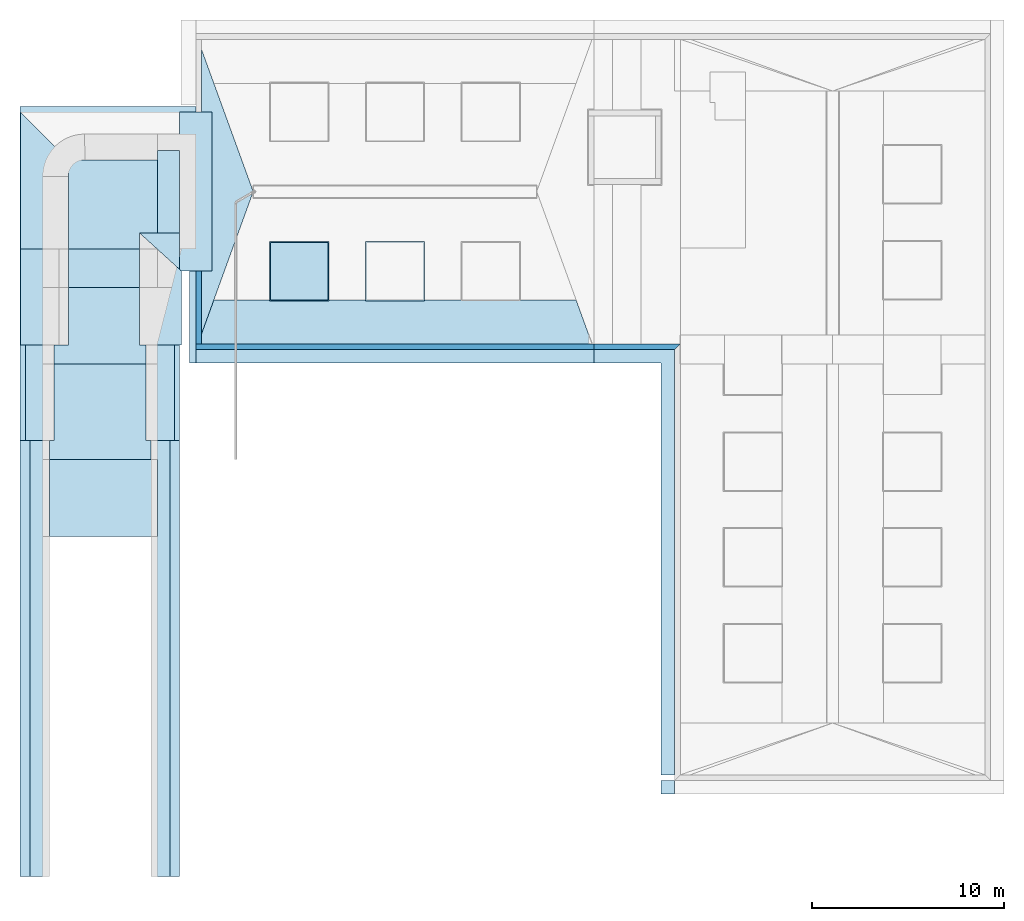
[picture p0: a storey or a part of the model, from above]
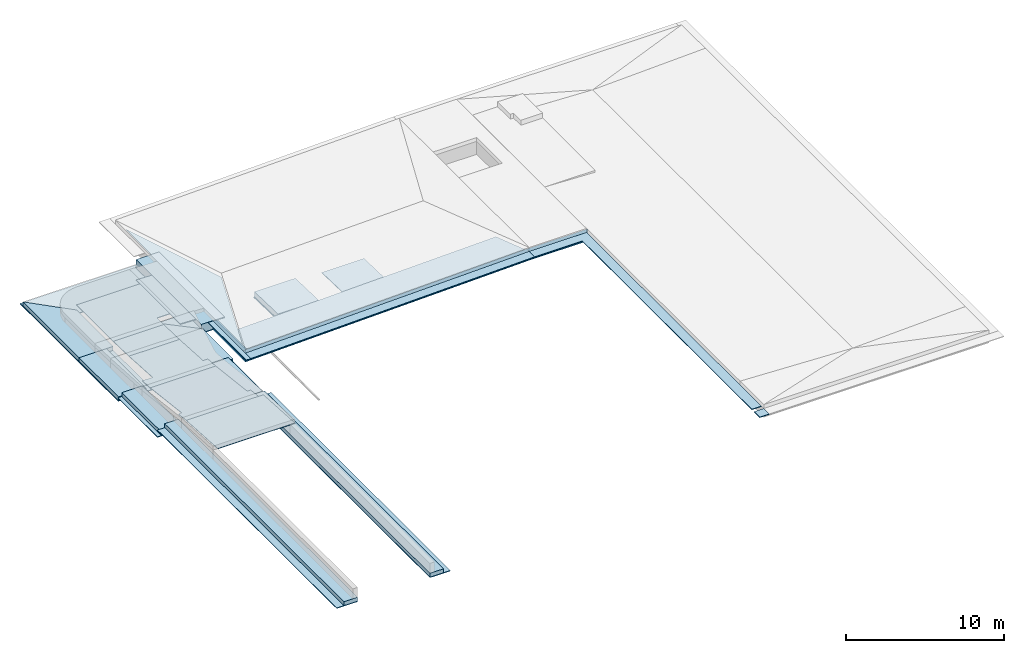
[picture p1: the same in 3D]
Properties of the parts of a building model (IFC4), part 1 of 8

# File
Description: ViewDefinition [, SurfaceGeometryAddOnView], ExchangeRequirement [Architecture], Option [Elements to export: Visible elements (on all stories)], Option [Partial Structure Display: Entire Model], Option [IFC Domain: All], Option [Structural Function: All Elements], Option [Convert Grid elements: On], Option [Convert IFC Annotations and Archicad 2D elements: Off], Option [Convert 2D symbols of Doors and Windows: Off], Option [Export geometries that Participates in Collision Detection only: Off], Option [Split complex elements: On], Option [IFC Model position: Project Origin only], Option [Curtain Wall export mode: Single Element], Option [Railing export mode: Single Element], Option [Stair export mode: Single Element], Option [Properties To Export: Current Scheme properties only], Option [Space containment: On], Option [IFC Domain For Space Containment: All], Option [Geometry to type objects: Off], Option [Element Properties: Visible Only], Option [Building Material Properties: On], Option [Element Parameters: Off], Option [Component Parameters: Off], Option [IFC Base Quantities: Off], Option [Door Window Parameters: Off], Option [IFC Space boundaries: Off], Option [Archicad Zone Categories as IFC Space classification data: Off], Option [Element Classifications: On]
File name: C:\Users\Fabienne\Desktop\Architektur Gebäudemodell__2026-02-03.ifc
Time: 2026-02-03T13:43:27
Author: Architect
Organization: Building Designer Office
Written by: DDS_IFC v3.0
Made in: Graphisoft - Archicad - 28.3.0
Authorization: The authorising person

# IfcSite, Gelände
RefLatitude: 47, 3, 30, 600000; RefLongitude: 8, 18, 39, 700000; RefElevation: 0 mm

# IfcBuildingStorey (7)
In: Gebäude
Name | Elevation (mm)
Fundation | -6000
UG | -3900
1.OG | 2900
EG | 0
2.OG | 5800
Attika | 8700
Dachaufsicht | 11600

# IfcBeam: Dachrand Typ 2 172 x 269 (3)
In: 2.OG
Classification: Träger Massivholz (BIM Base by Evolut); Material: Stahl (2), Vollholzwerkstoff
05_Bauablauf - Bau-Nr.: In Abklärung; Bauablauf Etappe: In Abklärung; Bauablauf Verbauungsort: In Abklärung; Bauablauf Start Ausführung: In Abklärung; Bauablauf Ende Ausführung: In Abklärung
03_Bausystem - Tragende Funktion: In Abklärung; Feuerwiderstand: In Abklärung; Umbau-Status: Neubau; Mehrschichtiger Aufbau: Stahl; Vollholzwerkstoff; Stahl
01_Leistungen und Kosten - Gebäude: In Abklärung; Elementpreis - CHF: 0; BKP: 214 - Montagebau in Holz; eBKP-H_Nr: C04; eBKP-H_Beschrieb: Deckenkonstrutkion, Dachkonstruktion
02_Mengen - Breite - m: 0.172423; Höhe - m: 0.269077; Kote Unterkante: 6.3; Kote Oberkante: 6.569
00_Datenstruktur - BIM Base Version: 4.0.0; Kundenergänzungen Version: v01; CAD Werkzeug Typ: Träger; Klassifizierung: Träger Massivholz; Klassifizierung Level 0: Träger; Modellierungsrichtlinien: https://evolutbaugmbh.sharepoint.com/:b:/s/External/EciBgBMJMZlDgYCafV5wNokBvCJq9PUJAyVGz7O3vsjVrg?e=aLjLN9; Übersicht BIM Base: https://evolutbaugmbh.sharepoint.com/:b:/s/External/EfS4mJ9nZQpOhASXp0n2kW4B0K7N-vHKx-_6Crp5CxEFeg?e=Qu0M5d; Verbesserungsvorschläge BIM Base: https://forms.office.com/e/pcFhFfi5DW; Anleitung Mengen: https://evolutbaugmbh.sharepoint.com/:b:/s/External/ETgyOLO3JxJEqg9rbaRMLVEBHuWIRtkoMiJN1fISDr-3lw?e=E0LTiQ; Anleitung Eigenschaften: https://evolutbaugmbh.sharepoint.com/:b:/s/External/EQedjNXQkc1Btaftc01yAPUBtND9QzXFSH3-7sie6PGFww?e=wP4uf3; Release Notes: https://evolutbaugmbh.sharepoint.com/:b:/s/External/Eb41lwlDI71MhUVvor2V2mUBSaI-0tQK5U9oJAWxpCINuw?e=NtK3j6
Bekleidung - Bekleidung Gipserarbeiten: In Abklärung; Bekleidung Malerarbeiten: In Abklärung; Bekleidung Putz: In Abklärung; Bekleidung Farbe: RAL / NCS
Name | Länge brutto - m = Länge netto - m | Volumen netto - m3
2 x Unterzug-028 | 3.8 | 0.16075
Unterzug-028 | 12.508 | 0.534861

# IfcBeam: Dreischichtplatte DSP 27 x 406, Unterzug-027
In: Dachaufsicht
Classification: Träger Massivholz (BIM Base by Evolut); Material: Dreischichtplatte DSP
01_Leistungen und Kosten - Gebäude: In Abklärung; Elementpreis - CHF: 0; BKP: 214 - Montagebau in Holz; eBKP-H_Nr: C04; eBKP-H_Beschrieb: Deckenkonstrutkion, Dachkonstruktion
05_Bauablauf - Bau-Nr.: In Abklärung; Bauablauf Etappe: In Abklärung; Bauablauf Verbauungsort: In Abklärung; Bauablauf Start Ausführung: In Abklärung; Bauablauf Ende Ausführung: In Abklärung
Bekleidung - Bekleidung Gipserarbeiten: In Abklärung; Bekleidung Malerarbeiten: In Abklärung; Bekleidung Putz: In Abklärung; Bekleidung Farbe: RAL / NCS
03_Bausystem - Tragende Funktion: In Abklärung; Feuerwiderstand: In Abklärung; Umbau-Status: Neubau; Mehrschichtiger Aufbau: Dreischichtplatte DSP
02_Mengen - Breite - m: 0.027; Höhe - m: 0.406; Länge brutto - m: 7.021; Länge netto - m: 7.021; Volumen netto - m3: 0.0769643; Kote Unterkante: 11.844; Kote Oberkante: 12.25
00_Datenstruktur - BIM Base Version: 4.0.0; Kundenergänzungen Version: v01; CAD Werkzeug Typ: Träger; Klassifizierung: Träger Massivholz; Klassifizierung Level 0: Träger; Modellierungsrichtlinien: https://evolutbaugmbh.sharepoint.com/:b:/s/External/EciBgBMJMZlDgYCafV5wNokBvCJq9PUJAyVGz7O3vsjVrg?e=aLjLN9; Übersicht BIM Base: https://evolutbaugmbh.sharepoint.com/:b:/s/External/EfS4mJ9nZQpOhASXp0n2kW4B0K7N-vHKx-_6Crp5CxEFeg?e=Qu0M5d; Verbesserungsvorschläge BIM Base: https://forms.office.com/e/pcFhFfi5DW; Anleitung Mengen: https://evolutbaugmbh.sharepoint.com/:b:/s/External/ETgyOLO3JxJEqg9rbaRMLVEBHuWIRtkoMiJN1fISDr-3lw?e=E0LTiQ; Anleitung Eigenschaften: https://evolutbaugmbh.sharepoint.com/:b:/s/External/EQedjNXQkc1Btaftc01yAPUBtND9QzXFSH3-7sie6PGFww?e=wP4uf3; Release Notes: https://evolutbaugmbh.sharepoint.com/:b:/s/External/Eb41lwlDI71MhUVvor2V2mUBSaI-0tQK5U9oJAWxpCINuw?e=NtK3j6

# IfcBeam: Massivholz 200 x 200 (25)
Classification: Träger Massivholz (BIM Base by Evolut); Material: Massivholz
01_Leistungen und Kosten - Gebäude: In Abklärung; Elementpreis - CHF: 0; BKP: 214 - Montagebau in Holz; eBKP-H_Nr: C04; eBKP-H_Beschrieb: Deckenkonstrutkion, Dachkonstruktion
05_Bauablauf - Bau-Nr.: In Abklärung; Bauablauf Etappe: In Abklärung; Bauablauf Verbauungsort: In Abklärung; Bauablauf Start Ausführung: In Abklärung; Bauablauf Ende Ausführung: In Abklärung
03_Bausystem - Tragende Funktion: In Abklärung; Feuerwiderstand: In Abklärung; Umbau-Status: Neubau; Mehrschichtiger Aufbau: Massivholz
Bekleidung - Bekleidung Gipserarbeiten: In Abklärung; Bekleidung Malerarbeiten: In Abklärung; Bekleidung Putz: In Abklärung; Bekleidung Farbe: RAL / NCS
00_Datenstruktur - BIM Base Version: 4.0.0; Kundenergänzungen Version: v01; CAD Werkzeug Typ: Träger; Klassifizierung: Träger Massivholz; Klassifizierung Level 0: Träger; Modellierungsrichtlinien: https://evolutbaugmbh.sharepoint.com/:b:/s/External/EciBgBMJMZlDgYCafV5wNokBvCJq9PUJAyVGz7O3vsjVrg?e=aLjLN9; Übersicht BIM Base: https://evolutbaugmbh.sharepoint.com/:b:/s/External/EfS4mJ9nZQpOhASXp0n2kW4B0K7N-vHKx-_6Crp5CxEFeg?e=Qu0M5d; Verbesserungsvorschläge BIM Base: https://forms.office.com/e/pcFhFfi5DW; Anleitung Mengen: https://evolutbaugmbh.sharepoint.com/:b:/s/External/ETgyOLO3JxJEqg9rbaRMLVEBHuWIRtkoMiJN1fISDr-3lw?e=E0LTiQ; Anleitung Eigenschaften: https://evolutbaugmbh.sharepoint.com/:b:/s/External/EQedjNXQkc1Btaftc01yAPUBtND9QzXFSH3-7sie6PGFww?e=wP4uf3; Release Notes: https://evolutbaugmbh.sharepoint.com/:b:/s/External/Eb41lwlDI71MhUVvor2V2mUBSaI-0tQK5U9oJAWxpCINuw?e=NtK3j6
02_Mengen - Breite - m: 0.2; Höhe - m: 0.2
Name | In | Länge brutto - m | Länge netto - m | Volumen netto - m3 | Kote Unterkante | Kote Oberkante
5 x Unterzug-027 | EG | 3.6 | 3.6 | 0.144 | 3.02 | 3.22
2 x Unterzug-027 | EG | 4 | 4 | 0.152 | 3.02 | 3.22
2 x Unterzug-027 | EG | 12.908 | 12.908 | 0.50832 | 3.02 | 3.22
2 x Unterzug-027 | 2.OG | 4 | 4 | 0.152 | 8.82 | 9.02
5 x Unterzug-027 | 2.OG | 3.6 | 3.6 | 0.144 | 8.82 | 9.02
2 x Unterzug-027 | 2.OG | 12.8974 | 12.8974 | 0.507897 | 8.82 | 9.02
Unterzug-027 | Attika | 19.2132 | 18.4132 | 0.736528 | 11.35 | 11.55
4 x Unterzug-027 | Attika | 5.11796 | 5.11796 | 0.204719 | 11.35 | 11.55
Unterzug-027 | Attika | 5.21 | 5.21 | 0.2044 | 11.35 | 11.55
Unterzug-027 | Attika | 19.4632 | 19.4632 | 0.757254 | 11.35 | 11.55

# IfcBeam: Massivholz 200 x 400 (5)
Classification: Träger Massivholz (BIM Base by Evolut); Material: Massivholz
05_Bauablauf - Bau-Nr.: In Abklärung; Bauablauf Etappe: In Abklärung; Bauablauf Verbauungsort: In Abklärung; Bauablauf Start Ausführung: In Abklärung; Bauablauf Ende Ausführung: In Abklärung
01_Leistungen und Kosten - Gebäude: In Abklärung; Elementpreis - CHF: 0; BKP: 214 - Montagebau in Holz; eBKP-H_Nr: C04; eBKP-H_Beschrieb: Deckenkonstrutkion, Dachkonstruktion
03_Bausystem - Tragende Funktion: In Abklärung; Feuerwiderstand: In Abklärung; Umbau-Status: Neubau; Mehrschichtiger Aufbau: Massivholz
Bekleidung - Bekleidung Gipserarbeiten: In Abklärung; Bekleidung Malerarbeiten: In Abklärung; Bekleidung Putz: In Abklärung; Bekleidung Farbe: RAL / NCS
00_Datenstruktur - BIM Base Version: 4.0.0; Kundenergänzungen Version: v01; CAD Werkzeug Typ: Träger; Klassifizierung: Träger Massivholz; Klassifizierung Level 0: Träger; Modellierungsrichtlinien: https://evolutbaugmbh.sharepoint.com/:b:/s/External/EciBgBMJMZlDgYCafV5wNokBvCJq9PUJAyVGz7O3vsjVrg?e=aLjLN9; Übersicht BIM Base: https://evolutbaugmbh.sharepoint.com/:b:/s/External/EfS4mJ9nZQpOhASXp0n2kW4B0K7N-vHKx-_6Crp5CxEFeg?e=Qu0M5d; Verbesserungsvorschläge BIM Base: https://forms.office.com/e/pcFhFfi5DW; Anleitung Mengen: https://evolutbaugmbh.sharepoint.com/:b:/s/External/ETgyOLO3JxJEqg9rbaRMLVEBHuWIRtkoMiJN1fISDr-3lw?e=E0LTiQ; Anleitung Eigenschaften: https://evolutbaugmbh.sharepoint.com/:b:/s/External/EQedjNXQkc1Btaftc01yAPUBtND9QzXFSH3-7sie6PGFww?e=wP4uf3; Release Notes: https://evolutbaugmbh.sharepoint.com/:b:/s/External/Eb41lwlDI71MhUVvor2V2mUBSaI-0tQK5U9oJAWxpCINuw?e=NtK3j6
02_Mengen - Breite - m: 0.2; Höhe - m: 0.4
Name | In | Länge brutto - m | Länge netto - m | Volumen netto - m3 | Kote Unterkante | Kote Oberkante
Unterzug-027 | Attika | 8.99307 | 8.99307 | 0.719446 | 11.444 | 11.844
Unterzug-027 | Dachaufsicht | 4.2 | 4.2 | 0.336 | 13.107 | 13.507
Unterzug-027 | Dachaufsicht | 7.93205 | 8.07763 | 0.62173 | 12.893 | 13.293
Unterzug-027 | Dachaufsicht | 4.2 | 4.2 | 0.327483 | 13.107 | 13.507
Unterzug-027 | Dachaufsicht | 7.93205 | 8.07763 | 0.630247 | 12.893 | 13.293

# IfcBeam: Massivholz 200 x 800, Unterzug-027
In: Dachaufsicht
Classification: Träger Massivholz (BIM Base by Evolut); Material: Massivholz
01_Leistungen und Kosten - Gebäude: In Abklärung; Elementpreis - CHF: 0; BKP: 214 - Montagebau in Holz; eBKP-H_Nr: C04; eBKP-H_Beschrieb: Deckenkonstrutkion, Dachkonstruktion
03_Bausystem - Tragende Funktion: In Abklärung; Feuerwiderstand: In Abklärung; Umbau-Status: Neubau; Mehrschichtiger Aufbau: Massivholz
Bekleidung - Bekleidung Gipserarbeiten: In Abklärung; Bekleidung Malerarbeiten: In Abklärung; Bekleidung Putz: In Abklärung; Bekleidung Farbe: RAL / NCS
05_Bauablauf - Bau-Nr.: In Abklärung; Bauablauf Etappe: In Abklärung; Bauablauf Verbauungsort: In Abklärung; Bauablauf Start Ausführung: In Abklärung; Bauablauf Ende Ausführung: In Abklärung
00_Datenstruktur - BIM Base Version: 4.0.0; Kundenergänzungen Version: v01; CAD Werkzeug Typ: Träger; Klassifizierung: Träger Massivholz; Klassifizierung Level 0: Träger; Modellierungsrichtlinien: https://evolutbaugmbh.sharepoint.com/:b:/s/External/EciBgBMJMZlDgYCafV5wNokBvCJq9PUJAyVGz7O3vsjVrg?e=aLjLN9; Übersicht BIM Base: https://evolutbaugmbh.sharepoint.com/:b:/s/External/EfS4mJ9nZQpOhASXp0n2kW4B0K7N-vHKx-_6Crp5CxEFeg?e=Qu0M5d; Verbesserungsvorschläge BIM Base: https://forms.office.com/e/pcFhFfi5DW; Anleitung Mengen: https://evolutbaugmbh.sharepoint.com/:b:/s/External/ETgyOLO3JxJEqg9rbaRMLVEBHuWIRtkoMiJN1fISDr-3lw?e=E0LTiQ; Anleitung Eigenschaften: https://evolutbaugmbh.sharepoint.com/:b:/s/External/EQedjNXQkc1Btaftc01yAPUBtND9QzXFSH3-7sie6PGFww?e=wP4uf3; Release Notes: https://evolutbaugmbh.sharepoint.com/:b:/s/External/Eb41lwlDI71MhUVvor2V2mUBSaI-0tQK5U9oJAWxpCINuw?e=NtK3j6
02_Mengen - Breite - m: 0.2; Höhe - m: 0.8; Länge brutto - m: 33.1; Länge netto - m: 33.264; Volumen netto - m3: 5.30744; Kote Unterkante: 15.004; Kote Oberkante: 15.804

# IfcBeam: Massivholz 21 x 150 (4)
In: Dachaufsicht
Classification: Träger Massivholz (BIM Base by Evolut); Material: Massivholz
05_Bauablauf - Bau-Nr.: In Abklärung; Bauablauf Etappe: In Abklärung; Bauablauf Verbauungsort: In Abklärung; Bauablauf Start Ausführung: In Abklärung; Bauablauf Ende Ausführung: In Abklärung
01_Leistungen und Kosten - Gebäude: In Abklärung; Elementpreis - CHF: 0; BKP: 214 - Montagebau in Holz; eBKP-H_Nr: C04; eBKP-H_Beschrieb: Deckenkonstrutkion, Dachkonstruktion
Bekleidung - Bekleidung Gipserarbeiten: In Abklärung; Bekleidung Malerarbeiten: In Abklärung; Bekleidung Putz: In Abklärung; Bekleidung Farbe: RAL / NCS
03_Bausystem - Tragende Funktion: In Abklärung; Feuerwiderstand: In Abklärung; Umbau-Status: Neubau; Mehrschichtiger Aufbau: Massivholz
02_Mengen - Breite - m: 0.021; Höhe - m: 0.15
00_Datenstruktur - BIM Base Version: 4.0.0; Kundenergänzungen Version: v01; CAD Werkzeug Typ: Träger; Klassifizierung: Träger Massivholz; Klassifizierung Level 0: Träger; Modellierungsrichtlinien: https://evolutbaugmbh.sharepoint.com/:b:/s/External/EciBgBMJMZlDgYCafV5wNokBvCJq9PUJAyVGz7O3vsjVrg?e=aLjLN9; Übersicht BIM Base: https://evolutbaugmbh.sharepoint.com/:b:/s/External/EfS4mJ9nZQpOhASXp0n2kW4B0K7N-vHKx-_6Crp5CxEFeg?e=Qu0M5d; Verbesserungsvorschläge BIM Base: https://forms.office.com/e/pcFhFfi5DW; Anleitung Mengen: https://evolutbaugmbh.sharepoint.com/:b:/s/External/ETgyOLO3JxJEqg9rbaRMLVEBHuWIRtkoMiJN1fISDr-3lw?e=E0LTiQ; Anleitung Eigenschaften: https://evolutbaugmbh.sharepoint.com/:b:/s/External/EQedjNXQkc1Btaftc01yAPUBtND9QzXFSH3-7sie6PGFww?e=wP4uf3; Release Notes: https://evolutbaugmbh.sharepoint.com/:b:/s/External/Eb41lwlDI71MhUVvor2V2mUBSaI-0tQK5U9oJAWxpCINuw?e=NtK3j6
Name | Länge brutto - m | Länge netto - m | Volumen netto - m3 | Kote Unterkante | Kote Oberkante
3 x Unterzug-027 | 8.68662 | 8.74122 | 0.0273629 | 13.06 | 13.21
Unterzug-027 | 6.07832 | 6.13292 | 0.0191467 | 13.952 | 14.102

# IfcBeam: Massivholz 21 x 160 (3)
In: Dachaufsicht
Classification: Träger Massivholz (BIM Base by Evolut); Material: Massivholz
01_Leistungen und Kosten - Gebäude: In Abklärung; Elementpreis - CHF: 0; BKP: 214 - Montagebau in Holz; eBKP-H_Nr: C04; eBKP-H_Beschrieb: Deckenkonstrutkion, Dachkonstruktion
05_Bauablauf - Bau-Nr.: In Abklärung; Bauablauf Etappe: In Abklärung; Bauablauf Verbauungsort: In Abklärung; Bauablauf Start Ausführung: In Abklärung; Bauablauf Ende Ausführung: In Abklärung
03_Bausystem - Tragende Funktion: In Abklärung; Feuerwiderstand: In Abklärung; Umbau-Status: Neubau; Mehrschichtiger Aufbau: Massivholz
02_Mengen - Breite - m: 0.021; Höhe - m: 0.16
Bekleidung - Bekleidung Gipserarbeiten: In Abklärung; Bekleidung Malerarbeiten: In Abklärung; Bekleidung Putz: In Abklärung; Bekleidung Farbe: RAL / NCS
00_Datenstruktur - BIM Base Version: 4.0.0; Kundenergänzungen Version: v01; CAD Werkzeug Typ: Träger; Klassifizierung: Träger Massivholz; Klassifizierung Level 0: Träger; Modellierungsrichtlinien: https://evolutbaugmbh.sharepoint.com/:b:/s/External/EciBgBMJMZlDgYCafV5wNokBvCJq9PUJAyVGz7O3vsjVrg?e=aLjLN9; Übersicht BIM Base: https://evolutbaugmbh.sharepoint.com/:b:/s/External/EfS4mJ9nZQpOhASXp0n2kW4B0K7N-vHKx-_6Crp5CxEFeg?e=Qu0M5d; Verbesserungsvorschläge BIM Base: https://forms.office.com/e/pcFhFfi5DW; Anleitung Mengen: https://evolutbaugmbh.sharepoint.com/:b:/s/External/ETgyOLO3JxJEqg9rbaRMLVEBHuWIRtkoMiJN1fISDr-3lw?e=E0LTiQ; Anleitung Eigenschaften: https://evolutbaugmbh.sharepoint.com/:b:/s/External/EQedjNXQkc1Btaftc01yAPUBtND9QzXFSH3-7sie6PGFww?e=wP4uf3; Release Notes: https://evolutbaugmbh.sharepoint.com/:b:/s/External/Eb41lwlDI71MhUVvor2V2mUBSaI-0tQK5U9oJAWxpCINuw?e=NtK3j6
Name | Länge brutto - m = Länge netto - m | Volumen netto - m3 | Kote Unterkante | Kote Oberkante
Unterzug-027 | 9.911 | 0.033301 | 13.952 | 14.112
Unterzug-027 | 24.271 | 0.0815506 | 13.06 | 13.22
Unterzug-027 | 34.182 | 0.114852 | 13.06 | 13.22

# IfcBuildingElementPart (1315)
Name | In | Material
Lattenrost vertikal | UG | Lattenrost vertikal
2 x Gipskartonplatte GKP | UG | Gipskartonplatte GKP
17 x Anstrich Innen | UG | Anstrich Innen
70 x Beton bewehrt | UG | Beton bewehrt
3 x Kalkzementputz Aussen | UG | Kalkzementputz Aussen
16 x Sichtbeton | UG | Sichtbeton
7 x Lattenrost vertikal | EG | Lattenrost vertikal
6 x Lattenrost horizontal | EG | Lattenrost horizontal
6 x Falzschalung vertikal | EG | Falzschalung vertikal
7 x Dämmung Aussen | EG | Dämmung Aussen
7 x Zementputz Aussen | EG | Zementputz Aussen
4 x Verputz Innen | EG | Verputz Innen
12 x Gipsfaserplatte GFP | EG | Gipsfaserplatte GFP
9 x Ständer Konstruktion gedämmt | EG | Ständer Konstruktion gedämmt
8 x Grobspanplatte-OSB | EG | Grobspanplatte-OSB
9 x Sichtbeton | EG | Sichtbeton
14 x Beton bewehrt | EG | Beton bewehrt
7 x Kalkzementputz Aussen | EG | Kalkzementputz Aussen
Anstrich Innen | EG | Anstrich Innen
4 x Dämmung Innen | EG | Dämmung Innen
6 x Gipskartonplatte GKP | EG | Gipskartonplatte GKP
2 x Balken Konstruktion ungedämmt | EG | Balken Konstruktion ungedämmt
2 x Balken Konstruktion gedämmt | EG | Balken Konstruktion gedämmt
2 x Dreischichtplatte DSP | EG | Dreischichtplatte DSP
5 x  | EG
2 x Bodenbelag | EG | Bodenbelag
2 x Unterlagsboden | EG | Unterlagsboden
5 x Sperrschicht | EG | Sperrschicht
Stahl | EG | Stahl
17 x Massivholz | EG | Massivholz
3 x Keramik | EG | Keramik
3 x Grünfläche | EG | Grünfläche
8 x Falzschalung vertikal | 1.OG | Falzschalung vertikal
8 x Lattenrost horizontal | 1.OG | Lattenrost horizontal
24 x Ständer Konstruktion gedämmt | 1.OG | Ständer Konstruktion gedämmt
2 x Dreischichtplatte DSP | 1.OG | Dreischichtplatte DSP
8 x Lattenrost vertikal | 1.OG | Lattenrost vertikal
20 x Dämmung Innen | 1.OG | Dämmung Innen
22 x Gipsfaserplatte GFP | 1.OG | Gipsfaserplatte GFP
24 x Gipskartonplatte GKP | 1.OG | Gipskartonplatte GKP
50 x Kalkzementputz Aussen | 1.OG | Kalkzementputz Aussen
21 x MW, Backstein | 1.OG | MW, Backstein
7 x Dämmung Aussen | 1.OG | Dämmung Aussen
7 x Zementputz Aussen | 1.OG | Zementputz Aussen
9 x Verputz Innen | 1.OG | Verputz Innen
13 x Grobspanplatte-OSB | 1.OG | Grobspanplatte-OSB
9 x Sichtbeton | 1.OG | Sichtbeton
16 x Beton bewehrt | 1.OG | Beton bewehrt
2 x Balken Konstruktion ungedämmt | 1.OG | Balken Konstruktion ungedämmt
2 x Balken Konstruktion gedämmt | 1.OG | Balken Konstruktion gedämmt
2 x Keramik | 1.OG | Keramik
4 x Unterlagsboden | 1.OG | Unterlagsboden
4 x Trittschalldämmung | 1.OG | Trittschalldämmung
 | 1.OG
2 x Bodenbelag | 1.OG | Bodenbelag
Stahl | 1.OG | Stahl
17 x Massivholz | 1.OG | Massivholz
6 x Falzschalung vertikal | 2.OG | Falzschalung vertikal
6 x Lattenrost horizontal | 2.OG | Lattenrost horizontal
7 x Lattenrost vertikal | 2.OG | Lattenrost vertikal
22 x Ständer Konstruktion gedämmt | 2.OG | Ständer Konstruktion gedämmt
30 x Gipskartonplatte GKP | 2.OG | Gipskartonplatte GKP
51 x Kalkzementputz Aussen | 2.OG | Kalkzementputz Aussen
9 x Grobspanplatte-OSB | 2.OG | Grobspanplatte-OSB
2 x Balken Konstruktion ungedämmt | 2.OG | Balken Konstruktion ungedämmt
2 x Balken Konstruktion gedämmt | 2.OG | Balken Konstruktion gedämmt
7 x Zementputz Aussen | 2.OG | Zementputz Aussen
8 x Dämmung Aussen | 2.OG | Dämmung Aussen
21 x MW, Backstein | 2.OG | MW, Backstein
2 x Dreischichtplatte DSP | 2.OG | Dreischichtplatte DSP
14 x Gipsfaserplatte GFP | 2.OG | Gipsfaserplatte GFP
21 x Dämmung Innen | 2.OG | Dämmung Innen
5 x Verputz Innen | 2.OG | Verputz Innen
9 x Sichtbeton | 2.OG | Sichtbeton
15 x Beton bewehrt | 2.OG | Beton bewehrt
33 x Keramik | 2.OG | Keramik
5 x Unterlagsboden | 2.OG | Unterlagsboden
5 x Trittschalldämmung | 2.OG | Trittschalldämmung
 | 2.OG
4 x Bodenbelag | 2.OG | Bodenbelag
Stahl | 2.OG | Stahl
17 x Massivholz | 2.OG | Massivholz
Sperrschicht | 2.OG | Sperrschicht
3 x Dachbegrünung extensiv | Attika | Dachbegrünung extensiv
3 x Abdichtung Bitumen | Attika | Abdichtung Bitumen
3 x Aufdachdämmung | Attika | Aufdachdämmung
3 x Dampf- / Luftdichtigkeitsschicht | Attika | Dampf- / Luftdichtigkeitsschicht
7 x Falzschalung vertikal | Attika | Falzschalung vertikal
7 x Lattenrost horizontal | Attika | Lattenrost horizontal
13 x Lattenrost vertikal | Attika | Lattenrost vertikal
3 x Gefällsdämmung | Attika | Gefällsdämmung
10 x Verputz Innen | Attika | Verputz Innen
20 x Gipsfaserplatte GFP | Attika | Gipsfaserplatte GFP
21 x Ständer Konstruktion gedämmt | Attika | Ständer Konstruktion gedämmt
20 x Grobspanplatte-OSB | Attika | Grobspanplatte-OSB
13 x Dämmung Innen | Attika | Dämmung Innen
16 x MW, Backstein | Attika | MW, Backstein
36 x Kalkzementputz Aussen | Attika | Kalkzementputz Aussen
12 x Beton bewehrt | Attika | Beton bewehrt
7 x Sichtbeton | Attika | Sichtbeton
16 x Gipskartonplatte GKP | Attika | Gipskartonplatte GKP
5 x Bodenbelag | Attika | Bodenbelag
6 x Unterlagsboden | Attika | Unterlagsboden
5 x Trittschalldämmung | Attika | Trittschalldämmung
8 x Zementputz Aussen | Attika | Zementputz Aussen
10 x Dämmung Aussen | Attika | Dämmung Aussen
2 x Balken Konstruktion ungedämmt | Attika | Balken Konstruktion ungedämmt
2 x Balken Konstruktion gedämmt | Attika | Balken Konstruktion gedämmt
6 x Falzschalung horizontal | Attika | Falzschalung horizontal
Sperrschicht | Attika | Sperrschicht
2 x  | Attika
17 x Vollholzwerkstoff | Attika | Vollholzwerkstoff
23 x Stahl | Attika | Stahl
2 x Keramik | Attika | Keramik
14 x Grobspanplatte-OSB | Dachaufsicht | Grobspanplatte-OSB
15 x Ständer Konstruktion gedämmt | Dachaufsicht | Ständer Konstruktion gedämmt
28 x Gipsfaserplatte GFP | Dachaufsicht | Gipsfaserplatte GFP
14 x Verputz Innen | Dachaufsicht | Verputz Innen
13 x Falzschalung vertikal | Dachaufsicht | Falzschalung vertikal
17 x Lattenrost vertikal | Dachaufsicht | Lattenrost vertikal
13 x Lattenrost horizontal | Dachaufsicht | Lattenrost horizontal
4 x Dachziegel grau | Dachaufsicht | Dachziegel grau
4 x Aufdachdämmung | Dachaufsicht | Aufdachdämmung
6 x Dreischichtplatte-DSP | Dachaufsicht | Dreischichtplatte-DSP
6 x Balken Konstruktion gedämmt | Dachaufsicht | Balken Konstruktion gedämmt
12 x Gipskartonplatte GKP | Dachaufsicht | Gipskartonplatte GKP
6 x Kalkzementputz Aussen | Dachaufsicht | Kalkzementputz Aussen
Bodenbelag | Dachaufsicht | Bodenbelag
Unterlagsboden | Dachaufsicht | Unterlagsboden
Trittschalldämmung | Dachaufsicht | Trittschalldämmung
Dämmung Innen | Dachaufsicht | Dämmung Innen
2 x Dreischichtplatte DSP | Dachaufsicht | Dreischichtplatte DSP
8 x Stahl | Dachaufsicht | Stahl

# IfcBuildingElementProxy: Evolut_Referenzpunkt_BIM Base_v4.0.7 (3)
In: EG
Description: D9.1; Classification: Referenzpunkt (BIM Base by Evolut)
01_Leistungen und Kosten - Gebäude: In Abklärung
Georeferenzierung - X Koordinaten - m: In Abklärung; Y Koordinaten - m: In Abklärung; Z Koordinaten - m: In Abklärung
00_Datenstruktur - BIM Base Version: 4.0.0; Kundenergänzungen Version: v01; CAD Werkzeug Typ: Objekt; Klassifizierung: Referenzpunkt; Klassifizierung Level 0: Referenzpunkt; Modellierungsrichtlinien: https://evolutbaugmbh.sharepoint.com/:b:/s/External/EciBgBMJMZlDgYCafV5wNokBvCJq9PUJAyVGz7O3vsjVrg?e=aLjLN9; Übersicht BIM Base: https://evolutbaugmbh.sharepoint.com/:b:/s/External/EfS4mJ9nZQpOhASXp0n2kW4B0K7N-vHKx-_6Crp5CxEFeg?e=Qu0M5d; Verbesserungsvorschläge BIM Base: https://forms.office.com/e/pcFhFfi5DW; Anleitung Mengen: https://evolutbaugmbh.sharepoint.com/:b:/s/External/ETgyOLO3JxJEqg9rbaRMLVEBHuWIRtkoMiJN1fISDr-3lw?e=E0LTiQ; Anleitung Eigenschaften: https://evolutbaugmbh.sharepoint.com/:b:/s/External/EQedjNXQkc1Btaftc01yAPUBtND9QzXFSH3-7sie6PGFww?e=wP4uf3; Release Notes: https://evolutbaugmbh.sharepoint.com/:b:/s/External/Eb41lwlDI71MhUVvor2V2mUBSaI-0tQK5U9oJAWxpCINuw?e=NtK3j6
02_Mengen - Breite - m: 1; Höhe - m: 2
Name | Kote Unterkante | Kote Oberkante
Kontrollpunkt_3613 | 0 | 2
Einfügepunkt_32084866 | -1.035 | 0.965
Kontrollpunkt_4497 | 0 | 2

# IfcBuildingElementProxy: Rechteckige Türöffnung 27, Türzarge Typ 01
In: Attika
Classification: Öffnung (BIM Base by Evolut)
01_Leistungen und Kosten - Gebäude: In Abklärung; Elementpreis - CHF: 0; eBKP-H_Nr: C05.01; eBKP-H_Beschrieb: Durchbruch, Schlitz zu Konstruktion
03_Bausystem - Umbau-Status: Neubau
02_Mengen - Breite - m: 1.1; Breite Lichtmass - m: 1.1; Höhe Lichtmass - m: 2.1; Fläche Lichtmass - m2: 2.31; Höhe Mauerlicht - m: 2.1; Breite Mauerlicht - m: 1.1; Fläche Mauerlicht - m2: 2.31; Delta Höhe unten - m: 0; Delta Hohe oben - m: 0; Wandstärke - m: 0.318; Kote Unterkante: 9.32; Kote Oberkante: 11.42
00_Datenstruktur - BIM Base Version: 4.0.0; Kundenergänzungen Version: v01; CAD Werkzeug Typ: Tür; Klassifizierung: Öffnung; Klassifizierung Level 0: Öffnung; Modellierungsrichtlinien: https://evolutbaugmbh.sharepoint.com/:b:/s/External/EciBgBMJMZlDgYCafV5wNokBvCJq9PUJAyVGz7O3vsjVrg?e=aLjLN9; Übersicht BIM Base: https://evolutbaugmbh.sharepoint.com/:b:/s/External/EfS4mJ9nZQpOhASXp0n2kW4B0K7N-vHKx-_6Crp5CxEFeg?e=Qu0M5d; Verbesserungsvorschläge BIM Base: https://forms.office.com/e/pcFhFfi5DW; Anleitung Mengen: https://evolutbaugmbh.sharepoint.com/:b:/s/External/ETgyOLO3JxJEqg9rbaRMLVEBHuWIRtkoMiJN1fISDr-3lw?e=E0LTiQ; Anleitung Eigenschaften: https://evolutbaugmbh.sharepoint.com/:b:/s/External/EQedjNXQkc1Btaftc01yAPUBtND9QzXFSH3-7sie6PGFww?e=wP4uf3; Release Notes: https://evolutbaugmbh.sharepoint.com/:b:/s/External/Eb41lwlDI71MhUVvor2V2mUBSaI-0tQK5U9oJAWxpCINuw?e=NtK3j6

# IfcColumn: Massivholz 200 x 200 (10)
Classification: Aussenstütze Massivholz (BIM Base by Evolut); Material: Massivholz
01_Leistungen und Kosten - Gebäude: In Abklärung; Elementpreis - CHF: 0; BKP: 214 - Montagebau in Holz; eBKP-H_Nr: C03.01; eBKP-H_Beschrieb: Aussenstütze
05_Bauablauf - Bau-Nr.: In Abklärung; Bauablauf Etappe: In Abklärung; Bauablauf Verbauungsort: In Abklärung; Bauablauf Start Ausführung: In Abklärung; Bauablauf Ende Ausführung: In Abklärung
03_Bausystem - Tragende Funktion: In Abklärung; Feuerwiderstand: In Abklärung; Umbau-Status: Neubau; Mehrschichtiger Aufbau: Massivholz
Bekleidung - Bekleidung Malerarbeiten: In Abklärung
Holzbau - Holzbau Durchstanzung: In Abklärung
02_Mengen - Breite - m: 0.2; Höhe - m: 0.2
00_Datenstruktur - BIM Base Version: 4.0.0; Kundenergänzungen Version: v01; CAD Werkzeug Typ: Stütze; Klassifizierung: Aussenstütze Massivholz; Klassifizierung Level 0: Stütze; Modellierungsrichtlinien: https://evolutbaugmbh.sharepoint.com/:b:/s/External/EciBgBMJMZlDgYCafV5wNokBvCJq9PUJAyVGz7O3vsjVrg?e=aLjLN9; Übersicht BIM Base: https://evolutbaugmbh.sharepoint.com/:b:/s/External/EfS4mJ9nZQpOhASXp0n2kW4B0K7N-vHKx-_6Crp5CxEFeg?e=Qu0M5d; Verbesserungsvorschläge BIM Base: https://forms.office.com/e/pcFhFfi5DW; Anleitung Mengen: https://evolutbaugmbh.sharepoint.com/:b:/s/External/ETgyOLO3JxJEqg9rbaRMLVEBHuWIRtkoMiJN1fISDr-3lw?e=E0LTiQ; Anleitung Eigenschaften: https://evolutbaugmbh.sharepoint.com/:b:/s/External/EQedjNXQkc1Btaftc01yAPUBtND9QzXFSH3-7sie6PGFww?e=wP4uf3; Release Notes: https://evolutbaugmbh.sharepoint.com/:b:/s/External/Eb41lwlDI71MhUVvor2V2mUBSaI-0tQK5U9oJAWxpCINuw?e=NtK3j6
Name | In | Länge brutto - m | Länge netto - m | Volumen netto - m3 | Kote Unterkante | Kote Oberkante
4 x Stütze-015 | EG | 2.52 | 3.70524 | 0.141866 | 0.5 | 3.02
2 x Stütze-015 | EG | 2.52 | 2.52 | 0.1008 | 0.5 | 3.02
2 x Stütze-015 | 2.OG | 2.52 | 2.52 | 0.1008 | 6.3 | 8.82
2 x Stütze-015 | Attika | 3.90655 | 3.90402 | 0.156161 | 9.2 | 13.107

# IfcColumn: Verschiedene Strukturen - 3 Segmente - 300 x 300 x 2150 (30+2090+30) (5)
In: Attika
Classification: Aussenstütze Stahl (BIM Base by Evolut); Material: Stahl (3)
01_Leistungen und Kosten - Gebäude: In Abklärung; Elementpreis - CHF: 0; BKP: 213 - Montagebau in Stahl; eBKP-H_Nr: C03.01; eBKP-H_Beschrieb: Aussenstütze
05_Bauablauf - Bau-Nr.: In Abklärung; Bauablauf Etappe: In Abklärung; Bauablauf Verbauungsort: In Abklärung; Bauablauf Start Ausführung: In Abklärung; Bauablauf Ende Ausführung: In Abklärung
Bekleidung - Bekleidung Malerarbeiten: In Abklärung
03_Bausystem - Tragende Funktion: In Abklärung; Feuerwiderstand: In Abklärung; Umbau-Status: Neubau; Mehrschichtiger Aufbau: Stahl; Stahl; Stahl
02_Mengen - Breite - m: 0.3; Höhe - m: 0.3; Länge brutto - m: 2.15; Länge netto - m: 2.15; Volumen netto - m3: 0.0130996; Kote Unterkante: 9.2; Kote Oberkante: 11.35
00_Datenstruktur - BIM Base Version: 4.0.0; Kundenergänzungen Version: v01; CAD Werkzeug Typ: Stütze; Klassifizierung: Aussenstütze Stahl; Klassifizierung Level 0: Stütze; Modellierungsrichtlinien: https://evolutbaugmbh.sharepoint.com/:b:/s/External/EciBgBMJMZlDgYCafV5wNokBvCJq9PUJAyVGz7O3vsjVrg?e=aLjLN9; Übersicht BIM Base: https://evolutbaugmbh.sharepoint.com/:b:/s/External/EfS4mJ9nZQpOhASXp0n2kW4B0K7N-vHKx-_6Crp5CxEFeg?e=Qu0M5d; Verbesserungsvorschläge BIM Base: https://forms.office.com/e/pcFhFfi5DW; Anleitung Mengen: https://evolutbaugmbh.sharepoint.com/:b:/s/External/ETgyOLO3JxJEqg9rbaRMLVEBHuWIRtkoMiJN1fISDr-3lw?e=E0LTiQ; Anleitung Eigenschaften: https://evolutbaugmbh.sharepoint.com/:b:/s/External/EQedjNXQkc1Btaftc01yAPUBtND9QzXFSH3-7sie6PGFww?e=wP4uf3; Release Notes: https://evolutbaugmbh.sharepoint.com/:b:/s/External/Eb41lwlDI71MhUVvor2V2mUBSaI-0tQK5U9oJAWxpCINuw?e=NtK3j6

# IfcColumn: Verschiedene Strukturen - 3 Segmente - 300 x 300 x 2650 (30+2590+30) (7)
Classification: Aussenstütze Stahl (BIM Base by Evolut); Material: Stahl (3)
01_Leistungen und Kosten - Gebäude: In Abklärung; Elementpreis - CHF: 0; BKP: 213 - Montagebau in Stahl; eBKP-H_Nr: C03.01; eBKP-H_Beschrieb: Aussenstütze
05_Bauablauf - Bau-Nr.: In Abklärung; Bauablauf Etappe: In Abklärung; Bauablauf Verbauungsort: In Abklärung; Bauablauf Start Ausführung: In Abklärung; Bauablauf Ende Ausführung: In Abklärung
03_Bausystem - Tragende Funktion: In Abklärung; Feuerwiderstand: In Abklärung; Umbau-Status: Neubau; Mehrschichtiger Aufbau: Stahl; Stahl; Stahl
Bekleidung - Bekleidung Malerarbeiten: In Abklärung
02_Mengen - Breite - m: 0.3; Höhe - m: 0.3; Länge brutto - m: 2.65; Länge netto - m: 2.65; Volumen netto - m3: 0.0149416
00_Datenstruktur - BIM Base Version: 4.0.0; Kundenergänzungen Version: v01; CAD Werkzeug Typ: Stütze; Klassifizierung: Aussenstütze Stahl; Klassifizierung Level 0: Stütze; Modellierungsrichtlinien: https://evolutbaugmbh.sharepoint.com/:b:/s/External/EciBgBMJMZlDgYCafV5wNokBvCJq9PUJAyVGz7O3vsjVrg?e=aLjLN9; Übersicht BIM Base: https://evolutbaugmbh.sharepoint.com/:b:/s/External/EfS4mJ9nZQpOhASXp0n2kW4B0K7N-vHKx-_6Crp5CxEFeg?e=Qu0M5d; Verbesserungsvorschläge BIM Base: https://forms.office.com/e/pcFhFfi5DW; Anleitung Mengen: https://evolutbaugmbh.sharepoint.com/:b:/s/External/ETgyOLO3JxJEqg9rbaRMLVEBHuWIRtkoMiJN1fISDr-3lw?e=E0LTiQ; Anleitung Eigenschaften: https://evolutbaugmbh.sharepoint.com/:b:/s/External/EQedjNXQkc1Btaftc01yAPUBtND9QzXFSH3-7sie6PGFww?e=wP4uf3; Release Notes: https://evolutbaugmbh.sharepoint.com/:b:/s/External/Eb41lwlDI71MhUVvor2V2mUBSaI-0tQK5U9oJAWxpCINuw?e=NtK3j6
Name | In | Kote Unterkante | Kote Oberkante
4 x Stütze-015 | 1.OG | 2.9 | 5.55
3 x Stütze-015 | 2.OG | 5.8 | 8.45

# IfcColumn: Verschiedene Strukturen - 3 Segmente - 300 x 300 x 2680 (30+2620+30) (4)
Classification: Aussenstütze Stahl (BIM Base by Evolut); Material: Stahl (3)
01_Leistungen und Kosten - Gebäude: In Abklärung; Elementpreis - CHF: 0; BKP: 213 - Montagebau in Stahl; eBKP-H_Nr: C03.01; eBKP-H_Beschrieb: Aussenstütze
05_Bauablauf - Bau-Nr.: In Abklärung; Bauablauf Etappe: In Abklärung; Bauablauf Verbauungsort: In Abklärung; Bauablauf Start Ausführung: In Abklärung; Bauablauf Ende Ausführung: In Abklärung
Bekleidung - Bekleidung Malerarbeiten: In Abklärung
00_Datenstruktur - BIM Base Version: 4.0.0; Kundenergänzungen Version: v01; CAD Werkzeug Typ: Stütze; Klassifizierung: Aussenstütze Stahl; Klassifizierung Level 0: Stütze; Modellierungsrichtlinien: https://evolutbaugmbh.sharepoint.com/:b:/s/External/EciBgBMJMZlDgYCafV5wNokBvCJq9PUJAyVGz7O3vsjVrg?e=aLjLN9; Übersicht BIM Base: https://evolutbaugmbh.sharepoint.com/:b:/s/External/EfS4mJ9nZQpOhASXp0n2kW4B0K7N-vHKx-_6Crp5CxEFeg?e=Qu0M5d; Verbesserungsvorschläge BIM Base: https://forms.office.com/e/pcFhFfi5DW; Anleitung Mengen: https://evolutbaugmbh.sharepoint.com/:b:/s/External/ETgyOLO3JxJEqg9rbaRMLVEBHuWIRtkoMiJN1fISDr-3lw?e=E0LTiQ; Anleitung Eigenschaften: https://evolutbaugmbh.sharepoint.com/:b:/s/External/EQedjNXQkc1Btaftc01yAPUBtND9QzXFSH3-7sie6PGFww?e=wP4uf3; Release Notes: https://evolutbaugmbh.sharepoint.com/:b:/s/External/Eb41lwlDI71MhUVvor2V2mUBSaI-0tQK5U9oJAWxpCINuw?e=NtK3j6
02_Mengen - Breite - m: 0.3; Höhe - m: 0.3; Länge brutto - m: 2.68; Länge netto - m: 2.68; Volumen netto - m3: 0.0150521
03_Bausystem - Tragende Funktion: In Abklärung; Feuerwiderstand: In Abklärung; Umbau-Status: Neubau; Mehrschichtiger Aufbau: Stahl; Stahl; Stahl
Name | In | Kote Unterkante | Kote Oberkante
2 x Stütze-015 | 1.OG | 2.87 | 5.55
2 x Stütze-015 | 2.OG | 5.77 | 8.45

# IfcColumn: Verschiedene Strukturen - 3 Segmente - 300 x 300 x 3150 (30+3090+30) (5)
In: EG
Classification: Aussenstütze Stahl (BIM Base by Evolut); Material: Stahl (3)
01_Leistungen und Kosten - Gebäude: In Abklärung; Elementpreis - CHF: 0; BKP: 213 - Montagebau in Stahl; eBKP-H_Nr: C03.01; eBKP-H_Beschrieb: Aussenstütze
05_Bauablauf - Bau-Nr.: In Abklärung; Bauablauf Etappe: In Abklärung; Bauablauf Verbauungsort: In Abklärung; Bauablauf Start Ausführung: In Abklärung; Bauablauf Ende Ausführung: In Abklärung
03_Bausystem - Tragende Funktion: In Abklärung; Feuerwiderstand: In Abklärung; Umbau-Status: Neubau; Mehrschichtiger Aufbau: Stahl; Stahl; Stahl
Bekleidung - Bekleidung Malerarbeiten: In Abklärung
02_Mengen - Breite - m: 0.3; Höhe - m: 0.3; Länge brutto - m: 3.15; Länge netto - m: 3.15; Volumen netto - m3: 0.0167836; Kote Unterkante: -0.5; Kote Oberkante: 2.65
00_Datenstruktur - BIM Base Version: 4.0.0; Kundenergänzungen Version: v01; CAD Werkzeug Typ: Stütze; Klassifizierung: Aussenstütze Stahl; Klassifizierung Level 0: Stütze; Modellierungsrichtlinien: https://evolutbaugmbh.sharepoint.com/:b:/s/External/EciBgBMJMZlDgYCafV5wNokBvCJq9PUJAyVGz7O3vsjVrg?e=aLjLN9; Übersicht BIM Base: https://evolutbaugmbh.sharepoint.com/:b:/s/External/EfS4mJ9nZQpOhASXp0n2kW4B0K7N-vHKx-_6Crp5CxEFeg?e=Qu0M5d; Verbesserungsvorschläge BIM Base: https://forms.office.com/e/pcFhFfi5DW; Anleitung Mengen: https://evolutbaugmbh.sharepoint.com/:b:/s/External/ETgyOLO3JxJEqg9rbaRMLVEBHuWIRtkoMiJN1fISDr-3lw?e=E0LTiQ; Anleitung Eigenschaften: https://evolutbaugmbh.sharepoint.com/:b:/s/External/EQedjNXQkc1Btaftc01yAPUBtND9QzXFSH3-7sie6PGFww?e=wP4uf3; Release Notes: https://evolutbaugmbh.sharepoint.com/:b:/s/External/Eb41lwlDI71MhUVvor2V2mUBSaI-0tQK5U9oJAWxpCINuw?e=NtK3j6

# IfcColumn: Verschiedene Strukturen - 3 Segmente - 300 x 300 x 3400 (30+3340+30), Stütze-015
In: EG
Classification: Aussenstütze Stahl (BIM Base by Evolut); Material: Stahl (3)
05_Bauablauf - Bau-Nr.: In Abklärung; Bauablauf Etappe: In Abklärung; Bauablauf Verbauungsort: In Abklärung; Bauablauf Start Ausführung: In Abklärung; Bauablauf Ende Ausführung: In Abklärung
03_Bausystem - Tragende Funktion: In Abklärung; Feuerwiderstand: In Abklärung; Umbau-Status: Neubau; Mehrschichtiger Aufbau: Stahl; Stahl; Stahl
Bekleidung - Bekleidung Malerarbeiten: In Abklärung
02_Mengen - Breite - m: 0.3; Höhe - m: 0.3; Länge brutto - m: 3.4; Länge netto - m: 3.4; Volumen netto - m3: 0.0177046; Kote Unterkante: -0.5; Kote Oberkante: 2.9
00_Datenstruktur - BIM Base Version: 4.0.0; Kundenergänzungen Version: v01; CAD Werkzeug Typ: Stütze; Klassifizierung: Aussenstütze Stahl; Klassifizierung Level 0: Stütze; Modellierungsrichtlinien: https://evolutbaugmbh.sharepoint.com/:b:/s/External/EciBgBMJMZlDgYCafV5wNokBvCJq9PUJAyVGz7O3vsjVrg?e=aLjLN9; Übersicht BIM Base: https://evolutbaugmbh.sharepoint.com/:b:/s/External/EfS4mJ9nZQpOhASXp0n2kW4B0K7N-vHKx-_6Crp5CxEFeg?e=Qu0M5d; Verbesserungsvorschläge BIM Base: https://forms.office.com/e/pcFhFfi5DW; Anleitung Mengen: https://evolutbaugmbh.sharepoint.com/:b:/s/External/ETgyOLO3JxJEqg9rbaRMLVEBHuWIRtkoMiJN1fISDr-3lw?e=E0LTiQ; Anleitung Eigenschaften: https://evolutbaugmbh.sharepoint.com/:b:/s/External/EQedjNXQkc1Btaftc01yAPUBtND9QzXFSH3-7sie6PGFww?e=wP4uf3; Release Notes: https://evolutbaugmbh.sharepoint.com/:b:/s/External/Eb41lwlDI71MhUVvor2V2mUBSaI-0tQK5U9oJAWxpCINuw?e=NtK3j6
01_Leistungen und Kosten - Gebäude: In Abklärung; Elementpreis - CHF: 0; BKP: 213 - Montagebau in Stahl; eBKP-H_Nr: C03.01; eBKP-H_Beschrieb: Aussenstütze

# IfcColumn: Vollholzwerkstoff 200 x 400 (2)
Classification: Innenstütze Massivholz (BIM Base by Evolut); Material: Vollholzwerkstoff
02_Mengen - Breite - m: 0.2; Höhe - m: 0.4
00_Datenstruktur - BIM Base Version: 4.0.0; Kundenergänzungen Version: v01; CAD Werkzeug Typ: Stütze; Klassifizierung: Innenstütze Massivholz; Klassifizierung Level 0: Stütze; Modellierungsrichtlinien: https://evolutbaugmbh.sharepoint.com/:b:/s/External/EciBgBMJMZlDgYCafV5wNokBvCJq9PUJAyVGz7O3vsjVrg?e=aLjLN9; Übersicht BIM Base: https://evolutbaugmbh.sharepoint.com/:b:/s/External/EfS4mJ9nZQpOhASXp0n2kW4B0K7N-vHKx-_6Crp5CxEFeg?e=Qu0M5d; Verbesserungsvorschläge BIM Base: https://forms.office.com/e/pcFhFfi5DW; Anleitung Mengen: https://evolutbaugmbh.sharepoint.com/:b:/s/External/ETgyOLO3JxJEqg9rbaRMLVEBHuWIRtkoMiJN1fISDr-3lw?e=E0LTiQ; Anleitung Eigenschaften: https://evolutbaugmbh.sharepoint.com/:b:/s/External/EQedjNXQkc1Btaftc01yAPUBtND9QzXFSH3-7sie6PGFww?e=wP4uf3; Release Notes: https://evolutbaugmbh.sharepoint.com/:b:/s/External/Eb41lwlDI71MhUVvor2V2mUBSaI-0tQK5U9oJAWxpCINuw?e=NtK3j6
03_Bausystem - Tragende Funktion: In Abklärung; Feuerwiderstand: In Abklärung; Umbau-Status: Neubau; Mehrschichtiger Aufbau: Vollholzwerkstoff
Holzbau - Holzbau Durchstanzung: In Abklärung
05_Bauablauf - Bau-Nr.: In Abklärung; Bauablauf Etappe: In Abklärung; Bauablauf Verbauungsort: In Abklärung; Bauablauf Start Ausführung: In Abklärung; Bauablauf Ende Ausführung: In Abklärung
01_Leistungen und Kosten - Gebäude: In Abklärung; Elementpreis - CHF: 0; BKP: 214 - Montagebau in Holz; eBKP-H_Nr: C03.02; eBKP-H_Beschrieb: Innenstütze
Bekleidung - Bekleidung Gipserarbeiten: In Abklärung; Bekleidung Malerarbeiten: In Abklärung; Bekleidung Putz: In Abklärung; Bekleidung Farbe: RAL / NCS
Name | In | Länge brutto - m = Länge netto - m | Volumen netto - m3 | Kote Unterkante | Kote Oberkante
Stütze-015 | Attika | 2.244 | 0.17952 | 9.2 | 11.444
Stütze-015 | Dachaufsicht | 3.34499 | 0.248501 | 11.844 | 15.189

# IfcCovering: Bodenaufbau Typ 01 150 (10)
Classification: Bodenbekleidung Unterkonstruktion (BIM Base by Evolut)
01_Leistungen und Kosten - Gebäude: In Abklärung; Elementpreis - CHF: 0; BKP: 281 - Bodenbeläge; eBKP-H_Nr: G02.01; eBKP-H_Beschrieb: Unterkonstruktion zu Bodenbelag
03_Bausystem - Feuerwiderstand: In Abklärung; Luftschall: In Abklärung; Trittschall: In Abklärung; U-Wert: In Abklärung; Umbau-Status: Neubau; Mehrschichtiger Aufbau: Bodenbelag; Unterlagsboden; Trittschalldämmung; Dämmung Innen
02_Mengen - Stärke - m: 0.15
05_Bauablauf - Bau-Nr.: In Abklärung; Bauablauf Etappe: In Abklärung; Bauablauf Verbauungsort: In Abklärung; Bauablauf Start Ausführung: In Abklärung; Bauablauf Ende Ausführung: In Abklärung
00_Datenstruktur - BIM Base Version: 4.0.0; Kundenergänzungen Version: v01; CAD Werkzeug Typ: Decke; Klassifizierung: Bodenbekleidung Unterkonstruktion; Klassifizierung Level 0: Bekleidung; Modellierungsrichtlinien: https://evolutbaugmbh.sharepoint.com/:b:/s/External/EciBgBMJMZlDgYCafV5wNokBvCJq9PUJAyVGz7O3vsjVrg?e=aLjLN9; Übersicht BIM Base: https://evolutbaugmbh.sharepoint.com/:b:/s/External/EfS4mJ9nZQpOhASXp0n2kW4B0K7N-vHKx-_6Crp5CxEFeg?e=Qu0M5d; Verbesserungsvorschläge BIM Base: https://forms.office.com/e/pcFhFfi5DW; Anleitung Mengen: https://evolutbaugmbh.sharepoint.com/:b:/s/External/ETgyOLO3JxJEqg9rbaRMLVEBHuWIRtkoMiJN1fISDr-3lw?e=E0LTiQ; Anleitung Eigenschaften: https://evolutbaugmbh.sharepoint.com/:b:/s/External/EQedjNXQkc1Btaftc01yAPUBtND9QzXFSH3-7sie6PGFww?e=wP4uf3; Release Notes: https://evolutbaugmbh.sharepoint.com/:b:/s/External/Eb41lwlDI71MhUVvor2V2mUBSaI-0tQK5U9oJAWxpCINuw?e=NtK3j6
Name | In | Fläche brutto - m2 | Fläche netto - m2 | Volumen netto - m3 | Umfang - m | Kote Unterkante | Kote Oberkante
Decke-007 | 1.OG | 437.021 | 431.699 | 64.7548 | 94.426 | 3.4 | 3.55
Decke-007 | 1.OG | 303.675 | 264.672 | 39.7008 | 103.107 | 2.9 | 3.05
Decke-007 | 2.OG | 387.276 | 383.212 | 57.4818 | 86.358 | 6.3 | 6.45
Decke-007 | 2.OG | 246.735 | 209.347 | 31.402 | 91.7254 | 5.8 | 5.95
Decke-007 | 2.OG | 56.9401 | 55.3219 | 8.29828 | 36.782 | 5.95 | 6.1
Decke-007 | Attika | 51.858 | 50.1196 | 7.51793 | 37.606 | 8.7 | 8.85
Decke-007 | Attika | 123.567 | 119.42 | 17.913 | 59.94 | 8.7 | 8.85
Decke-007 | Attika | 386.244 | 381.765 | 57.2647 | 87.264 | 9.2 | 9.35
Decke-007 | Attika | 8.0835 | 7.33855 | 1.10078 | 13.37 | 9.35 | 9.5
Decke-007 | Dachaufsicht | 124.877 | 120.816 | 18.1225 | 54.9021 | 12.1 | 12.25

# IfcCovering: Bodenaufbau Typ 02 150 (5)
Classification: Bodenbekleidung Unterkonstruktion (BIM Base by Evolut)
05_Bauablauf - Bau-Nr.: In Abklärung; Bauablauf Etappe: In Abklärung; Bauablauf Verbauungsort: In Abklärung; Bauablauf Start Ausführung: In Abklärung; Bauablauf Ende Ausführung: In Abklärung
03_Bausystem - Feuerwiderstand: In Abklärung; Luftschall: In Abklärung; Trittschall: In Abklärung; U-Wert: In Abklärung; Umbau-Status: Neubau; Mehrschichtiger Aufbau: Keramik; Unterlagsboden; Trittschalldämmung; Dämmung Innen
01_Leistungen und Kosten - Gebäude: In Abklärung; Elementpreis - CHF: 0; BKP: 281 - Bodenbeläge; eBKP-H_Nr: G02.01; eBKP-H_Beschrieb: Unterkonstruktion zu Bodenbelag
02_Mengen - Stärke - m: 0.15
00_Datenstruktur - BIM Base Version: 4.0.0; Kundenergänzungen Version: v01; CAD Werkzeug Typ: Decke; Klassifizierung: Bodenbekleidung Unterkonstruktion; Klassifizierung Level 0: Bekleidung; Modellierungsrichtlinien: https://evolutbaugmbh.sharepoint.com/:b:/s/External/EciBgBMJMZlDgYCafV5wNokBvCJq9PUJAyVGz7O3vsjVrg?e=aLjLN9; Übersicht BIM Base: https://evolutbaugmbh.sharepoint.com/:b:/s/External/EfS4mJ9nZQpOhASXp0n2kW4B0K7N-vHKx-_6Crp5CxEFeg?e=Qu0M5d; Verbesserungsvorschläge BIM Base: https://forms.office.com/e/pcFhFfi5DW; Anleitung Mengen: https://evolutbaugmbh.sharepoint.com/:b:/s/External/ETgyOLO3JxJEqg9rbaRMLVEBHuWIRtkoMiJN1fISDr-3lw?e=E0LTiQ; Anleitung Eigenschaften: https://evolutbaugmbh.sharepoint.com/:b:/s/External/EQedjNXQkc1Btaftc01yAPUBtND9QzXFSH3-7sie6PGFww?e=wP4uf3; Release Notes: https://evolutbaugmbh.sharepoint.com/:b:/s/External/Eb41lwlDI71MhUVvor2V2mUBSaI-0tQK5U9oJAWxpCINuw?e=NtK3j6
Name | In | Fläche brutto - m2 = Fläche netto - m2 | Volumen netto - m3 | Umfang - m | Kote Unterkante | Kote Oberkante
Decke-007 | 1.OG | 9.25542 | 1.38831 | 12.4485 | 2.9 | 3.05
Decke-008 | 1.OG | 12.3837 | 1.85756 | 14.1324 | 2.9 | 3.05
Decke-007 | 2.OG | 9.25542 | 1.38831 | 12.4485 | 5.8 | 5.95
Decke-007 | 2.OG | 12.3837 | 1.85756 | 14.1324 | 5.8 | 5.95
Decke-007 | Attika | 5.226 | 0.7839 | 9.82 | 8.7 | 8.85

# IfcCovering: Bodenaufbau Typ 03 - Terrasse 300, Decke-007
In: Attika
Classification: Dacheindeckung Terrasse Unterkonstruktion (BIM Base by Evolut)
01_Leistungen und Kosten - Gebäude: In Abklärung; Elementpreis - CHF: 0; BKP: 224 - Bedachungsarbeiten; eBKP-H_Nr: F01.02; eBKP-H_Beschrieb: Bedachung Flachdach
03_Bausystem - Feuerwiderstand: In Abklärung; Trittschall: In Abklärung; U-Wert: In Abklärung; Umbau-Status: Neubau; Mehrschichtiger Aufbau: Keramik; Unterlagsboden; Fehlt; Dämmung Aussen
05_Bauablauf - Bau-Nr.: In Abklärung; Bauablauf Etappe: In Abklärung; Bauablauf Verbauungsort: In Abklärung; Bauablauf Start Ausführung: In Abklärung; Bauablauf Ende Ausführung: In Abklärung
02_Mengen - Stärke - m: 0.3; Fläche brutto - m2: 131.256; Fläche netto - m2: 130.859; Volumen netto - m3: 39.2577; Umfang - m: 86.6685; Kote Unterkante: 8.7; Kote Oberkante: 9
00_Datenstruktur - BIM Base Version: 4.0.0; Kundenergänzungen Version: v01; CAD Werkzeug Typ: Decke; Klassifizierung: Dacheindeckung Terrasse Unterkonstruktion; Klassifizierung Level 0: Bekleidung; Modellierungsrichtlinien: https://evolutbaugmbh.sharepoint.com/:b:/s/External/EciBgBMJMZlDgYCafV5wNokBvCJq9PUJAyVGz7O3vsjVrg?e=aLjLN9; Übersicht BIM Base: https://evolutbaugmbh.sharepoint.com/:b:/s/External/EfS4mJ9nZQpOhASXp0n2kW4B0K7N-vHKx-_6Crp5CxEFeg?e=Qu0M5d; Verbesserungsvorschläge BIM Base: https://forms.office.com/e/pcFhFfi5DW; Anleitung Mengen: https://evolutbaugmbh.sharepoint.com/:b:/s/External/ETgyOLO3JxJEqg9rbaRMLVEBHuWIRtkoMiJN1fISDr-3lw?e=E0LTiQ; Anleitung Eigenschaften: https://evolutbaugmbh.sharepoint.com/:b:/s/External/EQedjNXQkc1Btaftc01yAPUBtND9QzXFSH3-7sie6PGFww?e=wP4uf3; Release Notes: https://evolutbaugmbh.sharepoint.com/:b:/s/External/Eb41lwlDI71MhUVvor2V2mUBSaI-0tQK5U9oJAWxpCINuw?e=NtK3j6

# IfcCovering: Bodenaufbau Typ 04 220 (2)
In: EG
Classification: Bodenbekleidung Unterkonstruktion (BIM Base by Evolut)
01_Leistungen und Kosten - Gebäude: In Abklärung; Elementpreis - CHF: 0; BKP: 281 - Bodenbeläge; eBKP-H_Nr: G02.01; eBKP-H_Beschrieb: Unterkonstruktion zu Bodenbelag
05_Bauablauf - Bau-Nr.: In Abklärung; Bauablauf Etappe: In Abklärung; Bauablauf Verbauungsort: In Abklärung; Bauablauf Start Ausführung: In Abklärung; Bauablauf Ende Ausführung: In Abklärung
03_Bausystem - Feuerwiderstand: In Abklärung; Luftschall: In Abklärung; Trittschall: In Abklärung; U-Wert: In Abklärung; Umbau-Status: Neubau; Mehrschichtiger Aufbau: Bodenbelag; Unterlagsboden; Fehlt; Fehlt; Sperrschicht
02_Mengen - Stärke - m: 0.22
00_Datenstruktur - BIM Base Version: 4.0.0; Kundenergänzungen Version: v01; CAD Werkzeug Typ: Decke; Klassifizierung: Bodenbekleidung Unterkonstruktion; Klassifizierung Level 0: Bekleidung; Modellierungsrichtlinien: https://evolutbaugmbh.sharepoint.com/:b:/s/External/EciBgBMJMZlDgYCafV5wNokBvCJq9PUJAyVGz7O3vsjVrg?e=aLjLN9; Übersicht BIM Base: https://evolutbaugmbh.sharepoint.com/:b:/s/External/EfS4mJ9nZQpOhASXp0n2kW4B0K7N-vHKx-_6Crp5CxEFeg?e=Qu0M5d; Verbesserungsvorschläge BIM Base: https://forms.office.com/e/pcFhFfi5DW; Anleitung Mengen: https://evolutbaugmbh.sharepoint.com/:b:/s/External/ETgyOLO3JxJEqg9rbaRMLVEBHuWIRtkoMiJN1fISDr-3lw?e=E0LTiQ; Anleitung Eigenschaften: https://evolutbaugmbh.sharepoint.com/:b:/s/External/EQedjNXQkc1Btaftc01yAPUBtND9QzXFSH3-7sie6PGFww?e=wP4uf3; Release Notes: https://evolutbaugmbh.sharepoint.com/:b:/s/External/Eb41lwlDI71MhUVvor2V2mUBSaI-0tQK5U9oJAWxpCINuw?e=NtK3j6
Name | Fläche brutto - m2 | Fläche netto - m2 | Volumen netto - m3 | Umfang - m | Kote Unterkante | Kote Oberkante
Decke-006 | 95.0656 | 95.0656 | 20.9144 | 50.36 | -0.6 | -0.38
Decke-006 | 389.297 | 386.495 | 85.0289 | 86.568 | 0 | 0.22

# IfcCovering: Brüstungsabdeckung 02 470 x 100 (3)
In: Dachaufsicht
Classification: Dacheindeckung Balkon (BIM Base by Evolut)
05_Bauablauf - Bau-Nr.: In Abklärung; Bauablauf Etappe: In Abklärung; Bauablauf Verbauungsort: In Abklärung; Bauablauf Start Ausführung: In Abklärung; Bauablauf Ende Ausführung: In Abklärung
03_Bausystem - Feuerwiderstand: In Abklärung; Trittschall: In Abklärung; U-Wert: In Abklärung; Umbau-Status: Neubau; Mehrschichtiger Aufbau: Stahl; Stahl
01_Leistungen und Kosten - Gebäude: In Abklärung; Elementpreis - CHF: 0; BKP: 224 - Bedachungsarbeiten; eBKP-H_Nr: F01.02; eBKP-H_Beschrieb: Bedachung Flachdach
02_Mengen - Breite - m: 0.4704; Höhe - m: 0.1; Stärke - m: 0.4704; Kote Unterkante: 12.434; Kote Oberkante: 12.534
00_Datenstruktur - BIM Base Version: 4.0.0; Kundenergänzungen Version: v01; CAD Werkzeug Typ: Träger; Klassifizierung: Dacheindeckung Balkon; Klassifizierung Level 0: Bekleidung; Modellierungsrichtlinien: https://evolutbaugmbh.sharepoint.com/:b:/s/External/EciBgBMJMZlDgYCafV5wNokBvCJq9PUJAyVGz7O3vsjVrg?e=aLjLN9; Übersicht BIM Base: https://evolutbaugmbh.sharepoint.com/:b:/s/External/EfS4mJ9nZQpOhASXp0n2kW4B0K7N-vHKx-_6Crp5CxEFeg?e=Qu0M5d; Verbesserungsvorschläge BIM Base: https://forms.office.com/e/pcFhFfi5DW; Anleitung Mengen: https://evolutbaugmbh.sharepoint.com/:b:/s/External/ETgyOLO3JxJEqg9rbaRMLVEBHuWIRtkoMiJN1fISDr-3lw?e=E0LTiQ; Anleitung Eigenschaften: https://evolutbaugmbh.sharepoint.com/:b:/s/External/EQedjNXQkc1Btaftc01yAPUBtND9QzXFSH3-7sie6PGFww?e=wP4uf3; Release Notes: https://evolutbaugmbh.sharepoint.com/:b:/s/External/Eb41lwlDI71MhUVvor2V2mUBSaI-0tQK5U9oJAWxpCINuw?e=NtK3j6
Name | Länge brutto - m | Fläche brutto - m2 | Volumen netto - m3
Unterzug-027 | 24.5077 | 11.5284 | 0.0416262
Unterzug-027 | 12.0154 | 5.65205 | 0.0197992
Unterzug-027 | 22.0787 | 10.3858 | 0.0374606

# IfcCovering: Brüstungsabdeckung 03 520 x 100, Unterzug-027
In: Dachaufsicht
Classification: Dacheindeckung Balkon (BIM Base by Evolut)
05_Bauablauf - Bau-Nr.: In Abklärung; Bauablauf Etappe: In Abklärung; Bauablauf Verbauungsort: In Abklärung; Bauablauf Start Ausführung: In Abklärung; Bauablauf Ende Ausführung: In Abklärung
03_Bausystem - Feuerwiderstand: In Abklärung; Trittschall: In Abklärung; U-Wert: In Abklärung; Umbau-Status: Neubau; Mehrschichtiger Aufbau: Stahl; Stahl
02_Mengen - Breite - m: 0.5204; Höhe - m: 0.1; Stärke - m: 0.5204; Länge brutto - m: 2.291; Fläche brutto - m2: 1.19224; Volumen netto - m3: 0.0044946; Kote Unterkante: 9.103; Kote Oberkante: 9.203
01_Leistungen und Kosten - Gebäude: In Abklärung; Elementpreis - CHF: 0; BKP: 224 - Bedachungsarbeiten; eBKP-H_Nr: F01.02; eBKP-H_Beschrieb: Bedachung Flachdach
00_Datenstruktur - BIM Base Version: 4.0.0; Kundenergänzungen Version: v01; CAD Werkzeug Typ: Träger; Klassifizierung: Dacheindeckung Balkon; Klassifizierung Level 0: Bekleidung; Modellierungsrichtlinien: https://evolutbaugmbh.sharepoint.com/:b:/s/External/EciBgBMJMZlDgYCafV5wNokBvCJq9PUJAyVGz7O3vsjVrg?e=aLjLN9; Übersicht BIM Base: https://evolutbaugmbh.sharepoint.com/:b:/s/External/EfS4mJ9nZQpOhASXp0n2kW4B0K7N-vHKx-_6Crp5CxEFeg?e=Qu0M5d; Verbesserungsvorschläge BIM Base: https://forms.office.com/e/pcFhFfi5DW; Anleitung Mengen: https://evolutbaugmbh.sharepoint.com/:b:/s/External/ETgyOLO3JxJEqg9rbaRMLVEBHuWIRtkoMiJN1fISDr-3lw?e=E0LTiQ; Anleitung Eigenschaften: https://evolutbaugmbh.sharepoint.com/:b:/s/External/EQedjNXQkc1Btaftc01yAPUBtND9QzXFSH3-7sie6PGFww?e=wP4uf3; Release Notes: https://evolutbaugmbh.sharepoint.com/:b:/s/External/Eb41lwlDI71MhUVvor2V2mUBSaI-0tQK5U9oJAWxpCINuw?e=NtK3j6

# IfcCovering: Brüstungsabdeckung 04 315 x 100 (5)
In: Attika
Classification: Dacheindeckung Balkon (BIM Base by Evolut)
01_Leistungen und Kosten - Gebäude: In Abklärung; Elementpreis - CHF: 0; BKP: 224 - Bedachungsarbeiten; eBKP-H_Nr: F01.02; eBKP-H_Beschrieb: Bedachung Flachdach
03_Bausystem - Feuerwiderstand: In Abklärung; Trittschall: In Abklärung; U-Wert: In Abklärung; Umbau-Status: Neubau; Mehrschichtiger Aufbau: Stahl; Stahl
02_Mengen - Breite - m: 0.3154; Höhe - m: 0.1; Stärke - m: 0.3154
00_Datenstruktur - BIM Base Version: 4.0.0; Kundenergänzungen Version: v01; CAD Werkzeug Typ: Träger; Klassifizierung: Dacheindeckung Balkon; Klassifizierung Level 0: Bekleidung; Modellierungsrichtlinien: https://evolutbaugmbh.sharepoint.com/:b:/s/External/EciBgBMJMZlDgYCafV5wNokBvCJq9PUJAyVGz7O3vsjVrg?e=aLjLN9; Übersicht BIM Base: https://evolutbaugmbh.sharepoint.com/:b:/s/External/EfS4mJ9nZQpOhASXp0n2kW4B0K7N-vHKx-_6Crp5CxEFeg?e=Qu0M5d; Verbesserungsvorschläge BIM Base: https://forms.office.com/e/pcFhFfi5DW; Anleitung Mengen: https://evolutbaugmbh.sharepoint.com/:b:/s/External/ETgyOLO3JxJEqg9rbaRMLVEBHuWIRtkoMiJN1fISDr-3lw?e=E0LTiQ; Anleitung Eigenschaften: https://evolutbaugmbh.sharepoint.com/:b:/s/External/EQedjNXQkc1Btaftc01yAPUBtND9QzXFSH3-7sie6PGFww?e=wP4uf3; Release Notes: https://evolutbaugmbh.sharepoint.com/:b:/s/External/Eb41lwlDI71MhUVvor2V2mUBSaI-0tQK5U9oJAWxpCINuw?e=NtK3j6
05_Bauablauf - Bau-Nr.: In Abklärung; Bauablauf Etappe: In Abklärung; Bauablauf Verbauungsort: In Abklärung; Bauablauf Start Ausführung: In Abklärung; Bauablauf Ende Ausführung: In Abklärung
Name | Länge brutto - m | Fläche brutto - m2 | Volumen netto - m3 | Kote Unterkante | Kote Oberkante
Unterzug-027 | 2.0977 | 0.661615 | 0.00250767 | 9.1 | 9.2
Unterzug-027 | 4.4908 | 1.4164 | 0.0059414 | 9.1 | 9.2
Unterzug-027 | 4.4908 | 1.4164 | 0.00594271 | 9.1 | 9.2
Unterzug-027 | 4.4908 | 1.4164 | 0.00594271 | 9.103 | 9.203
Unterzug-027 | 1.91 | 0.602414 | 0.0025829 | 9.103 | 9.203

# IfcCovering: Brüstungsabdeckung 05 405 x 100 (3)
In: Attika
Classification: Dacheindeckung Balkon (BIM Base by Evolut)
05_Bauablauf - Bau-Nr.: In Abklärung; Bauablauf Etappe: In Abklärung; Bauablauf Verbauungsort: In Abklärung; Bauablauf Start Ausführung: In Abklärung; Bauablauf Ende Ausführung: In Abklärung
03_Bausystem - Feuerwiderstand: In Abklärung; Trittschall: In Abklärung; U-Wert: In Abklärung; Umbau-Status: Neubau; Mehrschichtiger Aufbau: Stahl; Stahl
01_Leistungen und Kosten - Gebäude: In Abklärung; Elementpreis - CHF: 0; BKP: 224 - Bedachungsarbeiten; eBKP-H_Nr: F01.02; eBKP-H_Beschrieb: Bedachung Flachdach
02_Mengen - Breite - m: 0.4054; Höhe - m: 0.1; Stärke - m: 0.4054; Kote Unterkante: 9.103; Kote Oberkante: 9.203
00_Datenstruktur - BIM Base Version: 4.0.0; Kundenergänzungen Version: v01; CAD Werkzeug Typ: Träger; Klassifizierung: Dacheindeckung Balkon; Klassifizierung Level 0: Bekleidung; Modellierungsrichtlinien: https://evolutbaugmbh.sharepoint.com/:b:/s/External/EciBgBMJMZlDgYCafV5wNokBvCJq9PUJAyVGz7O3vsjVrg?e=aLjLN9; Übersicht BIM Base: https://evolutbaugmbh.sharepoint.com/:b:/s/External/EfS4mJ9nZQpOhASXp0n2kW4B0K7N-vHKx-_6Crp5CxEFeg?e=Qu0M5d; Verbesserungsvorschläge BIM Base: https://forms.office.com/e/pcFhFfi5DW; Anleitung Mengen: https://evolutbaugmbh.sharepoint.com/:b:/s/External/ETgyOLO3JxJEqg9rbaRMLVEBHuWIRtkoMiJN1fISDr-3lw?e=E0LTiQ; Anleitung Eigenschaften: https://evolutbaugmbh.sharepoint.com/:b:/s/External/EQedjNXQkc1Btaftc01yAPUBtND9QzXFSH3-7sie6PGFww?e=wP4uf3; Release Notes: https://evolutbaugmbh.sharepoint.com/:b:/s/External/Eb41lwlDI71MhUVvor2V2mUBSaI-0tQK5U9oJAWxpCINuw?e=NtK3j6
Name | Länge brutto - m | Fläche brutto - m2 | Volumen netto - m3
Unterzug-027 | 3.0077 | 1.21932 | 0.00434976
Unterzug-027 | 15.0154 | 6.08725 | 0.022656
Unterzug-027 | 3.2535 | 1.31897 | 0.00497547

# IfcCovering: Dacheindeckung Typ 01 120 (2)
Classification: Dacheindeckung Balkon Belag Holz (BIM Base by Evolut)
01_Leistungen und Kosten - Gebäude: In Abklärung; Elementpreis - CHF: 0; BKP: 224 - Bedachungsarbeiten; eBKP-H_Nr: F01.02; eBKP-H_Beschrieb: Bedachung Flachdach
03_Bausystem - Trittschall: In Abklärung; U-Wert: In Abklärung; Umbau-Status: Neubau; Mehrschichtiger Aufbau: Bodenbelag; Dämmung Aussen; Sperrschicht
05_Bauablauf - Bau-Nr.: In Abklärung; Bauablauf Etappe: In Abklärung; Bauablauf Verbauungsort: In Abklärung; Bauablauf Start Ausführung: In Abklärung; Bauablauf Ende Ausführung: In Abklärung
00_Datenstruktur - BIM Base Version: 4.0.0; Kundenergänzungen Version: v01; CAD Werkzeug Typ: Decke; Klassifizierung: Dacheindeckung Balkon Belag Holz; Klassifizierung Level 0: Bekleidung; Modellierungsrichtlinien: https://evolutbaugmbh.sharepoint.com/:b:/s/External/EciBgBMJMZlDgYCafV5wNokBvCJq9PUJAyVGz7O3vsjVrg?e=aLjLN9; Übersicht BIM Base: https://evolutbaugmbh.sharepoint.com/:b:/s/External/EfS4mJ9nZQpOhASXp0n2kW4B0K7N-vHKx-_6Crp5CxEFeg?e=Qu0M5d; Verbesserungsvorschläge BIM Base: https://forms.office.com/e/pcFhFfi5DW; Anleitung Mengen: https://evolutbaugmbh.sharepoint.com/:b:/s/External/ETgyOLO3JxJEqg9rbaRMLVEBHuWIRtkoMiJN1fISDr-3lw?e=E0LTiQ; Anleitung Eigenschaften: https://evolutbaugmbh.sharepoint.com/:b:/s/External/EQedjNXQkc1Btaftc01yAPUBtND9QzXFSH3-7sie6PGFww?e=wP4uf3; Release Notes: https://evolutbaugmbh.sharepoint.com/:b:/s/External/Eb41lwlDI71MhUVvor2V2mUBSaI-0tQK5U9oJAWxpCINuw?e=NtK3j6
02_Mengen - Stärke - m: 0.1201
Name | In | Fläche brutto - m2 | Fläche netto - m2 | Volumen netto - m3 | Umfang - m | Kote Unterkante | Kote Oberkante
Deckennr.-073 | 2.OG | 49.1657 | 49.1654 | 5.90472 | 33.7055 | 6.3 | 6.42
Deckennr.-073 | Attika | 48.7559 | 48.7558 | 5.85549 | 33.64 | 9.2 | 9.32

# IfcCovering: Dacheindeckung Typ 02 - Flachdach 502 (3)
In: Attika
Classification: Dacheindeckung Flachdach Belag extensive Begrünung (BIM Base by Evolut)
01_Leistungen und Kosten - Gebäude: In Abklärung; Elementpreis - CHF: 0; BKP: 224 - Bedachungsarbeiten; eBKP-H_Nr: F01.02; eBKP-H_Beschrieb: Bedachung Flachdach
05_Bauablauf - Bau-Nr.: In Abklärung; Bauablauf Etappe: In Abklärung; Bauablauf Verbauungsort: In Abklärung; Bauablauf Start Ausführung: In Abklärung; Bauablauf Ende Ausführung: In Abklärung
03_Bausystem - Trittschall: In Abklärung; U-Wert: In Abklärung; Umbau-Status: Neubau; Mehrschichtiger Aufbau: Dachbegrünung extensiv; Abdichtung Bitumen; Aufdachdämmung; Gefällsdämmung; Dampf- / Luftdichtigkeitsschicht
00_Datenstruktur - BIM Base Version: 4.0.0; Kundenergänzungen Version: v01; CAD Werkzeug Typ: Decke; Klassifizierung: Dacheindeckung Flachdach Belag extensive Begrünung; Klassifizierung Level 0: Bekleidung; Modellierungsrichtlinien: https://evolutbaugmbh.sharepoint.com/:b:/s/External/EciBgBMJMZlDgYCafV5wNokBvCJq9PUJAyVGz7O3vsjVrg?e=aLjLN9; Übersicht BIM Base: https://evolutbaugmbh.sharepoint.com/:b:/s/External/EfS4mJ9nZQpOhASXp0n2kW4B0K7N-vHKx-_6Crp5CxEFeg?e=Qu0M5d; Verbesserungsvorschläge BIM Base: https://forms.office.com/e/pcFhFfi5DW; Anleitung Mengen: https://evolutbaugmbh.sharepoint.com/:b:/s/External/ETgyOLO3JxJEqg9rbaRMLVEBHuWIRtkoMiJN1fISDr-3lw?e=E0LTiQ; Anleitung Eigenschaften: https://evolutbaugmbh.sharepoint.com/:b:/s/External/EQedjNXQkc1Btaftc01yAPUBtND9QzXFSH3-7sie6PGFww?e=wP4uf3; Release Notes: https://evolutbaugmbh.sharepoint.com/:b:/s/External/Eb41lwlDI71MhUVvor2V2mUBSaI-0tQK5U9oJAWxpCINuw?e=NtK3j6
02_Mengen - Stärke - m: 0.502
Name | Fläche brutto - m2 = Fläche netto - m2 | Volumen netto - m3 | Umfang - m | Kote Unterkante | Kote Oberkante
Deckennr.-073 | 167.937 | 84.3046 | 67.8407 | 11.6 | 12.102
Deckennr.-073 | 31.4745 | 15.8002 | 27.8413 | 11.6 | 12.102
Deckennr.-073 | 62.5125 | 31.3401 | 36.58 | 12.35 | 12.852

# IfcCovering: Dacheindeckung Typ 03 - Steildach 100 (4)
In: Dachaufsicht
Classification: Dacheindeckung Steildach Belag Dachziegel (BIM Base by Evolut)
05_Bauablauf - Bau-Nr.: In Abklärung; Bauablauf Etappe: In Abklärung; Bauablauf Verbauungsort: In Abklärung; Bauablauf Start Ausführung: In Abklärung; Bauablauf Ende Ausführung: In Abklärung
03_Bausystem - U-Wert: In Abklärung; Umbau-Status: Neubau; Mehrschichtiger Aufbau: Dachziegel grau; Aufdachdämmung; Lattenrost vertikal
01_Leistungen und Kosten - Gebäude: In Abklärung; Elementpreis - CHF: 0; BKP: 224 - Bedachungsarbeiten; eBKP-H_Nr: F01.03; eBKP-H_Beschrieb: Bedachung Steildach
02_Mengen - Stärke - m: 0.1
00_Datenstruktur - BIM Base Version: 4.0.0; Kundenergänzungen Version: v01; CAD Werkzeug Typ: Dach; Klassifizierung: Dacheindeckung Steildach Belag Dachziegel; Klassifizierung Level 0: Bekleidung; Modellierungsrichtlinien: https://evolutbaugmbh.sharepoint.com/:b:/s/External/EciBgBMJMZlDgYCafV5wNokBvCJq9PUJAyVGz7O3vsjVrg?e=aLjLN9; Übersicht BIM Base: https://evolutbaugmbh.sharepoint.com/:b:/s/External/EfS4mJ9nZQpOhASXp0n2kW4B0K7N-vHKx-_6Crp5CxEFeg?e=Qu0M5d; Verbesserungsvorschläge BIM Base: https://forms.office.com/e/pcFhFfi5DW; Anleitung Mengen: https://evolutbaugmbh.sharepoint.com/:b:/s/External/ETgyOLO3JxJEqg9rbaRMLVEBHuWIRtkoMiJN1fISDr-3lw?e=E0LTiQ; Anleitung Eigenschaften: https://evolutbaugmbh.sharepoint.com/:b:/s/External/EQedjNXQkc1Btaftc01yAPUBtND9QzXFSH3-7sie6PGFww?e=wP4uf3; Release Notes: https://evolutbaugmbh.sharepoint.com/:b:/s/External/Eb41lwlDI71MhUVvor2V2mUBSaI-0tQK5U9oJAWxpCINuw?e=NtK3j6
Name | Fläche brutto - m2 | Fläche netto - m2 | Volumen netto - m3 | Umfang - m | Kote Unterkante | Kote Oberkante
2 x Dach-011 | 44.4572 | 44.4572 | 4.44572 | 27.1192 | 15.153 | 15.253
Dach-011 | 296.561 | 189.165 | 23.1371 | 113.433 | 13.126 | 13.226
Dach-011 | 270.71 | 184.841 | 21.1978 | 113.433 | 13.126 | 13.226

# IfcCovering: Deckenbekleidung Typ 01 65 (3)
Classification: Deckenbekleidung Belag Gipskarton (BIM Base by Evolut)
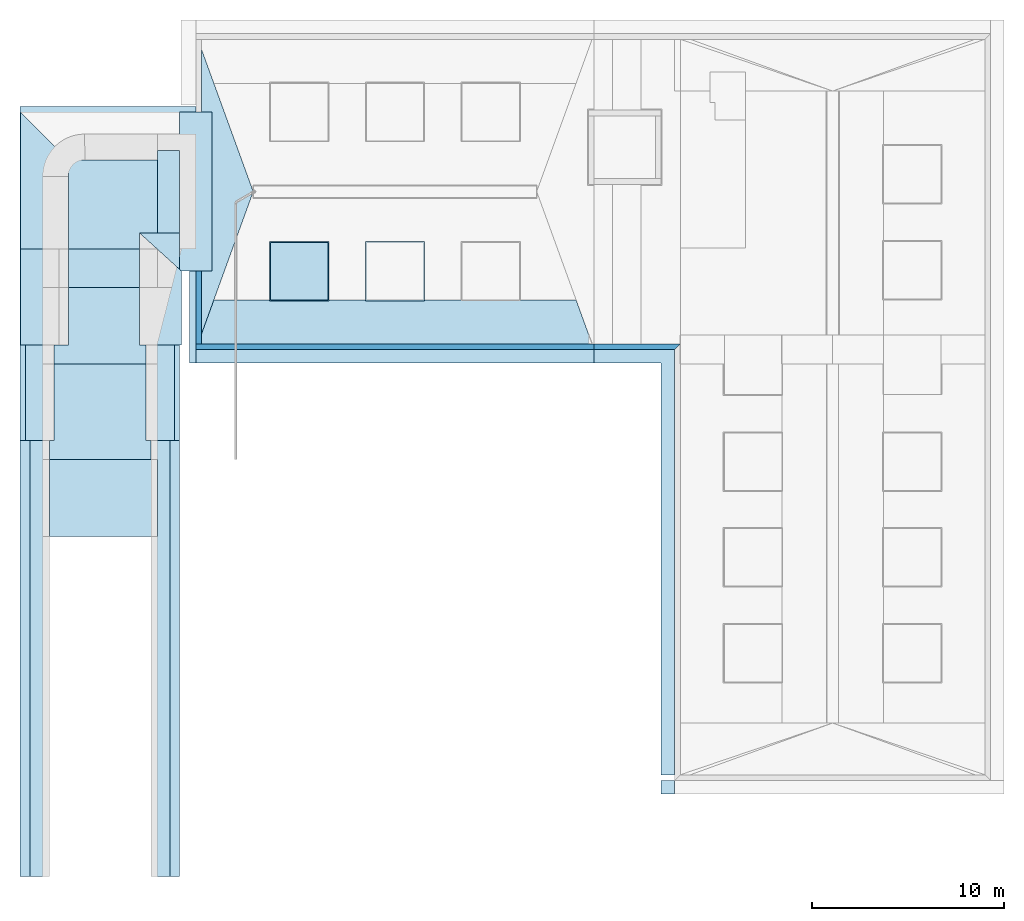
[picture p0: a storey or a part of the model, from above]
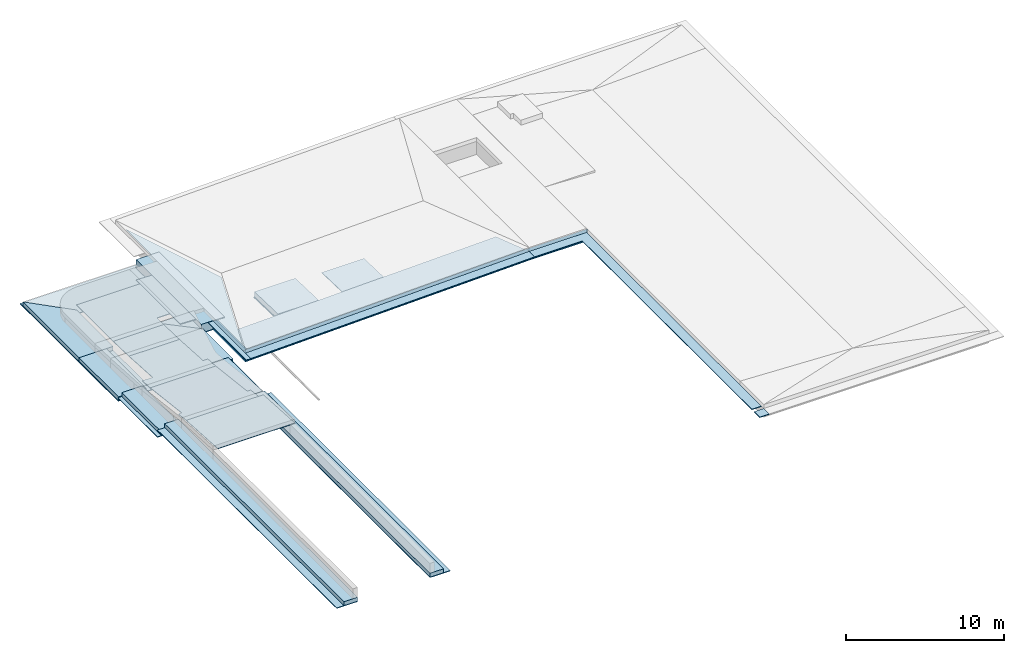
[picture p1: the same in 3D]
Properties of the parts of a building model (IFC4), part 2 of 8

# IfcCovering: Deckenbekleidung Typ 01 65 (3)
01_Leistungen und Kosten - Gebäude: In Abklärung; Elementpreis - CHF: 0; BKP: 283 - Deckenverkleidungen; eBKP-H_Nr: G04.02; eBKP-H_Beschrieb: Deckenbekleidung
05_Bauablauf - Bau-Nr.: In Abklärung; Bauablauf Etappe: In Abklärung; Bauablauf Verbauungsort: In Abklärung; Bauablauf Start Ausführung: In Abklärung; Bauablauf Ende Ausführung: In Abklärung
03_Bausystem - Feuerwiderstand: In Abklärung; Luftschall: In Abklärung; U-Wert: In Abklärung; Umbau-Status: Neubau; Mehrschichtiger Aufbau: Lattenrost vertikal; Gipskartonplatte GKP; Gipskartonplatte GKP
02_Mengen - Stärke - m: 0.065
00_Datenstruktur - BIM Base Version: 4.0.0; Kundenergänzungen Version: v01; Klassifizierung: Deckenbekleidung Belag Gipskarton; Klassifizierung Level 0: Bekleidung; Modellierungsrichtlinien: https://evolutbaugmbh.sharepoint.com/:b:/s/External/EciBgBMJMZlDgYCafV5wNokBvCJq9PUJAyVGz7O3vsjVrg?e=aLjLN9; Übersicht BIM Base: https://evolutbaugmbh.sharepoint.com/:b:/s/External/EfS4mJ9nZQpOhASXp0n2kW4B0K7N-vHKx-_6Crp5CxEFeg?e=Qu0M5d; Verbesserungsvorschläge BIM Base: https://forms.office.com/e/pcFhFfi5DW; Anleitung Mengen: https://evolutbaugmbh.sharepoint.com/:b:/s/External/ETgyOLO3JxJEqg9rbaRMLVEBHuWIRtkoMiJN1fISDr-3lw?e=E0LTiQ; Anleitung Eigenschaften: https://evolutbaugmbh.sharepoint.com/:b:/s/External/EQedjNXQkc1Btaftc01yAPUBtND9QzXFSH3-7sie6PGFww?e=wP4uf3; Release Notes: https://evolutbaugmbh.sharepoint.com/:b:/s/External/Eb41lwlDI71MhUVvor2V2mUBSaI-0tQK5U9oJAWxpCINuw?e=NtK3j6
Name | In | Fläche brutto - m2 | Fläche netto - m2 | Volumen netto - m3 | Umfang - m | Kote Unterkante | Kote Oberkante | CAD Werkzeug Typ
Dach-011 | UG | 29.7123 | 29.7123 | 1.9313 | 23.703 | -0.692 | -0.627 | Dach
Deckennr.-073 | EG | 50.328 | 50.328 | 3.27132 | 35.16 | 2.585 | 2.65 | Decke
Deckennr.-073 | 2.OG | 363.646 | 356.758 | 23.1522 | 86.538 | 8.879 | 8.944 | Decke

# IfcCovering: Dämmung Aussen 80 x 250 (2)
In: Dachaufsicht
Classification: Dämmung Dach (BIM Base by Evolut); Material: Dämmung Aussen
01_Leistungen und Kosten - Gebäude: In Abklärung; Elementpreis - CHF: 0
05_Bauablauf - Bau-Nr.: In Abklärung; Bauablauf Etappe: In Abklärung; Bauablauf Verbauungsort: In Abklärung; Bauablauf Start Ausführung: In Abklärung; Bauablauf Ende Ausführung: In Abklärung
03_Bausystem - Umbau-Status: Neubau; Mehrschichtiger Aufbau: Dämmung Aussen
00_Datenstruktur - BIM Base Version: 4.0.0; Kundenergänzungen Version: v01; CAD Werkzeug Typ: Stütze; Klassifizierung: Dämmung Dach; Klassifizierung Level 0: Baukomponente; Modellierungsrichtlinien: https://evolutbaugmbh.sharepoint.com/:b:/s/External/EciBgBMJMZlDgYCafV5wNokBvCJq9PUJAyVGz7O3vsjVrg?e=aLjLN9; Übersicht BIM Base: https://evolutbaugmbh.sharepoint.com/:b:/s/External/EfS4mJ9nZQpOhASXp0n2kW4B0K7N-vHKx-_6Crp5CxEFeg?e=Qu0M5d; Verbesserungsvorschläge BIM Base: https://forms.office.com/e/pcFhFfi5DW; Anleitung Mengen: https://evolutbaugmbh.sharepoint.com/:b:/s/External/ETgyOLO3JxJEqg9rbaRMLVEBHuWIRtkoMiJN1fISDr-3lw?e=E0LTiQ; Anleitung Eigenschaften: https://evolutbaugmbh.sharepoint.com/:b:/s/External/EQedjNXQkc1Btaftc01yAPUBtND9QzXFSH3-7sie6PGFww?e=wP4uf3; Release Notes: https://evolutbaugmbh.sharepoint.com/:b:/s/External/Eb41lwlDI71MhUVvor2V2mUBSaI-0tQK5U9oJAWxpCINuw?e=NtK3j6
02_Mengen - Breite - m: 0.08; Höhe - m: 0.25; Stärke - m: 0.08; Länge brutto - m: 0.931; Fläche brutto - m2: 0.23275; Volumen netto - m3: 0.01862; Kote Unterkante: 11.6; Kote Oberkante: 12.531

# IfcCovering: Dämmung Innen 40 (4)
In: Attika
Classification: Dämmung Wand (BIM Base by Evolut); Material: Dämmung Innen
01_Leistungen und Kosten - Gebäude: In Abklärung; Elementpreis - CHF: 0
05_Bauablauf - Bau-Nr.: In Abklärung; Bauablauf Etappe: In Abklärung; Bauablauf Verbauungsort: In Abklärung; Bauablauf Start Ausführung: In Abklärung; Bauablauf Ende Ausführung: In Abklärung
02_Mengen - Stärke - m: 0.04; Kote Oberkante: 12.35
03_Bausystem - Umbau-Status: Neubau; Mehrschichtiger Aufbau: Dämmung Innen
00_Datenstruktur - BIM Base Version: 4.0.0; Kundenergänzungen Version: v01; CAD Werkzeug Typ: Wand; Klassifizierung: Dämmung Wand; Klassifizierung Level 0: Baukomponente; Modellierungsrichtlinien: https://evolutbaugmbh.sharepoint.com/:b:/s/External/EciBgBMJMZlDgYCafV5wNokBvCJq9PUJAyVGz7O3vsjVrg?e=aLjLN9; Übersicht BIM Base: https://evolutbaugmbh.sharepoint.com/:b:/s/External/EfS4mJ9nZQpOhASXp0n2kW4B0K7N-vHKx-_6Crp5CxEFeg?e=Qu0M5d; Verbesserungsvorschläge BIM Base: https://forms.office.com/e/pcFhFfi5DW; Anleitung Mengen: https://evolutbaugmbh.sharepoint.com/:b:/s/External/ETgyOLO3JxJEqg9rbaRMLVEBHuWIRtkoMiJN1fISDr-3lw?e=E0LTiQ; Anleitung Eigenschaften: https://evolutbaugmbh.sharepoint.com/:b:/s/External/EQedjNXQkc1Btaftc01yAPUBtND9QzXFSH3-7sie6PGFww?e=wP4uf3; Release Notes: https://evolutbaugmbh.sharepoint.com/:b:/s/External/Eb41lwlDI71MhUVvor2V2mUBSaI-0tQK5U9oJAWxpCINuw?e=NtK3j6
Name | Höhe - m | Länge brutto - m | Fläche brutto - m2 | Fläche netto - m2 | Volumen netto - m3 | Kote Unterkante
Wand-014 | 3.15 | 2.549 | 8.02935 | 7.5852 | 0.303408 | 9.2
Wand-015 | 3.15 | 8.33 | 26.2395 | 26.2335 | 1.04934 | 9.2
Wand-015 | 0.93 | 1.1 | 1.023 | 1.023 | 0.04092 | 11.42
Wand-015 | 3.15 | 0.539 | 1.69785 | 0.82785 | 0.033114 | 9.2

# IfcCovering: Dämmung Innen 80 (3)
Classification: Dämmung Wand (BIM Base by Evolut); Material: Dämmung Innen
01_Leistungen und Kosten - Gebäude: In Abklärung; Elementpreis - CHF: 0
05_Bauablauf - Bau-Nr.: In Abklärung; Bauablauf Etappe: In Abklärung; Bauablauf Verbauungsort: In Abklärung; Bauablauf Start Ausführung: In Abklärung; Bauablauf Ende Ausführung: In Abklärung
02_Mengen - Höhe - m: 2.9; Stärke - m: 0.08
03_Bausystem - Umbau-Status: Neubau; Mehrschichtiger Aufbau: Dämmung Innen
00_Datenstruktur - BIM Base Version: 4.0.0; Kundenergänzungen Version: v01; CAD Werkzeug Typ: Wand; Klassifizierung: Dämmung Wand; Klassifizierung Level 0: Baukomponente; Modellierungsrichtlinien: https://evolutbaugmbh.sharepoint.com/:b:/s/External/EciBgBMJMZlDgYCafV5wNokBvCJq9PUJAyVGz7O3vsjVrg?e=aLjLN9; Übersicht BIM Base: https://evolutbaugmbh.sharepoint.com/:b:/s/External/EfS4mJ9nZQpOhASXp0n2kW4B0K7N-vHKx-_6Crp5CxEFeg?e=Qu0M5d; Verbesserungsvorschläge BIM Base: https://forms.office.com/e/pcFhFfi5DW; Anleitung Mengen: https://evolutbaugmbh.sharepoint.com/:b:/s/External/ETgyOLO3JxJEqg9rbaRMLVEBHuWIRtkoMiJN1fISDr-3lw?e=E0LTiQ; Anleitung Eigenschaften: https://evolutbaugmbh.sharepoint.com/:b:/s/External/EQedjNXQkc1Btaftc01yAPUBtND9QzXFSH3-7sie6PGFww?e=wP4uf3; Release Notes: https://evolutbaugmbh.sharepoint.com/:b:/s/External/Eb41lwlDI71MhUVvor2V2mUBSaI-0tQK5U9oJAWxpCINuw?e=NtK3j6
Name | In | Länge brutto - m | Fläche brutto - m2 | Fläche netto - m2 | Volumen netto - m3 | Kote Unterkante | Kote Oberkante
Wand-014 | EG | 4.4899 | 13.8907 | 13.7407 | 1.09345 | 0.5 | 3.4
Wand-014 | 1.OG | 4.7899 | 13.8907 | 13.8907 | 1.11126 | 3.4 | 6.3
Wand-014 | 2.OG | 4.78 | 14.761 | 13.791 | 1.09655 | 6.3 | 9.2

# IfcCovering: Dämmung-Innen 80, Wand-014
In: Attika
Classification: Dämmung Wand (BIM Base by Evolut); Material: Dämmung-Innen
01_Leistungen und Kosten - Gebäude: In Abklärung; Elementpreis - CHF: 0
05_Bauablauf - Bau-Nr.: In Abklärung; Bauablauf Etappe: In Abklärung; Bauablauf Verbauungsort: In Abklärung; Bauablauf Start Ausführung: In Abklärung; Bauablauf Ende Ausführung: In Abklärung
02_Mengen - Höhe - m: 3.331; Stärke - m: 0.08; Länge brutto - m: 1.75; Fläche brutto - m2: 5.92235; Fläche netto - m2: 5.92209; Volumen netto - m3: 0.473767; Kote Unterkante: 9.2; Kote Oberkante: 12.531
03_Bausystem - Umbau-Status: Neubau; Mehrschichtiger Aufbau: Dämmung-Innen
00_Datenstruktur - BIM Base Version: 4.0.0; Kundenergänzungen Version: v01; CAD Werkzeug Typ: Wand; Klassifizierung: Dämmung Wand; Klassifizierung Level 0: Baukomponente; Modellierungsrichtlinien: https://evolutbaugmbh.sharepoint.com/:b:/s/External/EciBgBMJMZlDgYCafV5wNokBvCJq9PUJAyVGz7O3vsjVrg?e=aLjLN9; Übersicht BIM Base: https://evolutbaugmbh.sharepoint.com/:b:/s/External/EfS4mJ9nZQpOhASXp0n2kW4B0K7N-vHKx-_6Crp5CxEFeg?e=Qu0M5d; Verbesserungsvorschläge BIM Base: https://forms.office.com/e/pcFhFfi5DW; Anleitung Mengen: https://evolutbaugmbh.sharepoint.com/:b:/s/External/ETgyOLO3JxJEqg9rbaRMLVEBHuWIRtkoMiJN1fISDr-3lw?e=E0LTiQ; Anleitung Eigenschaften: https://evolutbaugmbh.sharepoint.com/:b:/s/External/EQedjNXQkc1Btaftc01yAPUBtND9QzXFSH3-7sie6PGFww?e=wP4uf3; Release Notes: https://evolutbaugmbh.sharepoint.com/:b:/s/External/Eb41lwlDI71MhUVvor2V2mUBSaI-0tQK5U9oJAWxpCINuw?e=NtK3j6

# IfcCovering: Flachdach Typ 02 - Dacheindeckung ESH 155 (3)
In: EG
Classification: Dacheindeckung unter Terrain (BIM Base by Evolut)
01_Leistungen und Kosten - Gebäude: In Abklärung; Elementpreis - CHF: 0; BKP: 224 - Bedachungsarbeiten; eBKP-H_Nr: F01.01; eBKP-H_Beschrieb: Dachabdichtung unter Terrain
02_Mengen - Stärke - m: 0.155; Kote Unterkante: 0; Kote Oberkante: 0.155
03_Bausystem - Umbau-Status: Neubau; Mehrschichtiger Aufbau: Grünfläche; Keramik; Sperrschicht
00_Datenstruktur - BIM Base Version: 4.0.0; Kundenergänzungen Version: v01; Klassifizierung: Dacheindeckung unter Terrain; Klassifizierung Level 0: Bekleidung; Modellierungsrichtlinien: https://evolutbaugmbh.sharepoint.com/:b:/s/External/EciBgBMJMZlDgYCafV5wNokBvCJq9PUJAyVGz7O3vsjVrg?e=aLjLN9; Übersicht BIM Base: https://evolutbaugmbh.sharepoint.com/:b:/s/External/EfS4mJ9nZQpOhASXp0n2kW4B0K7N-vHKx-_6Crp5CxEFeg?e=Qu0M5d; Verbesserungsvorschläge BIM Base: https://forms.office.com/e/pcFhFfi5DW; Anleitung Mengen: https://evolutbaugmbh.sharepoint.com/:b:/s/External/ETgyOLO3JxJEqg9rbaRMLVEBHuWIRtkoMiJN1fISDr-3lw?e=E0LTiQ; Anleitung Eigenschaften: https://evolutbaugmbh.sharepoint.com/:b:/s/External/EQedjNXQkc1Btaftc01yAPUBtND9QzXFSH3-7sie6PGFww?e=wP4uf3; Release Notes: https://evolutbaugmbh.sharepoint.com/:b:/s/External/Eb41lwlDI71MhUVvor2V2mUBSaI-0tQK5U9oJAWxpCINuw?e=NtK3j6
05_Bauablauf - Bau-Nr.: In Abklärung; Bauablauf Etappe: In Abklärung; Bauablauf Verbauungsort: In Abklärung; Bauablauf Start Ausführung: In Abklärung; Bauablauf Ende Ausführung: In Abklärung
Name | Fläche brutto - m2 | Fläche netto - m2 | Volumen netto - m3 | Umfang - m | CAD Werkzeug Typ
Dach-010 | 23.6774 | 23.6774 | 3.67 | 35.127 | Dach
Dach-010 | 22.926 | 22.926 | 3.55353 | 34.127 | Dach
Deckennr.-070 | 107.25 | 106.75 | 16.5462 | 46 | Decke

# IfcCovering: Wandbekleidung Typ 01 15 (25)
Classification: Wandbekleidung Belag Keramik (BIM Base by Evolut); Material: Naturstein
05_Bauablauf - Bau-Nr.: In Abklärung; Bauablauf Etappe: In Abklärung; Bauablauf Verbauungsort: In Abklärung; Bauablauf Start Ausführung: In Abklärung; Bauablauf Ende Ausführung: In Abklärung
03_Bausystem - Feuerwiderstand: In Abklärung; Luftschall: In Abklärung; U-Wert: In Abklärung; Umbau-Status: Neubau; Mehrschichtiger Aufbau: Naturstein
02_Mengen - Stärke - m: 0.015
00_Datenstruktur - BIM Base Version: 4.0.0; Kundenergänzungen Version: v01; CAD Werkzeug Typ: Wand; Klassifizierung: Wandbekleidung Belag Keramik; Klassifizierung Level 0: Bekleidung; Modellierungsrichtlinien: https://evolutbaugmbh.sharepoint.com/:b:/s/External/EciBgBMJMZlDgYCafV5wNokBvCJq9PUJAyVGz7O3vsjVrg?e=aLjLN9; Übersicht BIM Base: https://evolutbaugmbh.sharepoint.com/:b:/s/External/EfS4mJ9nZQpOhASXp0n2kW4B0K7N-vHKx-_6Crp5CxEFeg?e=Qu0M5d; Verbesserungsvorschläge BIM Base: https://forms.office.com/e/pcFhFfi5DW; Anleitung Mengen: https://evolutbaugmbh.sharepoint.com/:b:/s/External/ETgyOLO3JxJEqg9rbaRMLVEBHuWIRtkoMiJN1fISDr-3lw?e=E0LTiQ; Anleitung Eigenschaften: https://evolutbaugmbh.sharepoint.com/:b:/s/External/EQedjNXQkc1Btaftc01yAPUBtND9QzXFSH3-7sie6PGFww?e=wP4uf3; Release Notes: https://evolutbaugmbh.sharepoint.com/:b:/s/External/Eb41lwlDI71MhUVvor2V2mUBSaI-0tQK5U9oJAWxpCINuw?e=NtK3j6
01_Leistungen und Kosten - Gebäude: In Abklärung; Elementpreis - CHF: 0; BKP: 282 - Wandbeläge, Wandverkleidungen; eBKP-H_Nr: G03.02; eBKP-H_Beschrieb: Wandbekleidung
Name | In | Höhe - m | Länge brutto - m | Fläche brutto - m2 | Fläche netto - m2 | Volumen netto - m3 | Kote Unterkante | Kote Oberkante
Wand-014 | 1.OG | 2.145 | 3.848 | 8.25329 | 8.25329 | 0.123799 | 3.05 | 5.195
Wand-014 | 1.OG | 2.145 | 2.22322 | 4.76814 | 4.73664 | 0.0710496 | 3.05 | 5.195
Wand-014 | 1.OG | 2.1 | 3.848 | 8.0808 | 8.0493 | 0.12074 | 3.05 | 5.15
2 x Wand-014 | 1.OG | 2.145 | 0.105 | 0.225225 | 0.19305 | 0.00289575 | 3.05 | 5.195
Wand-014 | 1.OG | 2.1 | 3.76778 | 7.91233 | 7.88083 | 0.118212 | 3.05 | 5.15
Wand-014 | 1.OG | 2.1 | 3.21822 | 6.75827 | 6.72677 | 0.100902 | 3.05 | 5.15
Wand-014 | 1.OG | 2.145 | 1.46147 | 3.13417 | 3.10267 | 0.0465401 | 3.05 | 5.195
Wand-014 | 1.OG | 2.1 | 2.45647 | 5.15858 | 5.12708 | 0.0769062 | 3.05 | 5.15
Wand-014 | 1.OG | 2.145 | 3.76778 | 8.08121 | 8.08121 | 0.121218 | 3.05 | 5.195
Wand-014 | 2.OG | 2.145 | 2.22322 | 4.76814 | 4.73664 | 0.0710496 | 5.95 | 8.095
Wand-014 | 2.OG | 2.1 | 3.848 | 8.0808 | 8.0493 | 0.12074 | 5.95 | 8.05
2 x Wand-014 | 2.OG | 2.145 | 0.105 | 0.225225 | 0.19305 | 0.00289575 | 5.95 | 8.095
Wand-014 | 2.OG | 2.1 | 3.21822 | 6.75827 | 6.72677 | 0.100902 | 5.95 | 8.05
Wand-014 | 2.OG | 2.145 | 3.848 | 8.25329 | 8.25329 | 0.123799 | 5.95 | 8.095
Wand-014 | 2.OG | 2.1 | 3.76778 | 7.91233 | 7.88083 | 0.118212 | 5.95 | 8.05
Wand-014 | 2.OG | 2.145 | 1.46147 | 3.13417 | 3.10267 | 0.0465401 | 5.95 | 8.095
Wand-014 | 2.OG | 2.1 | 2.45647 | 5.15858 | 5.12708 | 0.0769062 | 5.95 | 8.05
Wand-014 | 2.OG | 2.145 | 3.76778 | 8.08121 | 8.08121 | 0.121218 | 5.95 | 8.095
Wand-014 | Attika | 2.145 | 0.105 | 0.225225 | 0.19305 | 0.00289575 | 8.85 | 10.995
Wand-014 | Attika | 2.145 | 3.01478 | 6.46602 | 6.46602 | 0.0969903 | 8.85 | 10.995
Wand-014 | Attika | 2.145 | 1.46147 | 3.13417 | 3.10267 | 0.0465401 | 8.85 | 10.995
Wand-014 | Attika | 2.1 | 3.01478 | 6.33103 | 6.29953 | 0.094493 | 8.85 | 10.95
Wand-014 | Attika | 2.1 | 2.45647 | 5.15858 | 5.12708 | 0.0769062 | 8.85 | 10.95

# IfcCurtainWall: Brüstungsabdeckung 01 250 x 33 (3)
In: Attika
Classification: Fassadenbestandteil Gesimse (BIM Base by Evolut)
01_Leistungen und Kosten - Gebäude: In Abklärung; Elementpreis - CHF: 0; BKP: 215 - Montagebau als Leichtkonstruktionen; eBKP-H_Nr: E02.03; eBKP-H_Beschrieb: Fassadenbekleidung
05_Bauablauf - Bau-Nr.: In Abklärung; Bauablauf Etappe: In Abklärung; Bauablauf Verbauungsort: In Abklärung; Bauablauf Start Ausführung: In Abklärung; Bauablauf Ende Ausführung: In Abklärung
03_Bausystem - Feuerwiderstand: In Abklärung; Umbau-Status: Neubau; Mehrschichtiger Aufbau: Stahl; Stahl
02_Mengen - Breite - m: 0.25; Höhe - m: 0.0325268; Kote Unterkante: 10.17; Kote Oberkante: 10.203
00_Datenstruktur - BIM Base Version: 4.0.0; Kundenergänzungen Version: v01; CAD Werkzeug Typ: Träger; Klassifizierung: Fassadenbestandteil Gesimse; Klassifizierung Level 0: Fassade; Modellierungsrichtlinien: https://evolutbaugmbh.sharepoint.com/:b:/s/External/EciBgBMJMZlDgYCafV5wNokBvCJq9PUJAyVGz7O3vsjVrg?e=aLjLN9; Übersicht BIM Base: https://evolutbaugmbh.sharepoint.com/:b:/s/External/EfS4mJ9nZQpOhASXp0n2kW4B0K7N-vHKx-_6Crp5CxEFeg?e=Qu0M5d; Verbesserungsvorschläge BIM Base: https://forms.office.com/e/pcFhFfi5DW; Anleitung Mengen: https://evolutbaugmbh.sharepoint.com/:b:/s/External/ETgyOLO3JxJEqg9rbaRMLVEBHuWIRtkoMiJN1fISDr-3lw?e=E0LTiQ; Anleitung Eigenschaften: https://evolutbaugmbh.sharepoint.com/:b:/s/External/EQedjNXQkc1Btaftc01yAPUBtND9QzXFSH3-7sie6PGFww?e=wP4uf3; Release Notes: https://evolutbaugmbh.sharepoint.com/:b:/s/External/Eb41lwlDI71MhUVvor2V2mUBSaI-0tQK5U9oJAWxpCINuw?e=NtK3j6
Name | Länge brutto - m = Länge netto - m | Volumen netto - m3
2 x Unterzug-027 | 3.933 | 0.00302238
Unterzug-027 | 12.916 | 0.0100529

# IfcCurtainWall: Fassade Typ 01 - Kompaktfassade 210 (29)
Classification: Kompaktfassade Styropor (BIM Base by Evolut)
01_Leistungen und Kosten - Gebäude: In Abklärung; Elementpreis - CHF: 0; BKP: 226 - Fassadenputze; eBKP-H_Nr: E02.02; eBKP-H_Beschrieb: Aussenwärmedämmsystem
05_Bauablauf - Bau-Nr.: In Abklärung; Bauablauf Etappe: In Abklärung; Bauablauf Verbauungsort: In Abklärung; Bauablauf Start Ausführung: In Abklärung; Bauablauf Ende Ausführung: In Abklärung
03_Bausystem - Feuerwiderstand: In Abklärung; U-Wert: In Abklärung; Umbau-Status: Neubau; Mehrschichtiger Aufbau: Zementputz Aussen; Dämmung Aussen
02_Mengen - Stärke - m: 0.21
00_Datenstruktur - BIM Base Version: 4.0.0; Kundenergänzungen Version: v01; CAD Werkzeug Typ: Wand; Klassifizierung: Kompaktfassade Styropor; Klassifizierung Level 0: Fassade; Modellierungsrichtlinien: https://evolutbaugmbh.sharepoint.com/:b:/s/External/EciBgBMJMZlDgYCafV5wNokBvCJq9PUJAyVGz7O3vsjVrg?e=aLjLN9; Übersicht BIM Base: https://evolutbaugmbh.sharepoint.com/:b:/s/External/EfS4mJ9nZQpOhASXp0n2kW4B0K7N-vHKx-_6Crp5CxEFeg?e=Qu0M5d; Verbesserungsvorschläge BIM Base: https://forms.office.com/e/pcFhFfi5DW; Anleitung Mengen: https://evolutbaugmbh.sharepoint.com/:b:/s/External/ETgyOLO3JxJEqg9rbaRMLVEBHuWIRtkoMiJN1fISDr-3lw?e=E0LTiQ; Anleitung Eigenschaften: https://evolutbaugmbh.sharepoint.com/:b:/s/External/EQedjNXQkc1Btaftc01yAPUBtND9QzXFSH3-7sie6PGFww?e=wP4uf3; Release Notes: https://evolutbaugmbh.sharepoint.com/:b:/s/External/Eb41lwlDI71MhUVvor2V2mUBSaI-0tQK5U9oJAWxpCINuw?e=NtK3j6
Name | In | Höhe - m | Länge brutto - m | Fläche brutto - m2 | Fläche netto - m2 | Volumen netto - m3 | Kote Unterkante | Kote Oberkante
Wand-014 | EG | 3.5 | 5.95 | 20.825 | 14.7305 | 3.08899 | -0.6 | 2.9
Wand-014 | EG | 2.9 | 9.05001 | 26.2454 | 15.7169 | 3.1886 | 0 | 2.9
Wand-014 | EG | 2.9 | 2.83252 | 8.215 | 8.21431 | 1.71708 | 0 | 2.9
Wand-014 | EG | 2.9 | 9 | 26.1 | 24.484 | 5.14163 | 0 | 2.9
Wand-014 | EG | 3.5 | 18.5 | 64.75 | 48.5948 | 10.0649 | -0.6 | 2.9
Wand-014 | EG | 2.65 | 19.9912 | 52.9768 | 36.8566 | 7.73988 | 0 | 2.65
Wand-014 | EG | 2.9 | 2.237 | 7.4095 | 6.4518 | 1.35488 | 0 | 2.9
Wand-014 | 1.OG | 2.9 | 5.95 | 17.255 | 10.5609 | 2.21384 | 2.9 | 5.8
Wand-014 | 1.OG | 2.65 | 9.05 | 26.245 | 14.609 | 2.96189 | 2.9 | 5.8
Wand-014 | 1.OG | 2.9 | 9 | 26.1 | 24.484 | 5.14163 | 2.9 | 5.8
Wand-014 | 1.OG | 2.65 | 19.8662 | 52.6455 | 36.5253 | 7.67032 | 2.9 | 5.55
Wand-014 | 1.OG | 2.9 | 2.84276 | 8.244 | 8.185 | 1.63095 | 2.9 | 5.8
Wand-014 | 1.OG | 2.9 | 2.362 | 7.772 | 6.8498 | 1.43846 | 2.9 | 5.8
Wand-014 | 1.OG | 2.9 | 18.5 | 53.65 | 37.5008 | 7.75917 | 2.9 | 5.8
Wand-014 | 2.OG | 2.9 | 2.7458 | 7.96282 | 7.96282 | 1.66639 | 5.8 | 8.7
Wand-014 | 2.OG | 2.9 | 9 | 26.1 | 24.484 | 5.14163 | 5.8 | 8.7
Wand-014 | 2.OG | 2.9 | 18.5 | 53.65 | 37.5008 | 7.75917 | 5.8 | 8.7
Wand-014 | 2.OG | 3.4 | 2.362 | 9.21201 | 8.03081 | 1.68633 | 5.8 | 9.2
Wand-014 | 2.OG | 2.65 | 19.9632 | 52.9025 | 36.7823 | 7.72428 | 5.8 | 8.45
Wand-014 | 2.OG | 2.9 | 5.95 | 17.255 | 12.0249 | 2.40462 | 5.8 | 8.7
Wand-014 | 2.OG | 2.9 | 9.05 | 26.245 | 16.869 | 3.24969 | 5.8 | 8.7
Wand-014 | Attika | 3.831 | 5.95 | 22.7945 | 17.426 | 3.65884 | 8.7 | 12.531
Wand-014 | Attika | 3.831 | 6.05 | 23.1776 | 17.4748 | 3.66205 | 8.7 | 12.531
Wand-014 | Attika | 3.831 | 9 | 34.479 | 32.863 | 6.90122 | 8.7 | 12.531
Wand-014 | Attika | 3.831 | 22.071 | 85.7723 | 68.1555 | 13.4309 | 8.7 | 12.531
Wand-014 | Attika | 3.831 | 15.5 | 59.3805 | 46.446 | 9.60043 | 8.7 | 12.531
Wand-014 | Attika | 0.5 | 15 | 7.5 | 7.495 | 1.55295 | 8.7 | 9.2
Wand-014 | Attika | 0.5 | 3 | 1.655 | 1.5 | 0.315 | 8.7 | 9.2
Wand-014 | Attika | 0.5 | 3.2458 | 1.7229 | 1.6179 | 0.319759 | 8.7 | 9.2

# IfcCurtainWall: Fassade Typ 02 - Vertikale Schalung 71 (40)
Classification: Hinterlüftete Fassade Holzverkleidung (BIM Base by Evolut)
00_Datenstruktur - BIM Base Version: 4.0.0; Kundenergänzungen Version: v01; CAD Werkzeug Typ: Wand; Klassifizierung: Hinterlüftete Fassade Holzverkleidung; Klassifizierung Level 0: Fassade; Modellierungsrichtlinien: https://evolutbaugmbh.sharepoint.com/:b:/s/External/EciBgBMJMZlDgYCafV5wNokBvCJq9PUJAyVGz7O3vsjVrg?e=aLjLN9; Übersicht BIM Base: https://evolutbaugmbh.sharepoint.com/:b:/s/External/EfS4mJ9nZQpOhASXp0n2kW4B0K7N-vHKx-_6Crp5CxEFeg?e=Qu0M5d; Verbesserungsvorschläge BIM Base: https://forms.office.com/e/pcFhFfi5DW; Anleitung Mengen: https://evolutbaugmbh.sharepoint.com/:b:/s/External/ETgyOLO3JxJEqg9rbaRMLVEBHuWIRtkoMiJN1fISDr-3lw?e=E0LTiQ; Anleitung Eigenschaften: https://evolutbaugmbh.sharepoint.com/:b:/s/External/EQedjNXQkc1Btaftc01yAPUBtND9QzXFSH3-7sie6PGFww?e=wP4uf3; Release Notes: https://evolutbaugmbh.sharepoint.com/:b:/s/External/Eb41lwlDI71MhUVvor2V2mUBSaI-0tQK5U9oJAWxpCINuw?e=NtK3j6
02_Mengen - Stärke - m: 0.071
03_Bausystem - Feuerwiderstand: In Abklärung; Umbau-Status: Neubau; Mehrschichtiger Aufbau: Falzschalung vertikal; Lattenrost horizontal; Lattenrost vertikal
05_Bauablauf - Bau-Nr.: In Abklärung; Bauablauf Etappe: In Abklärung; Bauablauf Verbauungsort: In Abklärung; Bauablauf Start Ausführung: In Abklärung; Bauablauf Ende Ausführung: In Abklärung
01_Leistungen und Kosten - Gebäude: In Abklärung; Elementpreis - CHF: 0; BKP: 215 - Montagebau als Leichtkonstruktionen; eBKP-H_Nr: E02.03; eBKP-H_Beschrieb: Fassadenbekleidung
Name | In | Höhe - m | Länge brutto - m | Fläche brutto - m2 | Fläche netto - m2 | Volumen netto - m3 | Kote Unterkante | Kote Oberkante
Wand-014 | EG | 2.9 | 14.4999 | 42.0497 | 32.0089 | 2.26646 | 0.5 | 3.4
Wand-014 | EG | 2.9 | 12.5 | 36.25 | 29.5481 | 2.09193 | 0.5 | 3.4
AW01 | EG | 2.9 | 29.5 | 85.55 | 62.012 | 4.38931 | 0.5 | 3.4
Wand-014 | EG | 2.9 | 1.5 | 4.35 | 4.18731 | 0.292357 | 0.5 | 3.4
Wand-014 | EG | 2.9 | 1.046 | 3.04618 | 2.97339 | 0.205928 | 0.5 | 3.4
Wand-014 | EG | 2.52 | 12.454 | 31.3841 | 21.8672 | 1.55257 | 0.5 | 3.02
2 x Wand-014 | 1.OG | 2.9 | 1.046 | 3.2393 | 3.1059 | 0.220275 | 3.4 | 6.3
Wand-014 | 1.OG | 2.9 | 12.5 | 36.25 | 30.7 | 2.17485 | 3.4 | 6.3
Wand-014 | 1.OG | 2.9 | 14.4999 | 42.0497 | 33.7724 | 2.3924 | 3.4 | 6.3
Wand-014 | 1.OG | 2.9 | 29.5 | 85.55 | 66.0033 | 4.67536 | 3.4 | 6.3
Wand-014 | 1.OG | 3.08 | 12.908 | 39.7566 | 28.703 | 2.02759 | 3.22 | 6.3
Wand-014 | 1.OG | 3.08 | 3.929 | 12.32 | 12.0366 | 0.853985 | 3.22 | 6.3
Wand-014 | 1.OG | 3.08 | 3.929 | 12.32 | 12.0366 | 0.853684 | 3.22 | 6.3
2 x Wand-014 | 2.OG | 2.9 | 1.046 | 3.0334 | 3.03044 | 0.210219 | 6.3 | 9.2
Wand-014 | 2.OG | 2.9 | 12.5 | 36.25 | 30.6647 | 2.17123 | 6.3 | 9.2
Wand-014 | 2.OG | 2.9 | 14.4999 | 42.0497 | 33.7314 | 2.38818 | 6.3 | 9.2
Wand-014 | 2.OG | 2.9 | 29.5 | 85.55 | 65.92 | 4.66677 | 6.3 | 9.2
Wand-014 | 2.OG | 2.4 | 12.908 | 30.9792 | 20.5272 | 1.45602 | 6.42 | 8.82
2 x Wand-014 | Attika | 2.9 | 1.046 | 3.0334 | 3.03044 | 0.210219 | 9.2 | 12.1
Wand-014 | Attika | 2.78 | 12.908 | 35.8842 | 25.4322 | 1.78695 | 9.32 | 12.1
Wand-014 | Attika | 2.9 | 12.5 | 36.25 | 30.6648 | 2.17121 | 9.2 | 12.1
Wand-014 | Attika | 2.9 | 14.4999 | 42.0497 | 33.7314 | 2.38818 | 9.2 | 12.1
Wand-014 | Attika | 2.9 | 29.5 | 85.55 | 65.92 | 4.66677 | 9.2 | 12.1
Wand-014 | Attika | 3.1 | 3 | 9.3 | 9.22 | 0.65462 | 9 | 12.1
Wand-014 | Dachaufsicht | 3.66754 | 15 | 35.1273 | 15.6391 | 1.10595 | 12.1 | 15.768
Wand-014 | Dachaufsicht | 1.22833 | 17.5 | 21.5863 | 20.9767 | 1.5015 | 12.1 | 13.328
Wand-014 | Dachaufsicht | 1.72837 | 10.04 | 17.3528 | 17.3093 | 1.15836 | 12.531 | 14.259
Wand-014 | Dachaufsicht | 3.95811 | 12.5 | 34.7227 | 34.6616 | 2.45751 | 12.1 | 16.058
Wand-014 | Dachaufsicht | 0.822717 | 2.031 | 1.67094 | 1.65982 | 0.116886 | 12.531 | 13.354
Wand-014 | Dachaufsicht | 1.72837 | 2.469 | 3.62518 | 3.56677 | 0.234565 | 12.531 | 14.259
Wand-014 | Dachaufsicht | 1.26072 | 29.5 | 37.1913 | 37.0814 | 2.62564 | 12.1 | 13.361
3 x Wand-014 | Dachaufsicht | 2.00419 | 5.59824 | 4.22852 | 4.19692 | 0.295169 | 13.743 | 15.747
Wand-014 | Dachaufsicht | 2.00419 | 5.59824 | 4.33506 | 4.33506 | 0.305278 | 13.743 | 15.747
Wand-014 | Dachaufsicht | 1.51053 | 8.15 | 12.2564 | 7.20742 | 0.504932 | 13.743 | 15.254
Wand-014 | Dachaufsicht | 1.51053 | 8.15 | 12.2564 | 7.17584 | 0.502395 | 13.743 | 15.254

# IfcCurtainWall: Fassade Typ 03 - Horizontale Schalung 46 (6)
In: Attika
Classification: Hinterlüftete Fassade Holzverkleidung (BIM Base by Evolut)
01_Leistungen und Kosten - Gebäude: In Abklärung; Elementpreis - CHF: 0; BKP: 215 - Montagebau als Leichtkonstruktionen; eBKP-H_Nr: E02.03; eBKP-H_Beschrieb: Fassadenbekleidung
05_Bauablauf - Bau-Nr.: In Abklärung; Bauablauf Etappe: In Abklärung; Bauablauf Verbauungsort: In Abklärung; Bauablauf Start Ausführung: In Abklärung; Bauablauf Ende Ausführung: In Abklärung
02_Mengen - Stärke - m: 0.046; Kote Oberkante: 10.2
00_Datenstruktur - BIM Base Version: 4.0.0; Kundenergänzungen Version: v01; CAD Werkzeug Typ: Wand; Klassifizierung: Hinterlüftete Fassade Holzverkleidung; Klassifizierung Level 0: Fassade; Modellierungsrichtlinien: https://evolutbaugmbh.sharepoint.com/:b:/s/External/EciBgBMJMZlDgYCafV5wNokBvCJq9PUJAyVGz7O3vsjVrg?e=aLjLN9; Übersicht BIM Base: https://evolutbaugmbh.sharepoint.com/:b:/s/External/EfS4mJ9nZQpOhASXp0n2kW4B0K7N-vHKx-_6Crp5CxEFeg?e=Qu0M5d; Verbesserungsvorschläge BIM Base: https://forms.office.com/e/pcFhFfi5DW; Anleitung Mengen: https://evolutbaugmbh.sharepoint.com/:b:/s/External/ETgyOLO3JxJEqg9rbaRMLVEBHuWIRtkoMiJN1fISDr-3lw?e=E0LTiQ; Anleitung Eigenschaften: https://evolutbaugmbh.sharepoint.com/:b:/s/External/EQedjNXQkc1Btaftc01yAPUBtND9QzXFSH3-7sie6PGFww?e=wP4uf3; Release Notes: https://evolutbaugmbh.sharepoint.com/:b:/s/External/Eb41lwlDI71MhUVvor2V2mUBSaI-0tQK5U9oJAWxpCINuw?e=NtK3j6
03_Bausystem - Feuerwiderstand: In Abklärung; Umbau-Status: Neubau; Mehrschichtiger Aufbau: Falzschalung horizontal; Lattenrost vertikal
Name | Höhe - m | Länge brutto - m | Fläche brutto - m2 | Fläche netto - m2 | Volumen netto - m3 | Kote Unterkante
Wand-017 | 0.88 | 12.516 | 11.0141 | 10.9886 | 0.504745 | 9.32
Wand-017 | 1 | 12.508 | 12.508 | 12.508 | 0.575368 | 9.2
2 x Wand-017 | 1 | 3.7289 | 3.7289 | 3.7289 | 0.171529 | 9.2
Wand-017 | 0.88 | 3.71195 | 3.26652 | 3.263 | 0.149776 | 9.32
Wand-017 | 0.88 | 3.71195 | 3.26652 | 3.24452 | 0.148852 | 9.32

# IfcCurtainWall: Fassadentrennblech 01 80 x 71 (20)
Classification: Fassadenbestandteil Trennblech (BIM Base by Evolut); Material: Stahl
01_Leistungen und Kosten - Gebäude: In Abklärung; Elementpreis - CHF: 0; BKP: 215 - Montagebau als Leichtkonstruktionen; eBKP-H_Nr: E02.03; eBKP-H_Beschrieb: Fassadenbekleidung
05_Bauablauf - Bau-Nr.: In Abklärung; Bauablauf Etappe: In Abklärung; Bauablauf Verbauungsort: In Abklärung; Bauablauf Start Ausführung: In Abklärung; Bauablauf Ende Ausführung: In Abklärung
03_Bausystem - Feuerwiderstand: In Abklärung; Umbau-Status: Neubau; Mehrschichtiger Aufbau: Stahl
02_Mengen - Breite - m: 0.0801048; Höhe - m: 0.0706509
00_Datenstruktur - BIM Base Version: 4.0.0; Kundenergänzungen Version: v01; CAD Werkzeug Typ: Träger; Klassifizierung: Fassadenbestandteil Trennblech; Klassifizierung Level 0: Fassade; Modellierungsrichtlinien: https://evolutbaugmbh.sharepoint.com/:b:/s/External/EciBgBMJMZlDgYCafV5wNokBvCJq9PUJAyVGz7O3vsjVrg?e=aLjLN9; Übersicht BIM Base: https://evolutbaugmbh.sharepoint.com/:b:/s/External/EfS4mJ9nZQpOhASXp0n2kW4B0K7N-vHKx-_6Crp5CxEFeg?e=Qu0M5d; Verbesserungsvorschläge BIM Base: https://forms.office.com/e/pcFhFfi5DW; Anleitung Mengen: https://evolutbaugmbh.sharepoint.com/:b:/s/External/ETgyOLO3JxJEqg9rbaRMLVEBHuWIRtkoMiJN1fISDr-3lw?e=E0LTiQ; Anleitung Eigenschaften: https://evolutbaugmbh.sharepoint.com/:b:/s/External/EQedjNXQkc1Btaftc01yAPUBtND9QzXFSH3-7sie6PGFww?e=wP4uf3; Release Notes: https://evolutbaugmbh.sharepoint.com/:b:/s/External/Eb41lwlDI71MhUVvor2V2mUBSaI-0tQK5U9oJAWxpCINuw?e=NtK3j6
Name | In | Länge brutto - m | Länge netto - m | Volumen netto - m3 | Kote Unterkante | Kote Oberkante
Unterzug-032 | EG | 12.5091 | 12.5091 | 0.00496876 | 3.19 | 3.261
2 x Unterzug-032 | EG | 1.0501 | 1.0501 | 0.000402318 | 3.19 | 3.261
Unterzug-032 | EG | 29.5182 | 29.5182 | 0.0117308 | 3.19 | 3.261
Unterzug-032 | EG | 14.509 | 14.509 | 0.00576572 | 3.19 | 3.261
Unterzug-032 | 1.OG | 12.5091 | 12.5091 | 0.00496876 | 6.272 | 6.343
2 x Unterzug-032 | 1.OG | 1.0551 | 1.22266 | 0.000437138 | 6.272 | 6.343
Unterzug-032 | 1.OG | 29.5182 | 29.5182 | 0.0117308 | 6.272 | 6.343
Unterzug-032 | 1.OG | 14.509 | 14.509 | 0.00576572 | 6.272 | 6.343
Unterzug-032 | 2.OG | 12.4691 | 12.4691 | 0.00495282 | 9.172 | 9.243
2 x Unterzug-032 | 2.OG | 1.0551 | 1.0551 | 0.00040431 | 9.172 | 9.243
Unterzug-032 | 2.OG | 29.5182 | 29.5182 | 0.0117308 | 9.172 | 9.243
Unterzug-032 | 2.OG | 14.509 | 14.509 | 0.00576546 | 9.172 | 9.243
Unterzug-032 | Attika | 12.5091 | 12.5091 | 0.00496876 | 12.531 | 12.602
Unterzug-032 | Attika | 29.5182 | 29.5182 | 0.0117308 | 12.531 | 12.602
2 x Unterzug-032 | Attika | 1.7381 | 1.7381 | 0.000676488 | 12.531 | 12.602
Unterzug-032 | Attika | 17.5091 | 17.5091 | 0.00696122 | 12.531 | 12.602

# IfcDiscreteAccessory: Bewehrung 20 x 250 (6)
In: Dachaufsicht
Classification: Bewehrung Kragplattenanschluss (BIM Base by Evolut); Material: Bewehrung
01_Leistungen und Kosten - Gebäude: In Abklärung; BKP: 211 - Baumeisterarbeiten; Elementpreis - CHF: 0
05_Bauablauf - Bau-Nr.: In Abklärung; Bauablauf Etappe: In Abklärung; Bauablauf Verbauungsort: In Abklärung; Bauablauf Start Ausführung: In Abklärung; Bauablauf Ende Ausführung: In Abklärung
03_Bausystem - Tragende Funktion: In Abklärung; Umbau-Status: Neubau; Mehrschichtiger Aufbau: Bewehrung
02_Mengen - Breite - m: 0.02; Höhe - m: 0.25; Kote Unterkante: 11.35; Kote Oberkante: 11.6
00_Datenstruktur - BIM Base Version: 4.0.0; Kundenergänzungen Version: v01; CAD Werkzeug Typ: Träger; Klassifizierung: Bewehrung Kragplattenanschluss; Klassifizierung Level 0: Baukomponente; Modellierungsrichtlinien: https://evolutbaugmbh.sharepoint.com/:b:/s/External/EciBgBMJMZlDgYCafV5wNokBvCJq9PUJAyVGz7O3vsjVrg?e=aLjLN9; Übersicht BIM Base: https://evolutbaugmbh.sharepoint.com/:b:/s/External/EfS4mJ9nZQpOhASXp0n2kW4B0K7N-vHKx-_6Crp5CxEFeg?e=Qu0M5d; Verbesserungsvorschläge BIM Base: https://forms.office.com/e/pcFhFfi5DW; Anleitung Mengen: https://evolutbaugmbh.sharepoint.com/:b:/s/External/ETgyOLO3JxJEqg9rbaRMLVEBHuWIRtkoMiJN1fISDr-3lw?e=E0LTiQ; Anleitung Eigenschaften: https://evolutbaugmbh.sharepoint.com/:b:/s/External/EQedjNXQkc1Btaftc01yAPUBtND9QzXFSH3-7sie6PGFww?e=wP4uf3; Release Notes: https://evolutbaugmbh.sharepoint.com/:b:/s/External/Eb41lwlDI71MhUVvor2V2mUBSaI-0tQK5U9oJAWxpCINuw?e=NtK3j6
Name | Länge brutto - m
Unterzug-029 | 3.625
Unterzug-030 | 2.511
Unterzug-029 | 2.29
2 x Unterzug-029 | 3.5
Unterzug-029 | 3.915

# IfcDiscreteAccessory: Bewehrung 80 x 250 (6)
Classification: Bewehrung Kragplattenanschluss (BIM Base by Evolut); Material: Bewehrung
01_Leistungen und Kosten - Gebäude: In Abklärung; BKP: 211 - Baumeisterarbeiten; Elementpreis - CHF: 0
05_Bauablauf - Bau-Nr.: In Abklärung; Bauablauf Etappe: In Abklärung; Bauablauf Verbauungsort: In Abklärung; Bauablauf Start Ausführung: In Abklärung; Bauablauf Ende Ausführung: In Abklärung
03_Bausystem - Tragende Funktion: In Abklärung; Umbau-Status: Neubau; Mehrschichtiger Aufbau: Bewehrung
02_Mengen - Breite - m: 0.08; Höhe - m: 0.25
00_Datenstruktur - BIM Base Version: 4.0.0; Kundenergänzungen Version: v01; CAD Werkzeug Typ: Träger; Klassifizierung: Bewehrung Kragplattenanschluss; Klassifizierung Level 0: Baukomponente; Modellierungsrichtlinien: https://evolutbaugmbh.sharepoint.com/:b:/s/External/EciBgBMJMZlDgYCafV5wNokBvCJq9PUJAyVGz7O3vsjVrg?e=aLjLN9; Übersicht BIM Base: https://evolutbaugmbh.sharepoint.com/:b:/s/External/EfS4mJ9nZQpOhASXp0n2kW4B0K7N-vHKx-_6Crp5CxEFeg?e=Qu0M5d; Verbesserungsvorschläge BIM Base: https://forms.office.com/e/pcFhFfi5DW; Anleitung Mengen: https://evolutbaugmbh.sharepoint.com/:b:/s/External/ETgyOLO3JxJEqg9rbaRMLVEBHuWIRtkoMiJN1fISDr-3lw?e=E0LTiQ; Anleitung Eigenschaften: https://evolutbaugmbh.sharepoint.com/:b:/s/External/EQedjNXQkc1Btaftc01yAPUBtND9QzXFSH3-7sie6PGFww?e=wP4uf3; Release Notes: https://evolutbaugmbh.sharepoint.com/:b:/s/External/Eb41lwlDI71MhUVvor2V2mUBSaI-0tQK5U9oJAWxpCINuw?e=NtK3j6
Name | In | Länge brutto - m | Kote Unterkante | Kote Oberkante
Unterzug-029 | EG | 19.9912 | 2.65 | 2.9
Unterzug-028 | EG | 14.58 | 2.65 | 2.9
Unterzug-029 | 1.OG | 19.8662 | 5.55 | 5.8
Unterzug-028 | 1.OG | 14.58 | 5.55 | 5.8
Unterzug-028 | 2.OG | 14.58 | 8.45 | 8.7
Unterzug-029 | 2.OG | 19.5632 | 8.45 | 8.7

# IfcDiscreteAccessory: Träger Typ 01- L90X75X9 75 x 90 (4)
Classification: Bewehrung Kragplattenanschluss (BIM Base by Evolut); Material: Stahl
01_Leistungen und Kosten - Gebäude: In Abklärung; BKP: 211 - Baumeisterarbeiten; Elementpreis - CHF: 0
05_Bauablauf - Bau-Nr.: In Abklärung; Bauablauf Etappe: In Abklärung; Bauablauf Verbauungsort: In Abklärung; Bauablauf Start Ausführung: In Abklärung; Bauablauf Ende Ausführung: In Abklärung
03_Bausystem - Tragende Funktion: In Abklärung; Umbau-Status: Neubau; Mehrschichtiger Aufbau: Stahl
00_Datenstruktur - BIM Base Version: 4.0.0; Kundenergänzungen Version: v01; CAD Werkzeug Typ: Träger; Klassifizierung: Bewehrung Kragplattenanschluss; Klassifizierung Level 0: Baukomponente; Modellierungsrichtlinien: https://evolutbaugmbh.sharepoint.com/:b:/s/External/EciBgBMJMZlDgYCafV5wNokBvCJq9PUJAyVGz7O3vsjVrg?e=aLjLN9; Übersicht BIM Base: https://evolutbaugmbh.sharepoint.com/:b:/s/External/EfS4mJ9nZQpOhASXp0n2kW4B0K7N-vHKx-_6Crp5CxEFeg?e=Qu0M5d; Verbesserungsvorschläge BIM Base: https://forms.office.com/e/pcFhFfi5DW; Anleitung Mengen: https://evolutbaugmbh.sharepoint.com/:b:/s/External/ETgyOLO3JxJEqg9rbaRMLVEBHuWIRtkoMiJN1fISDr-3lw?e=E0LTiQ; Anleitung Eigenschaften: https://evolutbaugmbh.sharepoint.com/:b:/s/External/EQedjNXQkc1Btaftc01yAPUBtND9QzXFSH3-7sie6PGFww?e=wP4uf3; Release Notes: https://evolutbaugmbh.sharepoint.com/:b:/s/External/Eb41lwlDI71MhUVvor2V2mUBSaI-0tQK5U9oJAWxpCINuw?e=NtK3j6
02_Mengen - Breite - m: 0.075; Höhe - m: 0.09
Name | In | Länge brutto - m | Kote Unterkante | Kote Oberkante
Unterzug-026 | EG | 9.596 | 3.153 | 3.243
Unterzug-026 | EG | 2.096 | 3.153 | 3.243
Unterzug-026 | 1.OG | 9.596 | 6.053 | 6.143
Unterzug-026 | 1.OG | 2.096 | 6.053 | 6.143

# IfcDistributionPort (12)
FlowDirection: SOURCEANDSINK
Name
6 x Rohr 2
6 x Rohr 1

# IfcDoor: Eingangstür Typ 01 (4)
Type - OperationType: SINGLE_SWING_LEFT
OverallWidth: 1200 mm; Classification: Innentür (BIM Base by Evolut)
01_Leistungen und Kosten - Gebäude: In Abklärung; Elementpreis - CHF: 0; BKP: 273 - Schreinerarbeiten; eBKP-H_Nr: G01.05; eBKP-H_Beschrieb: Innentür
05_Bauablauf - Bau-Nr.: In Abklärung; Bauablauf Etappe: In Abklärung; Bauablauf Verbauungsort: In Abklärung; Bauablauf Start Ausführung: In Abklärung; Bauablauf Ende Ausführung: In Abklärung
03_Bausystem - Feuerwiderstand: In Abklärung; Umbau-Status: Neubau; Wand Typ: Innenwand Typ 10
Tür - Tür Rahmen: In Abklärung; Tür Blatt: In Abklärung; Tür Kanten: In Abklärung; Tür Dichtung: In Abklärung; Tür Drücker: In Abklärung; Tür Schutzbeschlag: In Abklärung; Tür Bänder: In Abklärung; Tür Absenkdichtung: In Abklärung; Tür Türspion: In Abklärung; Tür Schliesssystem: In Abklärung; Tür Schallschutz - R'w: In Abklärung; Tür Einbruchschutz: In Abklärung; Tür Rauchschutz: In Abklärung; Tür Strahlenschutz: In Abklärung; Tür Sicherheitsglas Personenschutz: In Abklärung; Tür Türschliesser: In Abklärung; Tür Blatt Farbe innen: RAL / NCS; Tür Blatt Farbe aussen: RAL / NCS; Tür Rahmen Farbe: RAL / NCS; Tür Rahmen Überstand aussen - cm: In Abklärung; Tür Rahmen Überstand innen - cm: In Abklärung; Tür Typ: In Abklärung
00_Datenstruktur - BIM Base Version: 4.0.0; Kundenergänzungen Version: v01; CAD Werkzeug Typ: Tür; Klassifizierung: Innentür; Klassifizierung Level 0: Tür; Modellierungsrichtlinien: https://evolutbaugmbh.sharepoint.com/:b:/s/External/EciBgBMJMZlDgYCafV5wNokBvCJq9PUJAyVGz7O3vsjVrg?e=aLjLN9; Übersicht BIM Base: https://evolutbaugmbh.sharepoint.com/:b:/s/External/EfS4mJ9nZQpOhASXp0n2kW4B0K7N-vHKx-_6Crp5CxEFeg?e=Qu0M5d; Verbesserungsvorschläge BIM Base: https://forms.office.com/e/pcFhFfi5DW; Anleitung Mengen: https://evolutbaugmbh.sharepoint.com/:b:/s/External/ETgyOLO3JxJEqg9rbaRMLVEBHuWIRtkoMiJN1fISDr-3lw?e=E0LTiQ; Anleitung Eigenschaften: https://evolutbaugmbh.sharepoint.com/:b:/s/External/EQedjNXQkc1Btaftc01yAPUBtND9QzXFSH3-7sie6PGFww?e=wP4uf3; Release Notes: https://evolutbaugmbh.sharepoint.com/:b:/s/External/Eb41lwlDI71MhUVvor2V2mUBSaI-0tQK5U9oJAWxpCINuw?e=NtK3j6
02_Mengen - Breite Lichtmass - m: 1.2; Höhe Lichtmass - m: 2.1; Fläche Lichtmass - m2: 2.52; Höhe Mauerlicht - m: 2.1; Breite Mauerlicht - m: 1.2; Fläche Mauerlicht - m2: 2.52; Wandstärke - m: 0.31
Name | In | OverallHeight (mm) | Delta Höhe unten - m | Delta Hohe oben - m | Kote Brüstung fertig - m = Kote Brüstung roh - m | Kote Sturz fertig - m = Kote Sturz roh - m
Tür-010 | EG | 2320 | 2.77556e-17 | -2.77556e-17 | 0.22 | 2.32
Tür-011 | 1.OG | 2100 | 0 | 0 | 2.9 | 5
Tür-011 | 2.OG | 2100 | 0 | 0 | 5.8 | 7.9
Tür-011 | Attika | 2100 | 0 | 0 | 8.7 | 10.8

# IfcDoor: Eingangstür Typ 01 (5)
Type - OperationType: SINGLE_SWING_RIGHT
OverallWidth: 1200 mm; Classification: Innentür (BIM Base by Evolut)
01_Leistungen und Kosten - Gebäude: In Abklärung; Elementpreis - CHF: 0; BKP: 273 - Schreinerarbeiten; eBKP-H_Nr: G01.05; eBKP-H_Beschrieb: Innentür
05_Bauablauf - Bau-Nr.: In Abklärung; Bauablauf Etappe: In Abklärung; Bauablauf Verbauungsort: In Abklärung; Bauablauf Start Ausführung: In Abklärung; Bauablauf Ende Ausführung: In Abklärung
03_Bausystem - Feuerwiderstand: In Abklärung; Umbau-Status: Neubau
00_Datenstruktur - BIM Base Version: 4.0.0; Kundenergänzungen Version: v01; CAD Werkzeug Typ: Tür; Klassifizierung: Innentür; Klassifizierung Level 0: Tür; Modellierungsrichtlinien: https://evolutbaugmbh.sharepoint.com/:b:/s/External/EciBgBMJMZlDgYCafV5wNokBvCJq9PUJAyVGz7O3vsjVrg?e=aLjLN9; Übersicht BIM Base: https://evolutbaugmbh.sharepoint.com/:b:/s/External/EfS4mJ9nZQpOhASXp0n2kW4B0K7N-vHKx-_6Crp5CxEFeg?e=Qu0M5d; Verbesserungsvorschläge BIM Base: https://forms.office.com/e/pcFhFfi5DW; Anleitung Mengen: https://evolutbaugmbh.sharepoint.com/:b:/s/External/ETgyOLO3JxJEqg9rbaRMLVEBHuWIRtkoMiJN1fISDr-3lw?e=E0LTiQ; Anleitung Eigenschaften: https://evolutbaugmbh.sharepoint.com/:b:/s/External/EQedjNXQkc1Btaftc01yAPUBtND9QzXFSH3-7sie6PGFww?e=wP4uf3; Release Notes: https://evolutbaugmbh.sharepoint.com/:b:/s/External/Eb41lwlDI71MhUVvor2V2mUBSaI-0tQK5U9oJAWxpCINuw?e=NtK3j6
02_Mengen - Breite Lichtmass - m: 1.2; Höhe Lichtmass - m: 2.1; Fläche Lichtmass - m2: 2.52; Höhe Mauerlicht - m: 2.1; Breite Mauerlicht - m: 1.2; Fläche Mauerlicht - m2: 2.52
Tür - Tür Rahmen: In Abklärung; Tür Blatt: In Abklärung; Tür Kanten: In Abklärung; Tür Dichtung: In Abklärung; Tür Drücker: In Abklärung; Tür Schutzbeschlag: In Abklärung; Tür Bänder: In Abklärung; Tür Absenkdichtung: In Abklärung; Tür Türspion: In Abklärung; Tür Schliesssystem: In Abklärung; Tür Schallschutz - R'w: In Abklärung; Tür Einbruchschutz: In Abklärung; Tür Rauchschutz: In Abklärung; Tür Strahlenschutz: In Abklärung; Tür Sicherheitsglas Personenschutz: In Abklärung; Tür Türschliesser: In Abklärung; Tür Blatt Farbe innen: RAL / NCS; Tür Blatt Farbe aussen: RAL / NCS; Tür Rahmen Farbe: RAL / NCS; Tür Rahmen Überstand aussen - cm: In Abklärung; Tür Rahmen Überstand innen - cm: In Abklärung; Tür Typ: In Abklärung
Name | In | OverallHeight (mm) | Wand Typ | Delta Höhe unten - m | Delta Hohe oben - m | Wandstärke - m | Kote Brüstung fertig - m = Kote Brüstung roh - m | Kote Sturz fertig - m = Kote Sturz roh - m
Tür-010 | EG | 2100 | Innenwand Typ 06 | 2.17375e-17 | -2.17375e-17 | 0.3 | 5.19885e-08 | 2.1
Tür-010 | 1.OG | 2750 | Innenwand Typ 10 | 0 | 0 | 0.31 | 3.55 | 5.65
Tür-012 | 2.OG | 2750 | Innenwand Typ 10 | 0 | 0 | 0.31 | 6.45 | 8.55
Tür-011 | 2.OG | 2250 | Innenwand Typ 10 | 0 | 0 | 0.31 | 5.95 | 8.05
Tür-011 | Attika | 2250 | Innenwand Typ 10 | 0 | 0 | 0.31 | 8.85 | 10.95

# IfcDoor: Eingangstür Typ 02 (2)
Type - OperationType: SINGLE_SWING_RIGHT
Classification: Innentür (BIM Base by Evolut)
01_Leistungen und Kosten - Gebäude: In Abklärung; Elementpreis - CHF: 0; BKP: 273 - Schreinerarbeiten; eBKP-H_Nr: G01.05; eBKP-H_Beschrieb: Innentür
05_Bauablauf - Bau-Nr.: In Abklärung; Bauablauf Etappe: In Abklärung; Bauablauf Verbauungsort: In Abklärung; Bauablauf Start Ausführung: In Abklärung; Bauablauf Ende Ausführung: In Abklärung
Tür - Tür Rahmen: In Abklärung; Tür Blatt: In Abklärung; Tür Kanten: In Abklärung; Tür Dichtung: In Abklärung; Tür Drücker: In Abklärung; Tür Schutzbeschlag: In Abklärung; Tür Bänder: In Abklärung; Tür Absenkdichtung: In Abklärung; Tür Türspion: In Abklärung; Tür Schliesssystem: In Abklärung; Tür Schallschutz - R'w: In Abklärung; Tür Einbruchschutz: In Abklärung; Tür Rauchschutz: In Abklärung; Tür Strahlenschutz: In Abklärung; Tür Sicherheitsglas Personenschutz: In Abklärung; Tür Türschliesser: In Abklärung; Tür Blatt Farbe innen: RAL / NCS; Tür Blatt Farbe aussen: RAL / NCS; Tür Rahmen Farbe: RAL / NCS; Tür Rahmen Überstand aussen - cm: In Abklärung; Tür Rahmen Überstand innen - cm: In Abklärung; Tür Typ: In Abklärung
02_Mengen - Höhe Lichtmass - m: 2.1; Höhe Mauerlicht - m: 2.1
00_Datenstruktur - BIM Base Version: 4.0.0; Kundenergänzungen Version: v01; CAD Werkzeug Typ: Tür; Klassifizierung: Innentür; Klassifizierung Level 0: Tür; Modellierungsrichtlinien: https://evolutbaugmbh.sharepoint.com/:b:/s/External/EciBgBMJMZlDgYCafV5wNokBvCJq9PUJAyVGz7O3vsjVrg?e=aLjLN9; Übersicht BIM Base: https://evolutbaugmbh.sharepoint.com/:b:/s/External/EfS4mJ9nZQpOhASXp0n2kW4B0K7N-vHKx-_6Crp5CxEFeg?e=Qu0M5d; Verbesserungsvorschläge BIM Base: https://forms.office.com/e/pcFhFfi5DW; Anleitung Mengen: https://evolutbaugmbh.sharepoint.com/:b:/s/External/ETgyOLO3JxJEqg9rbaRMLVEBHuWIRtkoMiJN1fISDr-3lw?e=E0LTiQ; Anleitung Eigenschaften: https://evolutbaugmbh.sharepoint.com/:b:/s/External/EQedjNXQkc1Btaftc01yAPUBtND9QzXFSH3-7sie6PGFww?e=wP4uf3; Release Notes: https://evolutbaugmbh.sharepoint.com/:b:/s/External/Eb41lwlDI71MhUVvor2V2mUBSaI-0tQK5U9oJAWxpCINuw?e=NtK3j6
03_Bausystem - Feuerwiderstand: In Abklärung; Umbau-Status: Neubau
Name | In | OverallHeight (mm) | OverallWidth (mm) | Breite Lichtmass - m = Breite Mauerlicht - m | Fläche Lichtmass - m2 = Fläche Mauerlicht - m2 | Delta Höhe unten - m | Delta Hohe oben - m | Wandstärke - m | Kote Brüstung fertig - m | Kote Brüstung roh - m | Kote Sturz fertig - m | Kote Sturz roh - m | Wand Typ
Tür-011 | 1.OG | 2250 | 1200 | 1.2 | 2.52 | 0 | 0 | 0.31 | 3.05 | 3.05 | 5.15 | 5.15 | Innenwand Typ 10
Tür-009 | Attika | 2220 | 1100 | 1.1 | 2.31 | 0.12 | -0.12 | 0.3 | 9.32 | 9.2 | 11.42 | 11.3 | Innenwand Typ 06

# IfcDoor: Innentor Typ 01, Tür-008
In: UG
Type - OperationType: USERDEFINED
OverallHeight: 3000 mm; OverallWidth: 4300 mm; Classification: Innentor (BIM Base by Evolut)
01_Leistungen und Kosten - Gebäude: In Abklärung; Elementpreis - CHF: 0; BKP: 221 - Fenster, Aussentüren, Tore; eBKP-H_Nr: G01.06; eBKP-H_Beschrieb: Innentor
05_Bauablauf - Bau-Nr.: In Abklärung; Bauablauf Etappe: In Abklärung; Bauablauf Verbauungsort: In Abklärung; Bauablauf Start Ausführung: In Abklärung; Bauablauf Ende Ausführung: In Abklärung
03_Bausystem - Feuerwiderstand: In Abklärung; Umbau-Status: Neubau; Wand Typ: Innenwand Typ 07
02_Mengen - Breite Lichtmass - m: 4.3; Höhe Lichtmass - m: 2.4; Fläche Lichtmass - m2: 10.32; Höhe Mauerlicht - m: 2.4; Breite Mauerlicht - m: 4.3; Fläche Mauerlicht - m2: 10.32; Delta Höhe unten - m: 0; Delta Hohe oben - m: 0; Wandstärke - m: 0.301; Kote Brüstung fertig - m: -3.3; Kote Brüstung roh - m: -3.3; Kote Sturz fertig - m: -0.9; Kote Sturz roh - m: -0.9
00_Datenstruktur - BIM Base Version: 4.0.0; Kundenergänzungen Version: v01; CAD Werkzeug Typ: Tür; Klassifizierung: Innentor; Klassifizierung Level 0: Tor; Modellierungsrichtlinien: https://evolutbaugmbh.sharepoint.com/:b:/s/External/EciBgBMJMZlDgYCafV5wNokBvCJq9PUJAyVGz7O3vsjVrg?e=aLjLN9; Übersicht BIM Base: https://evolutbaugmbh.sharepoint.com/:b:/s/External/EfS4mJ9nZQpOhASXp0n2kW4B0K7N-vHKx-_6Crp5CxEFeg?e=Qu0M5d; Verbesserungsvorschläge BIM Base: https://forms.office.com/e/pcFhFfi5DW; Anleitung Mengen: https://evolutbaugmbh.sharepoint.com/:b:/s/External/ETgyOLO3JxJEqg9rbaRMLVEBHuWIRtkoMiJN1fISDr-3lw?e=E0LTiQ; Anleitung Eigenschaften: https://evolutbaugmbh.sharepoint.com/:b:/s/External/EQedjNXQkc1Btaftc01yAPUBtND9QzXFSH3-7sie6PGFww?e=wP4uf3; Release Notes: https://evolutbaugmbh.sharepoint.com/:b:/s/External/Eb41lwlDI71MhUVvor2V2mUBSaI-0tQK5U9oJAWxpCINuw?e=NtK3j6
Tor - Tor Typ: In Abklärung

# IfcDoor: Teleskoptür Typ 01 (5)
Type - ElementType: Teleskoptür Typ 01; OperationType: DOUBLE_DOOR_SLIDING
OverallWidth: 1200 mm; Classification: Innentür (BIM Base by Evolut)
01_Leistungen und Kosten - Gebäude: In Abklärung; Elementpreis - CHF: 0; BKP: 273 - Schreinerarbeiten; eBKP-H_Nr: G01.05; eBKP-H_Beschrieb: Innentür
05_Bauablauf - Bau-Nr.: In Abklärung; Bauablauf Etappe: In Abklärung; Bauablauf Verbauungsort: In Abklärung; Bauablauf Start Ausführung: In Abklärung; Bauablauf Ende Ausführung: In Abklärung
03_Bausystem - Feuerwiderstand: In Abklärung; Umbau-Status: Neubau; Wand Typ: Innenwand Typ 06
02_Mengen - Breite Lichtmass - m: 1.2; Höhe Lichtmass - m: 2.05; Fläche Lichtmass - m2: 2.46; Höhe Mauerlicht - m: 2.05; Breite Mauerlicht - m: 1.2; Fläche Mauerlicht - m2: 2.46; Delta Höhe unten - m: 0.04; Delta Hohe oben - m: -0.04; Wandstärke - m: 0.3
00_Datenstruktur - BIM Base Version: 4.0.0; Kundenergänzungen Version: v01; CAD Werkzeug Typ: Tür; Klassifizierung: Innentür; Klassifizierung Level 0: Tür; Modellierungsrichtlinien: https://evolutbaugmbh.sharepoint.com/:b:/s/External/EciBgBMJMZlDgYCafV5wNokBvCJq9PUJAyVGz7O3vsjVrg?e=aLjLN9; Übersicht BIM Base: https://evolutbaugmbh.sharepoint.com/:b:/s/External/EfS4mJ9nZQpOhASXp0n2kW4B0K7N-vHKx-_6Crp5CxEFeg?e=Qu0M5d; Verbesserungsvorschläge BIM Base: https://forms.office.com/e/pcFhFfi5DW; Anleitung Mengen: https://evolutbaugmbh.sharepoint.com/:b:/s/External/ETgyOLO3JxJEqg9rbaRMLVEBHuWIRtkoMiJN1fISDr-3lw?e=E0LTiQ; Anleitung Eigenschaften: https://evolutbaugmbh.sharepoint.com/:b:/s/External/EQedjNXQkc1Btaftc01yAPUBtND9QzXFSH3-7sie6PGFww?e=wP4uf3; Release Notes: https://evolutbaugmbh.sharepoint.com/:b:/s/External/Eb41lwlDI71MhUVvor2V2mUBSaI-0tQK5U9oJAWxpCINuw?e=NtK3j6
Tür - Tür Rahmen: In Abklärung; Tür Blatt: In Abklärung; Tür Kanten: In Abklärung; Tür Dichtung: In Abklärung; Tür Drücker: In Abklärung; Tür Schutzbeschlag: In Abklärung; Tür Bänder: In Abklärung; Tür Absenkdichtung: In Abklärung; Tür Türspion: In Abklärung; Tür Schliesssystem: In Abklärung; Tür Schallschutz - R'w: In Abklärung; Tür Einbruchschutz: In Abklärung; Tür Rauchschutz: In Abklärung; Tür Strahlenschutz: In Abklärung; Tür Sicherheitsglas Personenschutz: In Abklärung; Tür Türschliesser: In Abklärung; Tür Blatt Farbe innen: RAL / NCS; Tür Blatt Farbe aussen: RAL / NCS; Tür Rahmen Farbe: RAL / NCS; Tür Rahmen Überstand aussen - cm: In Abklärung; Tür Rahmen Überstand innen - cm: In Abklärung; Tür Typ: In Abklärung
Name | In | OverallHeight (mm) | Kote Brüstung fertig - m | Kote Brüstung roh - m | Kote Sturz fertig - m | Kote Sturz roh - m
Tür-007 | UG | 2650 | -3.3 | -3.34 | -1.25 | -1.29
Tür-007 | EG | 2050 | 5.19885e-08 | -0.0399999 | 2.05 | 2.01
Tür-007 | 1.OG | 2200 | 3.05 | 3.01 | 5.1 | 5.06
Tür-007 | 2.OG | 2200 | 5.95 | 5.91 | 8 | 7.96
Tür-007 | Attika | 2200 | 8.85 | 8.81 | 10.9 | 10.86

# IfcDoor: Zimmertür Typ 01, Tür-011
In: 2.OG
Type - OperationType: SINGLE_SWING_LEFT
OverallHeight: 2250 mm; OverallWidth: 800 mm; Classification: Innentür (BIM Base by Evolut)
01_Leistungen und Kosten - Gebäude: In Abklärung; Elementpreis - CHF: 0; BKP: 273 - Schreinerarbeiten; eBKP-H_Nr: G01.05; eBKP-H_Beschrieb: Innentür
03_Bausystem - Feuerwiderstand: In Abklärung; Umbau-Status: Neubau; Wand Typ: Innenwand Typ 05
Tür - Tür Rahmen: In Abklärung; Tür Blatt: In Abklärung; Tür Kanten: In Abklärung; Tür Dichtung: In Abklärung; Tür Drücker: In Abklärung; Tür Schutzbeschlag: In Abklärung; Tür Bänder: In Abklärung; Tür Absenkdichtung: In Abklärung; Tür Türspion: In Abklärung; Tür Schliesssystem: In Abklärung; Tür Schallschutz - R'w: In Abklärung; Tür Einbruchschutz: In Abklärung; Tür Rauchschutz: In Abklärung; Tür Strahlenschutz: In Abklärung; Tür Sicherheitsglas Personenschutz: In Abklärung; Tür Türschliesser: In Abklärung; Tür Blatt Farbe innen: RAL / NCS; Tür Blatt Farbe aussen: RAL / NCS; Tür Rahmen Farbe: RAL / NCS; Tür Rahmen Überstand aussen - cm: In Abklärung; Tür Rahmen Überstand innen - cm: In Abklärung; Tür Typ: In Abklärung
05_Bauablauf - Bau-Nr.: In Abklärung; Bauablauf Etappe: In Abklärung; Bauablauf Verbauungsort: In Abklärung; Bauablauf Start Ausführung: In Abklärung; Bauablauf Ende Ausführung: In Abklärung
02_Mengen - Breite Lichtmass - m: 0.8; Höhe Lichtmass - m: 2.1; Fläche Lichtmass - m2: 1.68; Höhe Mauerlicht - m: 2.1; Breite Mauerlicht - m: 0.8; Fläche Mauerlicht - m2: 1.68; Delta Höhe unten - m: 0; Delta Hohe oben - m: 0; Wandstärke - m: 0.17; Kote Brüstung fertig - m: 5.95; Kote Brüstung roh - m: 5.95; Kote Sturz fertig - m: 8.05; Kote Sturz roh - m: 8.05
00_Datenstruktur - BIM Base Version: 4.0.0; Kundenergänzungen Version: v01; CAD Werkzeug Typ: Tür; Klassifizierung: Innentür; Klassifizierung Level 0: Tür; Modellierungsrichtlinien: https://evolutbaugmbh.sharepoint.com/:b:/s/External/EciBgBMJMZlDgYCafV5wNokBvCJq9PUJAyVGz7O3vsjVrg?e=aLjLN9; Übersicht BIM Base: https://evolutbaugmbh.sharepoint.com/:b:/s/External/EfS4mJ9nZQpOhASXp0n2kW4B0K7N-vHKx-_6Crp5CxEFeg?e=Qu0M5d; Verbesserungsvorschläge BIM Base: https://forms.office.com/e/pcFhFfi5DW; Anleitung Mengen: https://evolutbaugmbh.sharepoint.com/:b:/s/External/ETgyOLO3JxJEqg9rbaRMLVEBHuWIRtkoMiJN1fISDr-3lw?e=E0LTiQ; Anleitung Eigenschaften: https://evolutbaugmbh.sharepoint.com/:b:/s/External/EQedjNXQkc1Btaftc01yAPUBtND9QzXFSH3-7sie6PGFww?e=wP4uf3; Release Notes: https://evolutbaugmbh.sharepoint.com/:b:/s/External/Eb41lwlDI71MhUVvor2V2mUBSaI-0tQK5U9oJAWxpCINuw?e=NtK3j6

# IfcDoor: Zimmertür Typ 02 (6)
Type - OperationType: SINGLE_SWING_RIGHT
OverallWidth: 800 mm; Classification: Innentür (BIM Base by Evolut)
01_Leistungen und Kosten - Gebäude: In Abklärung; Elementpreis - CHF: 0; BKP: 273 - Schreinerarbeiten; eBKP-H_Nr: G01.05; eBKP-H_Beschrieb: Innentür
03_Bausystem - Feuerwiderstand: In Abklärung; Umbau-Status: Neubau
Tür - Tür Rahmen: In Abklärung; Tür Blatt: In Abklärung; Tür Kanten: In Abklärung; Tür Dichtung: In Abklärung; Tür Drücker: In Abklärung; Tür Schutzbeschlag: In Abklärung; Tür Bänder: In Abklärung; Tür Absenkdichtung: In Abklärung; Tür Türspion: In Abklärung; Tür Schliesssystem: In Abklärung; Tür Schallschutz - R'w: In Abklärung; Tür Einbruchschutz: In Abklärung; Tür Rauchschutz: In Abklärung; Tür Strahlenschutz: In Abklärung; Tür Sicherheitsglas Personenschutz: In Abklärung; Tür Türschliesser: In Abklärung; Tür Blatt Farbe innen: RAL / NCS; Tür Blatt Farbe aussen: RAL / NCS; Tür Rahmen Farbe: RAL / NCS; Tür Rahmen Überstand aussen - cm: In Abklärung; Tür Rahmen Überstand innen - cm: In Abklärung; Tür Typ: In Abklärung
02_Mengen - Breite Lichtmass - m: 0.8; Höhe Lichtmass - m: 2.1; Fläche Lichtmass - m2: 1.68; Höhe Mauerlicht - m: 2.1; Breite Mauerlicht - m: 0.8; Fläche Mauerlicht - m2: 1.68
00_Datenstruktur - BIM Base Version: 4.0.0; Kundenergänzungen Version: v01; CAD Werkzeug Typ: Tür; Klassifizierung: Innentür; Klassifizierung Level 0: Tür; Modellierungsrichtlinien: https://evolutbaugmbh.sharepoint.com/:b:/s/External/EciBgBMJMZlDgYCafV5wNokBvCJq9PUJAyVGz7O3vsjVrg?e=aLjLN9; Übersicht BIM Base: https://evolutbaugmbh.sharepoint.com/:b:/s/External/EfS4mJ9nZQpOhASXp0n2kW4B0K7N-vHKx-_6Crp5CxEFeg?e=Qu0M5d; Verbesserungsvorschläge BIM Base: https://forms.office.com/e/pcFhFfi5DW; Anleitung Mengen: https://evolutbaugmbh.sharepoint.com/:b:/s/External/ETgyOLO3JxJEqg9rbaRMLVEBHuWIRtkoMiJN1fISDr-3lw?e=E0LTiQ; Anleitung Eigenschaften: https://evolutbaugmbh.sharepoint.com/:b:/s/External/EQedjNXQkc1Btaftc01yAPUBtND9QzXFSH3-7sie6PGFww?e=wP4uf3; Release Notes: https://evolutbaugmbh.sharepoint.com/:b:/s/External/Eb41lwlDI71MhUVvor2V2mUBSaI-0tQK5U9oJAWxpCINuw?e=NtK3j6
05_Bauablauf - Bau-Nr.: In Abklärung; Bauablauf Etappe: In Abklärung; Bauablauf Verbauungsort: In Abklärung; Bauablauf Start Ausführung: In Abklärung; Bauablauf Ende Ausführung: In Abklärung
Name | In | OverallHeight (mm) | Wand Typ | Delta Höhe unten - m | Delta Hohe oben - m | Wandstärke - m | Kote Brüstung fertig - m = Kote Brüstung roh - m | Kote Sturz fertig - m = Kote Sturz roh - m
2 x Tür-011 | 1.OG | 2250 | Innenwand Typ 05 | 4.44089e-16 | -4.44089e-16 | 0.17 | 3.05 | 5.15
2 x Tür-011 | 2.OG | 2250 | Innenwand Typ 05 | 0 | 0 | 0.17 | 5.95 | 8.05
Tür-011 | Attika | 2250 | Innenwand Typ 05 | 0 | 0 | 0.17 | 8.85 | 10.95
Tür-011 | Attika | 2100 | Innenwand Typ 04 | 0 | 0 | 0.145 | 8.7 | 10.8

# IfcDoor: Zimmertür Typ 03 (7)
Type - OperationType: SINGLE_SWING_LEFT
OverallHeight: 2250 mm; OverallWidth: 800 mm; Classification: Innentür (BIM Base by Evolut)
01_Leistungen und Kosten - Gebäude: In Abklärung; Elementpreis - CHF: 0; BKP: 273 - Schreinerarbeiten; eBKP-H_Nr: G01.05; eBKP-H_Beschrieb: Innentür
05_Bauablauf - Bau-Nr.: In Abklärung; Bauablauf Etappe: In Abklärung; Bauablauf Verbauungsort: In Abklärung; Bauablauf Start Ausführung: In Abklärung; Bauablauf Ende Ausführung: In Abklärung
03_Bausystem - Feuerwiderstand: In Abklärung; Umbau-Status: Neubau; Wand Typ: Innenwand Typ 05
Tür - Tür Rahmen: In Abklärung; Tür Blatt: In Abklärung; Tür Kanten: In Abklärung; Tür Dichtung: In Abklärung; Tür Drücker: In Abklärung; Tür Schutzbeschlag: In Abklärung; Tür Bänder: In Abklärung; Tür Absenkdichtung: In Abklärung; Tür Türspion: In Abklärung; Tür Schliesssystem: In Abklärung; Tür Schallschutz - R'w: In Abklärung; Tür Einbruchschutz: In Abklärung; Tür Rauchschutz: In Abklärung; Tür Strahlenschutz: In Abklärung; Tür Sicherheitsglas Personenschutz: In Abklärung; Tür Türschliesser: In Abklärung; Tür Blatt Farbe innen: RAL / NCS; Tür Blatt Farbe aussen: RAL / NCS; Tür Rahmen Farbe: RAL / NCS; Tür Rahmen Überstand aussen - cm: In Abklärung; Tür Rahmen Überstand innen - cm: In Abklärung; Tür Typ: In Abklärung
02_Mengen - Breite Lichtmass - m: 0.8; Höhe Lichtmass - m: 2.1; Fläche Lichtmass - m2: 1.68; Höhe Mauerlicht - m: 2.1; Breite Mauerlicht - m: 0.8; Fläche Mauerlicht - m2: 1.68; Wandstärke - m: 0.17
00_Datenstruktur - BIM Base Version: 4.0.0; Kundenergänzungen Version: v01; CAD Werkzeug Typ: Tür; Klassifizierung: Innentür; Klassifizierung Level 0: Tür; Modellierungsrichtlinien: https://evolutbaugmbh.sharepoint.com/:b:/s/External/EciBgBMJMZlDgYCafV5wNokBvCJq9PUJAyVGz7O3vsjVrg?e=aLjLN9; Übersicht BIM Base: https://evolutbaugmbh.sharepoint.com/:b:/s/External/EfS4mJ9nZQpOhASXp0n2kW4B0K7N-vHKx-_6Crp5CxEFeg?e=Qu0M5d; Verbesserungsvorschläge BIM Base: https://forms.office.com/e/pcFhFfi5DW; Anleitung Mengen: https://evolutbaugmbh.sharepoint.com/:b:/s/External/ETgyOLO3JxJEqg9rbaRMLVEBHuWIRtkoMiJN1fISDr-3lw?e=E0LTiQ; Anleitung Eigenschaften: https://evolutbaugmbh.sharepoint.com/:b:/s/External/EQedjNXQkc1Btaftc01yAPUBtND9QzXFSH3-7sie6PGFww?e=wP4uf3; Release Notes: https://evolutbaugmbh.sharepoint.com/:b:/s/External/Eb41lwlDI71MhUVvor2V2mUBSaI-0tQK5U9oJAWxpCINuw?e=NtK3j6
Name | In | Delta Höhe unten - m | Delta Hohe oben - m | Kote Brüstung fertig - m = Kote Brüstung roh - m | Kote Sturz fertig - m = Kote Sturz roh - m
2 x Tür-011 | 1.OG | 4.44089e-16 | -4.44089e-16 | 3.05 | 5.15
2 x Tür-011 | 2.OG | 0 | 0 | 5.95 | 8.05
3 x Tür-011 | Attika | 0 | 0 | 8.85 | 10.95

# IfcDoor: Zimmertür Typ 04 (5)
Type - OperationType: SINGLE_SWING_LEFT
OverallHeight: 2145 mm; OverallWidth: 890 mm; Classification: Innentür (BIM Base by Evolut)
01_Leistungen und Kosten - Gebäude: In Abklärung; Elementpreis - CHF: 0; BKP: 273 - Schreinerarbeiten; eBKP-H_Nr: G01.05; eBKP-H_Beschrieb: Innentür
03_Bausystem - Feuerwiderstand: In Abklärung; Umbau-Status: Neubau; Wand Typ: Innenwand Typ 05
02_Mengen - Breite Lichtmass - m: 0.8; Höhe Lichtmass - m: 2.1; Fläche Lichtmass - m2: 1.68; Höhe Mauerlicht - m: 2.145; Breite Mauerlicht - m: 0.89; Fläche Mauerlicht - m2: 1.90905; Delta Hohe oben - m: 0.045; Wandstärke - m: 0.17
00_Datenstruktur - BIM Base Version: 4.0.0; Kundenergänzungen Version: v01; CAD Werkzeug Typ: Tür; Klassifizierung: Innentür; Klassifizierung Level 0: Tür; Modellierungsrichtlinien: https://evolutbaugmbh.sharepoint.com/:b:/s/External/EciBgBMJMZlDgYCafV5wNokBvCJq9PUJAyVGz7O3vsjVrg?e=aLjLN9; Übersicht BIM Base: https://evolutbaugmbh.sharepoint.com/:b:/s/External/EfS4mJ9nZQpOhASXp0n2kW4B0K7N-vHKx-_6Crp5CxEFeg?e=Qu0M5d; Verbesserungsvorschläge BIM Base: https://forms.office.com/e/pcFhFfi5DW; Anleitung Mengen: https://evolutbaugmbh.sharepoint.com/:b:/s/External/ETgyOLO3JxJEqg9rbaRMLVEBHuWIRtkoMiJN1fISDr-3lw?e=E0LTiQ; Anleitung Eigenschaften: https://evolutbaugmbh.sharepoint.com/:b:/s/External/EQedjNXQkc1Btaftc01yAPUBtND9QzXFSH3-7sie6PGFww?e=wP4uf3; Release Notes: https://evolutbaugmbh.sharepoint.com/:b:/s/External/Eb41lwlDI71MhUVvor2V2mUBSaI-0tQK5U9oJAWxpCINuw?e=NtK3j6
Tür - Tür Rahmen: In Abklärung; Tür Blatt: In Abklärung; Tür Kanten: In Abklärung; Tür Dichtung: In Abklärung; Tür Drücker: In Abklärung; Tür Schutzbeschlag: In Abklärung; Tür Bänder: In Abklärung; Tür Absenkdichtung: In Abklärung; Tür Türspion: In Abklärung; Tür Schliesssystem: In Abklärung; Tür Schallschutz - R'w: In Abklärung; Tür Einbruchschutz: In Abklärung; Tür Rauchschutz: In Abklärung; Tür Strahlenschutz: In Abklärung; Tür Sicherheitsglas Personenschutz: In Abklärung; Tür Türschliesser: In Abklärung; Tür Blatt Farbe innen: RAL / NCS; Tür Blatt Farbe aussen: RAL / NCS; Tür Rahmen Farbe: RAL / NCS; Tür Rahmen Überstand aussen - cm: In Abklärung; Tür Rahmen Überstand innen - cm: In Abklärung; Tür Typ: In Abklärung
05_Bauablauf - Bau-Nr.: In Abklärung; Bauablauf Etappe: In Abklärung; Bauablauf Verbauungsort: In Abklärung; Bauablauf Start Ausführung: In Abklärung; Bauablauf Ende Ausführung: In Abklärung
Name | In | Delta Höhe unten - m | Kote Brüstung fertig - m = Kote Brüstung roh - m | Kote Sturz fertig - m | Kote Sturz roh - m
2 x Tür-011 | 1.OG | 4.44089e-16 | 3.05 | 5.15 | 5.195
2 x Tür-011 | 2.OG | 0 | 5.95 | 8.05 | 8.095
Tür-011 | Attika | 0 | 8.85 | 10.95 | 10.995

# IfcDoor: Zimmertür Typ 05, Tür-011
In: 1.OG
Type - OperationType: SINGLE_SWING_LEFT
OverallHeight: 2250 mm; OverallWidth: 800 mm; Classification: Innentür (BIM Base by Evolut)
03_Bausystem - Feuerwiderstand: In Abklärung; Umbau-Status: Neubau; Wand Typ: Innenwand Typ 05
00_Datenstruktur - BIM Base Version: 4.0.0; Kundenergänzungen Version: v01; CAD Werkzeug Typ: Tür; Klassifizierung: Innentür; Klassifizierung Level 0: Tür; Modellierungsrichtlinien: https://evolutbaugmbh.sharepoint.com/:b:/s/External/EciBgBMJMZlDgYCafV5wNokBvCJq9PUJAyVGz7O3vsjVrg?e=aLjLN9; Übersicht BIM Base: https://evolutbaugmbh.sharepoint.com/:b:/s/External/EfS4mJ9nZQpOhASXp0n2kW4B0K7N-vHKx-_6Crp5CxEFeg?e=Qu0M5d; Verbesserungsvorschläge BIM Base: https://forms.office.com/e/pcFhFfi5DW; Anleitung Mengen: https://evolutbaugmbh.sharepoint.com/:b:/s/External/ETgyOLO3JxJEqg9rbaRMLVEBHuWIRtkoMiJN1fISDr-3lw?e=E0LTiQ; Anleitung Eigenschaften: https://evolutbaugmbh.sharepoint.com/:b:/s/External/EQedjNXQkc1Btaftc01yAPUBtND9QzXFSH3-7sie6PGFww?e=wP4uf3; Release Notes: https://evolutbaugmbh.sharepoint.com/:b:/s/External/Eb41lwlDI71MhUVvor2V2mUBSaI-0tQK5U9oJAWxpCINuw?e=NtK3j6
01_Leistungen und Kosten - Gebäude: In Abklärung; Elementpreis - CHF: 0; BKP: 273 - Schreinerarbeiten; eBKP-H_Nr: G01.05; eBKP-H_Beschrieb: Innentür
02_Mengen - Breite Lichtmass - m: 0.8; Höhe Lichtmass - m: 2.1; Fläche Lichtmass - m2: 1.68; Höhe Mauerlicht - m: 2.1; Breite Mauerlicht - m: 0.8; Fläche Mauerlicht - m2: 1.68; Delta Höhe unten - m: 4.44089e-16; Delta Hohe oben - m: -4.44089e-16; Wandstärke - m: 0.17; Kote Brüstung fertig - m: 3.05; Kote Brüstung roh - m: 3.05; Kote Sturz fertig - m: 5.15; Kote Sturz roh - m: 5.15
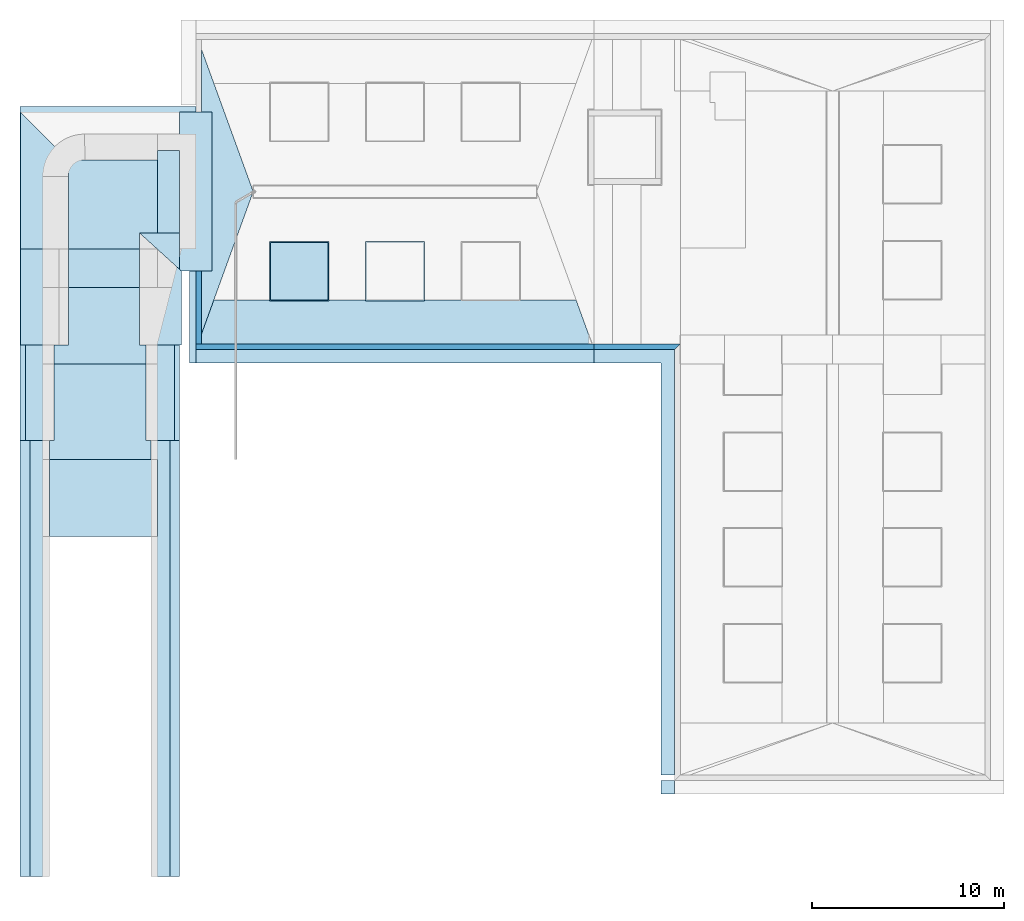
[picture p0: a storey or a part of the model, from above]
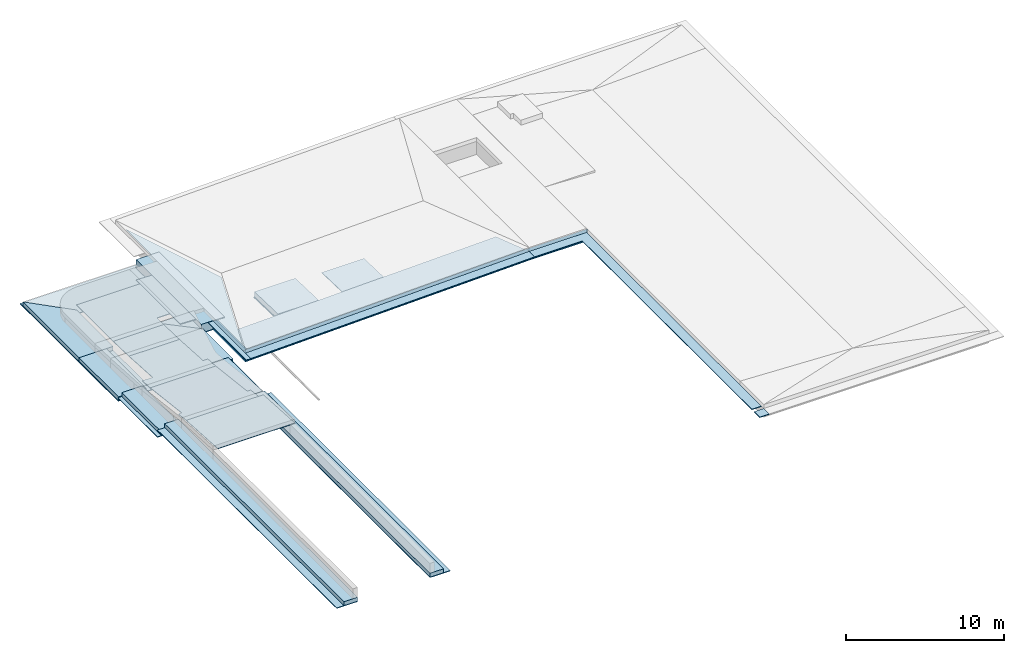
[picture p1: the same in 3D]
Properties of the parts of a building model (IFC4), part 3 of 8

# IfcDoor: Zimmertür Typ 05, Tür-011
Tür - Tür Rahmen: In Abklärung; Tür Blatt: In Abklärung; Tür Kanten: In Abklärung; Tür Dichtung: In Abklärung; Tür Drücker: In Abklärung; Tür Schutzbeschlag: In Abklärung; Tür Bänder: In Abklärung; Tür Absenkdichtung: In Abklärung; Tür Türspion: In Abklärung; Tür Schliesssystem: In Abklärung; Tür Schallschutz - R'w: In Abklärung; Tür Einbruchschutz: In Abklärung; Tür Rauchschutz: In Abklärung; Tür Strahlenschutz: In Abklärung; Tür Sicherheitsglas Personenschutz: In Abklärung; Tür Türschliesser: In Abklärung; Tür Blatt Farbe innen: RAL / NCS; Tür Blatt Farbe aussen: RAL / NCS; Tür Rahmen Farbe: RAL / NCS; Tür Rahmen Überstand aussen - cm: In Abklärung; Tür Rahmen Überstand innen - cm: In Abklärung; Tür Typ: In Abklärung
05_Bauablauf - Bau-Nr.: In Abklärung; Bauablauf Etappe: In Abklärung; Bauablauf Verbauungsort: In Abklärung; Bauablauf Start Ausführung: In Abklärung; Bauablauf Ende Ausführung: In Abklärung

# IfcFooting: Beton bewehrt 1000 x 300 (2)
In: Fundation
Classification: Streifenfundament Ortbeton (BIM Base by Evolut); Material: Beton bewehrt
01_Leistungen und Kosten - Gebäude: In Abklärung; Elementpreis - CHF: 0; BKP: 211 - Baumeisterarbeiten; eBKP-H_Nr: C01.02; eBKP-H_Beschrieb: Fundament
05_Bauablauf - Bau-Nr.: In Abklärung; Bauablauf Etappe: In Abklärung; Bauablauf Verbauungsort: In Abklärung; Bauablauf Start Ausführung: In Abklärung; Bauablauf Ende Ausführung: In Abklärung
03_Bausystem - Tragende Funktion: In Abklärung; Umbau-Status: Neubau; Mehrschichtiger Aufbau: Beton bewehrt
02_Mengen - Breite - m: 1; Höhe - m: 0.3; Stärke - m: 1; Länge brutto - m: 22.75; Fläche brutto - m2: 22.75; Volumen netto - m3: 6.825; Kote Unterkante: -4.065; Kote Oberkante: -3.765
00_Datenstruktur - BIM Base Version: 4.0.0; Kundenergänzungen Version: v01; CAD Werkzeug Typ: Träger; Klassifizierung: Streifenfundament Ortbeton; Klassifizierung Level 0: Fundation; Modellierungsrichtlinien: https://evolutbaugmbh.sharepoint.com/:b:/s/External/EciBgBMJMZlDgYCafV5wNokBvCJq9PUJAyVGz7O3vsjVrg?e=aLjLN9; Übersicht BIM Base: https://evolutbaugmbh.sharepoint.com/:b:/s/External/EfS4mJ9nZQpOhASXp0n2kW4B0K7N-vHKx-_6Crp5CxEFeg?e=Qu0M5d; Verbesserungsvorschläge BIM Base: https://forms.office.com/e/pcFhFfi5DW; Anleitung Mengen: https://evolutbaugmbh.sharepoint.com/:b:/s/External/ETgyOLO3JxJEqg9rbaRMLVEBHuWIRtkoMiJN1fISDr-3lw?e=E0LTiQ; Anleitung Eigenschaften: https://evolutbaugmbh.sharepoint.com/:b:/s/External/EQedjNXQkc1Btaftc01yAPUBtND9QzXFSH3-7sie6PGFww?e=wP4uf3; Release Notes: https://evolutbaugmbh.sharepoint.com/:b:/s/External/Eb41lwlDI71MhUVvor2V2mUBSaI-0tQK5U9oJAWxpCINuw?e=NtK3j6
Massivbau Ortbeton - Ortbeton Druckfestigkeitsklasse: In Abklärung; Ortbeton Expositionsklasse: In Abklärung; Ortbeton Grösstkorn - mm: Dmax 32; Ortbeton Chloridgehaltsklasse: Cl 0.10; Ortbeton Konsistenzklasse: C3; Ortbeton Recyclingbeton: In Abklärung; Ortbeton Oberflächenausführung: In Abklärung; Ortbeton Oberflächenklasse - BOK: In Abklärung; Ortbeton Schalungstyp: In Abklärung; Ortbeton Dreikantleisten - mm: In Abklärung; Ortbeton Bew. Überdeckung oben - mm: In Abklärung; Ortbeton Bew. Überdeckung unten - mm: In Abklärung; Ortbeton Bew. Überdeckung aussen - mm: In Abklärung; Ortbeton Bew. Überdeckung innen - mm: In Abklärung; Ortbeton Bewehrungsgehalt - kg/m3: In Abklärung

# IfcFooting: Beton bewehrt 1500 x 1500 (6)
In: UG
Classification: Einzelfundament Ortbeton (BIM Base by Evolut); Material: Beton bewehrt
01_Leistungen und Kosten - Gebäude: In Abklärung; Elementpreis - CHF: 0; BKP: 211 - Baumeisterarbeiten; eBKP-H_Nr: C01.02; eBKP-H_Beschrieb: Fundament
Massivbau Ortbeton - Ortbeton Druckfestigkeitsklasse: In Abklärung; Ortbeton Expositionsklasse: In Abklärung; Ortbeton Grösstkorn - mm: Dmax 32; Ortbeton Chloridgehaltsklasse: Cl 0.10; Ortbeton Konsistenzklasse: C3; Ortbeton Recyclingbeton: In Abklärung; Ortbeton Oberflächenausführung: In Abklärung; Ortbeton Oberflächenklasse - BOK: In Abklärung; Ortbeton Schalungstyp: In Abklärung; Ortbeton Dreikantleisten - mm: In Abklärung; Ortbeton Bew. Überdeckung oben - mm: In Abklärung; Ortbeton Bew. Überdeckung unten - mm: In Abklärung; Ortbeton Bew. Überdeckung aussen - mm: In Abklärung; Ortbeton Bew. Überdeckung innen - mm: In Abklärung; Ortbeton Bewehrungsgehalt - kg/m3: In Abklärung
02_Mengen - Breite - m: 1.5; Höhe - m: 1.5; Stärke - m: 1.5; Länge brutto - m: 0.25; Fläche brutto - m2: 0.375; Volumen netto - m3: 0.5625; Kote Unterkante: -1; Kote Oberkante: -0.75
00_Datenstruktur - BIM Base Version: 4.0.0; Kundenergänzungen Version: v01; CAD Werkzeug Typ: Stütze; Klassifizierung: Einzelfundament Ortbeton; Klassifizierung Level 0: Fundation; Modellierungsrichtlinien: https://evolutbaugmbh.sharepoint.com/:b:/s/External/EciBgBMJMZlDgYCafV5wNokBvCJq9PUJAyVGz7O3vsjVrg?e=aLjLN9; Übersicht BIM Base: https://evolutbaugmbh.sharepoint.com/:b:/s/External/EfS4mJ9nZQpOhASXp0n2kW4B0K7N-vHKx-_6Crp5CxEFeg?e=Qu0M5d; Verbesserungsvorschläge BIM Base: https://forms.office.com/e/pcFhFfi5DW; Anleitung Mengen: https://evolutbaugmbh.sharepoint.com/:b:/s/External/ETgyOLO3JxJEqg9rbaRMLVEBHuWIRtkoMiJN1fISDr-3lw?e=E0LTiQ; Anleitung Eigenschaften: https://evolutbaugmbh.sharepoint.com/:b:/s/External/EQedjNXQkc1Btaftc01yAPUBtND9QzXFSH3-7sie6PGFww?e=wP4uf3; Release Notes: https://evolutbaugmbh.sharepoint.com/:b:/s/External/Eb41lwlDI71MhUVvor2V2mUBSaI-0tQK5U9oJAWxpCINuw?e=NtK3j6
03_Bausystem - Tragende Funktion: In Abklärung; Umbau-Status: Neubau; Mehrschichtiger Aufbau: Beton bewehrt
05_Bauablauf - Bau-Nr.: In Abklärung; Bauablauf Etappe: In Abklärung; Bauablauf Verbauungsort: In Abklärung; Bauablauf Start Ausführung: In Abklärung; Bauablauf Ende Ausführung: In Abklärung

# IfcFooting: Beton bewehrt 1500 x 250 (4)
In: Fundation
Classification: Streifenfundament Ortbeton (BIM Base by Evolut); Material: Beton bewehrt
05_Bauablauf - Bau-Nr.: In Abklärung; Bauablauf Etappe: In Abklärung; Bauablauf Verbauungsort: In Abklärung; Bauablauf Start Ausführung: In Abklärung; Bauablauf Ende Ausführung: In Abklärung
01_Leistungen und Kosten - Gebäude: In Abklärung; Elementpreis - CHF: 0; BKP: 211 - Baumeisterarbeiten; eBKP-H_Nr: C01.02; eBKP-H_Beschrieb: Fundament
Massivbau Ortbeton - Ortbeton Druckfestigkeitsklasse: In Abklärung; Ortbeton Expositionsklasse: In Abklärung; Ortbeton Grösstkorn - mm: Dmax 32; Ortbeton Chloridgehaltsklasse: Cl 0.10; Ortbeton Konsistenzklasse: C3; Ortbeton Recyclingbeton: In Abklärung; Ortbeton Oberflächenausführung: In Abklärung; Ortbeton Oberflächenklasse - BOK: In Abklärung; Ortbeton Schalungstyp: In Abklärung; Ortbeton Dreikantleisten - mm: In Abklärung; Ortbeton Bew. Überdeckung oben - mm: In Abklärung; Ortbeton Bew. Überdeckung unten - mm: In Abklärung; Ortbeton Bew. Überdeckung aussen - mm: In Abklärung; Ortbeton Bew. Überdeckung innen - mm: In Abklärung; Ortbeton Bewehrungsgehalt - kg/m3: In Abklärung
02_Mengen - Breite - m: 1.5; Höhe - m: 0.25; Stärke - m: 1.5
00_Datenstruktur - BIM Base Version: 4.0.0; Kundenergänzungen Version: v01; CAD Werkzeug Typ: Träger; Klassifizierung: Streifenfundament Ortbeton; Klassifizierung Level 0: Fundation; Modellierungsrichtlinien: https://evolutbaugmbh.sharepoint.com/:b:/s/External/EciBgBMJMZlDgYCafV5wNokBvCJq9PUJAyVGz7O3vsjVrg?e=aLjLN9; Übersicht BIM Base: https://evolutbaugmbh.sharepoint.com/:b:/s/External/EfS4mJ9nZQpOhASXp0n2kW4B0K7N-vHKx-_6Crp5CxEFeg?e=Qu0M5d; Verbesserungsvorschläge BIM Base: https://forms.office.com/e/pcFhFfi5DW; Anleitung Mengen: https://evolutbaugmbh.sharepoint.com/:b:/s/External/ETgyOLO3JxJEqg9rbaRMLVEBHuWIRtkoMiJN1fISDr-3lw?e=E0LTiQ; Anleitung Eigenschaften: https://evolutbaugmbh.sharepoint.com/:b:/s/External/EQedjNXQkc1Btaftc01yAPUBtND9QzXFSH3-7sie6PGFww?e=wP4uf3; Release Notes: https://evolutbaugmbh.sharepoint.com/:b:/s/External/Eb41lwlDI71MhUVvor2V2mUBSaI-0tQK5U9oJAWxpCINuw?e=NtK3j6
03_Bausystem - Tragende Funktion: In Abklärung; Umbau-Status: Neubau; Mehrschichtiger Aufbau: Beton bewehrt
Name | Länge brutto - m | Fläche brutto - m2 | Volumen netto - m3 | Kote Unterkante | Kote Oberkante
2 x Unterzug-024 | 2.65332 | 3.97997 | 0.996868 | -4.18 | -3.93
2 x Unterzug-024 | 2.30304 | 3.45456 | 0.861765 | -3.954 | -3.704

# IfcFooting: Beton bewehrt 1500 x 300 (2)
In: Fundation
Classification: Streifenfundament Ortbeton (BIM Base by Evolut); Material: Beton bewehrt
01_Leistungen und Kosten - Gebäude: In Abklärung; Elementpreis - CHF: 0; BKP: 211 - Baumeisterarbeiten; eBKP-H_Nr: C01.02; eBKP-H_Beschrieb: Fundament
03_Bausystem - Tragende Funktion: In Abklärung; Umbau-Status: Neubau; Mehrschichtiger Aufbau: Beton bewehrt
02_Mengen - Breite - m: 1.5; Höhe - m: 0.3; Stärke - m: 1.5; Länge brutto - m: 5; Fläche brutto - m2: 7.5; Volumen netto - m3: 2.25; Kote Unterkante: -4.6; Kote Oberkante: -4.3
05_Bauablauf - Bau-Nr.: In Abklärung; Bauablauf Etappe: In Abklärung; Bauablauf Verbauungsort: In Abklärung; Bauablauf Start Ausführung: In Abklärung; Bauablauf Ende Ausführung: In Abklärung
00_Datenstruktur - BIM Base Version: 4.0.0; Kundenergänzungen Version: v01; CAD Werkzeug Typ: Träger; Klassifizierung: Streifenfundament Ortbeton; Klassifizierung Level 0: Fundation; Modellierungsrichtlinien: https://evolutbaugmbh.sharepoint.com/:b:/s/External/EciBgBMJMZlDgYCafV5wNokBvCJq9PUJAyVGz7O3vsjVrg?e=aLjLN9; Übersicht BIM Base: https://evolutbaugmbh.sharepoint.com/:b:/s/External/EfS4mJ9nZQpOhASXp0n2kW4B0K7N-vHKx-_6Crp5CxEFeg?e=Qu0M5d; Verbesserungsvorschläge BIM Base: https://forms.office.com/e/pcFhFfi5DW; Anleitung Mengen: https://evolutbaugmbh.sharepoint.com/:b:/s/External/ETgyOLO3JxJEqg9rbaRMLVEBHuWIRtkoMiJN1fISDr-3lw?e=E0LTiQ; Anleitung Eigenschaften: https://evolutbaugmbh.sharepoint.com/:b:/s/External/EQedjNXQkc1Btaftc01yAPUBtND9QzXFSH3-7sie6PGFww?e=wP4uf3; Release Notes: https://evolutbaugmbh.sharepoint.com/:b:/s/External/Eb41lwlDI71MhUVvor2V2mUBSaI-0tQK5U9oJAWxpCINuw?e=NtK3j6
Massivbau Ortbeton - Ortbeton Druckfestigkeitsklasse: In Abklärung; Ortbeton Expositionsklasse: In Abklärung; Ortbeton Grösstkorn - mm: Dmax 32; Ortbeton Chloridgehaltsklasse: Cl 0.10; Ortbeton Konsistenzklasse: C3; Ortbeton Recyclingbeton: In Abklärung; Ortbeton Oberflächenausführung: In Abklärung; Ortbeton Oberflächenklasse - BOK: In Abklärung; Ortbeton Schalungstyp: In Abklärung; Ortbeton Dreikantleisten - mm: In Abklärung; Ortbeton Bew. Überdeckung oben - mm: In Abklärung; Ortbeton Bew. Überdeckung unten - mm: In Abklärung; Ortbeton Bew. Überdeckung aussen - mm: In Abklärung; Ortbeton Bew. Überdeckung innen - mm: In Abklärung; Ortbeton Bewehrungsgehalt - kg/m3: In Abklärung

# IfcFooting: Beton bewehrt 1500 x 350 (2)
In: Fundation
Classification: Streifenfundament Ortbeton (BIM Base by Evolut); Material: Beton bewehrt
01_Leistungen und Kosten - Gebäude: In Abklärung; Elementpreis - CHF: 0; BKP: 211 - Baumeisterarbeiten; eBKP-H_Nr: C01.02; eBKP-H_Beschrieb: Fundament
03_Bausystem - Tragende Funktion: In Abklärung; Umbau-Status: Neubau; Mehrschichtiger Aufbau: Beton bewehrt
05_Bauablauf - Bau-Nr.: In Abklärung; Bauablauf Etappe: In Abklärung; Bauablauf Verbauungsort: In Abklärung; Bauablauf Start Ausführung: In Abklärung; Bauablauf Ende Ausführung: In Abklärung
Massivbau Ortbeton - Ortbeton Druckfestigkeitsklasse: In Abklärung; Ortbeton Expositionsklasse: In Abklärung; Ortbeton Grösstkorn - mm: Dmax 32; Ortbeton Chloridgehaltsklasse: Cl 0.10; Ortbeton Konsistenzklasse: C3; Ortbeton Recyclingbeton: In Abklärung; Ortbeton Oberflächenausführung: In Abklärung; Ortbeton Oberflächenklasse - BOK: In Abklärung; Ortbeton Schalungstyp: In Abklärung; Ortbeton Dreikantleisten - mm: In Abklärung; Ortbeton Bew. Überdeckung oben - mm: In Abklärung; Ortbeton Bew. Überdeckung unten - mm: In Abklärung; Ortbeton Bew. Überdeckung aussen - mm: In Abklärung; Ortbeton Bew. Überdeckung innen - mm: In Abklärung; Ortbeton Bewehrungsgehalt - kg/m3: In Abklärung
00_Datenstruktur - BIM Base Version: 4.0.0; Kundenergänzungen Version: v01; CAD Werkzeug Typ: Träger; Klassifizierung: Streifenfundament Ortbeton; Klassifizierung Level 0: Fundation; Modellierungsrichtlinien: https://evolutbaugmbh.sharepoint.com/:b:/s/External/EciBgBMJMZlDgYCafV5wNokBvCJq9PUJAyVGz7O3vsjVrg?e=aLjLN9; Übersicht BIM Base: https://evolutbaugmbh.sharepoint.com/:b:/s/External/EfS4mJ9nZQpOhASXp0n2kW4B0K7N-vHKx-_6Crp5CxEFeg?e=Qu0M5d; Verbesserungsvorschläge BIM Base: https://forms.office.com/e/pcFhFfi5DW; Anleitung Mengen: https://evolutbaugmbh.sharepoint.com/:b:/s/External/ETgyOLO3JxJEqg9rbaRMLVEBHuWIRtkoMiJN1fISDr-3lw?e=E0LTiQ; Anleitung Eigenschaften: https://evolutbaugmbh.sharepoint.com/:b:/s/External/EQedjNXQkc1Btaftc01yAPUBtND9QzXFSH3-7sie6PGFww?e=wP4uf3; Release Notes: https://evolutbaugmbh.sharepoint.com/:b:/s/External/Eb41lwlDI71MhUVvor2V2mUBSaI-0tQK5U9oJAWxpCINuw?e=NtK3j6
02_Mengen - Breite - m: 1.5; Höhe - m: 0.35; Stärke - m: 1.5; Kote Unterkante: -3.95; Kote Oberkante: -3.6
Name | Länge brutto - m | Fläche brutto - m2 | Volumen netto - m3
Unterzug-024 | 3.7 | 5.55 | 1.9425
Unterzug-024 | 8.325 | 12.4875 | 4.37062

# IfcFooting: Beton bewehrt 1700 x 663, Unterzug-024
In: Fundation
Classification: Streifenfundament Ortbeton (BIM Base by Evolut); Material: Beton bewehrt
01_Leistungen und Kosten - Gebäude: In Abklärung; Elementpreis - CHF: 0; BKP: 211 - Baumeisterarbeiten; eBKP-H_Nr: C01.02; eBKP-H_Beschrieb: Fundament
05_Bauablauf - Bau-Nr.: In Abklärung; Bauablauf Etappe: In Abklärung; Bauablauf Verbauungsort: In Abklärung; Bauablauf Start Ausführung: In Abklärung; Bauablauf Ende Ausführung: In Abklärung
Massivbau Ortbeton - Ortbeton Druckfestigkeitsklasse: In Abklärung; Ortbeton Expositionsklasse: In Abklärung; Ortbeton Grösstkorn - mm: Dmax 32; Ortbeton Chloridgehaltsklasse: Cl 0.10; Ortbeton Konsistenzklasse: C3; Ortbeton Recyclingbeton: In Abklärung; Ortbeton Oberflächenausführung: In Abklärung; Ortbeton Oberflächenklasse - BOK: In Abklärung; Ortbeton Schalungstyp: In Abklärung; Ortbeton Dreikantleisten - mm: In Abklärung; Ortbeton Bew. Überdeckung oben - mm: In Abklärung; Ortbeton Bew. Überdeckung unten - mm: In Abklärung; Ortbeton Bew. Überdeckung aussen - mm: In Abklärung; Ortbeton Bew. Überdeckung innen - mm: In Abklärung; Ortbeton Bewehrungsgehalt - kg/m3: In Abklärung
03_Bausystem - Tragende Funktion: In Abklärung; Umbau-Status: Neubau; Mehrschichtiger Aufbau: Beton bewehrt
02_Mengen - Breite - m: 1.7; Höhe - m: 0.662528; Stärke - m: 1.7; Länge brutto - m: 8.3; Fläche brutto - m2: 14.11; Volumen netto - m3: 9.34692; Kote Unterkante: -4.837; Kote Oberkante: -4.175
00_Datenstruktur - BIM Base Version: 4.0.0; Kundenergänzungen Version: v01; CAD Werkzeug Typ: Träger; Klassifizierung: Streifenfundament Ortbeton; Klassifizierung Level 0: Fundation; Modellierungsrichtlinien: https://evolutbaugmbh.sharepoint.com/:b:/s/External/EciBgBMJMZlDgYCafV5wNokBvCJq9PUJAyVGz7O3vsjVrg?e=aLjLN9; Übersicht BIM Base: https://evolutbaugmbh.sharepoint.com/:b:/s/External/EfS4mJ9nZQpOhASXp0n2kW4B0K7N-vHKx-_6Crp5CxEFeg?e=Qu0M5d; Verbesserungsvorschläge BIM Base: https://forms.office.com/e/pcFhFfi5DW; Anleitung Mengen: https://evolutbaugmbh.sharepoint.com/:b:/s/External/ETgyOLO3JxJEqg9rbaRMLVEBHuWIRtkoMiJN1fISDr-3lw?e=E0LTiQ; Anleitung Eigenschaften: https://evolutbaugmbh.sharepoint.com/:b:/s/External/EQedjNXQkc1Btaftc01yAPUBtND9QzXFSH3-7sie6PGFww?e=wP4uf3; Release Notes: https://evolutbaugmbh.sharepoint.com/:b:/s/External/Eb41lwlDI71MhUVvor2V2mUBSaI-0tQK5U9oJAWxpCINuw?e=NtK3j6

# IfcFooting: Beton bewehrt 2000 x 300 (2)
In: Fundation
Classification: Streifenfundament Ortbeton (BIM Base by Evolut); Material: Beton bewehrt
01_Leistungen und Kosten - Gebäude: In Abklärung; Elementpreis - CHF: 0; BKP: 211 - Baumeisterarbeiten; eBKP-H_Nr: C01.02; eBKP-H_Beschrieb: Fundament
05_Bauablauf - Bau-Nr.: In Abklärung; Bauablauf Etappe: In Abklärung; Bauablauf Verbauungsort: In Abklärung; Bauablauf Start Ausführung: In Abklärung; Bauablauf Ende Ausführung: In Abklärung
03_Bausystem - Tragende Funktion: In Abklärung; Umbau-Status: Neubau; Mehrschichtiger Aufbau: Beton bewehrt
Massivbau Ortbeton - Ortbeton Druckfestigkeitsklasse: In Abklärung; Ortbeton Expositionsklasse: In Abklärung; Ortbeton Grösstkorn - mm: Dmax 32; Ortbeton Chloridgehaltsklasse: Cl 0.10; Ortbeton Konsistenzklasse: C3; Ortbeton Recyclingbeton: In Abklärung; Ortbeton Oberflächenausführung: In Abklärung; Ortbeton Oberflächenklasse - BOK: In Abklärung; Ortbeton Schalungstyp: In Abklärung; Ortbeton Dreikantleisten - mm: In Abklärung; Ortbeton Bew. Überdeckung oben - mm: In Abklärung; Ortbeton Bew. Überdeckung unten - mm: In Abklärung; Ortbeton Bew. Überdeckung aussen - mm: In Abklärung; Ortbeton Bew. Überdeckung innen - mm: In Abklärung; Ortbeton Bewehrungsgehalt - kg/m3: In Abklärung
00_Datenstruktur - BIM Base Version: 4.0.0; Kundenergänzungen Version: v01; CAD Werkzeug Typ: Träger; Klassifizierung: Streifenfundament Ortbeton; Klassifizierung Level 0: Fundation; Modellierungsrichtlinien: https://evolutbaugmbh.sharepoint.com/:b:/s/External/EciBgBMJMZlDgYCafV5wNokBvCJq9PUJAyVGz7O3vsjVrg?e=aLjLN9; Übersicht BIM Base: https://evolutbaugmbh.sharepoint.com/:b:/s/External/EfS4mJ9nZQpOhASXp0n2kW4B0K7N-vHKx-_6Crp5CxEFeg?e=Qu0M5d; Verbesserungsvorschläge BIM Base: https://forms.office.com/e/pcFhFfi5DW; Anleitung Mengen: https://evolutbaugmbh.sharepoint.com/:b:/s/External/ETgyOLO3JxJEqg9rbaRMLVEBHuWIRtkoMiJN1fISDr-3lw?e=E0LTiQ; Anleitung Eigenschaften: https://evolutbaugmbh.sharepoint.com/:b:/s/External/EQedjNXQkc1Btaftc01yAPUBtND9QzXFSH3-7sie6PGFww?e=wP4uf3; Release Notes: https://evolutbaugmbh.sharepoint.com/:b:/s/External/Eb41lwlDI71MhUVvor2V2mUBSaI-0tQK5U9oJAWxpCINuw?e=NtK3j6
02_Mengen - Breite - m: 2; Höhe - m: 0.3; Stärke - m: 2; Kote Unterkante: -4.84; Kote Oberkante: -4.54
Name | Länge brutto - m | Fläche brutto - m2 | Volumen netto - m3
Unterzug-025 | 2.1 | 4.2 | 0.601364
Unterzug-025 | 5 | 10 | 3

# IfcFooting: Beton bewehrt 2200 x 300, Unterzug-025
In: Fundation
Classification: Streifenfundament Ortbeton (BIM Base by Evolut); Material: Beton bewehrt
01_Leistungen und Kosten - Gebäude: In Abklärung; Elementpreis - CHF: 0; BKP: 211 - Baumeisterarbeiten; eBKP-H_Nr: C01.02; eBKP-H_Beschrieb: Fundament
05_Bauablauf - Bau-Nr.: In Abklärung; Bauablauf Etappe: In Abklärung; Bauablauf Verbauungsort: In Abklärung; Bauablauf Start Ausführung: In Abklärung; Bauablauf Ende Ausführung: In Abklärung
03_Bausystem - Tragende Funktion: In Abklärung; Umbau-Status: Neubau; Mehrschichtiger Aufbau: Beton bewehrt
Massivbau Ortbeton - Ortbeton Druckfestigkeitsklasse: In Abklärung; Ortbeton Expositionsklasse: In Abklärung; Ortbeton Grösstkorn - mm: Dmax 32; Ortbeton Chloridgehaltsklasse: Cl 0.10; Ortbeton Konsistenzklasse: C3; Ortbeton Recyclingbeton: In Abklärung; Ortbeton Oberflächenausführung: In Abklärung; Ortbeton Oberflächenklasse - BOK: In Abklärung; Ortbeton Schalungstyp: In Abklärung; Ortbeton Dreikantleisten - mm: In Abklärung; Ortbeton Bew. Überdeckung oben - mm: In Abklärung; Ortbeton Bew. Überdeckung unten - mm: In Abklärung; Ortbeton Bew. Überdeckung aussen - mm: In Abklärung; Ortbeton Bew. Überdeckung innen - mm: In Abklärung; Ortbeton Bewehrungsgehalt - kg/m3: In Abklärung
00_Datenstruktur - BIM Base Version: 4.0.0; Kundenergänzungen Version: v01; CAD Werkzeug Typ: Träger; Klassifizierung: Streifenfundament Ortbeton; Klassifizierung Level 0: Fundation; Modellierungsrichtlinien: https://evolutbaugmbh.sharepoint.com/:b:/s/External/EciBgBMJMZlDgYCafV5wNokBvCJq9PUJAyVGz7O3vsjVrg?e=aLjLN9; Übersicht BIM Base: https://evolutbaugmbh.sharepoint.com/:b:/s/External/EfS4mJ9nZQpOhASXp0n2kW4B0K7N-vHKx-_6Crp5CxEFeg?e=Qu0M5d; Verbesserungsvorschläge BIM Base: https://forms.office.com/e/pcFhFfi5DW; Anleitung Mengen: https://evolutbaugmbh.sharepoint.com/:b:/s/External/ETgyOLO3JxJEqg9rbaRMLVEBHuWIRtkoMiJN1fISDr-3lw?e=E0LTiQ; Anleitung Eigenschaften: https://evolutbaugmbh.sharepoint.com/:b:/s/External/EQedjNXQkc1Btaftc01yAPUBtND9QzXFSH3-7sie6PGFww?e=wP4uf3; Release Notes: https://evolutbaugmbh.sharepoint.com/:b:/s/External/Eb41lwlDI71MhUVvor2V2mUBSaI-0tQK5U9oJAWxpCINuw?e=NtK3j6
02_Mengen - Breite - m: 2.2; Höhe - m: 0.3; Stärke - m: 2.2; Länge brutto - m: 5.85; Fläche brutto - m2: 12.87; Volumen netto - m3: 3.201; Kote Unterkante: -4.84; Kote Oberkante: -4.54

# IfcFooting: Beton bewehrt 2500 x 300 (2)
In: Fundation
Classification: Streifenfundament Ortbeton (BIM Base by Evolut); Material: Beton bewehrt
05_Bauablauf - Bau-Nr.: In Abklärung; Bauablauf Etappe: In Abklärung; Bauablauf Verbauungsort: In Abklärung; Bauablauf Start Ausführung: In Abklärung; Bauablauf Ende Ausführung: In Abklärung
01_Leistungen und Kosten - Gebäude: In Abklärung; Elementpreis - CHF: 0; BKP: 211 - Baumeisterarbeiten; eBKP-H_Nr: C01.02; eBKP-H_Beschrieb: Fundament
03_Bausystem - Tragende Funktion: In Abklärung; Umbau-Status: Neubau; Mehrschichtiger Aufbau: Beton bewehrt
Massivbau Ortbeton - Ortbeton Druckfestigkeitsklasse: In Abklärung; Ortbeton Expositionsklasse: In Abklärung; Ortbeton Grösstkorn - mm: Dmax 32; Ortbeton Chloridgehaltsklasse: Cl 0.10; Ortbeton Konsistenzklasse: C3; Ortbeton Recyclingbeton: In Abklärung; Ortbeton Oberflächenausführung: In Abklärung; Ortbeton Oberflächenklasse - BOK: In Abklärung; Ortbeton Schalungstyp: In Abklärung; Ortbeton Dreikantleisten - mm: In Abklärung; Ortbeton Bew. Überdeckung oben - mm: In Abklärung; Ortbeton Bew. Überdeckung unten - mm: In Abklärung; Ortbeton Bew. Überdeckung aussen - mm: In Abklärung; Ortbeton Bew. Überdeckung innen - mm: In Abklärung; Ortbeton Bewehrungsgehalt - kg/m3: In Abklärung
02_Mengen - Breite - m: 2.5; Höhe - m: 0.3; Stärke - m: 2.5; Kote Unterkante: -4.84; Kote Oberkante: -4.54
00_Datenstruktur - BIM Base Version: 4.0.0; Kundenergänzungen Version: v01; CAD Werkzeug Typ: Träger; Klassifizierung: Streifenfundament Ortbeton; Klassifizierung Level 0: Fundation; Modellierungsrichtlinien: https://evolutbaugmbh.sharepoint.com/:b:/s/External/EciBgBMJMZlDgYCafV5wNokBvCJq9PUJAyVGz7O3vsjVrg?e=aLjLN9; Übersicht BIM Base: https://evolutbaugmbh.sharepoint.com/:b:/s/External/EfS4mJ9nZQpOhASXp0n2kW4B0K7N-vHKx-_6Crp5CxEFeg?e=Qu0M5d; Verbesserungsvorschläge BIM Base: https://forms.office.com/e/pcFhFfi5DW; Anleitung Mengen: https://evolutbaugmbh.sharepoint.com/:b:/s/External/ETgyOLO3JxJEqg9rbaRMLVEBHuWIRtkoMiJN1fISDr-3lw?e=E0LTiQ; Anleitung Eigenschaften: https://evolutbaugmbh.sharepoint.com/:b:/s/External/EQedjNXQkc1Btaftc01yAPUBtND9QzXFSH3-7sie6PGFww?e=wP4uf3; Release Notes: https://evolutbaugmbh.sharepoint.com/:b:/s/External/Eb41lwlDI71MhUVvor2V2mUBSaI-0tQK5U9oJAWxpCINuw?e=NtK3j6
Name | Länge brutto - m | Fläche brutto - m2 | Volumen netto - m3
Unterzug-025 | 8.3 | 20.75 | 5.2875
Unterzug-025 | 7.15 | 17.875 | 4.425

# IfcFooting: Beton bewehrt 300 (5)
In: Fundation
Classification: Liftunerfahrt Ortbeton (BIM Base by Evolut); Material: Beton bewehrt
05_Bauablauf - Bau-Nr.: In Abklärung; Bauablauf Etappe: In Abklärung; Bauablauf Verbauungsort: In Abklärung; Bauablauf Start Ausführung: In Abklärung; Bauablauf Ende Ausführung: In Abklärung
03_Bausystem - Tragende Funktion: In Abklärung; Umbau-Status: Neubau; Mehrschichtiger Aufbau: Beton bewehrt
01_Leistungen und Kosten - Gebäude: In Abklärung; Elementpreis - CHF: 0; BKP: 211 - Baumeisterarbeiten; eBKP-H_Nr: C01.02; eBKP-H_Beschrieb: Fundament
Massivbau Ortbeton - Ortbeton Druckfestigkeitsklasse: In Abklärung; Ortbeton Expositionsklasse: In Abklärung; Ortbeton Grösstkorn - mm: Dmax 32; Ortbeton Chloridgehaltsklasse: Cl 0.10; Ortbeton Konsistenzklasse: C3; Ortbeton Recyclingbeton: In Abklärung; Ortbeton Oberflächenausführung: In Abklärung; Ortbeton Oberflächenklasse - BOK: In Abklärung; Ortbeton Schalungstyp: In Abklärung; Ortbeton Dreikantleisten - mm: In Abklärung; Ortbeton Bew. Überdeckung oben - mm: In Abklärung; Ortbeton Bew. Überdeckung unten - mm: In Abklärung; Ortbeton Bew. Überdeckung aussen - mm: In Abklärung; Ortbeton Bew. Überdeckung innen - mm: In Abklärung; Ortbeton Bewehrungsgehalt - kg/m3: In Abklärung
02_Mengen - Stärke - m: 0.3
00_Datenstruktur - BIM Base Version: 4.0.0; Kundenergänzungen Version: v01; Klassifizierung: Liftunerfahrt Ortbeton; Klassifizierung Level 0: Fundation; Modellierungsrichtlinien: https://evolutbaugmbh.sharepoint.com/:b:/s/External/EciBgBMJMZlDgYCafV5wNokBvCJq9PUJAyVGz7O3vsjVrg?e=aLjLN9; Übersicht BIM Base: https://evolutbaugmbh.sharepoint.com/:b:/s/External/EfS4mJ9nZQpOhASXp0n2kW4B0K7N-vHKx-_6Crp5CxEFeg?e=Qu0M5d; Verbesserungsvorschläge BIM Base: https://forms.office.com/e/pcFhFfi5DW; Anleitung Mengen: https://evolutbaugmbh.sharepoint.com/:b:/s/External/ETgyOLO3JxJEqg9rbaRMLVEBHuWIRtkoMiJN1fISDr-3lw?e=E0LTiQ; Anleitung Eigenschaften: https://evolutbaugmbh.sharepoint.com/:b:/s/External/EQedjNXQkc1Btaftc01yAPUBtND9QzXFSH3-7sie6PGFww?e=wP4uf3; Release Notes: https://evolutbaugmbh.sharepoint.com/:b:/s/External/Eb41lwlDI71MhUVvor2V2mUBSaI-0tQK5U9oJAWxpCINuw?e=NtK3j6
Name | Fläche brutto - m2 | Volumen netto - m3 | Kote Unterkante | Kote Oberkante | CAD Werkzeug Typ | Höhe - m | Länge brutto - m
Deckennr.-069 | 14.725 | 4.4175 | -4.9 | -4.6 | Decke
Wand-008 | 3.8 | 1.14 | -4.6 | -3.6 | Wand | 1 | 3.8
Wand-011 | 3.875 | 0.9825 | -4.6 | -3.6 | Wand | 1 | 3.875
Wand-009 | 3.875 | 1.0725 | -4.6 | -3.6 | Wand | 1 | 3.875
Wand-010 | 3.8 | 1.05 | -4.6 | -3.6 | Wand | 1 | 3.8

# IfcFooting: Beton bewehrt 300 x 700 (9)
In: Fundation
Classification: Streifenfundament Ortbeton (BIM Base by Evolut); Material: Beton bewehrt
01_Leistungen und Kosten - Gebäude: In Abklärung; Elementpreis - CHF: 0; BKP: 211 - Baumeisterarbeiten; eBKP-H_Nr: C01.02; eBKP-H_Beschrieb: Fundament
05_Bauablauf - Bau-Nr.: In Abklärung; Bauablauf Etappe: In Abklärung; Bauablauf Verbauungsort: In Abklärung; Bauablauf Start Ausführung: In Abklärung; Bauablauf Ende Ausführung: In Abklärung
03_Bausystem - Tragende Funktion: In Abklärung; Umbau-Status: Neubau; Mehrschichtiger Aufbau: Beton bewehrt
Massivbau Ortbeton - Ortbeton Druckfestigkeitsklasse: In Abklärung; Ortbeton Expositionsklasse: In Abklärung; Ortbeton Grösstkorn - mm: Dmax 32; Ortbeton Chloridgehaltsklasse: Cl 0.10; Ortbeton Konsistenzklasse: C3; Ortbeton Recyclingbeton: In Abklärung; Ortbeton Oberflächenausführung: In Abklärung; Ortbeton Oberflächenklasse - BOK: In Abklärung; Ortbeton Schalungstyp: In Abklärung; Ortbeton Dreikantleisten - mm: In Abklärung; Ortbeton Bew. Überdeckung oben - mm: In Abklärung; Ortbeton Bew. Überdeckung unten - mm: In Abklärung; Ortbeton Bew. Überdeckung aussen - mm: In Abklärung; Ortbeton Bew. Überdeckung innen - mm: In Abklärung; Ortbeton Bewehrungsgehalt - kg/m3: In Abklärung
02_Mengen - Breite - m: 0.3; Höhe - m: 0.7; Stärke - m: 0.3
00_Datenstruktur - BIM Base Version: 4.0.0; Kundenergänzungen Version: v01; CAD Werkzeug Typ: Träger; Klassifizierung: Streifenfundament Ortbeton; Klassifizierung Level 0: Fundation; Modellierungsrichtlinien: https://evolutbaugmbh.sharepoint.com/:b:/s/External/EciBgBMJMZlDgYCafV5wNokBvCJq9PUJAyVGz7O3vsjVrg?e=aLjLN9; Übersicht BIM Base: https://evolutbaugmbh.sharepoint.com/:b:/s/External/EfS4mJ9nZQpOhASXp0n2kW4B0K7N-vHKx-_6Crp5CxEFeg?e=Qu0M5d; Verbesserungsvorschläge BIM Base: https://forms.office.com/e/pcFhFfi5DW; Anleitung Mengen: https://evolutbaugmbh.sharepoint.com/:b:/s/External/ETgyOLO3JxJEqg9rbaRMLVEBHuWIRtkoMiJN1fISDr-3lw?e=E0LTiQ; Anleitung Eigenschaften: https://evolutbaugmbh.sharepoint.com/:b:/s/External/EQedjNXQkc1Btaftc01yAPUBtND9QzXFSH3-7sie6PGFww?e=wP4uf3; Release Notes: https://evolutbaugmbh.sharepoint.com/:b:/s/External/Eb41lwlDI71MhUVvor2V2mUBSaI-0tQK5U9oJAWxpCINuw?e=NtK3j6
Name | Länge brutto - m | Fläche brutto - m2 | Volumen netto - m3 | Kote Unterkante | Kote Oberkante
Unterzug-026 | 20.8087 | 14.5661 | 4.37085 | -4.9 | -4.2
2 x Unterzug-026 | 3.8 | 2.66 | 0.798 | -4.9 | -4.2
Unterzug-026 | 4.5 | 3.15 | 0.912465 | -4.3 | -3.6
Unterzug-026 | 22.5 | 15.75 | 4.725 | -4.3 | -3.6
Unterzug-026 | 16.5 | 11.55 | 3.402 | -4.3 | -3.6
Unterzug-026 | 39 | 27.3 | 8.127 | -4.3 | -3.6
Unterzug-026 | 20.8092 | 14.5665 | 4.37058 | -4.9 | -4.2
Unterzug-026 | 20.7 | 14.49 | 4.31488 | -4.3 | -3.6

# IfcFooting: Beton bewehrt 3000 x 3000 (14)
In: Fundation
Classification: Einzelfundament Ortbeton (BIM Base by Evolut); Material: Beton bewehrt
01_Leistungen und Kosten - Gebäude: In Abklärung; Elementpreis - CHF: 0; BKP: 211 - Baumeisterarbeiten; eBKP-H_Nr: C01.02; eBKP-H_Beschrieb: Fundament
05_Bauablauf - Bau-Nr.: In Abklärung; Bauablauf Etappe: In Abklärung; Bauablauf Verbauungsort: In Abklärung; Bauablauf Start Ausführung: In Abklärung; Bauablauf Ende Ausführung: In Abklärung
03_Bausystem - Tragende Funktion: In Abklärung; Umbau-Status: Neubau; Mehrschichtiger Aufbau: Beton bewehrt
Massivbau Ortbeton - Ortbeton Druckfestigkeitsklasse: In Abklärung; Ortbeton Expositionsklasse: In Abklärung; Ortbeton Grösstkorn - mm: Dmax 32; Ortbeton Chloridgehaltsklasse: Cl 0.10; Ortbeton Konsistenzklasse: C3; Ortbeton Recyclingbeton: In Abklärung; Ortbeton Oberflächenausführung: In Abklärung; Ortbeton Oberflächenklasse - BOK: In Abklärung; Ortbeton Schalungstyp: In Abklärung; Ortbeton Dreikantleisten - mm: In Abklärung; Ortbeton Bew. Überdeckung oben - mm: In Abklärung; Ortbeton Bew. Überdeckung unten - mm: In Abklärung; Ortbeton Bew. Überdeckung aussen - mm: In Abklärung; Ortbeton Bew. Überdeckung innen - mm: In Abklärung; Ortbeton Bewehrungsgehalt - kg/m3: In Abklärung
02_Mengen - Breite - m: 3; Höhe - m: 3; Stärke - m: 3
00_Datenstruktur - BIM Base Version: 4.0.0; Kundenergänzungen Version: v01; CAD Werkzeug Typ: Stütze; Klassifizierung: Einzelfundament Ortbeton; Klassifizierung Level 0: Fundation; Modellierungsrichtlinien: https://evolutbaugmbh.sharepoint.com/:b:/s/External/EciBgBMJMZlDgYCafV5wNokBvCJq9PUJAyVGz7O3vsjVrg?e=aLjLN9; Übersicht BIM Base: https://evolutbaugmbh.sharepoint.com/:b:/s/External/EfS4mJ9nZQpOhASXp0n2kW4B0K7N-vHKx-_6Crp5CxEFeg?e=Qu0M5d; Verbesserungsvorschläge BIM Base: https://forms.office.com/e/pcFhFfi5DW; Anleitung Mengen: https://evolutbaugmbh.sharepoint.com/:b:/s/External/ETgyOLO3JxJEqg9rbaRMLVEBHuWIRtkoMiJN1fISDr-3lw?e=E0LTiQ; Anleitung Eigenschaften: https://evolutbaugmbh.sharepoint.com/:b:/s/External/EQedjNXQkc1Btaftc01yAPUBtND9QzXFSH3-7sie6PGFww?e=wP4uf3; Release Notes: https://evolutbaugmbh.sharepoint.com/:b:/s/External/Eb41lwlDI71MhUVvor2V2mUBSaI-0tQK5U9oJAWxpCINuw?e=NtK3j6
Name | Länge brutto - m | Volumen netto - m3 | Kote Unterkante | Kote Oberkante
2 x Stütze-015 | 0.400172 | 3.60155 | -4.467 | -4.067
2 x Stütze-015 | 0.400172 | 3.60155 | -4.611 | -4.211
8 x Stütze-015 | 0.40032 | 3.60288 | -4.224 | -3.824
Stütze-015 | 0.400172 | 3.60155 | -4.313 | -3.913
Stütze-015 | 0.400172 | 3.60155 | -4.321 | -3.921

# IfcFooting: Beton bewehrt 3100 x 3000 (2)
In: Fundation
Classification: Einzelfundament Ortbeton (BIM Base by Evolut); Material: Beton bewehrt
01_Leistungen und Kosten - Gebäude: In Abklärung; Elementpreis - CHF: 0; BKP: 211 - Baumeisterarbeiten; eBKP-H_Nr: C01.02; eBKP-H_Beschrieb: Fundament
05_Bauablauf - Bau-Nr.: In Abklärung; Bauablauf Etappe: In Abklärung; Bauablauf Verbauungsort: In Abklärung; Bauablauf Start Ausführung: In Abklärung; Bauablauf Ende Ausführung: In Abklärung
03_Bausystem - Tragende Funktion: In Abklärung; Umbau-Status: Neubau; Mehrschichtiger Aufbau: Beton bewehrt
Massivbau Ortbeton - Ortbeton Druckfestigkeitsklasse: In Abklärung; Ortbeton Expositionsklasse: In Abklärung; Ortbeton Grösstkorn - mm: Dmax 32; Ortbeton Chloridgehaltsklasse: Cl 0.10; Ortbeton Konsistenzklasse: C3; Ortbeton Recyclingbeton: In Abklärung; Ortbeton Oberflächenausführung: In Abklärung; Ortbeton Oberflächenklasse - BOK: In Abklärung; Ortbeton Schalungstyp: In Abklärung; Ortbeton Dreikantleisten - mm: In Abklärung; Ortbeton Bew. Überdeckung oben - mm: In Abklärung; Ortbeton Bew. Überdeckung unten - mm: In Abklärung; Ortbeton Bew. Überdeckung aussen - mm: In Abklärung; Ortbeton Bew. Überdeckung innen - mm: In Abklärung; Ortbeton Bewehrungsgehalt - kg/m3: In Abklärung
00_Datenstruktur - BIM Base Version: 4.0.0; Kundenergänzungen Version: v01; CAD Werkzeug Typ: Stütze; Klassifizierung: Einzelfundament Ortbeton; Klassifizierung Level 0: Fundation; Modellierungsrichtlinien: https://evolutbaugmbh.sharepoint.com/:b:/s/External/EciBgBMJMZlDgYCafV5wNokBvCJq9PUJAyVGz7O3vsjVrg?e=aLjLN9; Übersicht BIM Base: https://evolutbaugmbh.sharepoint.com/:b:/s/External/EfS4mJ9nZQpOhASXp0n2kW4B0K7N-vHKx-_6Crp5CxEFeg?e=Qu0M5d; Verbesserungsvorschläge BIM Base: https://forms.office.com/e/pcFhFfi5DW; Anleitung Mengen: https://evolutbaugmbh.sharepoint.com/:b:/s/External/ETgyOLO3JxJEqg9rbaRMLVEBHuWIRtkoMiJN1fISDr-3lw?e=E0LTiQ; Anleitung Eigenschaften: https://evolutbaugmbh.sharepoint.com/:b:/s/External/EQedjNXQkc1Btaftc01yAPUBtND9QzXFSH3-7sie6PGFww?e=wP4uf3; Release Notes: https://evolutbaugmbh.sharepoint.com/:b:/s/External/Eb41lwlDI71MhUVvor2V2mUBSaI-0tQK5U9oJAWxpCINuw?e=NtK3j6
02_Mengen - Breite - m: 3.1; Höhe - m: 3; Stärke - m: 3.1; Länge brutto - m: 0.40032; Volumen netto - m3: 3.72297; Kote Unterkante: -4.224; Kote Oberkante: -3.824

# IfcFooting: Beton bewehrt 500 x 500 (8)
Classification: Einzelfundament Ortbeton (BIM Base by Evolut); Material: Beton bewehrt
01_Leistungen und Kosten - Gebäude: In Abklärung; Elementpreis - CHF: 0; BKP: 211 - Baumeisterarbeiten; eBKP-H_Nr: C01.02; eBKP-H_Beschrieb: Fundament
05_Bauablauf - Bau-Nr.: In Abklärung; Bauablauf Etappe: In Abklärung; Bauablauf Verbauungsort: In Abklärung; Bauablauf Start Ausführung: In Abklärung; Bauablauf Ende Ausführung: In Abklärung
03_Bausystem - Tragende Funktion: In Abklärung; Umbau-Status: Neubau; Mehrschichtiger Aufbau: Beton bewehrt
Massivbau Ortbeton - Ortbeton Druckfestigkeitsklasse: In Abklärung; Ortbeton Expositionsklasse: In Abklärung; Ortbeton Grösstkorn - mm: Dmax 32; Ortbeton Chloridgehaltsklasse: Cl 0.10; Ortbeton Konsistenzklasse: C3; Ortbeton Recyclingbeton: In Abklärung; Ortbeton Oberflächenausführung: In Abklärung; Ortbeton Oberflächenklasse - BOK: In Abklärung; Ortbeton Schalungstyp: In Abklärung; Ortbeton Dreikantleisten - mm: In Abklärung; Ortbeton Bew. Überdeckung oben - mm: In Abklärung; Ortbeton Bew. Überdeckung unten - mm: In Abklärung; Ortbeton Bew. Überdeckung aussen - mm: In Abklärung; Ortbeton Bew. Überdeckung innen - mm: In Abklärung; Ortbeton Bewehrungsgehalt - kg/m3: In Abklärung
02_Mengen - Breite - m: 0.5; Höhe - m: 0.5; Stärke - m: 0.5
00_Datenstruktur - BIM Base Version: 4.0.0; Kundenergänzungen Version: v01; CAD Werkzeug Typ: Stütze; Klassifizierung: Einzelfundament Ortbeton; Klassifizierung Level 0: Fundation; Modellierungsrichtlinien: https://evolutbaugmbh.sharepoint.com/:b:/s/External/EciBgBMJMZlDgYCafV5wNokBvCJq9PUJAyVGz7O3vsjVrg?e=aLjLN9; Übersicht BIM Base: https://evolutbaugmbh.sharepoint.com/:b:/s/External/EfS4mJ9nZQpOhASXp0n2kW4B0K7N-vHKx-_6Crp5CxEFeg?e=Qu0M5d; Verbesserungsvorschläge BIM Base: https://forms.office.com/e/pcFhFfi5DW; Anleitung Mengen: https://evolutbaugmbh.sharepoint.com/:b:/s/External/ETgyOLO3JxJEqg9rbaRMLVEBHuWIRtkoMiJN1fISDr-3lw?e=E0LTiQ; Anleitung Eigenschaften: https://evolutbaugmbh.sharepoint.com/:b:/s/External/EQedjNXQkc1Btaftc01yAPUBtND9QzXFSH3-7sie6PGFww?e=wP4uf3; Release Notes: https://evolutbaugmbh.sharepoint.com/:b:/s/External/Eb41lwlDI71MhUVvor2V2mUBSaI-0tQK5U9oJAWxpCINuw?e=NtK3j6
Name | In | Länge brutto - m | Fläche brutto - m2 | Volumen netto - m3 | Kote Unterkante | Kote Oberkante
6 x Stütze-015 | UG | 0.25 | 0.125 | 0.0625 | -0.75 | -0.5
2 x Stütze-015 | EG | 0.5 | 0.25 | 0.125 | 0 | 0.5

# IfcFooting: Beton bewehrt 600 x 200 (3)
In: Fundation
Classification: Streifenfundament Ortbeton (BIM Base by Evolut); Material: Beton bewehrt
01_Leistungen und Kosten - Gebäude: In Abklärung; Elementpreis - CHF: 0; BKP: 211 - Baumeisterarbeiten; eBKP-H_Nr: C01.02; eBKP-H_Beschrieb: Fundament
03_Bausystem - Tragende Funktion: In Abklärung; Umbau-Status: Neubau; Mehrschichtiger Aufbau: Beton bewehrt
05_Bauablauf - Bau-Nr.: In Abklärung; Bauablauf Etappe: In Abklärung; Bauablauf Verbauungsort: In Abklärung; Bauablauf Start Ausführung: In Abklärung; Bauablauf Ende Ausführung: In Abklärung
Massivbau Ortbeton - Ortbeton Druckfestigkeitsklasse: In Abklärung; Ortbeton Expositionsklasse: In Abklärung; Ortbeton Grösstkorn - mm: Dmax 32; Ortbeton Chloridgehaltsklasse: Cl 0.10; Ortbeton Konsistenzklasse: C3; Ortbeton Recyclingbeton: In Abklärung; Ortbeton Oberflächenausführung: In Abklärung; Ortbeton Oberflächenklasse - BOK: In Abklärung; Ortbeton Schalungstyp: In Abklärung; Ortbeton Dreikantleisten - mm: In Abklärung; Ortbeton Bew. Überdeckung oben - mm: In Abklärung; Ortbeton Bew. Überdeckung unten - mm: In Abklärung; Ortbeton Bew. Überdeckung aussen - mm: In Abklärung; Ortbeton Bew. Überdeckung innen - mm: In Abklärung; Ortbeton Bewehrungsgehalt - kg/m3: In Abklärung
00_Datenstruktur - BIM Base Version: 4.0.0; Kundenergänzungen Version: v01; CAD Werkzeug Typ: Träger; Klassifizierung: Streifenfundament Ortbeton; Klassifizierung Level 0: Fundation; Modellierungsrichtlinien: https://evolutbaugmbh.sharepoint.com/:b:/s/External/EciBgBMJMZlDgYCafV5wNokBvCJq9PUJAyVGz7O3vsjVrg?e=aLjLN9; Übersicht BIM Base: https://evolutbaugmbh.sharepoint.com/:b:/s/External/EfS4mJ9nZQpOhASXp0n2kW4B0K7N-vHKx-_6Crp5CxEFeg?e=Qu0M5d; Verbesserungsvorschläge BIM Base: https://forms.office.com/e/pcFhFfi5DW; Anleitung Mengen: https://evolutbaugmbh.sharepoint.com/:b:/s/External/ETgyOLO3JxJEqg9rbaRMLVEBHuWIRtkoMiJN1fISDr-3lw?e=E0LTiQ; Anleitung Eigenschaften: https://evolutbaugmbh.sharepoint.com/:b:/s/External/EQedjNXQkc1Btaftc01yAPUBtND9QzXFSH3-7sie6PGFww?e=wP4uf3; Release Notes: https://evolutbaugmbh.sharepoint.com/:b:/s/External/Eb41lwlDI71MhUVvor2V2mUBSaI-0tQK5U9oJAWxpCINuw?e=NtK3j6
02_Mengen - Breite - m: 0.6; Höhe - m: 0.2; Stärke - m: 0.6
Name | Länge brutto - m | Fläche brutto - m2 | Volumen netto - m3 | Kote Unterkante | Kote Oberkante
Unterzug-024 | 18.75 | 11.25 | 2.25 | -4.12 | -3.92
Unterzug-024 | 14.8062 | 8.88369 | 1.77674 | -4.561 | -4.361
Unterzug-024 | 12.75 | 7.65 | 1.53 | -4.118 | -3.918

# IfcFooting: Magerbeton 50 (70)
Classification: Untergrund Magerbeton (BIM Base by Evolut); Material: Magerbeton
01_Leistungen und Kosten - Gebäude: In Abklärung; Elementpreis - CHF: 0; BKP: 211 - Baumeisterarbeiten; eBKP-H_Nr: C01.01; eBKP-H_Beschrieb: Unterbau Fundament, Bodenplatte
05_Bauablauf - Bau-Nr.: In Abklärung; Bauablauf Etappe: In Abklärung; Bauablauf Verbauungsort: In Abklärung; Bauablauf Start Ausführung: In Abklärung; Bauablauf Ende Ausführung: In Abklärung
03_Bausystem - Tragende Funktion: In Abklärung; Umbau-Status: Neubau; Mehrschichtiger Aufbau: Magerbeton
00_Datenstruktur - BIM Base Version: 4.0.0; Kundenergänzungen Version: v01; Klassifizierung: Untergrund Magerbeton; Klassifizierung Level 0: Fundation; Modellierungsrichtlinien: https://evolutbaugmbh.sharepoint.com/:b:/s/External/EciBgBMJMZlDgYCafV5wNokBvCJq9PUJAyVGz7O3vsjVrg?e=aLjLN9; Übersicht BIM Base: https://evolutbaugmbh.sharepoint.com/:b:/s/External/EfS4mJ9nZQpOhASXp0n2kW4B0K7N-vHKx-_6Crp5CxEFeg?e=Qu0M5d; Verbesserungsvorschläge BIM Base: https://forms.office.com/e/pcFhFfi5DW; Anleitung Mengen: https://evolutbaugmbh.sharepoint.com/:b:/s/External/ETgyOLO3JxJEqg9rbaRMLVEBHuWIRtkoMiJN1fISDr-3lw?e=E0LTiQ; Anleitung Eigenschaften: https://evolutbaugmbh.sharepoint.com/:b:/s/External/EQedjNXQkc1Btaftc01yAPUBtND9QzXFSH3-7sie6PGFww?e=wP4uf3; Release Notes: https://evolutbaugmbh.sharepoint.com/:b:/s/External/Eb41lwlDI71MhUVvor2V2mUBSaI-0tQK5U9oJAWxpCINuw?e=NtK3j6
Name | In | Stärke - m | Fläche brutto - m2 | Volumen netto - m3 | Kote Unterkante | Kote Oberkante | CAD Werkzeug Typ
Dach-008 | Fundation | 0.05 | 63.8808 | 3.19404 | -4.411 | -4.361 | Dach
Dach-008 | Fundation | 0.05 | 45.1909 | 2.25954 | -4.301 | -4.251 | Dach
Dach-008 | Fundation | 0.05 | 64.0324 | 3.20162 | -4.411 | -4.361 | Dach
Dach-008 | Fundation | 0.05 | 45.4129 | 2.27065 | -4.301 | -4.251 | Dach
Dach-009 | Fundation | 0.05 | 20.0763 | 1.00382 | -4.411 | -4.361 | Dach
Dach-009 | Fundation | 0.05 | 23.7168 | 1.18584 | -3.984 | -3.934 | Dach
Deckennr.-072 | Fundation | 0.05 | 18.69 | 0.924 | -3.65 | -3.6 | Decke
Deckennr.-072 | Fundation | 0.05 | 12.0399 | 0.601997 | -3.65 | -3.6 | Decke
Deckennr.-072 | Fundation | 0.05 | 27.79 | 1.3894 | -3.65 | -3.6 | Decke
Deckennr.-072 | Fundation | 0.05 | 14.697 | 0.73485 | -3.65 | -3.6 | Decke
Dach-009 | Fundation | 0.05 | 14.7741 | 0.738707 | -4.25 | -4.2 | Dach
Deckennr.-072 | Fundation | 0.05 | 3.48423 | 0.174211 | -4.25 | -4.2 | Decke
Deckennr.-070 | Fundation | 0.05 | 28.5526 | 1.4276 | -3.65 | -3.6 | Decke
Dach-009 | Fundation | 0.05 | 49.4096 | 2.47048 | -3.872 | -3.822 | Dach
Dach-009 | Fundation | 0.05 | 67.6332 | 3.38166 | -3.874 | -3.824 | Dach
Dach-009 | Fundation | 0.05 | 44.1192 | 2.20596 | -3.968 | -3.918 | Dach
Dach-009 | Fundation | 0.05 | 44.1262 | 2.20631 | -3.968 | -3.918 | Dach
Deckennr.-071 | Fundation | 0.05 | 7.90875 | 0.395437 | -3.65 | -3.6 | Decke
Dach-009 | Fundation | 0.05 | 21.6112 | 1.08056 | -3.981 | -3.931 | Dach
Dach-009 | Fundation | 0.05 | 14.5661 | 0.728303 | -4.25 | -4.2 | Dach
Dach-009 | Fundation | 0.05 | 10.7414 | 0.537071 | -3.98 | -3.93 | Dach
Deckennr.-070 | Fundation | 0.05 | 3.515 | 0.17575 | -3.65 | -3.6 | Decke
3 x Dach-009 | Fundation | 0.05 | 10.7411 | 0.537054 | -3.979 | -3.929 | Dach
Dach-009 | Fundation | 0.05 | 30.2059 | 1.51029 | -3.968 | -3.918 | Dach
Dach-009 | Fundation | 0.05 | 97.59 | 4.8795 | -3.968 | -3.918 | Dach
Dach-009 | Fundation | 0.05 | 21.6131 | 1.08065 | -3.979 | -3.929 | Dach
2 x Dach-009 | Fundation | 0.05 | 9.60646 | 0.480323 | -4.519 | -4.469 | Dach
Dach-009 | Fundation | 0.05 | 9.60646 | 0.480323 | -4.374 | -4.324 | Dach
Dach-009 | Fundation | 0.05 | 9.60646 | 0.480323 | -4.364 | -4.314 | Dach
2 x Dach-009 | Fundation | 0.05 | 9.60646 | 0.480323 | -4.663 | -4.613 | Dach
2 x Dach-009 | Fundation | 0.05 | 9.641 | 0.48205 | -4.252 | -4.202 | Dach
Dach-009 | Fundation | 0.05 | 9.7965 | 0.489825 | -4.277 | -4.227 | Dach
Dach-009 | Fundation | 0.05 | 9.641 | 0.48205 | -4.277 | -4.227 | Dach
2 x Dach-009 | Fundation | 0.05 | 9.61 | 0.4805 | -4.276 | -4.226 | Dach
4 x Dach-009 | Fundation | 0.05 | 9.61 | 0.4805 | -4.252 | -4.202 | Dach
Dach-009 | Fundation | 0.05 | 3.43956 | 0.171978 | -4.004 | -3.954 | Dach
2 x Dach-009 | Fundation | 0.05 | 3.99676 | 0.199838 | -4.23 | -4.18 | Dach
Deckennr.-074 | Fundation | 0.05 | 11.625 | 0.58125 | -4.17 | -4.12 | Decke
Dach-009 | Fundation | 0.05 | 3.45006 | 0.172503 | -4.004 | -3.954 | Dach
Deckennr.-074 | Fundation | 0.05 | 8.925 | 0.291441 | -4.148 | -4.098 | Decke
Deckennr.-069 | Fundation | 0.05 | 15.5025 | 0.775125 | -4.95 | -4.9 | Decke
Deckennr.-073 | Fundation | 0.05 | 12.4875 | 0.624375 | -4 | -3.95 | Decke
Dach-009 | Fundation | 0.05 | 10.3785 | 0.518925 | -4.612 | -4.562 | Dach
Deckennr.-072 | Fundation | 0.05 | 8.75 | 0.4375 | -4.65 | -4.6 | Decke
Deckennr.-072 | Fundation | 0.05 | 74.9916 | 3.74508 | -4.89 | -4.84 | Decke
Deckennr.-072 | Fundation | 0.05 | 8.89965 | 0.444983 | -4.65 | -4.6 | Decke
Deckennr.-072 | Fundation | 0.05 | 1.62144 | 0.0810718 | -4.25 | -4.2 | Decke
Dach-008 | Fundation | 0.0499102 | 22.6406 | 1.13 | -3.29 | -3.24 | Dach
Dach-008 | Fundation | 0.0496438 | 24.6758 | 1.225 | -3.89 | -3.841 | Dach
Deckennr.-068 | Fundation | 0.05 | 20.844 | 1.0422 | -4.19 | -4.14 | Decke
Dach-008 | Fundation | 0.0499102 | 15.9286 | 0.795 | -4.13 | -4.08 | Dach
Dach-008 | Fundation | 0.0499775 | 7.40333 | 0.37 | -4.19 | -4.14 | Dach
Deckennr.-072 | Fundation | 0.05 | 5.55 | 0.2775 | -4 | -3.95 | Decke
Dach-008 | Fundation | 0.0499775 | 6.45226 | 0.322468 | -4.225 | -4.175 | Dach
Dach-009 | Fundation | 0.05 | 67.6326 | 3.38163 | -3.874 | -3.824 | Dach
Dach-009 | Fundation | 0.05 | 10.7414 | 0.53707 | -3.98 | -3.93 | Dach
Dach-009 | Fundation | 0.05 | 0.0475428 | 0.00237714 | -3.683 | -3.633 | Dach
Deckennr.-073 | Fundation | 0.05 | 34.125 | 1.70625 | -4.115 | -4.065 | Decke
Deckennr.-071 | Fundation | 0.05 | 34.8059 | 1.74006 | -4.115 | -4.065 | Decke
Deckennr.-068 | UG | 0.05 | 94.075 | 4.70375 | -3.05 | -3 | Decke

# IfcFooting: Verschiedene Strukturen - 2 Segmente - 1500 x 1500 x 2569 (1926+642), Stütze-014
In: UG
Classification: Fundament Beton (BIM Base by Evolut)
05_Bauablauf - Bau-Nr.: In Abklärung; Bauablauf Etappe: In Abklärung; Bauablauf Verbauungsort: In Abklärung; Bauablauf Start Ausführung: In Abklärung; Bauablauf Ende Ausführung: In Abklärung
01_Leistungen und Kosten - Gebäude: In Abklärung; Elementpreis - CHF: 0; BKP: 211 - Baumeisterarbeiten; eBKP-H_Nr: C01.02; eBKP-H_Beschrieb: Fundament
02_Mengen - Breite - m: 1.5; Höhe - m: 1.5; Stärke - m: 1.5; Länge brutto - m: 2.56853; Fläche brutto - m2: 3.8528; Volumen netto - m3: 0.77056; Kote Unterkante: -3.569; Kote Oberkante: -1
00_Datenstruktur - BIM Base Version: 4.0.0; Kundenergänzungen Version: v01; CAD Werkzeug Typ: Stütze; Klassifizierung: Fundament Beton; Klassifizierung Level 0: Fundation; Modellierungsrichtlinien: https://evolutbaugmbh.sharepoint.com/:b:/s/External/EciBgBMJMZlDgYCafV5wNokBvCJq9PUJAyVGz7O3vsjVrg?e=aLjLN9; Übersicht BIM Base: https://evolutbaugmbh.sharepoint.com/:b:/s/External/EfS4mJ9nZQpOhASXp0n2kW4B0K7N-vHKx-_6Crp5CxEFeg?e=Qu0M5d; Verbesserungsvorschläge BIM Base: https://forms.office.com/e/pcFhFfi5DW; Anleitung Mengen: https://evolutbaugmbh.sharepoint.com/:b:/s/External/ETgyOLO3JxJEqg9rbaRMLVEBHuWIRtkoMiJN1fISDr-3lw?e=E0LTiQ; Anleitung Eigenschaften: https://evolutbaugmbh.sharepoint.com/:b:/s/External/EQedjNXQkc1Btaftc01yAPUBtND9QzXFSH3-7sie6PGFww?e=wP4uf3; Release Notes: https://evolutbaugmbh.sharepoint.com/:b:/s/External/Eb41lwlDI71MhUVvor2V2mUBSaI-0tQK5U9oJAWxpCINuw?e=NtK3j6
03_Bausystem - Tragende Funktion: In Abklärung; Umbau-Status: Neubau; Mehrschichtiger Aufbau: Beton bewehrt; Beton bewehrt

# IfcFooting: Verschiedene Strukturen - 2 Segmente - 1500 x 1500 x 2715 (2036+679), Stütze-014
In: UG
Classification: Fundament Beton (BIM Base by Evolut)
05_Bauablauf - Bau-Nr.: In Abklärung; Bauablauf Etappe: In Abklärung; Bauablauf Verbauungsort: In Abklärung; Bauablauf Start Ausführung: In Abklärung; Bauablauf Ende Ausführung: In Abklärung
01_Leistungen und Kosten - Gebäude: In Abklärung; Elementpreis - CHF: 0; BKP: 211 - Baumeisterarbeiten; eBKP-H_Nr: C01.02; eBKP-H_Beschrieb: Fundament
03_Bausystem - Tragende Funktion: In Abklärung; Umbau-Status: Neubau; Mehrschichtiger Aufbau: Beton bewehrt; Beton bewehrt
02_Mengen - Breite - m: 1.5; Höhe - m: 1.5; Stärke - m: 1.5; Länge brutto - m: 2.7152; Fläche brutto - m2: 4.0728; Volumen netto - m3: 0.81456; Kote Unterkante: -3.715; Kote Oberkante: -1
00_Datenstruktur - BIM Base Version: 4.0.0; Kundenergänzungen Version: v01; CAD Werkzeug Typ: Stütze; Klassifizierung: Fundament Beton; Klassifizierung Level 0: Fundation; Modellierungsrichtlinien: https://evolutbaugmbh.sharepoint.com/:b:/s/External/EciBgBMJMZlDgYCafV5wNokBvCJq9PUJAyVGz7O3vsjVrg?e=aLjLN9; Übersicht BIM Base: https://evolutbaugmbh.sharepoint.com/:b:/s/External/EfS4mJ9nZQpOhASXp0n2kW4B0K7N-vHKx-_6Crp5CxEFeg?e=Qu0M5d; Verbesserungsvorschläge BIM Base: https://forms.office.com/e/pcFhFfi5DW; Anleitung Mengen: https://evolutbaugmbh.sharepoint.com/:b:/s/External/ETgyOLO3JxJEqg9rbaRMLVEBHuWIRtkoMiJN1fISDr-3lw?e=E0LTiQ; Anleitung Eigenschaften: https://evolutbaugmbh.sharepoint.com/:b:/s/External/EQedjNXQkc1Btaftc01yAPUBtND9QzXFSH3-7sie6PGFww?e=wP4uf3; Release Notes: https://evolutbaugmbh.sharepoint.com/:b:/s/External/Eb41lwlDI71MhUVvor2V2mUBSaI-0tQK5U9oJAWxpCINuw?e=NtK3j6

# IfcFooting: Verschiedene Strukturen - 2 Segmente - 1500 x 1500 x 2862 (2146+715), Stütze-014
In: UG
Classification: Fundament Beton (BIM Base by Evolut)
05_Bauablauf - Bau-Nr.: In Abklärung; Bauablauf Etappe: In Abklärung; Bauablauf Verbauungsort: In Abklärung; Bauablauf Start Ausführung: In Abklärung; Bauablauf Ende Ausführung: In Abklärung
03_Bausystem - Tragende Funktion: In Abklärung; Umbau-Status: Neubau; Mehrschichtiger Aufbau: Beton bewehrt; Beton bewehrt
01_Leistungen und Kosten - Gebäude: In Abklärung; Elementpreis - CHF: 0; BKP: 211 - Baumeisterarbeiten; eBKP-H_Nr: C01.02; eBKP-H_Beschrieb: Fundament
02_Mengen - Breite - m: 1.5; Höhe - m: 1.5; Stärke - m: 1.5; Länge brutto - m: 2.86187; Fläche brutto - m2: 4.2928; Volumen netto - m3: 0.85856; Kote Unterkante: -3.862; Kote Oberkante: -1
00_Datenstruktur - BIM Base Version: 4.0.0; Kundenergänzungen Version: v01; CAD Werkzeug Typ: Stütze; Klassifizierung: Fundament Beton; Klassifizierung Level 0: Fundation; Modellierungsrichtlinien: https://evolutbaugmbh.sharepoint.com/:b:/s/External/EciBgBMJMZlDgYCafV5wNokBvCJq9PUJAyVGz7O3vsjVrg?e=aLjLN9; Übersicht BIM Base: https://evolutbaugmbh.sharepoint.com/:b:/s/External/EfS4mJ9nZQpOhASXp0n2kW4B0K7N-vHKx-_6Crp5CxEFeg?e=Qu0M5d; Verbesserungsvorschläge BIM Base: https://forms.office.com/e/pcFhFfi5DW; Anleitung Mengen: https://evolutbaugmbh.sharepoint.com/:b:/s/External/ETgyOLO3JxJEqg9rbaRMLVEBHuWIRtkoMiJN1fISDr-3lw?e=E0LTiQ; Anleitung Eigenschaften: https://evolutbaugmbh.sharepoint.com/:b:/s/External/EQedjNXQkc1Btaftc01yAPUBtND9QzXFSH3-7sie6PGFww?e=wP4uf3; Release Notes: https://evolutbaugmbh.sharepoint.com/:b:/s/External/Eb41lwlDI71MhUVvor2V2mUBSaI-0tQK5U9oJAWxpCINuw?e=NtK3j6

# IfcFooting: Verschiedene Strukturen - 2 Segmente - 1500 x 1500 x 3013 (2259+753), Stütze-014
In: UG
Classification: Fundament Beton (BIM Base by Evolut)
05_Bauablauf - Bau-Nr.: In Abklärung; Bauablauf Etappe: In Abklärung; Bauablauf Verbauungsort: In Abklärung; Bauablauf Start Ausführung: In Abklärung; Bauablauf Ende Ausführung: In Abklärung
03_Bausystem - Tragende Funktion: In Abklärung; Umbau-Status: Neubau; Mehrschichtiger Aufbau: Beton bewehrt; Beton bewehrt
02_Mengen - Breite - m: 1.5; Höhe - m: 1.5; Stärke - m: 1.5; Länge brutto - m: 3.0126; Fläche brutto - m2: 4.5189; Volumen netto - m3: 0.903779; Kote Unterkante: -3.569; Kote Oberkante: -0.556
00_Datenstruktur - BIM Base Version: 4.0.0; Kundenergänzungen Version: v01; CAD Werkzeug Typ: Stütze; Klassifizierung: Fundament Beton; Klassifizierung Level 0: Fundation; Modellierungsrichtlinien: https://evolutbaugmbh.sharepoint.com/:b:/s/External/EciBgBMJMZlDgYCafV5wNokBvCJq9PUJAyVGz7O3vsjVrg?e=aLjLN9; Übersicht BIM Base: https://evolutbaugmbh.sharepoint.com/:b:/s/External/EfS4mJ9nZQpOhASXp0n2kW4B0K7N-vHKx-_6Crp5CxEFeg?e=Qu0M5d; Verbesserungsvorschläge BIM Base: https://forms.office.com/e/pcFhFfi5DW; Anleitung Mengen: https://evolutbaugmbh.sharepoint.com/:b:/s/External/ETgyOLO3JxJEqg9rbaRMLVEBHuWIRtkoMiJN1fISDr-3lw?e=E0LTiQ; Anleitung Eigenschaften: https://evolutbaugmbh.sharepoint.com/:b:/s/External/EQedjNXQkc1Btaftc01yAPUBtND9QzXFSH3-7sie6PGFww?e=wP4uf3; Release Notes: https://evolutbaugmbh.sharepoint.com/:b:/s/External/Eb41lwlDI71MhUVvor2V2mUBSaI-0tQK5U9oJAWxpCINuw?e=NtK3j6
01_Leistungen und Kosten - Gebäude: In Abklärung; Elementpreis - CHF: 0; BKP: 211 - Baumeisterarbeiten; eBKP-H_Nr: C01.02; eBKP-H_Beschrieb: Fundament

# IfcFooting: Verschiedene Strukturen - 2 Segmente - 1500 x 1500 x 3015 (2261+754), Stütze-014
In: UG
Classification: Fundament Beton (BIM Base by Evolut)
01_Leistungen und Kosten - Gebäude: In Abklärung; Elementpreis - CHF: 0; BKP: 211 - Baumeisterarbeiten; eBKP-H_Nr: C01.02; eBKP-H_Beschrieb: Fundament
05_Bauablauf - Bau-Nr.: In Abklärung; Bauablauf Etappe: In Abklärung; Bauablauf Verbauungsort: In Abklärung; Bauablauf Start Ausführung: In Abklärung; Bauablauf Ende Ausführung: In Abklärung
00_Datenstruktur - BIM Base Version: 4.0.0; Kundenergänzungen Version: v01; CAD Werkzeug Typ: Stütze; Klassifizierung: Fundament Beton; Klassifizierung Level 0: Fundation; Modellierungsrichtlinien: https://evolutbaugmbh.sharepoint.com/:b:/s/External/EciBgBMJMZlDgYCafV5wNokBvCJq9PUJAyVGz7O3vsjVrg?e=aLjLN9; Übersicht BIM Base: https://evolutbaugmbh.sharepoint.com/:b:/s/External/EfS4mJ9nZQpOhASXp0n2kW4B0K7N-vHKx-_6Crp5CxEFeg?e=Qu0M5d; Verbesserungsvorschläge BIM Base: https://forms.office.com/e/pcFhFfi5DW; Anleitung Mengen: https://evolutbaugmbh.sharepoint.com/:b:/s/External/ETgyOLO3JxJEqg9rbaRMLVEBHuWIRtkoMiJN1fISDr-3lw?e=E0LTiQ; Anleitung Eigenschaften: https://evolutbaugmbh.sharepoint.com/:b:/s/External/EQedjNXQkc1Btaftc01yAPUBtND9QzXFSH3-7sie6PGFww?e=wP4uf3; Release Notes: https://evolutbaugmbh.sharepoint.com/:b:/s/External/Eb41lwlDI71MhUVvor2V2mUBSaI-0tQK5U9oJAWxpCINuw?e=NtK3j6
02_Mengen - Breite - m: 1.5; Höhe - m: 1.5; Stärke - m: 1.5; Länge brutto - m: 3.01503; Fläche brutto - m2: 4.52255; Volumen netto - m3: 0.90451; Kote Unterkante: -3.715; Kote Oberkante: -0.7
03_Bausystem - Tragende Funktion: In Abklärung; Umbau-Status: Neubau; Mehrschichtiger Aufbau: Beton bewehrt; Beton bewehrt

# IfcFooting: Verschiedene Strukturen - 2 Segmente - 1500 x 1500 x 3017 (2263+754), Stütze-014
In: UG
Classification: Fundament Beton (BIM Base by Evolut)
01_Leistungen und Kosten - Gebäude: In Abklärung; Elementpreis - CHF: 0; BKP: 211 - Baumeisterarbeiten; eBKP-H_Nr: C01.02; eBKP-H_Beschrieb: Fundament
05_Bauablauf - Bau-Nr.: In Abklärung; Bauablauf Etappe: In Abklärung; Bauablauf Verbauungsort: In Abklärung; Bauablauf Start Ausführung: In Abklärung; Bauablauf Ende Ausführung: In Abklärung
03_Bausystem - Tragende Funktion: In Abklärung; Umbau-Status: Neubau; Mehrschichtiger Aufbau: Beton bewehrt; Beton bewehrt
02_Mengen - Breite - m: 1.5; Höhe - m: 1.5; Stärke - m: 1.5; Länge brutto - m: 3.01747; Fläche brutto - m2: 4.5262; Volumen netto - m3: 0.905241; Kote Unterkante: -3.862; Kote Oberkante: -0.844
00_Datenstruktur - BIM Base Version: 4.0.0; Kundenergänzungen Version: v01; CAD Werkzeug Typ: Stütze; Klassifizierung: Fundament Beton; Klassifizierung Level 0: Fundation; Modellierungsrichtlinien: https://evolutbaugmbh.sharepoint.com/:b:/s/External/EciBgBMJMZlDgYCafV5wNokBvCJq9PUJAyVGz7O3vsjVrg?e=aLjLN9; Übersicht BIM Base: https://evolutbaugmbh.sharepoint.com/:b:/s/External/EfS4mJ9nZQpOhASXp0n2kW4B0K7N-vHKx-_6Crp5CxEFeg?e=Qu0M5d; Verbesserungsvorschläge BIM Base: https://forms.office.com/e/pcFhFfi5DW; Anleitung Mengen: https://evolutbaugmbh.sharepoint.com/:b:/s/External/ETgyOLO3JxJEqg9rbaRMLVEBHuWIRtkoMiJN1fISDr-3lw?e=E0LTiQ; Anleitung Eigenschaften: https://evolutbaugmbh.sharepoint.com/:b:/s/External/EQedjNXQkc1Btaftc01yAPUBtND9QzXFSH3-7sie6PGFww?e=wP4uf3; Release Notes: https://evolutbaugmbh.sharepoint.com/:b:/s/External/Eb41lwlDI71MhUVvor2V2mUBSaI-0tQK5U9oJAWxpCINuw?e=NtK3j6

# IfcFooting: Verschiedene Strukturen - 2 Segmente - 1500 x 1500 x 3064 (2298+766) (10)
In: UG
Classification: Fundament Beton (BIM Base by Evolut)
01_Leistungen und Kosten - Gebäude: In Abklärung; Elementpreis - CHF: 0; BKP: 211 - Baumeisterarbeiten; eBKP-H_Nr: C01.02; eBKP-H_Beschrieb: Fundament
05_Bauablauf - Bau-Nr.: In Abklärung; Bauablauf Etappe: In Abklärung; Bauablauf Verbauungsort: In Abklärung; Bauablauf Start Ausführung: In Abklärung; Bauablauf Ende Ausführung: In Abklärung
02_Mengen - Breite - m: 1.5; Höhe - m: 1.5; Stärke - m: 1.5; Länge brutto - m: 3.064; Fläche brutto - m2: 4.596; Volumen netto - m3: 0.9192; Kote Unterkante: -3.464; Kote Oberkante: -0.4
03_Bausystem - Tragende Funktion: In Abklärung; Umbau-Status: Neubau; Mehrschichtiger Aufbau: Beton bewehrt; Beton bewehrt
00_Datenstruktur - BIM Base Version: 4.0.0; Kundenergänzungen Version: v01; CAD Werkzeug Typ: Stütze; Klassifizierung: Fundament Beton; Klassifizierung Level 0: Fundation; Modellierungsrichtlinien: https://evolutbaugmbh.sharepoint.com/:b:/s/External/EciBgBMJMZlDgYCafV5wNokBvCJq9PUJAyVGz7O3vsjVrg?e=aLjLN9; Übersicht BIM Base: https://evolutbaugmbh.sharepoint.com/:b:/s/External/EfS4mJ9nZQpOhASXp0n2kW4B0K7N-vHKx-_6Crp5CxEFeg?e=Qu0M5d; Verbesserungsvorschläge BIM Base: https://forms.office.com/e/pcFhFfi5DW; Anleitung Mengen: https://evolutbaugmbh.sharepoint.com/:b:/s/External/ETgyOLO3JxJEqg9rbaRMLVEBHuWIRtkoMiJN1fISDr-3lw?e=E0LTiQ; Anleitung Eigenschaften: https://evolutbaugmbh.sharepoint.com/:b:/s/External/EQedjNXQkc1Btaftc01yAPUBtND9QzXFSH3-7sie6PGFww?e=wP4uf3; Release Notes: https://evolutbaugmbh.sharepoint.com/:b:/s/External/Eb41lwlDI71MhUVvor2V2mUBSaI-0tQK5U9oJAWxpCINuw?e=NtK3j6

# IfcFurniture: Basisschrank Block 27 (18)
Classification: Küche (BIM Base by Evolut)
01_Leistungen und Kosten - Gebäude: In Abklärung; Elementpreis - CHF: 0; BKP: 258 - Kücheneinrichtungen; eBKP-H_Nr: G05.02; eBKP-H_Beschrieb: Einbauküche
02_Mengen - Breite - m: 0.4; Höhe - m: 0.8; Länge brutto - m: 0.6; Fläche brutto - m2: 0.24; Volumen netto - m3: 0.0778351
03_Bausystem - Umbau-Status: Neubau
00_Datenstruktur - BIM Base Version: 4.0.0; Kundenergänzungen Version: v01; CAD Werkzeug Typ: Objekt; Klassifizierung: Küche; Klassifizierung Level 0: Ausstattung; Modellierungsrichtlinien: https://evolutbaugmbh.sharepoint.com/:b:/s/External/EciBgBMJMZlDgYCafV5wNokBvCJq9PUJAyVGz7O3vsjVrg?e=aLjLN9; Übersicht BIM Base: https://evolutbaugmbh.sharepoint.com/:b:/s/External/EfS4mJ9nZQpOhASXp0n2kW4B0K7N-vHKx-_6Crp5CxEFeg?e=Qu0M5d; Verbesserungsvorschläge BIM Base: https://forms.office.com/e/pcFhFfi5DW; Anleitung Mengen: https://evolutbaugmbh.sharepoint.com/:b:/s/External/ETgyOLO3JxJEqg9rbaRMLVEBHuWIRtkoMiJN1fISDr-3lw?e=E0LTiQ; Anleitung Eigenschaften: https://evolutbaugmbh.sharepoint.com/:b:/s/External/EQedjNXQkc1Btaftc01yAPUBtND9QzXFSH3-7sie6PGFww?e=wP4uf3; Release Notes: https://evolutbaugmbh.sharepoint.com/:b:/s/External/Eb41lwlDI71MhUVvor2V2mUBSaI-0tQK5U9oJAWxpCINuw?e=NtK3j6
05_Bauablauf - Bau-Nr.: In Abklärung; Bauablauf Etappe: In Abklärung; Bauablauf Verbauungsort: In Abklärung; Bauablauf Start Ausführung: In Abklärung; Bauablauf Ende Ausführung: In Abklärung
Name | In | Kote Unterkante | Kote Oberkante
6 x Esstisch-4-005 | 1.OG | 2.95 | 3.75
6 x Esstisch-4-005 | 2.OG | 5.85 | 6.65
6 x Esstisch-4-005 | Attika | 8.75 | 9.55

# IfcFurniture: Konzeptküche 27 (6)
Classification: Küche (BIM Base by Evolut)
01_Leistungen und Kosten - Gebäude: In Abklärung; Elementpreis - CHF: 0; BKP: 258 - Kücheneinrichtungen; eBKP-H_Nr: G05.02; eBKP-H_Beschrieb: Einbauküche
05_Bauablauf - Bau-Nr.: In Abklärung; Bauablauf Etappe: In Abklärung; Bauablauf Verbauungsort: In Abklärung; Bauablauf Start Ausführung: In Abklärung; Bauablauf Ende Ausführung: In Abklärung
02_Mengen - Breite - m: 3.00475; Höhe - m: 2.25
03_Bausystem - Umbau-Status: Neubau
00_Datenstruktur - BIM Base Version: 4.0.0; Kundenergänzungen Version: v01; CAD Werkzeug Typ: Objekt; Klassifizierung: Küche; Klassifizierung Level 0: Ausstattung; Modellierungsrichtlinien: https://evolutbaugmbh.sharepoint.com/:b:/s/External/EciBgBMJMZlDgYCafV5wNokBvCJq9PUJAyVGz7O3vsjVrg?e=aLjLN9; Übersicht BIM Base: https://evolutbaugmbh.sharepoint.com/:b:/s/External/EfS4mJ9nZQpOhASXp0n2kW4B0K7N-vHKx-_6Crp5CxEFeg?e=Qu0M5d; Verbesserungsvorschläge BIM Base: https://forms.office.com/e/pcFhFfi5DW; Anleitung Mengen: https://evolutbaugmbh.sharepoint.com/:b:/s/External/ETgyOLO3JxJEqg9rbaRMLVEBHuWIRtkoMiJN1fISDr-3lw?e=E0LTiQ; Anleitung Eigenschaften: https://evolutbaugmbh.sharepoint.com/:b:/s/External/EQedjNXQkc1Btaftc01yAPUBtND9QzXFSH3-7sie6PGFww?e=wP4uf3; Release Notes: https://evolutbaugmbh.sharepoint.com/:b:/s/External/Eb41lwlDI71MhUVvor2V2mUBSaI-0tQK5U9oJAWxpCINuw?e=NtK3j6
Name | In | Länge brutto - m | Fläche brutto - m2 | Volumen netto - m3 | Kote Unterkante | Kote Oberkante
Möbel-020 | 1.OG | 2.76 | 8.29312 | 5.19578 | 3.05 | 5.3
Möbel-020 | 1.OG | 2.928 | 8.79793 | 5.3252 | 3.05 | 5.3
Möbel-020 | 2.OG | 2.928 | 8.79793 | 5.3252 | 5.95 | 8.2
Möbel-020 | 2.OG | 2.76 | 8.29312 | 5.19578 | 5.95 | 8.2
Möbel-020 | Attika | 2.928 | 8.79793 | 5.3252 | 8.85 | 11.1
Möbel-020 | Attika | 2.76 | 8.29312 | 5.19578 | 8.85 | 11.1

# IfcFurniture: Stehender Schrank Block 27 (46)
Classification: Einbauschrank (BIM Base by Evolut)
01_Leistungen und Kosten - Gebäude: In Abklärung; Elementpreis - CHF: 0; BKP: 273 - Schreinerarbeiten; eBKP-H_Nr: G05.01; eBKP-H_Beschrieb: Einbauschrank, Einbauregal
05_Bauablauf - Bau-Nr.: In Abklärung; Bauablauf Etappe: In Abklärung; Bauablauf Verbauungsort: In Abklärung; Bauablauf Start Ausführung: In Abklärung; Bauablauf Ende Ausführung: In Abklärung
03_Bausystem - Umbau-Status: Neubau
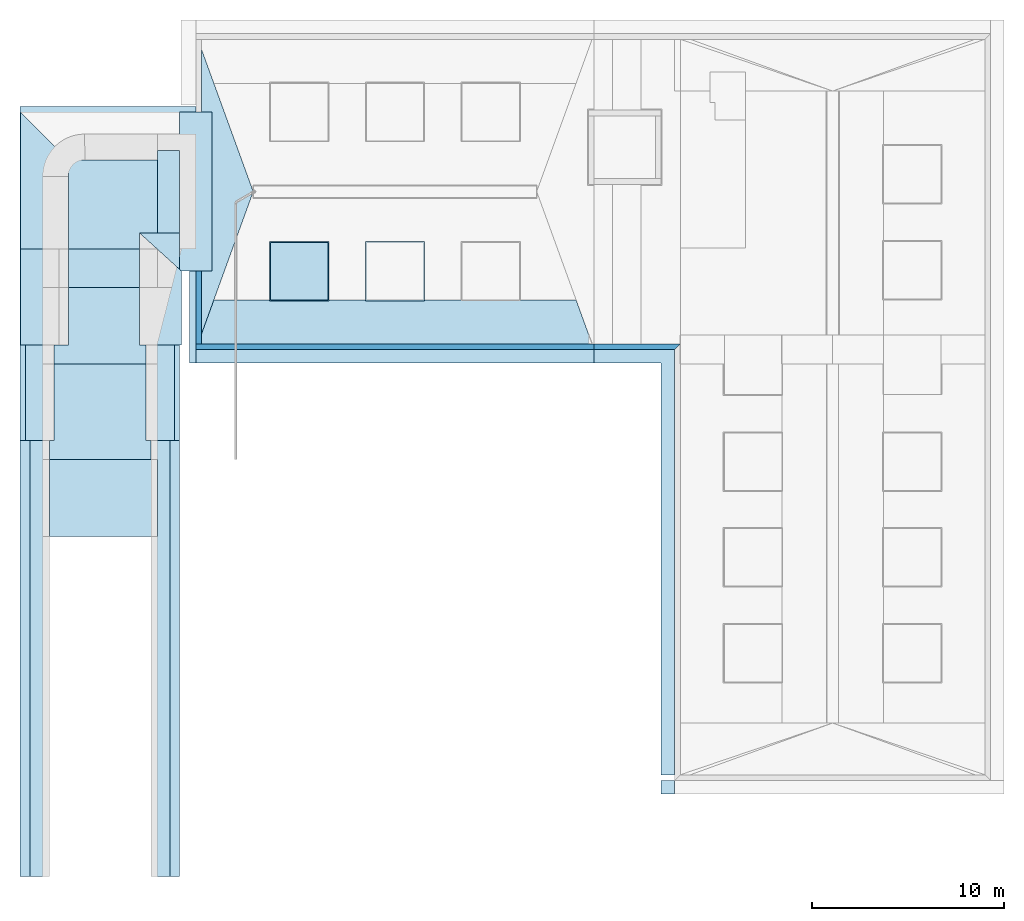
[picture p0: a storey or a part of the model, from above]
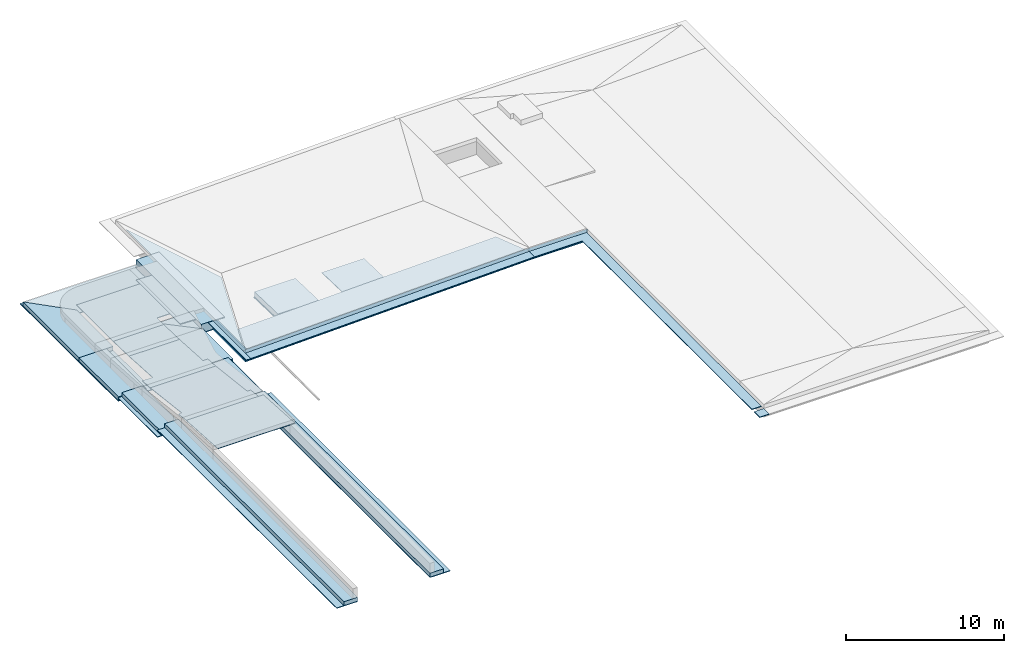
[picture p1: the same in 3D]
Properties of the parts of a building model (IFC4), part 4 of 8

# IfcFurniture: Stehender Schrank Block 27 (46)
00_Datenstruktur - BIM Base Version: 4.0.0; Kundenergänzungen Version: v01; CAD Werkzeug Typ: Objekt; Klassifizierung: Einbauschrank; Klassifizierung Level 0: Ausstattung; Modellierungsrichtlinien: https://evolutbaugmbh.sharepoint.com/:b:/s/External/EciBgBMJMZlDgYCafV5wNokBvCJq9PUJAyVGz7O3vsjVrg?e=aLjLN9; Übersicht BIM Base: https://evolutbaugmbh.sharepoint.com/:b:/s/External/EfS4mJ9nZQpOhASXp0n2kW4B0K7N-vHKx-_6Crp5CxEFeg?e=Qu0M5d; Verbesserungsvorschläge BIM Base: https://forms.office.com/e/pcFhFfi5DW; Anleitung Mengen: https://evolutbaugmbh.sharepoint.com/:b:/s/External/ETgyOLO3JxJEqg9rbaRMLVEBHuWIRtkoMiJN1fISDr-3lw?e=E0LTiQ; Anleitung Eigenschaften: https://evolutbaugmbh.sharepoint.com/:b:/s/External/EQedjNXQkc1Btaftc01yAPUBtND9QzXFSH3-7sie6PGFww?e=wP4uf3; Release Notes: https://evolutbaugmbh.sharepoint.com/:b:/s/External/Eb41lwlDI71MhUVvor2V2mUBSaI-0tQK5U9oJAWxpCINuw?e=NtK3j6
02_Mengen - Breite - m: 0.598
Name | In | Höhe - m | Länge brutto - m | Fläche brutto - m2 | Volumen netto - m3 | Kote Unterkante | Kote Oberkante
9 x Möbel-021 | 1.OG | 2.5 | 0.6 | 0.3588 | 0.129116 | 3.05 | 5.55
Möbel-021 | 1.OG | 2.5 | 0.3 | 0.1794 | 0.0888197 | 3.05 | 5.55
4 x Möbel-021 | 1.OG | 2.55 | 0.6 | 0.3588 | 0.130952 | 3.05 | 5.6
Möbel-021 | 1.OG | 2.55 | 0.6 | 0.3588 | 0.130952 | 3 | 5.55
Möbel-021 | 2.OG | 2.5 | 0.391 | 0.233818 | 0.101043 | 5.95 | 8.45
5 x Möbel-021 | 2.OG | 2.55 | 0.6 | 0.3588 | 0.130952 | 5.95 | 8.5
10 x Möbel-021 | 2.OG | 2.5 | 0.6 | 0.3588 | 0.129116 | 5.95 | 8.45
Möbel-021 | 2.OG | 2.55 | 0.6 | 0.3588 | 0.130952 | 5.9 | 8.45
Möbel-021 | 2.OG | 2.5 | 0.3 | 0.1794 | 0.0888197 | 5.95 | 8.45
9 x Möbel-021 | Attika | 2.5 | 0.6 | 0.3588 | 0.129116 | 8.85 | 11.35
2 x Möbel-021 | Attika | 2.55 | 0.6 | 0.3588 | 0.130952 | 8.85 | 11.4
Möbel-021 | Attika | 2.55 | 0.6 | 0.3588 | 0.130952 | 8.8 | 11.35
Möbel-021 | Attika | 2.5 | 0.3 | 0.1794 | 0.0888197 | 8.85 | 11.35

# IfcFurniture: Tisch-Stuhlgruppe eckig 27 (6)
Classification: Möbel (BIM Base by Evolut)
01_Leistungen und Kosten - Gebäude: In Abklärung; Elementpreis - CHF: 0; BKP: 90 - Möbel; eBKP-H_Nr: J01.02; eBKP-H_Beschrieb: Nutzungsspezifisches Mobiliar
05_Bauablauf - Bau-Nr.: In Abklärung; Bauablauf Etappe: In Abklärung; Bauablauf Verbauungsort: In Abklärung; Bauablauf Start Ausführung: In Abklärung; Bauablauf Ende Ausführung: In Abklärung
02_Mengen - Breite - m: 1.54; Höhe - m: 0.85
03_Bausystem - Umbau-Status: Neubau
00_Datenstruktur - BIM Base Version: 4.0.0; Kundenergänzungen Version: v01; CAD Werkzeug Typ: Objekt; Klassifizierung: Möbel; Klassifizierung Level 0: Ausstattung; Modellierungsrichtlinien: https://evolutbaugmbh.sharepoint.com/:b:/s/External/EciBgBMJMZlDgYCafV5wNokBvCJq9PUJAyVGz7O3vsjVrg?e=aLjLN9; Übersicht BIM Base: https://evolutbaugmbh.sharepoint.com/:b:/s/External/EfS4mJ9nZQpOhASXp0n2kW4B0K7N-vHKx-_6Crp5CxEFeg?e=Qu0M5d; Verbesserungsvorschläge BIM Base: https://forms.office.com/e/pcFhFfi5DW; Anleitung Mengen: https://evolutbaugmbh.sharepoint.com/:b:/s/External/ETgyOLO3JxJEqg9rbaRMLVEBHuWIRtkoMiJN1fISDr-3lw?e=E0LTiQ; Anleitung Eigenschaften: https://evolutbaugmbh.sharepoint.com/:b:/s/External/EQedjNXQkc1Btaftc01yAPUBtND9QzXFSH3-7sie6PGFww?e=wP4uf3; Release Notes: https://evolutbaugmbh.sharepoint.com/:b:/s/External/Eb41lwlDI71MhUVvor2V2mUBSaI-0tQK5U9oJAWxpCINuw?e=NtK3j6
Name | In | Länge brutto - m | Fläche brutto - m2 | Volumen netto - m3 | Kote Unterkante | Kote Oberkante
2 x Esstisch-4-001 | 1.OG | 2.2 | 3.388 | 0.11453 | 3.05 | 3.9
2 x Esstisch-4-001 | 2.OG | 2.2 | 3.388 | 0.11453 | 5.95 | 6.8
Esstisch-4-001 | Attika | 1.6 | 2.464 | 0.0825611 | 8.85 | 9.7
Esstisch-4-001 | Attika | 1.8 | 2.772 | 0.10093 | 8.85 | 9.7

# IfcGeographicElement: Lichtschacht 27 (7)
In: Gelände
Classification: Kleinbauwerk (BIM Base by Evolut)
00_Datenstruktur - BIM Base Version: 4.0.0; Kundenergänzungen Version: v01; CAD Werkzeug Typ: Objekt; Klassifizierung: Kleinbauwerk; Klassifizierung Level 0: Umgebung; Modellierungsrichtlinien: https://evolutbaugmbh.sharepoint.com/:b:/s/External/EciBgBMJMZlDgYCafV5wNokBvCJq9PUJAyVGz7O3vsjVrg?e=aLjLN9; Übersicht BIM Base: https://evolutbaugmbh.sharepoint.com/:b:/s/External/EfS4mJ9nZQpOhASXp0n2kW4B0K7N-vHKx-_6Crp5CxEFeg?e=Qu0M5d; Verbesserungsvorschläge BIM Base: https://forms.office.com/e/pcFhFfi5DW; Anleitung Mengen: https://evolutbaugmbh.sharepoint.com/:b:/s/External/ETgyOLO3JxJEqg9rbaRMLVEBHuWIRtkoMiJN1fISDr-3lw?e=E0LTiQ; Anleitung Eigenschaften: https://evolutbaugmbh.sharepoint.com/:b:/s/External/EQedjNXQkc1Btaftc01yAPUBtND9QzXFSH3-7sie6PGFww?e=wP4uf3; Release Notes: https://evolutbaugmbh.sharepoint.com/:b:/s/External/Eb41lwlDI71MhUVvor2V2mUBSaI-0tQK5U9oJAWxpCINuw?e=NtK3j6
03_Bausystem - Umbau-Status: Neubau
02_Mengen - Breite - m: 0.66; Höhe - m: 2.5; Länge brutto - m: 1.32; Volumen netto - m3: 0.377071
05_Bauablauf - Bau-Nr.: In Abklärung; Bauablauf Etappe: In Abklärung; Bauablauf Verbauungsort: In Abklärung; Bauablauf Start Ausführung: In Abklärung; Bauablauf Ende Ausführung: In Abklärung
01_Leistungen und Kosten - Gebäude: In Abklärung; BKP: 429 - Übriges Umgebung; Elementpreis - CHF: 0; eBKP-H_Nr: I02.05; eBKP-H_Beschrieb: Kleinbauwerk
Name | Kote Unterkante | Kote Oberkante
4 x Möbel-015 | -3 | -0.5
3 x Möbel-015 | -2.2 | 0.3

# IfcOpeningElement (296)
Name | In
Tür-007 | UG
Tür-008 | UG
59 x Fenster-004 | EG
2 x Tür-010 | EG
Tür-007 | EG
 | EG
57 x Fenster-004 | 1.OG
2 x  | 1.OG
9 x Tür-011 | 1.OG
Tür-010 | 1.OG
Tür-007 | 1.OG
DD-020 | 2.OG | Classification: Öffnung (BIM Base by Evolut); 01_Leistungen und Kosten - Gebäude: In Abklärung; Elementpreis - CHF: 0; eBKP-H_Nr: C05.01; eBKP-H_Beschrieb: Durchbruch, Schlitz zu Konstruktion; 02_Mengen - Breite - m: 0.5; Höhe - m: 0.5; Breite Lichtmass - m: 0.5; Höhe Lichtmass - m: 0.5; Delta Höhe unten - m: 0.25; Kote Unterkante: 7.45; Kote Oberkante: 7.95; 05_Bauablauf - Bau-Nr.: In Abklärung; Bauablauf Etappe: In Abklärung; Bauablauf Verbauungsort: In Abklärung; Bauablauf Start Ausführung: In Abklärung; Bauablauf Ende Ausführung: In Abklärung; 03_Bausystem - Umbau-Status: Neubau; 00_Datenstruktur - BIM Base Version: 4.0.0; Kundenergänzungen Version: v01; CAD Werkzeug Typ: Öffnung; Klassifizierung: Öffnung; Klassifizierung Level 0: Öffnung; Modellierungsrichtlinien: https://evolutbaugmbh.sharepoint.com/:b:/s/External/EciBgBMJMZlDgYCafV5wNokBvCJq9PUJAyVGz7O3vsjVrg?e=aLjLN9; Übersicht BIM Base: https://evolutbaugmbh.sharepoint.com/:b:/s/External/EfS4mJ9nZQpOhASXp0n2kW4B0K7N-vHKx-_6Crp5CxEFeg?e=Qu0M5d; Verbesserungsvorschläge BIM Base: https://forms.office.com/e/pcFhFfi5DW; Anleitung Mengen: https://evolutbaugmbh.sharepoint.com/:b:/s/External/ETgyOLO3JxJEqg9rbaRMLVEBHuWIRtkoMiJN1fISDr-3lw?e=E0LTiQ; Anleitung Eigenschaften: https://evolutbaugmbh.sharepoint.com/:b:/s/External/EQedjNXQkc1Btaftc01yAPUBtND9QzXFSH3-7sie6PGFww?e=wP4uf3; Release Notes: https://evolutbaugmbh.sharepoint.com/:b:/s/External/Eb41lwlDI71MhUVvor2V2mUBSaI-0tQK5U9oJAWxpCINuw?e=NtK3j6
60 x Fenster-004 | 2.OG
hervorheben | 2.OG
Tür-012 | 2.OG
9 x Tür-011 | 2.OG
Tür-007 | 2.OG
 | 2.OG
8 x Tür-011 | Attika
Tür-009 | Attika
53 x Fenster-004 | Attika
2 x  | Attika
Türzarge Typ 01 | Attika
Tür-007 | Attika
DD-006 | Attika
20 x Fenster-004 | Dachaufsicht

# IfcPipeSegment: IfcPipeSegment (6)
In: Fundation
Classification: Sanitär Leitung Abwasser (BIM Base by Evolut); Group: Wasser - Abwasser
01_Leistungen und Kosten - Gebäude: In Abklärung; Elementpreis - CHF: 0; BKP: 254 - Sanitärleitungen; eBKP-H_Nr: D09.05; eBKP-H_Beschrieb: Abwasser: Armatur, Apparat
05_Bauablauf - Bau-Nr.: In Abklärung; Bauablauf Etappe: In Abklärung; Bauablauf Verbauungsort: In Abklärung; Bauablauf Start Ausführung: In Abklärung; Bauablauf Ende Ausführung: In Abklärung
02_Mengen - Durchmesser - m: 0.15
03_Bausystem - Umbau-Status: Neubau
00_Datenstruktur - BIM Base Version: 4.0.0; Kundenergänzungen Version: v01; Klassifizierung: Sanitär Leitung Abwasser; Klassifizierung Level 0: Haustechnik; Modellierungsrichtlinien: https://evolutbaugmbh.sharepoint.com/:b:/s/External/EciBgBMJMZlDgYCafV5wNokBvCJq9PUJAyVGz7O3vsjVrg?e=aLjLN9; Übersicht BIM Base: https://evolutbaugmbh.sharepoint.com/:b:/s/External/EfS4mJ9nZQpOhASXp0n2kW4B0K7N-vHKx-_6Crp5CxEFeg?e=Qu0M5d; Verbesserungsvorschläge BIM Base: https://forms.office.com/e/pcFhFfi5DW; Anleitung Mengen: https://evolutbaugmbh.sharepoint.com/:b:/s/External/ETgyOLO3JxJEqg9rbaRMLVEBHuWIRtkoMiJN1fISDr-3lw?e=E0LTiQ; Anleitung Eigenschaften: https://evolutbaugmbh.sharepoint.com/:b:/s/External/EQedjNXQkc1Btaftc01yAPUBtND9QzXFSH3-7sie6PGFww?e=wP4uf3; Release Notes: https://evolutbaugmbh.sharepoint.com/:b:/s/External/Eb41lwlDI71MhUVvor2V2mUBSaI-0tQK5U9oJAWxpCINuw?e=NtK3j6
Name | Kote Unterkante | CAD Werkzeug Typ | Länge brutto - m
2 x Rohrbogen - 001 | -5.137 | Rohr-Bogen
Rohr - 001 | -5.137 | Starres Rohrsegment | 0.871864
Rohr - 001 | -5.137 | Starres Rohrsegment | 13.3445
Rohr - 001 | -4.912 | Starres Rohrsegment | 0.162197
Rohr - 001 | -4.75 | Starres Rohrsegment | 0.188374

# IfcPlate: Podest Typ 01 300 (7)
Classification: Innenpodest Beton vorfabriziert (BIM Base by Evolut)
01_Leistungen und Kosten - Gebäude: In Abklärung; Elementpreis - CHF: 0; BKP: 211 - Baumeisterarbeiten; eBKP-H_Nr: C04.03; eBKP-H_Beschrieb: Innen liegendes Podest
05_Bauablauf - Bau-Nr.: In Abklärung; Bauablauf Etappe: In Abklärung; Bauablauf Verbauungsort: In Abklärung; Bauablauf Start Ausführung: In Abklärung; Bauablauf Ende Ausführung: In Abklärung
03_Bausystem - Tragende Funktion: In Abklärung; Feuerwiderstand: In Abklärung; Trittschall: In Abklärung; Umbau-Status: Neubau; Mehrschichtiger Aufbau: Beton bewehrt; Sichtbeton
Massivbau Beton vorfabriziert - Beton vorfabriziert Druckfestigkeitsklasse: In Abklärung; Beton vorfabriziert Expositionsklasse: In Abklärung; Beton vorfabriziert Grösstkorn - mm: Dmax 32; Beton vorfabriziert Chloridgehaltsklasse: Cl 0.10; Beton vorfabriziert Konsistenzklasse: C3; Beton vorfabriziert Recyclingbeton: In Abklärung; Beton vorfabriziert Betonsorte zusammengestellt: In Abklärung; Beton vorfabriziert Oberflächenklasse - BOK: In Abklärung; Beton vorfabriziert Schalungstyp: In Abklärung; Beton vorfabriziert Dreikantleisten - mm: In Abklärung; Beton vorfabriziert Bew. Überdeckung oben - mm: In Abklärung; Beton vorfabriziert Bew. Überdeckung unten - mm: In Abklärung; Beton vorfabriziert Bew. Überdeckung aussen - mm: In Abklärung; Beton vorfabriziert Bew. Überdeckung innen - mm: In Abklärung; Beton vorfabriziert Bewehrungsgehalt - kg/m3: In Abklärung
Bekleidung - Bekleidung Gipserarbeiten: In Abklärung; Bekleidung Malerarbeiten: In Abklärung; Bekleidung Putz: In Abklärung; Bekleidung Farbe: RAL / NCS
02_Mengen - Stärke - m: 0.3
00_Datenstruktur - BIM Base Version: 4.0.0; Kundenergänzungen Version: v01; CAD Werkzeug Typ: Decke; Klassifizierung: Innenpodest Beton vorfabriziert; Klassifizierung Level 0: Podest; Modellierungsrichtlinien: https://evolutbaugmbh.sharepoint.com/:b:/s/External/EciBgBMJMZlDgYCafV5wNokBvCJq9PUJAyVGz7O3vsjVrg?e=aLjLN9; Übersicht BIM Base: https://evolutbaugmbh.sharepoint.com/:b:/s/External/EfS4mJ9nZQpOhASXp0n2kW4B0K7N-vHKx-_6Crp5CxEFeg?e=Qu0M5d; Verbesserungsvorschläge BIM Base: https://forms.office.com/e/pcFhFfi5DW; Anleitung Mengen: https://evolutbaugmbh.sharepoint.com/:b:/s/External/ETgyOLO3JxJEqg9rbaRMLVEBHuWIRtkoMiJN1fISDr-3lw?e=E0LTiQ; Anleitung Eigenschaften: https://evolutbaugmbh.sharepoint.com/:b:/s/External/EQedjNXQkc1Btaftc01yAPUBtND9QzXFSH3-7sie6PGFww?e=wP4uf3; Release Notes: https://evolutbaugmbh.sharepoint.com/:b:/s/External/Eb41lwlDI71MhUVvor2V2mUBSaI-0tQK5U9oJAWxpCINuw?e=NtK3j6
Name | In | Fläche brutto - m2 | Volumen netto - m3 | Kote Unterkante | Kote Oberkante
Deckennr.-073 | UG | 4.40838 | 1.13521 | 0.34 | 0.64
Deckennr.-073 | EG | 23.133 | 6.74951 | 2.75 | 3.05
Deckennr.-073 | EG | 4.38171 | 1.25211 | 3.25 | 3.55
Deckennr.-073 | 1.OG | 4.38171 | 1.24706 | 6.15 | 6.45
Deckennr.-073 | 1.OG | 23.133 | 6.80006 | 5.65 | 5.95
Deckennr.-073 | 2.OG | 23.133 | 6.79989 | 8.55 | 8.85
Deckennr.-073 | 2.OG | 2.94971 | 0.851314 | 9.05 | 9.35

# IfcRailing: Geländerart (37)
00_Datenstruktur - BIM Base Version: 4.0.0; Kundenergänzungen Version: v01; CAD Werkzeug Typ: Geländer; Klassifizierung Level 0: Absturzsicherung; Modellierungsrichtlinien: https://evolutbaugmbh.sharepoint.com/:b:/s/External/EciBgBMJMZlDgYCafV5wNokBvCJq9PUJAyVGz7O3vsjVrg?e=aLjLN9; Übersicht BIM Base: https://evolutbaugmbh.sharepoint.com/:b:/s/External/EfS4mJ9nZQpOhASXp0n2kW4B0K7N-vHKx-_6Crp5CxEFeg?e=Qu0M5d; Verbesserungsvorschläge BIM Base: https://forms.office.com/e/pcFhFfi5DW; Anleitung Mengen: https://evolutbaugmbh.sharepoint.com/:b:/s/External/ETgyOLO3JxJEqg9rbaRMLVEBHuWIRtkoMiJN1fISDr-3lw?e=E0LTiQ; Anleitung Eigenschaften: https://evolutbaugmbh.sharepoint.com/:b:/s/External/EQedjNXQkc1Btaftc01yAPUBtND9QzXFSH3-7sie6PGFww?e=wP4uf3; Release Notes: https://evolutbaugmbh.sharepoint.com/:b:/s/External/Eb41lwlDI71MhUVvor2V2mUBSaI-0tQK5U9oJAWxpCINuw?e=NtK3j6
03_Bausystem - Umbau-Status: Neubau
01_Leistungen und Kosten - Gebäude: In Abklärung; Elementpreis - CHF: 0; BKP: 272 - Metallbauarbeiten
05_Bauablauf - Bau-Nr.: In Abklärung; Bauablauf Etappe: In Abklärung; Bauablauf Verbauungsort: In Abklärung; Bauablauf Start Ausführung: In Abklärung; Bauablauf Ende Ausführung: In Abklärung
Name | In | Classification | Material | Klassifizierung | Mehrschichtiger Aufbau | Höhe - m | Länge brutto - m | Fläche brutto - m2 | Kote Unterkante | Kote Oberkante | Absturzsicherung Oberflächenbehandlung = Absturzsicherung Handlauf | eBKP-H_Nr | eBKP-H_Beschrieb
Geländer-001 | UG | Absturzsicherung innen Staketengeländer (BIM Base by Evolut) | Vollholzwerkstoff (56) | Absturzsicherung innen Staketengeländer | Vollholzwerkstoff | 3.30991 | 13.9161 | 46.061 | -3.3 | 0.01 | In Abklärung | G05.05 | Absturz-, Anprallschutzeinrichtung
Geländer-001 | EG | Absturzsicherung innen Staketengeländer (BIM Base by Evolut) | Vollholzwerkstoff (56) | Absturzsicherung innen Staketengeländer | Vollholzwerkstoff | 2.86 | 13.9161 | 39.8 | 0.05 | 2.91 | In Abklärung | G05.05 | Absturz-, Anprallschutzeinrichtung
Geländer-001 | EG | Absturzsicherung Aussen Staketengeländer Holz (BIM Base by Evolut) | Vollholzwerkstoff (21) | Absturzsicherung Aussen Staketengeländer Holz | Vollholzwerkstoff | 2.86 | 3.31299 | 9.47516 | 0 | 2.86 | In Abklärung | E02.06 | Aussen liegende Absturzsicherung
Geländer-001 | EG | Absturzsicherung Aussen Staketengeländer Holz (BIM Base by Evolut) | Vollholzwerkstoff (28) | Absturzsicherung Aussen Staketengeländer Holz | Vollholzwerkstoff | 3.355 | 4.7508 | 15.9389 | -0.465 | 2.89 | In Abklärung | E02.06 | Aussen liegende Absturzsicherung
Geländer-001 | 1.OG | Absturzsicherung innen Staketengeländer (BIM Base by Evolut) | Vollholzwerkstoff (56) | Absturzsicherung innen Staketengeländer | Vollholzwerkstoff | 2.86 | 13.9161 | 39.8 | 2.95 | 5.81 | In Abklärung | G05.05 | Absturz-, Anprallschutzeinrichtung
2 x Geländer-001 | 1.OG | Absturzsicherung Aussen Staketengeländer Metall (BIM Base by Evolut) | Chrom (6), Glas (2), Lattenrost vertikal | Absturzsicherung Aussen Staketengeländer Metall | Lattenrost vertikal; Glas; Chrom | 1 | 1.19915 | 1.19915 | 3.5 | 4.5 | In Abklärung | E02.06 | Aussen liegende Absturzsicherung
Geländer-001 | 1.OG | Absturzsicherung Aussen Staketengeländer Holz (BIM Base by Evolut) | Vollholzwerkstoff (5) | Absturzsicherung Aussen Staketengeländer Holz | Vollholzwerkstoff | 2.61 | 0.59 | 1.5399 | 2.9 | 5.51 | In Abklärung | E02.06 | Aussen liegende Absturzsicherung
Geländer-003 | 1.OG | Absturzsicherung Aussen Staketengeländer Metall (BIM Base by Evolut) | Stahl (14) | Absturzsicherung Aussen Staketengeländer Metall | Stahl | 1 | 1.7465 | 1.7465 | 2.936 | 3.936 | In Abklärung | E02.06 | Aussen liegende Absturzsicherung
Geländer-001 | 1.OG | Absturzsicherung Aussen Staketengeländer Holz (BIM Base by Evolut) | Vollholzwerkstoff (26) | Absturzsicherung Aussen Staketengeländer Holz | Vollholzwerkstoff | 2.575 | 4.7508 | 12.2333 | 2.935 | 5.51 | In Abklärung | E02.06 | Aussen liegende Absturzsicherung
Geländer-001 | 1.OG | Absturzsicherung Aussen Staketengeländer Holz (BIM Base by Evolut) | Vollholzwerkstoff (21) | Absturzsicherung Aussen Staketengeländer Holz | Vollholzwerkstoff | 2.61 | 3.31299 | 8.64691 | 2.9 | 5.51 | In Abklärung | E02.06 | Aussen liegende Absturzsicherung
2 x Geländer-003 | 1.OG | Absturzsicherung Aussen Staketengeländer Metall (BIM Base by Evolut) | Stahl (29) | Absturzsicherung Aussen Staketengeländer Metall | Stahl | 1 | 4.6908 | 4.6908 | 2.936 | 3.936 | In Abklärung | E02.06 | Aussen liegende Absturzsicherung
Geländer-001 | 1.OG | Absturzsicherung Aussen Staketengeländer Holz (BIM Base by Evolut) | Vollholzwerkstoff (26) | Absturzsicherung Aussen Staketengeländer Holz | Vollholzwerkstoff | 2.825 | 4.7508 | 13.421 | 2.935 | 5.76 | In Abklärung | E02.06 | Aussen liegende Absturzsicherung
Geländer-001 | 1.OG | Absturzsicherung Aussen Staketengeländer Holz (BIM Base by Evolut) | Vollholzwerkstoff (25) | Absturzsicherung Aussen Staketengeländer Holz | Vollholzwerkstoff | 2.825 | 4.7508 | 13.421 | 2.935 | 5.76 | In Abklärung | E02.06 | Aussen liegende Absturzsicherung
Geländer-003 | 1.OG | Absturzsicherung Aussen Staketengeländer Metall (BIM Base by Evolut) | Stahl (101) | Absturzsicherung Aussen Staketengeländer Metall | Stahl | 1 | 18.1613 | 18.1613 | 2.936 | 3.936 | In Abklärung | E02.06 | Aussen liegende Absturzsicherung
Geländer-001 | 2.OG | Absturzsicherung innen Staketengeländer (BIM Base by Evolut) | Vollholzwerkstoff (56) | Absturzsicherung innen Staketengeländer | Vollholzwerkstoff | 2.86 | 13.9161 | 39.8 | 5.85 | 8.71 | In Abklärung | G05.05 | Absturz-, Anprallschutzeinrichtung
Geländer-003 | 2.OG | Absturzsicherung Aussen Staketengeländer Metall (BIM Base by Evolut) | Stahl (71) | Absturzsicherung Aussen Staketengeländer Metall | Stahl | 1 | 12.4715 | 12.4715 | 6.605 | 7.605 | In Abklärung | E02.06 | Aussen liegende Absturzsicherung
2 x Geländer-003 | 2.OG | Absturzsicherung Aussen Staketengeländer Metall (BIM Base by Evolut) | Stahl (27) | Absturzsicherung Aussen Staketengeländer Metall | Stahl | 1 | 3.679 | 3.679 | 6.605 | 7.605 | In Abklärung | E02.06 | Aussen liegende Absturzsicherung
Geländer-003 | 2.OG | Absturzsicherung Aussen Staketengeländer Metall (BIM Base by Evolut) | Stahl (127) | Absturzsicherung Aussen Staketengeländer Metall | Stahl | 1 | 23.3132 | 23.3132 | 5.836 | 6.836 | In Abklärung | E02.06 | Aussen liegende Absturzsicherung
Geländer-003 | 2.OG | Absturzsicherung Aussen Staketengeländer Metall (BIM Base by Evolut) | Stahl (14) | Absturzsicherung Aussen Staketengeländer Metall | Stahl | 1 | 1.7465 | 1.7465 | 5.836 | 6.836 | In Abklärung | E02.06 | Aussen liegende Absturzsicherung
Geländer-001 | 2.OG | Absturzsicherung Aussen Staketengeländer Holz (BIM Base by Evolut) | Vollholzwerkstoff (26) | Absturzsicherung Aussen Staketengeländer Holz | Vollholzwerkstoff | 2.575 | 4.7508 | 12.2333 | 5.835 | 8.41 | In Abklärung | E02.06 | Aussen liegende Absturzsicherung
2 x Geländer-003 | 2.OG | Absturzsicherung Aussen Staketengeländer Metall (BIM Base by Evolut) | Stahl (29) | Absturzsicherung Aussen Staketengeländer Metall | Stahl | 1 | 4.6908 | 4.6908 | 5.836 | 6.836 | In Abklärung | E02.06 | Aussen liegende Absturzsicherung
Geländer-001 | 2.OG | Absturzsicherung Aussen Staketengeländer Holz (BIM Base by Evolut) | Vollholzwerkstoff (26) | Absturzsicherung Aussen Staketengeländer Holz | Vollholzwerkstoff | 2.825 | 4.7508 | 13.421 | 5.835 | 8.66 | In Abklärung | E02.06 | Aussen liegende Absturzsicherung
Geländer-001 | Attika | Absturzsicherung innen Staketengeländer (BIM Base by Evolut) | Vollholzwerkstoff (56) | Absturzsicherung innen Staketengeländer | Vollholzwerkstoff | 3.41018 | 13.9161 | 47.4563 | 8.75 | 12.16 | In Abklärung | G05.05 | Absturz-, Anprallschutzeinrichtung
Geländer-002 | Attika | Absturzsicherung innen Staketengeländer (BIM Base by Evolut) | Vollholzwerkstoff (27) | Absturzsicherung innen Staketengeländer | Vollholzwerkstoff | 1.14584 | 7.77751 | 8.91181 | 9.474 | 10.62 | In Abklärung | G05.05 | Absturz-, Anprallschutzeinrichtung
Geländer-003 | Attika | Absturzsicherung Aussen Staketengeländer Metall (BIM Base by Evolut) | Stahl (18) | Absturzsicherung Aussen Staketengeländer Metall | Stahl | 0.8 | 1.99966 | 1.59973 | 9.206 | 10.006 | In Abklärung | E02.06 | Aussen liegende Absturzsicherung
3 x Geländer-003 | Attika | Absturzsicherung Aussen Staketengeländer Metall (BIM Base by Evolut) | Stahl (29) | Absturzsicherung Aussen Staketengeländer Metall | Stahl | 0.8 | 4.6908 | 3.75264 | 9.206 | 10.006 | In Abklärung | E02.06 | Aussen liegende Absturzsicherung
Geländer-001 | Attika | Absturzsicherung Aussen Staketengeländer Holz (BIM Base by Evolut) | Vollholzwerkstoff (26) | Absturzsicherung Aussen Staketengeländer Holz | Vollholzwerkstoff | 2.575 | 4.7508 | 12.2333 | 8.735 | 11.31 | In Abklärung | E02.06 | Aussen liegende Absturzsicherung
Geländer-003 | Attika | Absturzsicherung Aussen Staketengeländer Metall (BIM Base by Evolut) | Stahl (111) | Absturzsicherung Aussen Staketengeländer Metall | Stahl | 0.8 | 20.1078 | 16.0862 | 9.206 | 10.006 | In Abklärung | E02.06 | Aussen liegende Absturzsicherung
Geländer-003 | Attika | Absturzsicherung Aussen Staketengeländer Metall (BIM Base by Evolut) | Stahl (31) | Absturzsicherung Aussen Staketengeländer Metall | Stahl | 0.8 | 4.5675 | 3.654 | 9.206 | 10.006 | In Abklärung | E02.06 | Aussen liegende Absturzsicherung
Geländer-002 | Dachaufsicht | Absturzsicherung innen Staketengeländer (BIM Base by Evolut) | Vollholzwerkstoff (25) | Absturzsicherung innen Staketengeländer | Vollholzwerkstoff | 1.00004 | 7.54809 | 7.5484 | 12.21 | 13.21 | In Abklärung | G05.05 | Absturz-, Anprallschutzeinrichtung
Geländer-001 | Dachaufsicht | Absturzsicherung innen Glas (BIM Base by Evolut) | Stahl (5), Glas | Absturzsicherung innen Glas | Glas; Stahl | 1 | 7.021 | 7.021 | 12.25 | 13.25 |  | G05.05 | Absturz-, Anprallschutzeinrichtung

# IfcRamp: Beton bewehrt 300 (7)
Classification: Aussenrampe Ortbeton (BIM Base by Evolut); Material: Beton bewehrt
05_Bauablauf - Bau-Nr.: In Abklärung; Bauablauf Etappe: In Abklärung; Bauablauf Verbauungsort: In Abklärung; Bauablauf Start Ausführung: In Abklärung; Bauablauf Ende Ausführung: In Abklärung
01_Leistungen und Kosten - Gebäude: In Abklärung; Elementpreis - CHF: 0; BKP: 211 - Baumeisterarbeiten; eBKP-H_Nr: C04.06; eBKP-H_Beschrieb: Aussen liegende Treppe, Rampe
03_Bausystem - Feuerwiderstand: In Abklärung; Umbau-Status: Neubau; Mehrschichtiger Aufbau: Beton bewehrt
Massivbau Ortbeton - Ortbeton Druckfestigkeitsklasse: In Abklärung; Ortbeton Expositionsklasse: In Abklärung; Ortbeton Grösstkorn - mm: Dmax 32; Ortbeton Chloridgehaltsklasse: Cl 0.10; Ortbeton Konsistenzklasse: C3; Ortbeton Recyclingbeton: In Abklärung; Ortbeton Oberflächenausführung: In Abklärung; Ortbeton Oberflächenklasse - BOK: In Abklärung; Ortbeton Schalungstyp: In Abklärung; Ortbeton Dreikantleisten - mm: In Abklärung; Ortbeton Bew. Überdeckung oben - mm: In Abklärung; Ortbeton Bew. Überdeckung unten - mm: In Abklärung; Ortbeton Bew. Überdeckung aussen - mm: In Abklärung; Ortbeton Bew. Überdeckung innen - mm: In Abklärung; Ortbeton Bewehrungsgehalt - kg/m3: In Abklärung
00_Datenstruktur - BIM Base Version: 4.0.0; Kundenergänzungen Version: v01; Klassifizierung: Aussenrampe Ortbeton; Klassifizierung Level 0: Rampe; Modellierungsrichtlinien: https://evolutbaugmbh.sharepoint.com/:b:/s/External/EciBgBMJMZlDgYCafV5wNokBvCJq9PUJAyVGz7O3vsjVrg?e=aLjLN9; Übersicht BIM Base: https://evolutbaugmbh.sharepoint.com/:b:/s/External/EfS4mJ9nZQpOhASXp0n2kW4B0K7N-vHKx-_6Crp5CxEFeg?e=Qu0M5d; Verbesserungsvorschläge BIM Base: https://forms.office.com/e/pcFhFfi5DW; Anleitung Mengen: https://evolutbaugmbh.sharepoint.com/:b:/s/External/ETgyOLO3JxJEqg9rbaRMLVEBHuWIRtkoMiJN1fISDr-3lw?e=E0LTiQ; Anleitung Eigenschaften: https://evolutbaugmbh.sharepoint.com/:b:/s/External/EQedjNXQkc1Btaftc01yAPUBtND9QzXFSH3-7sie6PGFww?e=wP4uf3; Release Notes: https://evolutbaugmbh.sharepoint.com/:b:/s/External/Eb41lwlDI71MhUVvor2V2mUBSaI-0tQK5U9oJAWxpCINuw?e=NtK3j6
Name | In | CAD Werkzeug Typ | Stärke - m | Fläche brutto - m2 | Volumen netto - m3 | Kote Unterkante | Kote Oberkante
Dach-008 | Fundation | Dach | 0.299817 | 24.0432 | 7.20855 | -3.24 | -2.94
Dach-008 | Fundation | Dach | 0.299817 | 30.2152 | 9.05905 | -3.842 | -3.542
Dach-008 | Fundation | Dach | 0.299817 | 25.1654 | 7.54503 | -4.08 | -3.78
Dach-008 | Fundation | Dach | 0.299817 | 14.0296 | 4.20632 | -4.14 | -3.84
Dach-008 | Fundation | Dach | 0.299817 | 12.0054 | 3.59943 | -4.2 | -3.9
Deckennr.-068 | Fundation | Decke | 0.3 | 34.962 | 10.4886 | -4.14 | -3.84
Deckennr.-068 | UG | Decke | 0.3 | 106.5 | 31.95 | -3 | -2.7

# IfcRamp: Magerbeton 1267 x 460, Unterzug-032
In: Fundation
Classification: Aussenrampe Ortbeton (BIM Base by Evolut); Material: Magerbeton
01_Leistungen und Kosten - Gebäude: In Abklärung; Elementpreis - CHF: 0; BKP: 211 - Baumeisterarbeiten; eBKP-H_Nr: C04.06; eBKP-H_Beschrieb: Aussen liegende Treppe, Rampe
05_Bauablauf - Bau-Nr.: In Abklärung; Bauablauf Etappe: In Abklärung; Bauablauf Verbauungsort: In Abklärung; Bauablauf Start Ausführung: In Abklärung; Bauablauf Ende Ausführung: In Abklärung
03_Bausystem - Feuerwiderstand: In Abklärung; Umbau-Status: Neubau; Mehrschichtiger Aufbau: Magerbeton
Massivbau Ortbeton - Ortbeton Druckfestigkeitsklasse: In Abklärung; Ortbeton Expositionsklasse: In Abklärung; Ortbeton Grösstkorn - mm: Dmax 32; Ortbeton Chloridgehaltsklasse: Cl 0.10; Ortbeton Konsistenzklasse: C3; Ortbeton Recyclingbeton: In Abklärung; Ortbeton Oberflächenausführung: In Abklärung; Ortbeton Oberflächenklasse - BOK: In Abklärung; Ortbeton Schalungstyp: In Abklärung; Ortbeton Dreikantleisten - mm: In Abklärung; Ortbeton Bew. Überdeckung oben - mm: In Abklärung; Ortbeton Bew. Überdeckung unten - mm: In Abklärung; Ortbeton Bew. Überdeckung aussen - mm: In Abklärung; Ortbeton Bew. Überdeckung innen - mm: In Abklärung; Ortbeton Bewehrungsgehalt - kg/m3: In Abklärung
02_Mengen - Breite - m: 1.26697; Höhe - m: 0.459692; Stärke - m: 1.26697; Länge brutto - m: 2.06416; Fläche brutto - m2: 2.61523; Volumen netto - m3: 0.816998; Kote Unterkante: -4.54; Kote Oberkante: -4.08
00_Datenstruktur - BIM Base Version: 4.0.0; Kundenergänzungen Version: v01; CAD Werkzeug Typ: Träger; Klassifizierung: Aussenrampe Ortbeton; Klassifizierung Level 0: Rampe; Modellierungsrichtlinien: https://evolutbaugmbh.sharepoint.com/:b:/s/External/EciBgBMJMZlDgYCafV5wNokBvCJq9PUJAyVGz7O3vsjVrg?e=aLjLN9; Übersicht BIM Base: https://evolutbaugmbh.sharepoint.com/:b:/s/External/EfS4mJ9nZQpOhASXp0n2kW4B0K7N-vHKx-_6Crp5CxEFeg?e=Qu0M5d; Verbesserungsvorschläge BIM Base: https://forms.office.com/e/pcFhFfi5DW; Anleitung Mengen: https://evolutbaugmbh.sharepoint.com/:b:/s/External/ETgyOLO3JxJEqg9rbaRMLVEBHuWIRtkoMiJN1fISDr-3lw?e=E0LTiQ; Anleitung Eigenschaften: https://evolutbaugmbh.sharepoint.com/:b:/s/External/EQedjNXQkc1Btaftc01yAPUBtND9QzXFSH3-7sie6PGFww?e=wP4uf3; Release Notes: https://evolutbaugmbh.sharepoint.com/:b:/s/External/Eb41lwlDI71MhUVvor2V2mUBSaI-0tQK5U9oJAWxpCINuw?e=NtK3j6

# IfcRamp: Magerbeton 1350 x 400 (3)
In: Fundation
Classification: Aussenrampe Ortbeton (BIM Base by Evolut); Material: Magerbeton
01_Leistungen und Kosten - Gebäude: In Abklärung; Elementpreis - CHF: 0; BKP: 211 - Baumeisterarbeiten; eBKP-H_Nr: C04.06; eBKP-H_Beschrieb: Aussen liegende Treppe, Rampe
03_Bausystem - Feuerwiderstand: In Abklärung; Umbau-Status: Neubau; Mehrschichtiger Aufbau: Magerbeton
Massivbau Ortbeton - Ortbeton Druckfestigkeitsklasse: In Abklärung; Ortbeton Expositionsklasse: In Abklärung; Ortbeton Grösstkorn - mm: Dmax 32; Ortbeton Chloridgehaltsklasse: Cl 0.10; Ortbeton Konsistenzklasse: C3; Ortbeton Recyclingbeton: In Abklärung; Ortbeton Oberflächenausführung: In Abklärung; Ortbeton Oberflächenklasse - BOK: In Abklärung; Ortbeton Schalungstyp: In Abklärung; Ortbeton Dreikantleisten - mm: In Abklärung; Ortbeton Bew. Überdeckung oben - mm: In Abklärung; Ortbeton Bew. Überdeckung unten - mm: In Abklärung; Ortbeton Bew. Überdeckung aussen - mm: In Abklärung; Ortbeton Bew. Überdeckung innen - mm: In Abklärung; Ortbeton Bewehrungsgehalt - kg/m3: In Abklärung
02_Mengen - Breite - m: 1.35; Höhe - m: 0.400002; Stärke - m: 1.35; Kote Unterkante: -4.54; Kote Oberkante: -4.14
05_Bauablauf - Bau-Nr.: In Abklärung; Bauablauf Etappe: In Abklärung; Bauablauf Verbauungsort: In Abklärung; Bauablauf Start Ausführung: In Abklärung; Bauablauf Ende Ausführung: In Abklärung
00_Datenstruktur - BIM Base Version: 4.0.0; Kundenergänzungen Version: v01; CAD Werkzeug Typ: Träger; Klassifizierung: Aussenrampe Ortbeton; Klassifizierung Level 0: Rampe; Modellierungsrichtlinien: https://evolutbaugmbh.sharepoint.com/:b:/s/External/EciBgBMJMZlDgYCafV5wNokBvCJq9PUJAyVGz7O3vsjVrg?e=aLjLN9; Übersicht BIM Base: https://evolutbaugmbh.sharepoint.com/:b:/s/External/EfS4mJ9nZQpOhASXp0n2kW4B0K7N-vHKx-_6Crp5CxEFeg?e=Qu0M5d; Verbesserungsvorschläge BIM Base: https://forms.office.com/e/pcFhFfi5DW; Anleitung Mengen: https://evolutbaugmbh.sharepoint.com/:b:/s/External/ETgyOLO3JxJEqg9rbaRMLVEBHuWIRtkoMiJN1fISDr-3lw?e=E0LTiQ; Anleitung Eigenschaften: https://evolutbaugmbh.sharepoint.com/:b:/s/External/EQedjNXQkc1Btaftc01yAPUBtND9QzXFSH3-7sie6PGFww?e=wP4uf3; Release Notes: https://evolutbaugmbh.sharepoint.com/:b:/s/External/Eb41lwlDI71MhUVvor2V2mUBSaI-0tQK5U9oJAWxpCINuw?e=NtK3j6
Name | Länge brutto - m | Fläche brutto - m2 | Volumen netto - m3
Unterzug-032 | 3.79995 | 5.12993 | 2.05199
Unterzug-032 | 3.45824 | 4.66862 | 1.29333
Unterzug-032 | 3.8 | 5.13 | 2.05201

# IfcRamp: Magerbeton 1706 x 640, Unterzug-032
In: Fundation
Classification: Aussenrampe Ortbeton (BIM Base by Evolut); Material: Magerbeton
01_Leistungen und Kosten - Gebäude: In Abklärung; Elementpreis - CHF: 0; BKP: 211 - Baumeisterarbeiten; eBKP-H_Nr: C04.06; eBKP-H_Beschrieb: Aussen liegende Treppe, Rampe
03_Bausystem - Feuerwiderstand: In Abklärung; Umbau-Status: Neubau; Mehrschichtiger Aufbau: Magerbeton
05_Bauablauf - Bau-Nr.: In Abklärung; Bauablauf Etappe: In Abklärung; Bauablauf Verbauungsort: In Abklärung; Bauablauf Start Ausführung: In Abklärung; Bauablauf Ende Ausführung: In Abklärung
Massivbau Ortbeton - Ortbeton Druckfestigkeitsklasse: In Abklärung; Ortbeton Expositionsklasse: In Abklärung; Ortbeton Grösstkorn - mm: Dmax 32; Ortbeton Chloridgehaltsklasse: Cl 0.10; Ortbeton Konsistenzklasse: C3; Ortbeton Recyclingbeton: In Abklärung; Ortbeton Oberflächenausführung: In Abklärung; Ortbeton Oberflächenklasse - BOK: In Abklärung; Ortbeton Schalungstyp: In Abklärung; Ortbeton Dreikantleisten - mm: In Abklärung; Ortbeton Bew. Überdeckung oben - mm: In Abklärung; Ortbeton Bew. Überdeckung unten - mm: In Abklärung; Ortbeton Bew. Überdeckung aussen - mm: In Abklärung; Ortbeton Bew. Überdeckung innen - mm: In Abklärung; Ortbeton Bewehrungsgehalt - kg/m3: In Abklärung
00_Datenstruktur - BIM Base Version: 4.0.0; Kundenergänzungen Version: v01; CAD Werkzeug Typ: Träger; Klassifizierung: Aussenrampe Ortbeton; Klassifizierung Level 0: Rampe; Modellierungsrichtlinien: https://evolutbaugmbh.sharepoint.com/:b:/s/External/EciBgBMJMZlDgYCafV5wNokBvCJq9PUJAyVGz7O3vsjVrg?e=aLjLN9; Übersicht BIM Base: https://evolutbaugmbh.sharepoint.com/:b:/s/External/EfS4mJ9nZQpOhASXp0n2kW4B0K7N-vHKx-_6Crp5CxEFeg?e=Qu0M5d; Verbesserungsvorschläge BIM Base: https://forms.office.com/e/pcFhFfi5DW; Anleitung Mengen: https://evolutbaugmbh.sharepoint.com/:b:/s/External/ETgyOLO3JxJEqg9rbaRMLVEBHuWIRtkoMiJN1fISDr-3lw?e=E0LTiQ; Anleitung Eigenschaften: https://evolutbaugmbh.sharepoint.com/:b:/s/External/EQedjNXQkc1Btaftc01yAPUBtND9QzXFSH3-7sie6PGFww?e=wP4uf3; Release Notes: https://evolutbaugmbh.sharepoint.com/:b:/s/External/Eb41lwlDI71MhUVvor2V2mUBSaI-0tQK5U9oJAWxpCINuw?e=NtK3j6
02_Mengen - Breite - m: 1.70633; Höhe - m: 0.64; Stärke - m: 1.70633; Länge brutto - m: 3.09496; Fläche brutto - m2: 5.28104; Volumen netto - m3: 2.14855; Kote Unterkante: -4.54; Kote Oberkante: -3.9

# IfcRamp: Magerbeton 350 x 525 (2)
In: Fundation
Classification: Aussenrampe Ortbeton (BIM Base by Evolut); Material: Magerbeton
01_Leistungen und Kosten - Gebäude: In Abklärung; Elementpreis - CHF: 0; BKP: 211 - Baumeisterarbeiten; eBKP-H_Nr: C04.06; eBKP-H_Beschrieb: Aussen liegende Treppe, Rampe
Massivbau Ortbeton - Ortbeton Druckfestigkeitsklasse: In Abklärung; Ortbeton Expositionsklasse: In Abklärung; Ortbeton Grösstkorn - mm: Dmax 32; Ortbeton Chloridgehaltsklasse: Cl 0.10; Ortbeton Konsistenzklasse: C3; Ortbeton Recyclingbeton: In Abklärung; Ortbeton Oberflächenausführung: In Abklärung; Ortbeton Oberflächenklasse - BOK: In Abklärung; Ortbeton Schalungstyp: In Abklärung; Ortbeton Dreikantleisten - mm: In Abklärung; Ortbeton Bew. Überdeckung oben - mm: In Abklärung; Ortbeton Bew. Überdeckung unten - mm: In Abklärung; Ortbeton Bew. Überdeckung aussen - mm: In Abklärung; Ortbeton Bew. Überdeckung innen - mm: In Abklärung; Ortbeton Bewehrungsgehalt - kg/m3: In Abklärung
00_Datenstruktur - BIM Base Version: 4.0.0; Kundenergänzungen Version: v01; CAD Werkzeug Typ: Träger; Klassifizierung: Aussenrampe Ortbeton; Klassifizierung Level 0: Rampe; Modellierungsrichtlinien: https://evolutbaugmbh.sharepoint.com/:b:/s/External/EciBgBMJMZlDgYCafV5wNokBvCJq9PUJAyVGz7O3vsjVrg?e=aLjLN9; Übersicht BIM Base: https://evolutbaugmbh.sharepoint.com/:b:/s/External/EfS4mJ9nZQpOhASXp0n2kW4B0K7N-vHKx-_6Crp5CxEFeg?e=Qu0M5d; Verbesserungsvorschläge BIM Base: https://forms.office.com/e/pcFhFfi5DW; Anleitung Mengen: https://evolutbaugmbh.sharepoint.com/:b:/s/External/ETgyOLO3JxJEqg9rbaRMLVEBHuWIRtkoMiJN1fISDr-3lw?e=E0LTiQ; Anleitung Eigenschaften: https://evolutbaugmbh.sharepoint.com/:b:/s/External/EQedjNXQkc1Btaftc01yAPUBtND9QzXFSH3-7sie6PGFww?e=wP4uf3; Release Notes: https://evolutbaugmbh.sharepoint.com/:b:/s/External/Eb41lwlDI71MhUVvor2V2mUBSaI-0tQK5U9oJAWxpCINuw?e=NtK3j6
02_Mengen - Breite - m: 0.35; Höhe - m: 0.524625; Stärke - m: 0.35; Länge brutto - m: 1; Fläche brutto - m2: 0.524625; Volumen netto - m3: 0.162619; Kote Unterkante: -3.765; Kote Oberkante: -3.24
05_Bauablauf - Bau-Nr.: In Abklärung; Bauablauf Etappe: In Abklärung; Bauablauf Verbauungsort: In Abklärung; Bauablauf Start Ausführung: In Abklärung; Bauablauf Ende Ausführung: In Abklärung
03_Bausystem - Feuerwiderstand: In Abklärung; Umbau-Status: Neubau; Mehrschichtiger Aufbau: Magerbeton

# IfcRamp: Magerbeton 350 x 765 (4)
In: Fundation
Classification: Aussenrampe Ortbeton (BIM Base by Evolut); Material: Magerbeton
01_Leistungen und Kosten - Gebäude: In Abklärung; Elementpreis - CHF: 0; BKP: 211 - Baumeisterarbeiten; eBKP-H_Nr: C04.06; eBKP-H_Beschrieb: Aussen liegende Treppe, Rampe
05_Bauablauf - Bau-Nr.: In Abklärung; Bauablauf Etappe: In Abklärung; Bauablauf Verbauungsort: In Abklärung; Bauablauf Start Ausführung: In Abklärung; Bauablauf Ende Ausführung: In Abklärung
03_Bausystem - Feuerwiderstand: In Abklärung; Umbau-Status: Neubau; Mehrschichtiger Aufbau: Magerbeton
Massivbau Ortbeton - Ortbeton Druckfestigkeitsklasse: In Abklärung; Ortbeton Expositionsklasse: In Abklärung; Ortbeton Grösstkorn - mm: Dmax 32; Ortbeton Chloridgehaltsklasse: Cl 0.10; Ortbeton Konsistenzklasse: C3; Ortbeton Recyclingbeton: In Abklärung; Ortbeton Oberflächenausführung: In Abklärung; Ortbeton Oberflächenklasse - BOK: In Abklärung; Ortbeton Schalungstyp: In Abklärung; Ortbeton Dreikantleisten - mm: In Abklärung; Ortbeton Bew. Überdeckung oben - mm: In Abklärung; Ortbeton Bew. Überdeckung unten - mm: In Abklärung; Ortbeton Bew. Überdeckung aussen - mm: In Abklärung; Ortbeton Bew. Überdeckung innen - mm: In Abklärung; Ortbeton Bewehrungsgehalt - kg/m3: In Abklärung
02_Mengen - Breite - m: 0.35; Höhe - m: 0.764691; Stärke - m: 0.35; Kote Unterkante: -3.765; Kote Oberkante: -3
00_Datenstruktur - BIM Base Version: 4.0.0; Kundenergänzungen Version: v01; CAD Werkzeug Typ: Träger; Klassifizierung: Aussenrampe Ortbeton; Klassifizierung Level 0: Rampe; Modellierungsrichtlinien: https://evolutbaugmbh.sharepoint.com/:b:/s/External/EciBgBMJMZlDgYCafV5wNokBvCJq9PUJAyVGz7O3vsjVrg?e=aLjLN9; Übersicht BIM Base: https://evolutbaugmbh.sharepoint.com/:b:/s/External/EfS4mJ9nZQpOhASXp0n2kW4B0K7N-vHKx-_6Crp5CxEFeg?e=Qu0M5d; Verbesserungsvorschläge BIM Base: https://forms.office.com/e/pcFhFfi5DW; Anleitung Mengen: https://evolutbaugmbh.sharepoint.com/:b:/s/External/ETgyOLO3JxJEqg9rbaRMLVEBHuWIRtkoMiJN1fISDr-3lw?e=E0LTiQ; Anleitung Eigenschaften: https://evolutbaugmbh.sharepoint.com/:b:/s/External/EQedjNXQkc1Btaftc01yAPUBtND9QzXFSH3-7sie6PGFww?e=wP4uf3; Release Notes: https://evolutbaugmbh.sharepoint.com/:b:/s/External/Eb41lwlDI71MhUVvor2V2mUBSaI-0tQK5U9oJAWxpCINuw?e=NtK3j6
Name | Länge brutto - m | Fläche brutto - m2 | Volumen netto - m3
2 x Unterzug-032 | 4 | 3.05876 | 0.902521
2 x Unterzug-032 | 17.75 | 13.5733 | 4.75064

# IfcRamp: Magerbeton 500 x 460, Unterzug-032
In: Fundation
Classification: Aussenrampe Ortbeton (BIM Base by Evolut); Material: Magerbeton
01_Leistungen und Kosten - Gebäude: In Abklärung; Elementpreis - CHF: 0; BKP: 211 - Baumeisterarbeiten; eBKP-H_Nr: C04.06; eBKP-H_Beschrieb: Aussen liegende Treppe, Rampe
03_Bausystem - Feuerwiderstand: In Abklärung; Umbau-Status: Neubau; Mehrschichtiger Aufbau: Magerbeton
Massivbau Ortbeton - Ortbeton Druckfestigkeitsklasse: In Abklärung; Ortbeton Expositionsklasse: In Abklärung; Ortbeton Grösstkorn - mm: Dmax 32; Ortbeton Chloridgehaltsklasse: Cl 0.10; Ortbeton Konsistenzklasse: C3; Ortbeton Recyclingbeton: In Abklärung; Ortbeton Oberflächenausführung: In Abklärung; Ortbeton Oberflächenklasse - BOK: In Abklärung; Ortbeton Schalungstyp: In Abklärung; Ortbeton Dreikantleisten - mm: In Abklärung; Ortbeton Bew. Überdeckung oben - mm: In Abklärung; Ortbeton Bew. Überdeckung unten - mm: In Abklärung; Ortbeton Bew. Überdeckung aussen - mm: In Abklärung; Ortbeton Bew. Überdeckung innen - mm: In Abklärung; Ortbeton Bewehrungsgehalt - kg/m3: In Abklärung
02_Mengen - Breite - m: 0.5; Höhe - m: 0.459691; Stärke - m: 0.5; Länge brutto - m: 2; Fläche brutto - m2: 1; Volumen netto - m3: 0.429847; Kote Unterkante: -4.54; Kote Oberkante: -4.08
00_Datenstruktur - BIM Base Version: 4.0.0; Kundenergänzungen Version: v01; CAD Werkzeug Typ: Träger; Klassifizierung: Aussenrampe Ortbeton; Klassifizierung Level 0: Rampe; Modellierungsrichtlinien: https://evolutbaugmbh.sharepoint.com/:b:/s/External/EciBgBMJMZlDgYCafV5wNokBvCJq9PUJAyVGz7O3vsjVrg?e=aLjLN9; Übersicht BIM Base: https://evolutbaugmbh.sharepoint.com/:b:/s/External/EfS4mJ9nZQpOhASXp0n2kW4B0K7N-vHKx-_6Crp5CxEFeg?e=Qu0M5d; Verbesserungsvorschläge BIM Base: https://forms.office.com/e/pcFhFfi5DW; Anleitung Mengen: https://evolutbaugmbh.sharepoint.com/:b:/s/External/ETgyOLO3JxJEqg9rbaRMLVEBHuWIRtkoMiJN1fISDr-3lw?e=E0LTiQ; Anleitung Eigenschaften: https://evolutbaugmbh.sharepoint.com/:b:/s/External/EQedjNXQkc1Btaftc01yAPUBtND9QzXFSH3-7sie6PGFww?e=wP4uf3; Release Notes: https://evolutbaugmbh.sharepoint.com/:b:/s/External/Eb41lwlDI71MhUVvor2V2mUBSaI-0tQK5U9oJAWxpCINuw?e=NtK3j6
05_Bauablauf - Bau-Nr.: In Abklärung; Bauablauf Etappe: In Abklärung; Bauablauf Verbauungsort: In Abklärung; Bauablauf Start Ausführung: In Abklärung; Bauablauf Ende Ausführung: In Abklärung

# IfcRamp: Magerbeton 500 x 640, Unterzug-032
In: Fundation
Classification: Aussenrampe Ortbeton (BIM Base by Evolut); Material: Magerbeton
01_Leistungen und Kosten - Gebäude: In Abklärung; Elementpreis - CHF: 0; BKP: 211 - Baumeisterarbeiten; eBKP-H_Nr: C04.06; eBKP-H_Beschrieb: Aussen liegende Treppe, Rampe
03_Bausystem - Feuerwiderstand: In Abklärung; Umbau-Status: Neubau; Mehrschichtiger Aufbau: Magerbeton
05_Bauablauf - Bau-Nr.: In Abklärung; Bauablauf Etappe: In Abklärung; Bauablauf Verbauungsort: In Abklärung; Bauablauf Start Ausführung: In Abklärung; Bauablauf Ende Ausführung: In Abklärung
Massivbau Ortbeton - Ortbeton Druckfestigkeitsklasse: In Abklärung; Ortbeton Expositionsklasse: In Abklärung; Ortbeton Grösstkorn - mm: Dmax 32; Ortbeton Chloridgehaltsklasse: Cl 0.10; Ortbeton Konsistenzklasse: C3; Ortbeton Recyclingbeton: In Abklärung; Ortbeton Oberflächenausführung: In Abklärung; Ortbeton Oberflächenklasse - BOK: In Abklärung; Ortbeton Schalungstyp: In Abklärung; Ortbeton Dreikantleisten - mm: In Abklärung; Ortbeton Bew. Überdeckung oben - mm: In Abklärung; Ortbeton Bew. Überdeckung unten - mm: In Abklärung; Ortbeton Bew. Überdeckung aussen - mm: In Abklärung; Ortbeton Bew. Überdeckung innen - mm: In Abklärung; Ortbeton Bewehrungsgehalt - kg/m3: In Abklärung
02_Mengen - Breite - m: 0.5; Höhe - m: 0.64; Stärke - m: 0.5; Länge brutto - m: 3; Fläche brutto - m2: 1.92; Volumen netto - m3: 0.824769; Kote Unterkante: -4.54; Kote Oberkante: -3.9
00_Datenstruktur - BIM Base Version: 4.0.0; Kundenergänzungen Version: v01; CAD Werkzeug Typ: Träger; Klassifizierung: Aussenrampe Ortbeton; Klassifizierung Level 0: Rampe; Modellierungsrichtlinien: https://evolutbaugmbh.sharepoint.com/:b:/s/External/EciBgBMJMZlDgYCafV5wNokBvCJq9PUJAyVGz7O3vsjVrg?e=aLjLN9; Übersicht BIM Base: https://evolutbaugmbh.sharepoint.com/:b:/s/External/EfS4mJ9nZQpOhASXp0n2kW4B0K7N-vHKx-_6Crp5CxEFeg?e=Qu0M5d; Verbesserungsvorschläge BIM Base: https://forms.office.com/e/pcFhFfi5DW; Anleitung Mengen: https://evolutbaugmbh.sharepoint.com/:b:/s/External/ETgyOLO3JxJEqg9rbaRMLVEBHuWIRtkoMiJN1fISDr-3lw?e=E0LTiQ; Anleitung Eigenschaften: https://evolutbaugmbh.sharepoint.com/:b:/s/External/EQedjNXQkc1Btaftc01yAPUBtND9QzXFSH3-7sie6PGFww?e=wP4uf3; Release Notes: https://evolutbaugmbh.sharepoint.com/:b:/s/External/Eb41lwlDI71MhUVvor2V2mUBSaI-0tQK5U9oJAWxpCINuw?e=NtK3j6

# IfcRamp: Magerbeton 600 x 458 (2)
In: Fundation
Classification: Aussenrampe Ortbeton (BIM Base by Evolut); Material: Magerbeton
01_Leistungen und Kosten - Gebäude: In Abklärung; Elementpreis - CHF: 0; BKP: 211 - Baumeisterarbeiten; eBKP-H_Nr: C04.06; eBKP-H_Beschrieb: Aussen liegende Treppe, Rampe
05_Bauablauf - Bau-Nr.: In Abklärung; Bauablauf Etappe: In Abklärung; Bauablauf Verbauungsort: In Abklärung; Bauablauf Start Ausführung: In Abklärung; Bauablauf Ende Ausführung: In Abklärung
Massivbau Ortbeton - Ortbeton Druckfestigkeitsklasse: In Abklärung; Ortbeton Expositionsklasse: In Abklärung; Ortbeton Grösstkorn - mm: Dmax 32; Ortbeton Chloridgehaltsklasse: Cl 0.10; Ortbeton Konsistenzklasse: C3; Ortbeton Recyclingbeton: In Abklärung; Ortbeton Oberflächenausführung: In Abklärung; Ortbeton Oberflächenklasse - BOK: In Abklärung; Ortbeton Schalungstyp: In Abklärung; Ortbeton Dreikantleisten - mm: In Abklärung; Ortbeton Bew. Überdeckung oben - mm: In Abklärung; Ortbeton Bew. Überdeckung unten - mm: In Abklärung; Ortbeton Bew. Überdeckung aussen - mm: In Abklärung; Ortbeton Bew. Überdeckung innen - mm: In Abklärung; Ortbeton Bewehrungsgehalt - kg/m3: In Abklärung
03_Bausystem - Feuerwiderstand: In Abklärung; Umbau-Status: Neubau; Mehrschichtiger Aufbau: Magerbeton
02_Mengen - Breite - m: 0.6; Höhe - m: 0.45839; Stärke - m: 0.6; Länge brutto - m: 1; Fläche brutto - m2: 0.6; Volumen netto - m3: 0.25761; Kote Unterkante: -4.3; Kote Oberkante: -3.842
00_Datenstruktur - BIM Base Version: 4.0.0; Kundenergänzungen Version: v01; CAD Werkzeug Typ: Träger; Klassifizierung: Aussenrampe Ortbeton; Klassifizierung Level 0: Rampe; Modellierungsrichtlinien: https://evolutbaugmbh.sharepoint.com/:b:/s/External/EciBgBMJMZlDgYCafV5wNokBvCJq9PUJAyVGz7O3vsjVrg?e=aLjLN9; Übersicht BIM Base: https://evolutbaugmbh.sharepoint.com/:b:/s/External/EfS4mJ9nZQpOhASXp0n2kW4B0K7N-vHKx-_6Crp5CxEFeg?e=Qu0M5d; Verbesserungsvorschläge BIM Base: https://forms.office.com/e/pcFhFfi5DW; Anleitung Mengen: https://evolutbaugmbh.sharepoint.com/:b:/s/External/ETgyOLO3JxJEqg9rbaRMLVEBHuWIRtkoMiJN1fISDr-3lw?e=E0LTiQ; Anleitung Eigenschaften: https://evolutbaugmbh.sharepoint.com/:b:/s/External/EQedjNXQkc1Btaftc01yAPUBtND9QzXFSH3-7sie6PGFww?e=wP4uf3; Release Notes: https://evolutbaugmbh.sharepoint.com/:b:/s/External/Eb41lwlDI71MhUVvor2V2mUBSaI-0tQK5U9oJAWxpCINuw?e=NtK3j6

# IfcRamp: Magerbeton 600 x 940 (2)
In: Fundation
Classification: Aussenrampe Ortbeton (BIM Base by Evolut); Material: Magerbeton
01_Leistungen und Kosten - Gebäude: In Abklärung; Elementpreis - CHF: 0; BKP: 211 - Baumeisterarbeiten; eBKP-H_Nr: C04.06; eBKP-H_Beschrieb: Aussen liegende Treppe, Rampe
Massivbau Ortbeton - Ortbeton Druckfestigkeitsklasse: In Abklärung; Ortbeton Expositionsklasse: In Abklärung; Ortbeton Grösstkorn - mm: Dmax 32; Ortbeton Chloridgehaltsklasse: Cl 0.10; Ortbeton Konsistenzklasse: C3; Ortbeton Recyclingbeton: In Abklärung; Ortbeton Oberflächenausführung: In Abklärung; Ortbeton Oberflächenklasse - BOK: In Abklärung; Ortbeton Schalungstyp: In Abklärung; Ortbeton Dreikantleisten - mm: In Abklärung; Ortbeton Bew. Überdeckung oben - mm: In Abklärung; Ortbeton Bew. Überdeckung unten - mm: In Abklärung; Ortbeton Bew. Überdeckung aussen - mm: In Abklärung; Ortbeton Bew. Überdeckung innen - mm: In Abklärung; Ortbeton Bewehrungsgehalt - kg/m3: In Abklärung
03_Bausystem - Feuerwiderstand: In Abklärung; Umbau-Status: Neubau; Mehrschichtiger Aufbau: Magerbeton
05_Bauablauf - Bau-Nr.: In Abklärung; Bauablauf Etappe: In Abklärung; Bauablauf Verbauungsort: In Abklärung; Bauablauf Start Ausführung: In Abklärung; Bauablauf Ende Ausführung: In Abklärung
02_Mengen - Breite - m: 0.6; Höhe - m: 0.94; Stärke - m: 0.6; Länge brutto - m: 4; Fläche brutto - m2: 3.76; Volumen netto - m3: 1.67807; Kote Unterkante: -4.3; Kote Oberkante: -3.36
00_Datenstruktur - BIM Base Version: 4.0.0; Kundenergänzungen Version: v01; CAD Werkzeug Typ: Träger; Klassifizierung: Aussenrampe Ortbeton; Klassifizierung Level 0: Rampe; Modellierungsrichtlinien: https://evolutbaugmbh.sharepoint.com/:b:/s/External/EciBgBMJMZlDgYCafV5wNokBvCJq9PUJAyVGz7O3vsjVrg?e=aLjLN9; Übersicht BIM Base: https://evolutbaugmbh.sharepoint.com/:b:/s/External/EfS4mJ9nZQpOhASXp0n2kW4B0K7N-vHKx-_6Crp5CxEFeg?e=Qu0M5d; Verbesserungsvorschläge BIM Base: https://forms.office.com/e/pcFhFfi5DW; Anleitung Mengen: https://evolutbaugmbh.sharepoint.com/:b:/s/External/ETgyOLO3JxJEqg9rbaRMLVEBHuWIRtkoMiJN1fISDr-3lw?e=E0LTiQ; Anleitung Eigenschaften: https://evolutbaugmbh.sharepoint.com/:b:/s/External/EQedjNXQkc1Btaftc01yAPUBtND9QzXFSH3-7sie6PGFww?e=wP4uf3; Release Notes: https://evolutbaugmbh.sharepoint.com/:b:/s/External/Eb41lwlDI71MhUVvor2V2mUBSaI-0tQK5U9oJAWxpCINuw?e=NtK3j6

# IfcRamp: Magerbeton 850 x 460, Unterzug-032
In: Fundation
Classification: Aussenrampe Ortbeton (BIM Base by Evolut); Material: Magerbeton
01_Leistungen und Kosten - Gebäude: In Abklärung; Elementpreis - CHF: 0; BKP: 211 - Baumeisterarbeiten; eBKP-H_Nr: C04.06; eBKP-H_Beschrieb: Aussen liegende Treppe, Rampe
05_Bauablauf - Bau-Nr.: In Abklärung; Bauablauf Etappe: In Abklärung; Bauablauf Verbauungsort: In Abklärung; Bauablauf Start Ausführung: In Abklärung; Bauablauf Ende Ausführung: In Abklärung
03_Bausystem - Feuerwiderstand: In Abklärung; Umbau-Status: Neubau; Mehrschichtiger Aufbau: Magerbeton
Massivbau Ortbeton - Ortbeton Druckfestigkeitsklasse: In Abklärung; Ortbeton Expositionsklasse: In Abklärung; Ortbeton Grösstkorn - mm: Dmax 32; Ortbeton Chloridgehaltsklasse: Cl 0.10; Ortbeton Konsistenzklasse: C3; Ortbeton Recyclingbeton: In Abklärung; Ortbeton Oberflächenausführung: In Abklärung; Ortbeton Oberflächenklasse - BOK: In Abklärung; Ortbeton Schalungstyp: In Abklärung; Ortbeton Dreikantleisten - mm: In Abklärung; Ortbeton Bew. Überdeckung oben - mm: In Abklärung; Ortbeton Bew. Überdeckung unten - mm: In Abklärung; Ortbeton Bew. Überdeckung aussen - mm: In Abklärung; Ortbeton Bew. Überdeckung innen - mm: In Abklärung; Ortbeton Bewehrungsgehalt - kg/m3: In Abklärung
02_Mengen - Breite - m: 0.85; Höhe - m: 0.459691; Stärke - m: 0.85; Länge brutto - m: 2; Fläche brutto - m2: 1.7; Volumen netto - m3: 0.73074; Kote Unterkante: -4.54; Kote Oberkante: -4.08
00_Datenstruktur - BIM Base Version: 4.0.0; Kundenergänzungen Version: v01; CAD Werkzeug Typ: Träger; Klassifizierung: Aussenrampe Ortbeton; Klassifizierung Level 0: Rampe; Modellierungsrichtlinien: https://evolutbaugmbh.sharepoint.com/:b:/s/External/EciBgBMJMZlDgYCafV5wNokBvCJq9PUJAyVGz7O3vsjVrg?e=aLjLN9; Übersicht BIM Base: https://evolutbaugmbh.sharepoint.com/:b:/s/External/EfS4mJ9nZQpOhASXp0n2kW4B0K7N-vHKx-_6Crp5CxEFeg?e=Qu0M5d; Verbesserungsvorschläge BIM Base: https://forms.office.com/e/pcFhFfi5DW; Anleitung Mengen: https://evolutbaugmbh.sharepoint.com/:b:/s/External/ETgyOLO3JxJEqg9rbaRMLVEBHuWIRtkoMiJN1fISDr-3lw?e=E0LTiQ; Anleitung Eigenschaften: https://evolutbaugmbh.sharepoint.com/:b:/s/External/EQedjNXQkc1Btaftc01yAPUBtND9QzXFSH3-7sie6PGFww?e=wP4uf3; Release Notes: https://evolutbaugmbh.sharepoint.com/:b:/s/External/Eb41lwlDI71MhUVvor2V2mUBSaI-0tQK5U9oJAWxpCINuw?e=NtK3j6

# IfcRamp: Magerbeton 850 x 640, Unterzug-032
In: Fundation
Classification: Aussenrampe Ortbeton (BIM Base by Evolut); Material: Magerbeton
01_Leistungen und Kosten - Gebäude: In Abklärung; Elementpreis - CHF: 0; BKP: 211 - Baumeisterarbeiten; eBKP-H_Nr: C04.06; eBKP-H_Beschrieb: Aussen liegende Treppe, Rampe
05_Bauablauf - Bau-Nr.: In Abklärung; Bauablauf Etappe: In Abklärung; Bauablauf Verbauungsort: In Abklärung; Bauablauf Start Ausführung: In Abklärung; Bauablauf Ende Ausführung: In Abklärung
03_Bausystem - Feuerwiderstand: In Abklärung; Umbau-Status: Neubau; Mehrschichtiger Aufbau: Magerbeton
Massivbau Ortbeton - Ortbeton Druckfestigkeitsklasse: In Abklärung; Ortbeton Expositionsklasse: In Abklärung; Ortbeton Grösstkorn - mm: Dmax 32; Ortbeton Chloridgehaltsklasse: Cl 0.10; Ortbeton Konsistenzklasse: C3; Ortbeton Recyclingbeton: In Abklärung; Ortbeton Oberflächenausführung: In Abklärung; Ortbeton Oberflächenklasse - BOK: In Abklärung; Ortbeton Schalungstyp: In Abklärung; Ortbeton Dreikantleisten - mm: In Abklärung; Ortbeton Bew. Überdeckung oben - mm: In Abklärung; Ortbeton Bew. Überdeckung unten - mm: In Abklärung; Ortbeton Bew. Überdeckung aussen - mm: In Abklärung; Ortbeton Bew. Überdeckung innen - mm: In Abklärung; Ortbeton Bewehrungsgehalt - kg/m3: In Abklärung
02_Mengen - Breite - m: 0.85; Höhe - m: 0.64; Stärke - m: 0.85; Länge brutto - m: 3; Fläche brutto - m2: 2.55; Volumen netto - m3: 1.40211; Kote Unterkante: -4.54; Kote Oberkante: -3.9
00_Datenstruktur - BIM Base Version: 4.0.0; Kundenergänzungen Version: v01; CAD Werkzeug Typ: Träger; Klassifizierung: Aussenrampe Ortbeton; Klassifizierung Level 0: Rampe; Modellierungsrichtlinien: https://evolutbaugmbh.sharepoint.com/:b:/s/External/EciBgBMJMZlDgYCafV5wNokBvCJq9PUJAyVGz7O3vsjVrg?e=aLjLN9; Übersicht BIM Base: https://evolutbaugmbh.sharepoint.com/:b:/s/External/EfS4mJ9nZQpOhASXp0n2kW4B0K7N-vHKx-_6Crp5CxEFeg?e=Qu0M5d; Verbesserungsvorschläge BIM Base: https://forms.office.com/e/pcFhFfi5DW; Anleitung Mengen: https://evolutbaugmbh.sharepoint.com/:b:/s/External/ETgyOLO3JxJEqg9rbaRMLVEBHuWIRtkoMiJN1fISDr-3lw?e=E0LTiQ; Anleitung Eigenschaften: https://evolutbaugmbh.sharepoint.com/:b:/s/External/EQedjNXQkc1Btaftc01yAPUBtND9QzXFSH3-7sie6PGFww?e=wP4uf3; Release Notes: https://evolutbaugmbh.sharepoint.com/:b:/s/External/Eb41lwlDI71MhUVvor2V2mUBSaI-0tQK5U9oJAWxpCINuw?e=NtK3j6

# IfcRamp: Magerbeton 950 x 460, Unterzug-032
In: Fundation
Classification: Aussenrampe Ortbeton (BIM Base by Evolut); Material: Magerbeton
01_Leistungen und Kosten - Gebäude: In Abklärung; Elementpreis - CHF: 0; BKP: 211 - Baumeisterarbeiten; eBKP-H_Nr: C04.06; eBKP-H_Beschrieb: Aussen liegende Treppe, Rampe
05_Bauablauf - Bau-Nr.: In Abklärung; Bauablauf Etappe: In Abklärung; Bauablauf Verbauungsort: In Abklärung; Bauablauf Start Ausführung: In Abklärung; Bauablauf Ende Ausführung: In Abklärung
Massivbau Ortbeton - Ortbeton Druckfestigkeitsklasse: In Abklärung; Ortbeton Expositionsklasse: In Abklärung; Ortbeton Grösstkorn - mm: Dmax 32; Ortbeton Chloridgehaltsklasse: Cl 0.10; Ortbeton Konsistenzklasse: C3; Ortbeton Recyclingbeton: In Abklärung; Ortbeton Oberflächenausführung: In Abklärung; Ortbeton Oberflächenklasse - BOK: In Abklärung; Ortbeton Schalungstyp: In Abklärung; Ortbeton Dreikantleisten - mm: In Abklärung; Ortbeton Bew. Überdeckung oben - mm: In Abklärung; Ortbeton Bew. Überdeckung unten - mm: In Abklärung; Ortbeton Bew. Überdeckung aussen - mm: In Abklärung; Ortbeton Bew. Überdeckung innen - mm: In Abklärung; Ortbeton Bewehrungsgehalt - kg/m3: In Abklärung
03_Bausystem - Feuerwiderstand: In Abklärung; Umbau-Status: Neubau; Mehrschichtiger Aufbau: Magerbeton
02_Mengen - Breite - m: 0.95; Höhe - m: 0.459691; Stärke - m: 0.95; Länge brutto - m: 2.85; Fläche brutto - m2: 2.7075; Volumen netto - m3: 1.16578; Kote Unterkante: -4.54; Kote Oberkante: -4.08
00_Datenstruktur - BIM Base Version: 4.0.0; Kundenergänzungen Version: v01; CAD Werkzeug Typ: Träger; Klassifizierung: Aussenrampe Ortbeton; Klassifizierung Level 0: Rampe; Modellierungsrichtlinien: https://evolutbaugmbh.sharepoint.com/:b:/s/External/EciBgBMJMZlDgYCafV5wNokBvCJq9PUJAyVGz7O3vsjVrg?e=aLjLN9; Übersicht BIM Base: https://evolutbaugmbh.sharepoint.com/:b:/s/External/EfS4mJ9nZQpOhASXp0n2kW4B0K7N-vHKx-_6Crp5CxEFeg?e=Qu0M5d; Verbesserungsvorschläge BIM Base: https://forms.office.com/e/pcFhFfi5DW; Anleitung Mengen: https://evolutbaugmbh.sharepoint.com/:b:/s/External/ETgyOLO3JxJEqg9rbaRMLVEBHuWIRtkoMiJN1fISDr-3lw?e=E0LTiQ; Anleitung Eigenschaften: https://evolutbaugmbh.sharepoint.com/:b:/s/External/EQedjNXQkc1Btaftc01yAPUBtND9QzXFSH3-7sie6PGFww?e=wP4uf3; Release Notes: https://evolutbaugmbh.sharepoint.com/:b:/s/External/Eb41lwlDI71MhUVvor2V2mUBSaI-0tQK5U9oJAWxpCINuw?e=NtK3j6

# IfcRoof: Dachrand Typ 01 - Beton 250 (4)
In: Dachaufsicht
Classification: Dachrand Beton (BIM Base by Evolut); Material: Beton bewehrt
01_Leistungen und Kosten - Gebäude: In Abklärung; Elementpreis - CHF: 0; BKP: 211 - Baumeisterarbeiten; eBKP-H_Nr: C04.04; eBKP-H_Beschrieb: Konstruktion Flachdach
05_Bauablauf - Bau-Nr.: In Abklärung; Bauablauf Etappe: In Abklärung; Bauablauf Verbauungsort: In Abklärung; Bauablauf Start Ausführung: In Abklärung; Bauablauf Ende Ausführung: In Abklärung
03_Bausystem - Tragende Funktion: In Abklärung; Feuerwiderstand: In Abklärung; Umbau-Status: Neubau; Mehrschichtiger Aufbau: Beton bewehrt
Bekleidung - Bekleidung Malerarbeiten: In Abklärung
02_Mengen - Höhe - m: 0.931; Kote Unterkante: 11.6; Kote Oberkante: 12.531
00_Datenstruktur - BIM Base Version: 4.0.0; Kundenergänzungen Version: v01; CAD Werkzeug Typ: Wand; Klassifizierung: Dachrand Beton; Klassifizierung Level 0: Dach; Modellierungsrichtlinien: https://evolutbaugmbh.sharepoint.com/:b:/s/External/EciBgBMJMZlDgYCafV5wNokBvCJq9PUJAyVGz7O3vsjVrg?e=aLjLN9; Übersicht BIM Base: https://evolutbaugmbh.sharepoint.com/:b:/s/External/EfS4mJ9nZQpOhASXp0n2kW4B0K7N-vHKx-_6Crp5CxEFeg?e=Qu0M5d; Verbesserungsvorschläge BIM Base: https://forms.office.com/e/pcFhFfi5DW; Anleitung Mengen: https://evolutbaugmbh.sharepoint.com/:b:/s/External/ETgyOLO3JxJEqg9rbaRMLVEBHuWIRtkoMiJN1fISDr-3lw?e=E0LTiQ; Anleitung Eigenschaften: https://evolutbaugmbh.sharepoint.com/:b:/s/External/EQedjNXQkc1Btaftc01yAPUBtND9QzXFSH3-7sie6PGFww?e=wP4uf3; Release Notes: https://evolutbaugmbh.sharepoint.com/:b:/s/External/Eb41lwlDI71MhUVvor2V2mUBSaI-0tQK5U9oJAWxpCINuw?e=NtK3j6
Name | Länge brutto - m | Fläche brutto - m2 | Volumen netto - m3
Wand-014 | 11.58 | 10.781 | 2.63706
Wand-014 | 21.781 | 20.2781 | 5.01134
Wand-014 | 1.71 | 1.59201 | 0.339749
Wand-014 | 19.21 | 17.8845 | 4.47113

# IfcRoof: Flachdach Typ 01 - Beton ungedämmt 250 (3)
In: Attika
Classification: Flachdach Ortbeton (BIM Base by Evolut); Material: Beton bewehrt
01_Leistungen und Kosten - Gebäude: In Abklärung; Elementpreis - CHF: 0; BKP: 211 - Baumeisterarbeiten; eBKP-H_Nr: C04.04; eBKP-H_Beschrieb: Konstruktion Flachdach
03_Bausystem - Tragende Funktion: In Abklärung; Feuerwiderstand: In Abklärung; Luftschall: In Abklärung; Trittschall: In Abklärung; U-Wert: In Abklärung; Umbau-Status: Neubau; Mehrschichtiger Aufbau: Beton bewehrt
Bekleidung - Bekleidung Gipserarbeiten: In Abklärung; Bekleidung Malerarbeiten: In Abklärung; Bekleidung Putz: In Abklärung; Bekleidung Farbe: RAL / NCS
05_Bauablauf - Bau-Nr.: In Abklärung; Bauablauf Etappe: In Abklärung; Bauablauf Verbauungsort: In Abklärung; Bauablauf Start Ausführung: In Abklärung; Bauablauf Ende Ausführung: In Abklärung
Massivbau Ortbeton - Ortbeton Druckfestigkeitsklasse: In Abklärung; Ortbeton Expositionsklasse: In Abklärung; Ortbeton Grösstkorn - mm: Dmax 32; Ortbeton Chloridgehaltsklasse: Cl 0.10; Ortbeton Konsistenzklasse: C3; Ortbeton Recyclingbeton: In Abklärung; Ortbeton Oberflächenausführung: In Abklärung; Ortbeton Oberflächenklasse - BOK: In Abklärung; Ortbeton Schalungstyp: In Abklärung; Ortbeton Dreikantleisten - mm: In Abklärung; Ortbeton Bew. Überdeckung oben - mm: In Abklärung; Ortbeton Bew. Überdeckung unten - mm: In Abklärung; Ortbeton Bew. Überdeckung aussen - mm: In Abklärung; Ortbeton Bew. Überdeckung innen - mm: In Abklärung; Ortbeton Bewehrungsgehalt - kg/m3: In Abklärung
00_Datenstruktur - BIM Base Version: 4.0.0; Kundenergänzungen Version: v01; CAD Werkzeug Typ: Decke; Klassifizierung: Flachdach Ortbeton; Klassifizierung Level 0: Dach; Modellierungsrichtlinien: https://evolutbaugmbh.sharepoint.com/:b:/s/External/EciBgBMJMZlDgYCafV5wNokBvCJq9PUJAyVGz7O3vsjVrg?e=aLjLN9; Übersicht BIM Base: https://evolutbaugmbh.sharepoint.com/:b:/s/External/EfS4mJ9nZQpOhASXp0n2kW4B0K7N-vHKx-_6Crp5CxEFeg?e=Qu0M5d; Verbesserungsvorschläge BIM Base: https://forms.office.com/e/pcFhFfi5DW; Anleitung Mengen: https://evolutbaugmbh.sharepoint.com/:b:/s/External/ETgyOLO3JxJEqg9rbaRMLVEBHuWIRtkoMiJN1fISDr-3lw?e=E0LTiQ; Anleitung Eigenschaften: https://evolutbaugmbh.sharepoint.com/:b:/s/External/EQedjNXQkc1Btaftc01yAPUBtND9QzXFSH3-7sie6PGFww?e=wP4uf3; Release Notes: https://evolutbaugmbh.sharepoint.com/:b:/s/External/Eb41lwlDI71MhUVvor2V2mUBSaI-0tQK5U9oJAWxpCINuw?e=NtK3j6
02_Mengen - Stärke - m: 0.25
Name | Fläche brutto - m2 | Volumen netto - m3 | Kote Unterkante | Kote Oberkante
Deckennr.-073 | 177.045 | 44.1647 | 11.35 | 11.6
Deckennr.-073 | 35.7898 | 8.94745 | 11.35 | 11.6
Deckennr.-073 | 62.5125 | 15.6281 | 12.1 | 12.35

# IfcRoof: Steildach Typ 01 255 (6)
In: Dachaufsicht
Classification: Steildach Holzbalken (BIM Base by Evolut)
01_Leistungen und Kosten - Gebäude: In Abklärung; Elementpreis - CHF: 0; BKP: 214 - Montagebau in Holz; eBKP-H_Nr: C04.05; eBKP-H_Beschrieb: Konstruktion geneigtes Dach
05_Bauablauf - Bau-Nr.: In Abklärung; Bauablauf Etappe: In Abklärung; Bauablauf Verbauungsort: In Abklärung; Bauablauf Start Ausführung: In Abklärung; Bauablauf Ende Ausführung: In Abklärung
03_Bausystem - Tragende Funktion: In Abklärung; Feuerwiderstand: In Abklärung; Luftschall: In Abklärung; U-Wert: In Abklärung; Umbau-Status: Neubau; Mehrschichtiger Aufbau: Dreischichtplatte-DSP; Balken Konstruktion gedämmt; Gipskartonplatte GKP; Gipskartonplatte GKP; Kalkzementputz Aussen
Bekleidung - Bekleidung Gipserarbeiten: In Abklärung; Bekleidung Malerarbeiten: In Abklärung; Bekleidung Putz: In Abklärung; Bekleidung Farbe: RAL / NCS
Holzbau - Holzbau Sonderelement: In Abklärung
02_Mengen - Stärke - m: 0.255
00_Datenstruktur - BIM Base Version: 4.0.0; Kundenergänzungen Version: v01; CAD Werkzeug Typ: Dach; Klassifizierung: Steildach Holzbalken; Klassifizierung Level 0: Dach; Modellierungsrichtlinien: https://evolutbaugmbh.sharepoint.com/:b:/s/External/EciBgBMJMZlDgYCafV5wNokBvCJq9PUJAyVGz7O3vsjVrg?e=aLjLN9; Übersicht BIM Base: https://evolutbaugmbh.sharepoint.com/:b:/s/External/EfS4mJ9nZQpOhASXp0n2kW4B0K7N-vHKx-_6Crp5CxEFeg?e=Qu0M5d; Verbesserungsvorschläge BIM Base: https://forms.office.com/e/pcFhFfi5DW; Anleitung Mengen: https://evolutbaugmbh.sharepoint.com/:b:/s/External/ETgyOLO3JxJEqg9rbaRMLVEBHuWIRtkoMiJN1fISDr-3lw?e=E0LTiQ; Anleitung Eigenschaften: https://evolutbaugmbh.sharepoint.com/:b:/s/External/EQedjNXQkc1Btaftc01yAPUBtND9QzXFSH3-7sie6PGFww?e=wP4uf3; Release Notes: https://evolutbaugmbh.sharepoint.com/:b:/s/External/Eb41lwlDI71MhUVvor2V2mUBSaI-0tQK5U9oJAWxpCINuw?e=NtK3j6
Name | Fläche brutto - m2 | Volumen netto - m3 | Kote Unterkante | Kote Oberkante
Dach-011 | 203.797 | 39.7516 | 13.128 | 13.383
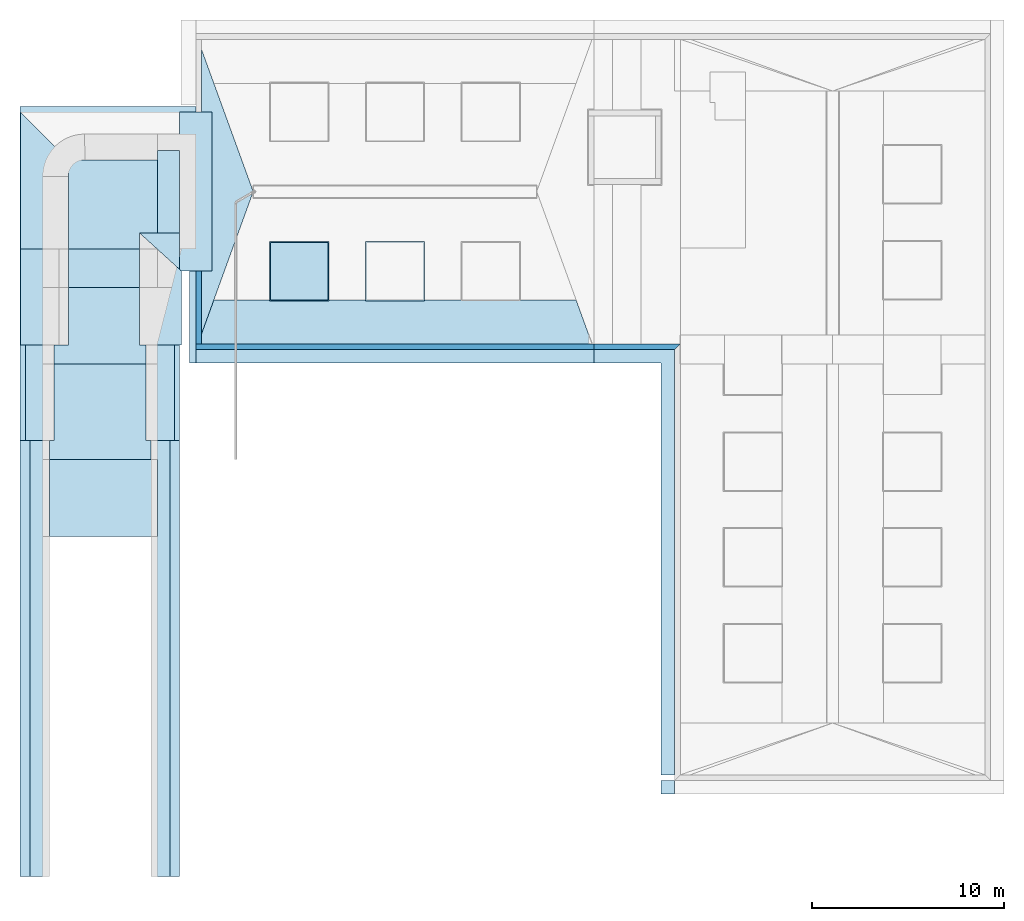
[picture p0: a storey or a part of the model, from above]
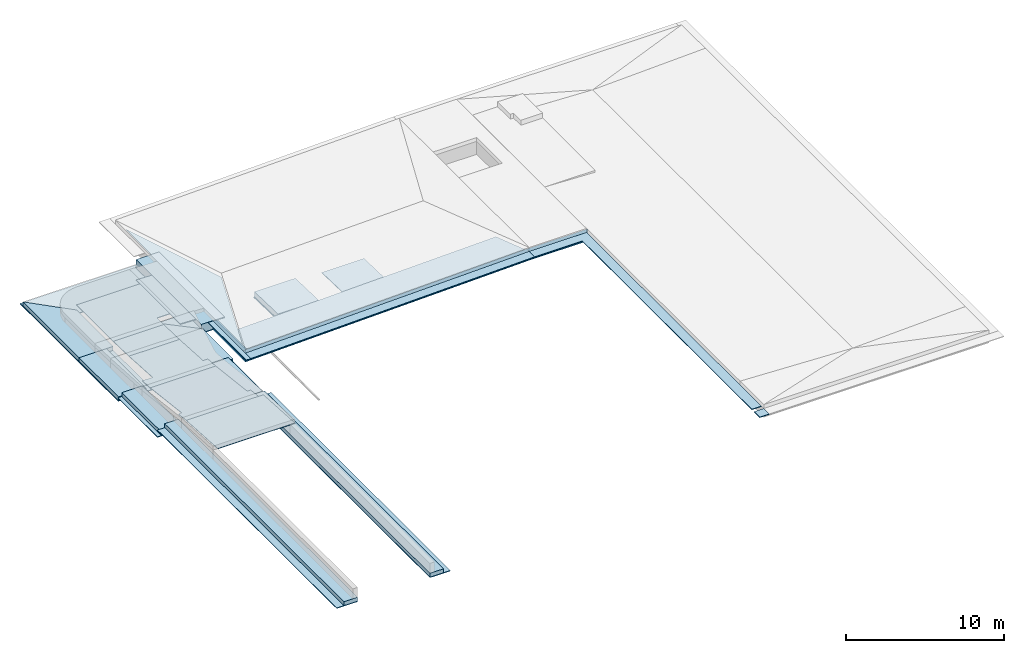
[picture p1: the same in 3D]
Properties of the parts of a building model (IFC4), part 5 of 8

# IfcRoof: Steildach Typ 01 255 (6)
Name | Fläche brutto - m2 | Volumen netto - m3 | Kote Unterkante | Kote Oberkante
2 x Dach-011 | 44.3127 | 11.2997 | 14.909 | 15.164
Dach-011 | 32.477 | 7.94367 | 13.106 | 13.361
Dach-011 | 32.477 | 7.9429 | 13.106 | 13.361
Dach-011 | 229.99 | 46.9398 | 13.107 | 13.362

# IfcRoof: Vordach Typ 01 60 (3)
In: Dachaufsicht
Classification: Vordach Massivholz (BIM Base by Evolut); Material: Dreischichtplatte DSP
05_Bauablauf - Bau-Nr.: In Abklärung; Bauablauf Etappe: In Abklärung; Bauablauf Verbauungsort: In Abklärung; Bauablauf Start Ausführung: In Abklärung; Bauablauf Ende Ausführung: In Abklärung
01_Leistungen und Kosten - Gebäude: In Abklärung; Elementpreis - CHF: 0; BKP: 214 - Montagebau in Holz; eBKP-H_Nr: C04.08; eBKP-H_Beschrieb: Aussen liegende Konstruktion, Vordach
03_Bausystem - Tragende Funktion: In Abklärung; Feuerwiderstand: In Abklärung; Umbau-Status: Neubau; Mehrschichtiger Aufbau: Dreischichtplatte DSP
Holzbau - Holzbau Sonderelement: In Abklärung
Bekleidung - Bekleidung Malerarbeiten: In Abklärung
00_Datenstruktur - BIM Base Version: 4.0.0; Kundenergänzungen Version: v01; CAD Werkzeug Typ: Dach; Klassifizierung: Vordach Massivholz; Klassifizierung Level 0: Dach; Modellierungsrichtlinien: https://evolutbaugmbh.sharepoint.com/:b:/s/External/EciBgBMJMZlDgYCafV5wNokBvCJq9PUJAyVGz7O3vsjVrg?e=aLjLN9; Übersicht BIM Base: https://evolutbaugmbh.sharepoint.com/:b:/s/External/EfS4mJ9nZQpOhASXp0n2kW4B0K7N-vHKx-_6Crp5CxEFeg?e=Qu0M5d; Verbesserungsvorschläge BIM Base: https://forms.office.com/e/pcFhFfi5DW; Anleitung Mengen: https://evolutbaugmbh.sharepoint.com/:b:/s/External/ETgyOLO3JxJEqg9rbaRMLVEBHuWIRtkoMiJN1fISDr-3lw?e=E0LTiQ; Anleitung Eigenschaften: https://evolutbaugmbh.sharepoint.com/:b:/s/External/EQedjNXQkc1Btaftc01yAPUBtND9QzXFSH3-7sie6PGFww?e=wP4uf3; Release Notes: https://evolutbaugmbh.sharepoint.com/:b:/s/External/Eb41lwlDI71MhUVvor2V2mUBSaI-0tQK5U9oJAWxpCINuw?e=NtK3j6
02_Mengen - Stärke - m: 0.06
Name | Fläche brutto - m2 | Volumen netto - m3 | Kote Unterkante | Kote Oberkante
Dach-011 | 38.7664 | 2.32598 | 13.062 | 13.122
Dach-011 | 21.6312 | 1.29787 | 13.609 | 13.669
Dach-011 | 60.2933 | 3.6176 | 13.062 | 13.122

# IfcSanitaryTerminal: Badewanne 27 (5)
Classification: Sanitär Apparate Badewanne (BIM Base by Evolut)
01_Leistungen und Kosten - Gebäude: In Abklärung; Elementpreis - CHF: 0; BKP: 251 - Allgemeine Sanitärapparate; eBKP-H_Nr: D08.05; eBKP-H_Beschrieb: Wasser: Armatur, Apparat
05_Bauablauf - Bau-Nr.: In Abklärung; Bauablauf Etappe: In Abklärung; Bauablauf Verbauungsort: In Abklärung; Bauablauf Start Ausführung: In Abklärung; Bauablauf Ende Ausführung: In Abklärung
02_Mengen - Breite - m: 0.75; Höhe - m: 0.6; Länge brutto - m: 1.7
00_Datenstruktur - BIM Base Version: 4.0.0; Kundenergänzungen Version: v01; CAD Werkzeug Typ: Objekt; Klassifizierung: Sanitär Apparate Badewanne; Klassifizierung Level 0: Haustechnik; Modellierungsrichtlinien: https://evolutbaugmbh.sharepoint.com/:b:/s/External/EciBgBMJMZlDgYCafV5wNokBvCJq9PUJAyVGz7O3vsjVrg?e=aLjLN9; Übersicht BIM Base: https://evolutbaugmbh.sharepoint.com/:b:/s/External/EfS4mJ9nZQpOhASXp0n2kW4B0K7N-vHKx-_6Crp5CxEFeg?e=Qu0M5d; Verbesserungsvorschläge BIM Base: https://forms.office.com/e/pcFhFfi5DW; Anleitung Mengen: https://evolutbaugmbh.sharepoint.com/:b:/s/External/ETgyOLO3JxJEqg9rbaRMLVEBHuWIRtkoMiJN1fISDr-3lw?e=E0LTiQ; Anleitung Eigenschaften: https://evolutbaugmbh.sharepoint.com/:b:/s/External/EQedjNXQkc1Btaftc01yAPUBtND9QzXFSH3-7sie6PGFww?e=wP4uf3; Release Notes: https://evolutbaugmbh.sharepoint.com/:b:/s/External/Eb41lwlDI71MhUVvor2V2mUBSaI-0tQK5U9oJAWxpCINuw?e=NtK3j6
03_Bausystem - Umbau-Status: Neubau
Name | In | Kote Unterkante | Kote Oberkante
2 x Esstisch-4-006 | 1.OG | 2.98 | 3.58
2 x Esstisch-4-006 | 2.OG | 5.88 | 6.48
Esstisch-4-006 | Attika | 8.78 | 9.38

# IfcSanitaryTerminal: Duschkabine 2 27 (7)
Classification: Sanitär Apparate Dusche (BIM Base by Evolut)
03_Bausystem - Umbau-Status: Neubau
02_Mengen - Breite - m: 0.8; Höhe - m: 2.1; Länge brutto - m: 0.8
05_Bauablauf - Bau-Nr.: In Abklärung; Bauablauf Etappe: In Abklärung; Bauablauf Verbauungsort: In Abklärung; Bauablauf Start Ausführung: In Abklärung; Bauablauf Ende Ausführung: In Abklärung
01_Leistungen und Kosten - Gebäude: In Abklärung; Elementpreis - CHF: 0; BKP: 251 - Allgemeine Sanitärapparate; eBKP-H_Nr: D08.05; eBKP-H_Beschrieb: Wasser: Armatur, Apparat
00_Datenstruktur - BIM Base Version: 4.0.0; Kundenergänzungen Version: v01; CAD Werkzeug Typ: Objekt; Klassifizierung: Sanitär Apparate Dusche; Klassifizierung Level 0: Haustechnik; Modellierungsrichtlinien: https://evolutbaugmbh.sharepoint.com/:b:/s/External/EciBgBMJMZlDgYCafV5wNokBvCJq9PUJAyVGz7O3vsjVrg?e=aLjLN9; Übersicht BIM Base: https://evolutbaugmbh.sharepoint.com/:b:/s/External/EfS4mJ9nZQpOhASXp0n2kW4B0K7N-vHKx-_6Crp5CxEFeg?e=Qu0M5d; Verbesserungsvorschläge BIM Base: https://forms.office.com/e/pcFhFfi5DW; Anleitung Mengen: https://evolutbaugmbh.sharepoint.com/:b:/s/External/ETgyOLO3JxJEqg9rbaRMLVEBHuWIRtkoMiJN1fISDr-3lw?e=E0LTiQ; Anleitung Eigenschaften: https://evolutbaugmbh.sharepoint.com/:b:/s/External/EQedjNXQkc1Btaftc01yAPUBtND9QzXFSH3-7sie6PGFww?e=wP4uf3; Release Notes: https://evolutbaugmbh.sharepoint.com/:b:/s/External/Eb41lwlDI71MhUVvor2V2mUBSaI-0tQK5U9oJAWxpCINuw?e=NtK3j6
Name | In | Kote Unterkante | Kote Oberkante
2 x Esstisch-4-003 | 1.OG | 3.03 | 5.13
3 x Esstisch-4-003 | 2.OG | 5.93 | 8.03
2 x Esstisch-4-003 | Attika | 8.83 | 10.93

# IfcSanitaryTerminal: Mehrfach-Becken-Schrank 27 (4)
Classification: Sanitär Apparate Waschbecken + Wasserhahn (BIM Base by Evolut)
01_Leistungen und Kosten - Gebäude: In Abklärung; Elementpreis - CHF: 0; BKP: 251 - Allgemeine Sanitärapparate; eBKP-H_Nr: D08.05; eBKP-H_Beschrieb: Wasser: Armatur, Apparat
05_Bauablauf - Bau-Nr.: In Abklärung; Bauablauf Etappe: In Abklärung; Bauablauf Verbauungsort: In Abklärung; Bauablauf Start Ausführung: In Abklärung; Bauablauf Ende Ausführung: In Abklärung
02_Mengen - Höhe - m: 0.025; Länge brutto - m: 1.2
03_Bausystem - Umbau-Status: Neubau
00_Datenstruktur - BIM Base Version: 4.0.0; Kundenergänzungen Version: v01; CAD Werkzeug Typ: Objekt; Klassifizierung: Sanitär Apparate Waschbecken + Wasserhahn; Klassifizierung Level 0: Haustechnik; Modellierungsrichtlinien: https://evolutbaugmbh.sharepoint.com/:b:/s/External/EciBgBMJMZlDgYCafV5wNokBvCJq9PUJAyVGz7O3vsjVrg?e=aLjLN9; Übersicht BIM Base: https://evolutbaugmbh.sharepoint.com/:b:/s/External/EfS4mJ9nZQpOhASXp0n2kW4B0K7N-vHKx-_6Crp5CxEFeg?e=Qu0M5d; Verbesserungsvorschläge BIM Base: https://forms.office.com/e/pcFhFfi5DW; Anleitung Mengen: https://evolutbaugmbh.sharepoint.com/:b:/s/External/ETgyOLO3JxJEqg9rbaRMLVEBHuWIRtkoMiJN1fISDr-3lw?e=E0LTiQ; Anleitung Eigenschaften: https://evolutbaugmbh.sharepoint.com/:b:/s/External/EQedjNXQkc1Btaftc01yAPUBtND9QzXFSH3-7sie6PGFww?e=wP4uf3; Release Notes: https://evolutbaugmbh.sharepoint.com/:b:/s/External/Eb41lwlDI71MhUVvor2V2mUBSaI-0tQK5U9oJAWxpCINuw?e=NtK3j6
Name | In | Breite - m | Kote Unterkante | Kote Oberkante
Esstisch-4-005 | 1.OG | 0.5 | 3.713 | 3.738
Esstisch-4-005 | 1.OG | 0.485 | 3.713 | 3.738
2 x Esstisch-4-005 | 2.OG | 0.5 | 6.613 | 6.638

# IfcSanitaryTerminal: WC 27 (7)
Classification: Sanitär Apparate WC (BIM Base by Evolut)
01_Leistungen und Kosten - Gebäude: In Abklärung; Elementpreis - CHF: 0; BKP: 251 - Allgemeine Sanitärapparate; eBKP-H_Nr: D08.05; eBKP-H_Beschrieb: Wasser: Armatur, Apparat
05_Bauablauf - Bau-Nr.: In Abklärung; Bauablauf Etappe: In Abklärung; Bauablauf Verbauungsort: In Abklärung; Bauablauf Start Ausführung: In Abklärung; Bauablauf Ende Ausführung: In Abklärung
02_Mengen - Breite - m: 0.56; Höhe - m: 0.33; Länge brutto - m: 0.35
03_Bausystem - Umbau-Status: Neubau
00_Datenstruktur - BIM Base Version: 4.0.0; Kundenergänzungen Version: v01; CAD Werkzeug Typ: Objekt; Klassifizierung: Sanitär Apparate WC; Klassifizierung Level 0: Haustechnik; Modellierungsrichtlinien: https://evolutbaugmbh.sharepoint.com/:b:/s/External/EciBgBMJMZlDgYCafV5wNokBvCJq9PUJAyVGz7O3vsjVrg?e=aLjLN9; Übersicht BIM Base: https://evolutbaugmbh.sharepoint.com/:b:/s/External/EfS4mJ9nZQpOhASXp0n2kW4B0K7N-vHKx-_6Crp5CxEFeg?e=Qu0M5d; Verbesserungsvorschläge BIM Base: https://forms.office.com/e/pcFhFfi5DW; Anleitung Mengen: https://evolutbaugmbh.sharepoint.com/:b:/s/External/ETgyOLO3JxJEqg9rbaRMLVEBHuWIRtkoMiJN1fISDr-3lw?e=E0LTiQ; Anleitung Eigenschaften: https://evolutbaugmbh.sharepoint.com/:b:/s/External/EQedjNXQkc1Btaftc01yAPUBtND9QzXFSH3-7sie6PGFww?e=wP4uf3; Release Notes: https://evolutbaugmbh.sharepoint.com/:b:/s/External/Eb41lwlDI71MhUVvor2V2mUBSaI-0tQK5U9oJAWxpCINuw?e=NtK3j6
Name | In | Kote Unterkante | Kote Oberkante
2 x Esstisch-4-004 | 1.OG | 3.12 | 3.45
3 x Esstisch-4-004 | 2.OG | 6.02 | 6.35
2 x Esstisch-4-004 | Attika | 8.92 | 9.25

# IfcSanitaryTerminal: Waschbecken 7 27 (3)
Classification: Sanitär Apparate Waschbecken + Wasserhahn (BIM Base by Evolut)
01_Leistungen und Kosten - Gebäude: In Abklärung; Elementpreis - CHF: 0; BKP: 251 - Allgemeine Sanitärapparate; eBKP-H_Nr: D08.05; eBKP-H_Beschrieb: Wasser: Armatur, Apparat
05_Bauablauf - Bau-Nr.: In Abklärung; Bauablauf Etappe: In Abklärung; Bauablauf Verbauungsort: In Abklärung; Bauablauf Start Ausführung: In Abklärung; Bauablauf Ende Ausführung: In Abklärung
02_Mengen - Breite - m: 0.6; Höhe - m: 0.2; Länge brutto - m: 0.5
03_Bausystem - Umbau-Status: Neubau
00_Datenstruktur - BIM Base Version: 4.0.0; Kundenergänzungen Version: v01; CAD Werkzeug Typ: Objekt; Klassifizierung: Sanitär Apparate Waschbecken + Wasserhahn; Klassifizierung Level 0: Haustechnik; Modellierungsrichtlinien: https://evolutbaugmbh.sharepoint.com/:b:/s/External/EciBgBMJMZlDgYCafV5wNokBvCJq9PUJAyVGz7O3vsjVrg?e=aLjLN9; Übersicht BIM Base: https://evolutbaugmbh.sharepoint.com/:b:/s/External/EfS4mJ9nZQpOhASXp0n2kW4B0K7N-vHKx-_6Crp5CxEFeg?e=Qu0M5d; Verbesserungsvorschläge BIM Base: https://forms.office.com/e/pcFhFfi5DW; Anleitung Mengen: https://evolutbaugmbh.sharepoint.com/:b:/s/External/ETgyOLO3JxJEqg9rbaRMLVEBHuWIRtkoMiJN1fISDr-3lw?e=E0LTiQ; Anleitung Eigenschaften: https://evolutbaugmbh.sharepoint.com/:b:/s/External/EQedjNXQkc1Btaftc01yAPUBtND9QzXFSH3-7sie6PGFww?e=wP4uf3; Release Notes: https://evolutbaugmbh.sharepoint.com/:b:/s/External/Eb41lwlDI71MhUVvor2V2mUBSaI-0tQK5U9oJAWxpCINuw?e=NtK3j6
Name | In | Kote Unterkante | Kote Oberkante
Esstisch-4-005 | 2.OG | 6.714 | 6.914
2 x Esstisch-4-005 | Attika | 9.614 | 9.814

# IfcSanitaryTerminal: Waschmaschine Einbau 27 (6)
Classification: Sanitär Apparate (BIM Base by Evolut)
01_Leistungen und Kosten - Gebäude: In Abklärung; Elementpreis - CHF: 0; BKP: 251 - Allgemeine Sanitärapparate; eBKP-H_Nr: D08.05; eBKP-H_Beschrieb: Wasser: Armatur, Apparat
05_Bauablauf - Bau-Nr.: In Abklärung; Bauablauf Etappe: In Abklärung; Bauablauf Verbauungsort: In Abklärung; Bauablauf Start Ausführung: In Abklärung; Bauablauf Ende Ausführung: In Abklärung
02_Mengen - Breite - m: 0.6; Höhe - m: 0.865; Länge brutto - m: 0.6
00_Datenstruktur - BIM Base Version: 4.0.0; Kundenergänzungen Version: v01; CAD Werkzeug Typ: Objekt; Klassifizierung: Sanitär Apparate; Klassifizierung Level 0: Haustechnik; Modellierungsrichtlinien: https://evolutbaugmbh.sharepoint.com/:b:/s/External/EciBgBMJMZlDgYCafV5wNokBvCJq9PUJAyVGz7O3vsjVrg?e=aLjLN9; Übersicht BIM Base: https://evolutbaugmbh.sharepoint.com/:b:/s/External/EfS4mJ9nZQpOhASXp0n2kW4B0K7N-vHKx-_6Crp5CxEFeg?e=Qu0M5d; Verbesserungsvorschläge BIM Base: https://forms.office.com/e/pcFhFfi5DW; Anleitung Mengen: https://evolutbaugmbh.sharepoint.com/:b:/s/External/ETgyOLO3JxJEqg9rbaRMLVEBHuWIRtkoMiJN1fISDr-3lw?e=E0LTiQ; Anleitung Eigenschaften: https://evolutbaugmbh.sharepoint.com/:b:/s/External/EQedjNXQkc1Btaftc01yAPUBtND9QzXFSH3-7sie6PGFww?e=wP4uf3; Release Notes: https://evolutbaugmbh.sharepoint.com/:b:/s/External/Eb41lwlDI71MhUVvor2V2mUBSaI-0tQK5U9oJAWxpCINuw?e=NtK3j6
03_Bausystem - Umbau-Status: Neubau
Name | In | Kote Unterkante | Kote Oberkante
Esstisch-4-002 | 1.OG | 3.05 | 3.915
Esstisch-4-002 | 1.OG | 3.915 | 4.78
Esstisch-4-002 | 2.OG | 5.95 | 6.815
Esstisch-4-002 | 2.OG | 6.815 | 7.68
Esstisch-4-002 | Attika | 8.85 | 9.715
Esstisch-4-002 | Attika | 9.715 | 10.58

# IfcShadingDevice: Sonnensegel 27 (4)
In: Attika
Classification: Markise (BIM Base by Evolut)
01_Leistungen und Kosten - Gebäude: In Abklärung; Elementpreis - CHF: 0; BKP: 228 - Äussere Abschlüsse, Sonnenschutz; eBKP-H_Nr: E03.04; eBKP-H_Beschrieb: Sonnenschutz, Wetterschutz
05_Bauablauf - Bau-Nr.: In Abklärung; Bauablauf Etappe: In Abklärung; Bauablauf Verbauungsort: In Abklärung; Bauablauf Start Ausführung: In Abklärung; Bauablauf Ende Ausführung: In Abklärung
Sonnenschutz - Sonnenschutz Steuerung: In Abklärung; Sonnenschutz Antrieb: In Abklärung; Sonnenschutz Farbe: RAL / NCS
03_Bausystem - Umbau-Status: Neubau
00_Datenstruktur - BIM Base Version: 4.0.0; Kundenergänzungen Version: v01; CAD Werkzeug Typ: Objekt; Klassifizierung: Markise; Klassifizierung Level 0: Sonnenschutz; Modellierungsrichtlinien: https://evolutbaugmbh.sharepoint.com/:b:/s/External/EciBgBMJMZlDgYCafV5wNokBvCJq9PUJAyVGz7O3vsjVrg?e=aLjLN9; Übersicht BIM Base: https://evolutbaugmbh.sharepoint.com/:b:/s/External/EfS4mJ9nZQpOhASXp0n2kW4B0K7N-vHKx-_6Crp5CxEFeg?e=Qu0M5d; Verbesserungsvorschläge BIM Base: https://forms.office.com/e/pcFhFfi5DW; Anleitung Mengen: https://evolutbaugmbh.sharepoint.com/:b:/s/External/ETgyOLO3JxJEqg9rbaRMLVEBHuWIRtkoMiJN1fISDr-3lw?e=E0LTiQ; Anleitung Eigenschaften: https://evolutbaugmbh.sharepoint.com/:b:/s/External/EQedjNXQkc1Btaftc01yAPUBtND9QzXFSH3-7sie6PGFww?e=wP4uf3; Release Notes: https://evolutbaugmbh.sharepoint.com/:b:/s/External/Eb41lwlDI71MhUVvor2V2mUBSaI-0tQK5U9oJAWxpCINuw?e=NtK3j6
Name | Breite - m | Höhe - m | Länge brutto - m | Volumen netto - m3 | Kote Unterkante | Kote Oberkante
Möbel-018 | 1.81153 | 0.14974 | 4.6408 | 0.251311 | 11.45 | 11.6
Möbel-018 | 1.76636 | 0.145788 | 4.7908 | 0.258892 | 11.444 | 11.59
Möbel-018 | 1.30245 | 0.105201 | 4.7908 | 0.258892 | 11.45 | 11.555
Möbel-018 | 0.359011 | 0.0226605 | 4.7908 | 0.258892 | 11.45 | 11.473

# IfcSlab: Balkon Typ 01 250 (5)
Classification: Balkon Ortbeton (BIM Base by Evolut); Material: Beton bewehrt
01_Leistungen und Kosten - Gebäude: In Abklärung; Elementpreis - CHF: 0; BKP: 211 - Baumeisterarbeiten; eBKP-H_Nr: C04.08; eBKP-H_Beschrieb: Aussen liegende Konstruktion, Vordach
05_Bauablauf - Bau-Nr.: In Abklärung; Bauablauf Etappe: In Abklärung; Bauablauf Verbauungsort: In Abklärung; Bauablauf Start Ausführung: In Abklärung; Bauablauf Ende Ausführung: In Abklärung
Massivbau Ortbeton - Ortbeton Druckfestigkeitsklasse: In Abklärung; Ortbeton Expositionsklasse: In Abklärung; Ortbeton Grösstkorn - mm: Dmax 32; Ortbeton Chloridgehaltsklasse: Cl 0.10; Ortbeton Konsistenzklasse: C3; Ortbeton Recyclingbeton: In Abklärung; Ortbeton Oberflächenausführung: In Abklärung; Ortbeton Oberflächenklasse - BOK: In Abklärung; Ortbeton Schalungstyp: In Abklärung; Ortbeton Dreikantleisten - mm: In Abklärung; Ortbeton Bew. Überdeckung oben - mm: In Abklärung; Ortbeton Bew. Überdeckung unten - mm: In Abklärung; Ortbeton Bew. Überdeckung aussen - mm: In Abklärung; Ortbeton Bew. Überdeckung innen - mm: In Abklärung; Ortbeton Bewehrungsgehalt - kg/m3: In Abklärung
03_Bausystem - Tragende Funktion: In Abklärung; Feuerwiderstand: In Abklärung; Trittschall: In Abklärung; Umbau-Status: Neubau; Mehrschichtiger Aufbau: Beton bewehrt
Bekleidung - Bekleidung Malerarbeiten: In Abklärung
00_Datenstruktur - BIM Base Version: 4.0.0; Kundenergänzungen Version: v01; CAD Werkzeug Typ: Decke; Klassifizierung: Balkon Ortbeton; Klassifizierung Level 0: Decke; Modellierungsrichtlinien: https://evolutbaugmbh.sharepoint.com/:b:/s/External/EciBgBMJMZlDgYCafV5wNokBvCJq9PUJAyVGz7O3vsjVrg?e=aLjLN9; Übersicht BIM Base: https://evolutbaugmbh.sharepoint.com/:b:/s/External/EfS4mJ9nZQpOhASXp0n2kW4B0K7N-vHKx-_6Crp5CxEFeg?e=Qu0M5d; Verbesserungsvorschläge BIM Base: https://forms.office.com/e/pcFhFfi5DW; Anleitung Mengen: https://evolutbaugmbh.sharepoint.com/:b:/s/External/ETgyOLO3JxJEqg9rbaRMLVEBHuWIRtkoMiJN1fISDr-3lw?e=E0LTiQ; Anleitung Eigenschaften: https://evolutbaugmbh.sharepoint.com/:b:/s/External/EQedjNXQkc1Btaftc01yAPUBtND9QzXFSH3-7sie6PGFww?e=wP4uf3; Release Notes: https://evolutbaugmbh.sharepoint.com/:b:/s/External/Eb41lwlDI71MhUVvor2V2mUBSaI-0tQK5U9oJAWxpCINuw?e=NtK3j6
02_Mengen - Stärke - m: 0.25
Name | In | Fläche brutto - m2 | Volumen netto - m3 | Kote Unterkante | Kote Oberkante
Deckennr.-073 | EG | 26.622 | 6.6555 | 2.65 | 2.9
Deckennr.-073 | EG | 42.1541 | 10.5331 | 2.65 | 2.9
Deckennr.-073 | 1.OG | 47.9393 | 11.9794 | 5.55 | 5.8
Deckennr.-073 | 1.OG | 26.622 | 6.6555 | 5.55 | 5.8
Deckennr.-073 | 2.OG | 37.0219 | 9.25548 | 8.45 | 8.7

# IfcSlab: Beton bewehrt 147, Deckennr.-073
In: Fundation
Classification: Bodenplatte Ortbeton (BIM Base by Evolut); Material: Beton bewehrt
01_Leistungen und Kosten - Gebäude: In Abklärung; Elementpreis - CHF: 0; BKP: 211 - Baumeisterarbeiten; eBKP-H_Nr: C01.03; eBKP-H_Beschrieb: Bodenplatte
05_Bauablauf - Bau-Nr.: In Abklärung; Bauablauf Etappe: In Abklärung; Bauablauf Verbauungsort: In Abklärung; Bauablauf Start Ausführung: In Abklärung; Bauablauf Ende Ausführung: In Abklärung
03_Bausystem - Tragende Funktion: In Abklärung; Feuerwiderstand: In Abklärung; Trittschall: In Abklärung; U-Wert: In Abklärung; Umbau-Status: Neubau; Mehrschichtiger Aufbau: Beton bewehrt
Massivbau Ortbeton - Ortbeton Druckfestigkeitsklasse: In Abklärung; Ortbeton Expositionsklasse: In Abklärung; Ortbeton Grösstkorn - mm: Dmax 32; Ortbeton Chloridgehaltsklasse: Cl 0.10; Ortbeton Konsistenzklasse: C3; Ortbeton Recyclingbeton: In Abklärung; Ortbeton Oberflächenausführung: In Abklärung; Ortbeton Oberflächenklasse - BOK: In Abklärung; Ortbeton Schalungstyp: In Abklärung; Ortbeton Dreikantleisten - mm: In Abklärung; Ortbeton Bew. Überdeckung oben - mm: In Abklärung; Ortbeton Bew. Überdeckung unten - mm: In Abklärung; Ortbeton Bew. Überdeckung aussen - mm: In Abklärung; Ortbeton Bew. Überdeckung innen - mm: In Abklärung; Ortbeton Bewehrungsgehalt - kg/m3: In Abklärung
Bekleidung - Bekleidung Malerarbeiten: In Abklärung
02_Mengen - Stärke - m: 0.147486; Fläche brutto - m2: 34.003; Volumen netto - m3: 5.01495; Kote Unterkante: -3.448; Kote Oberkante: -3.301
00_Datenstruktur - BIM Base Version: 4.0.0; Kundenergänzungen Version: v01; CAD Werkzeug Typ: Decke; Klassifizierung: Bodenplatte Ortbeton; Klassifizierung Level 0: Decke; Modellierungsrichtlinien: https://evolutbaugmbh.sharepoint.com/:b:/s/External/EciBgBMJMZlDgYCafV5wNokBvCJq9PUJAyVGz7O3vsjVrg?e=aLjLN9; Übersicht BIM Base: https://evolutbaugmbh.sharepoint.com/:b:/s/External/EfS4mJ9nZQpOhASXp0n2kW4B0K7N-vHKx-_6Crp5CxEFeg?e=Qu0M5d; Verbesserungsvorschläge BIM Base: https://forms.office.com/e/pcFhFfi5DW; Anleitung Mengen: https://evolutbaugmbh.sharepoint.com/:b:/s/External/ETgyOLO3JxJEqg9rbaRMLVEBHuWIRtkoMiJN1fISDr-3lw?e=E0LTiQ; Anleitung Eigenschaften: https://evolutbaugmbh.sharepoint.com/:b:/s/External/EQedjNXQkc1Btaftc01yAPUBtND9QzXFSH3-7sie6PGFww?e=wP4uf3; Release Notes: https://evolutbaugmbh.sharepoint.com/:b:/s/External/Eb41lwlDI71MhUVvor2V2mUBSaI-0tQK5U9oJAWxpCINuw?e=NtK3j6

# IfcSlab: Beton bewehrt 300 (13)
In: Fundation
Classification: Bodenplatte Ortbeton (BIM Base by Evolut); Material: Beton bewehrt
01_Leistungen und Kosten - Gebäude: In Abklärung; Elementpreis - CHF: 0; BKP: 211 - Baumeisterarbeiten; eBKP-H_Nr: C01.03; eBKP-H_Beschrieb: Bodenplatte
05_Bauablauf - Bau-Nr.: In Abklärung; Bauablauf Etappe: In Abklärung; Bauablauf Verbauungsort: In Abklärung; Bauablauf Start Ausführung: In Abklärung; Bauablauf Ende Ausführung: In Abklärung
03_Bausystem - Tragende Funktion: In Abklärung; Feuerwiderstand: In Abklärung; Trittschall: In Abklärung; U-Wert: In Abklärung; Umbau-Status: Neubau; Mehrschichtiger Aufbau: Beton bewehrt
Massivbau Ortbeton - Ortbeton Druckfestigkeitsklasse: In Abklärung; Ortbeton Expositionsklasse: In Abklärung; Ortbeton Grösstkorn - mm: Dmax 32; Ortbeton Chloridgehaltsklasse: Cl 0.10; Ortbeton Konsistenzklasse: C3; Ortbeton Recyclingbeton: In Abklärung; Ortbeton Oberflächenausführung: In Abklärung; Ortbeton Oberflächenklasse - BOK: In Abklärung; Ortbeton Schalungstyp: In Abklärung; Ortbeton Dreikantleisten - mm: In Abklärung; Ortbeton Bew. Überdeckung oben - mm: In Abklärung; Ortbeton Bew. Überdeckung unten - mm: In Abklärung; Ortbeton Bew. Überdeckung aussen - mm: In Abklärung; Ortbeton Bew. Überdeckung innen - mm: In Abklärung; Ortbeton Bewehrungsgehalt - kg/m3: In Abklärung
Bekleidung - Bekleidung Malerarbeiten: In Abklärung
00_Datenstruktur - BIM Base Version: 4.0.0; Kundenergänzungen Version: v01; Klassifizierung: Bodenplatte Ortbeton; Klassifizierung Level 0: Decke; Modellierungsrichtlinien: https://evolutbaugmbh.sharepoint.com/:b:/s/External/EciBgBMJMZlDgYCafV5wNokBvCJq9PUJAyVGz7O3vsjVrg?e=aLjLN9; Übersicht BIM Base: https://evolutbaugmbh.sharepoint.com/:b:/s/External/EfS4mJ9nZQpOhASXp0n2kW4B0K7N-vHKx-_6Crp5CxEFeg?e=Qu0M5d; Verbesserungsvorschläge BIM Base: https://forms.office.com/e/pcFhFfi5DW; Anleitung Mengen: https://evolutbaugmbh.sharepoint.com/:b:/s/External/ETgyOLO3JxJEqg9rbaRMLVEBHuWIRtkoMiJN1fISDr-3lw?e=E0LTiQ; Anleitung Eigenschaften: https://evolutbaugmbh.sharepoint.com/:b:/s/External/EQedjNXQkc1Btaftc01yAPUBtND9QzXFSH3-7sie6PGFww?e=wP4uf3; Release Notes: https://evolutbaugmbh.sharepoint.com/:b:/s/External/Eb41lwlDI71MhUVvor2V2mUBSaI-0tQK5U9oJAWxpCINuw?e=NtK3j6
Name | Stärke - m | Fläche brutto - m2 | Volumen netto - m3 | Kote Unterkante | Kote Oberkante | CAD Werkzeug Typ
2 x Dach-008 | 0.299817 | 146.977 | 44.0663 | -4.361 | -4.061 | Dach
Dach-009 | 0.3 | 24.903 | 7.47089 | -3.936 | -3.636 | Dach
2 x Dach-009 | 0.3 | 24.8993 | 7.46979 | -3.932 | -3.632 | Dach
4 x Dach-009 | 0.3 | 12.3849 | 3.71547 | -3.93 | -3.63 | Dach
2 x Dach-009 | 0.3 | 272.468 | 81.7403 | -3.93 | -3.63 | Dach
Deckennr.-068 | 0.3 | 58.82 | 17.646 | -3.6 | -3.3 | Decke
Dach-009 | 0.3 | 24.7856 | 7.43568 | -4.361 | -4.061 | Dach

# IfcSlab: Beton bewehrt 528, Deckennr.-073
In: Fundation
Classification: Bodenplatte Ortbeton (BIM Base by Evolut); Material: Beton bewehrt
01_Leistungen und Kosten - Gebäude: In Abklärung; Elementpreis - CHF: 0; BKP: 211 - Baumeisterarbeiten; eBKP-H_Nr: C01.03; eBKP-H_Beschrieb: Bodenplatte
05_Bauablauf - Bau-Nr.: In Abklärung; Bauablauf Etappe: In Abklärung; Bauablauf Verbauungsort: In Abklärung; Bauablauf Start Ausführung: In Abklärung; Bauablauf Ende Ausführung: In Abklärung
03_Bausystem - Tragende Funktion: In Abklärung; Feuerwiderstand: In Abklärung; Trittschall: In Abklärung; U-Wert: In Abklärung; Umbau-Status: Neubau; Mehrschichtiger Aufbau: Beton bewehrt
Massivbau Ortbeton - Ortbeton Druckfestigkeitsklasse: In Abklärung; Ortbeton Expositionsklasse: In Abklärung; Ortbeton Grösstkorn - mm: Dmax 32; Ortbeton Chloridgehaltsklasse: Cl 0.10; Ortbeton Konsistenzklasse: C3; Ortbeton Recyclingbeton: In Abklärung; Ortbeton Oberflächenausführung: In Abklärung; Ortbeton Oberflächenklasse - BOK: In Abklärung; Ortbeton Schalungstyp: In Abklärung; Ortbeton Dreikantleisten - mm: In Abklärung; Ortbeton Bew. Überdeckung oben - mm: In Abklärung; Ortbeton Bew. Überdeckung unten - mm: In Abklärung; Ortbeton Bew. Überdeckung aussen - mm: In Abklärung; Ortbeton Bew. Überdeckung innen - mm: In Abklärung; Ortbeton Bewehrungsgehalt - kg/m3: In Abklärung
Bekleidung - Bekleidung Malerarbeiten: In Abklärung
02_Mengen - Stärke - m: 0.528; Fläche brutto - m2: 4.40838; Volumen netto - m3: 2.26033; Kote Unterkante: -3.448; Kote Oberkante: -2.92
00_Datenstruktur - BIM Base Version: 4.0.0; Kundenergänzungen Version: v01; CAD Werkzeug Typ: Decke; Klassifizierung: Bodenplatte Ortbeton; Klassifizierung Level 0: Decke; Modellierungsrichtlinien: https://evolutbaugmbh.sharepoint.com/:b:/s/External/EciBgBMJMZlDgYCafV5wNokBvCJq9PUJAyVGz7O3vsjVrg?e=aLjLN9; Übersicht BIM Base: https://evolutbaugmbh.sharepoint.com/:b:/s/External/EfS4mJ9nZQpOhASXp0n2kW4B0K7N-vHKx-_6Crp5CxEFeg?e=Qu0M5d; Verbesserungsvorschläge BIM Base: https://forms.office.com/e/pcFhFfi5DW; Anleitung Mengen: https://evolutbaugmbh.sharepoint.com/:b:/s/External/ETgyOLO3JxJEqg9rbaRMLVEBHuWIRtkoMiJN1fISDr-3lw?e=E0LTiQ; Anleitung Eigenschaften: https://evolutbaugmbh.sharepoint.com/:b:/s/External/EQedjNXQkc1Btaftc01yAPUBtND9QzXFSH3-7sie6PGFww?e=wP4uf3; Release Notes: https://evolutbaugmbh.sharepoint.com/:b:/s/External/Eb41lwlDI71MhUVvor2V2mUBSaI-0tQK5U9oJAWxpCINuw?e=NtK3j6

# IfcSlab: Beton bewehrt 800 x 600 (2)
In: UG
Classification: Geschossdecke Ortbeton (BIM Base by Evolut); Material: Beton bewehrt
01_Leistungen und Kosten - Gebäude: In Abklärung; Elementpreis - CHF: 0; BKP: 211 - Baumeisterarbeiten; eBKP-H_Nr: C04.01; eBKP-H_Beschrieb: Geschossdecke
05_Bauablauf - Bau-Nr.: In Abklärung; Bauablauf Etappe: In Abklärung; Bauablauf Verbauungsort: In Abklärung; Bauablauf Start Ausführung: In Abklärung; Bauablauf Ende Ausführung: In Abklärung
03_Bausystem - Tragende Funktion: In Abklärung; Feuerwiderstand: In Abklärung; Luftschall: In Abklärung; Trittschall: In Abklärung; U-Wert: In Abklärung; Umbau-Status: Neubau; Mehrschichtiger Aufbau: Beton bewehrt
Massivbau Ortbeton - Ortbeton Druckfestigkeitsklasse: In Abklärung; Ortbeton Expositionsklasse: In Abklärung; Ortbeton Grösstkorn - mm: Dmax 32; Ortbeton Chloridgehaltsklasse: Cl 0.10; Ortbeton Konsistenzklasse: C3; Ortbeton Recyclingbeton: In Abklärung; Ortbeton Oberflächenausführung: In Abklärung; Ortbeton Oberflächenklasse - BOK: In Abklärung; Ortbeton Schalungstyp: In Abklärung; Ortbeton Dreikantleisten - mm: In Abklärung; Ortbeton Bew. Überdeckung oben - mm: In Abklärung; Ortbeton Bew. Überdeckung unten - mm: In Abklärung; Ortbeton Bew. Überdeckung aussen - mm: In Abklärung; Ortbeton Bew. Überdeckung innen - mm: In Abklärung; Ortbeton Bewehrungsgehalt - kg/m3: In Abklärung
Bekleidung - Bekleidung Gipserarbeiten: In Abklärung; Bekleidung Malerarbeiten: In Abklärung; Bekleidung Putz: In Abklärung; Bekleidung Farbe: RAL / NCS
02_Mengen - Breite - m: 0.8; Höhe - m: 0.6; Stärke - m: 0.8; Kote Unterkante: -0.6; Kote Oberkante: 0
00_Datenstruktur - BIM Base Version: 4.0.0; Kundenergänzungen Version: v01; CAD Werkzeug Typ: Träger; Klassifizierung: Geschossdecke Ortbeton; Klassifizierung Level 0: Decke; Modellierungsrichtlinien: https://evolutbaugmbh.sharepoint.com/:b:/s/External/EciBgBMJMZlDgYCafV5wNokBvCJq9PUJAyVGz7O3vsjVrg?e=aLjLN9; Übersicht BIM Base: https://evolutbaugmbh.sharepoint.com/:b:/s/External/EfS4mJ9nZQpOhASXp0n2kW4B0K7N-vHKx-_6Crp5CxEFeg?e=Qu0M5d; Verbesserungsvorschläge BIM Base: https://forms.office.com/e/pcFhFfi5DW; Anleitung Mengen: https://evolutbaugmbh.sharepoint.com/:b:/s/External/ETgyOLO3JxJEqg9rbaRMLVEBHuWIRtkoMiJN1fISDr-3lw?e=E0LTiQ; Anleitung Eigenschaften: https://evolutbaugmbh.sharepoint.com/:b:/s/External/EQedjNXQkc1Btaftc01yAPUBtND9QzXFSH3-7sie6PGFww?e=wP4uf3; Release Notes: https://evolutbaugmbh.sharepoint.com/:b:/s/External/Eb41lwlDI71MhUVvor2V2mUBSaI-0tQK5U9oJAWxpCINuw?e=NtK3j6
Name | Länge brutto - m | Fläche brutto - m2 | Volumen netto - m3
Unterzug-025 | 8.25 | 6.6 | 3.768
Unterzug-025 | 20.8 | 16.64 | 9.792

# IfcSlab: Gefällsbeton (3)
In: UG
Classification: Geschossdecke Ortbeton (BIM Base by Evolut); Material: Gefällsbeton
01_Leistungen und Kosten - Gebäude: In Abklärung; Elementpreis - CHF: 0; BKP: 211 - Baumeisterarbeiten; eBKP-H_Nr: C04.01; eBKP-H_Beschrieb: Geschossdecke
03_Bausystem - Tragende Funktion: In Abklärung; Feuerwiderstand: In Abklärung; Luftschall: In Abklärung; Trittschall: In Abklärung; U-Wert: In Abklärung; Umbau-Status: Neubau; Mehrschichtiger Aufbau: Gefällsbeton
Massivbau Ortbeton - Ortbeton Druckfestigkeitsklasse: In Abklärung; Ortbeton Expositionsklasse: In Abklärung; Ortbeton Grösstkorn - mm: Dmax 32; Ortbeton Chloridgehaltsklasse: Cl 0.10; Ortbeton Konsistenzklasse: C3; Ortbeton Recyclingbeton: In Abklärung; Ortbeton Oberflächenausführung: In Abklärung; Ortbeton Oberflächenklasse - BOK: In Abklärung; Ortbeton Schalungstyp: In Abklärung; Ortbeton Dreikantleisten - mm: In Abklärung; Ortbeton Bew. Überdeckung oben - mm: In Abklärung; Ortbeton Bew. Überdeckung unten - mm: In Abklärung; Ortbeton Bew. Überdeckung aussen - mm: In Abklärung; Ortbeton Bew. Überdeckung innen - mm: In Abklärung; Ortbeton Bewehrungsgehalt - kg/m3: In Abklärung
05_Bauablauf - Bau-Nr.: In Abklärung; Bauablauf Etappe: In Abklärung; Bauablauf Verbauungsort: In Abklärung; Bauablauf Start Ausführung: In Abklärung; Bauablauf Ende Ausführung: In Abklärung
Bekleidung - Bekleidung Gipserarbeiten: In Abklärung; Bekleidung Malerarbeiten: In Abklärung; Bekleidung Putz: In Abklärung; Bekleidung Farbe: RAL / NCS
00_Datenstruktur - BIM Base Version: 4.0.0; Kundenergänzungen Version: v01; CAD Werkzeug Typ: Freifläche; Klassifizierung: Geschossdecke Ortbeton; Klassifizierung Level 0: Decke; Modellierungsrichtlinien: https://evolutbaugmbh.sharepoint.com/:b:/s/External/EciBgBMJMZlDgYCafV5wNokBvCJq9PUJAyVGz7O3vsjVrg?e=aLjLN9; Übersicht BIM Base: https://evolutbaugmbh.sharepoint.com/:b:/s/External/EfS4mJ9nZQpOhASXp0n2kW4B0K7N-vHKx-_6Crp5CxEFeg?e=Qu0M5d; Verbesserungsvorschläge BIM Base: https://forms.office.com/e/pcFhFfi5DW; Anleitung Mengen: https://evolutbaugmbh.sharepoint.com/:b:/s/External/ETgyOLO3JxJEqg9rbaRMLVEBHuWIRtkoMiJN1fISDr-3lw?e=E0LTiQ; Anleitung Eigenschaften: https://evolutbaugmbh.sharepoint.com/:b:/s/External/EQedjNXQkc1Btaftc01yAPUBtND9QzXFSH3-7sie6PGFww?e=wP4uf3; Release Notes: https://evolutbaugmbh.sharepoint.com/:b:/s/External/Eb41lwlDI71MhUVvor2V2mUBSaI-0tQK5U9oJAWxpCINuw?e=NtK3j6
Name | Stärke - m | Fläche brutto - m2 | Volumen netto - m3 | Kote Unterkante | Kote Oberkante
Gelände-005 | 0.1 | 25.0951 | 1.30952 | 0 | 0.066
Gelände-005 | 0.1 | 22.875 | 1.125 | 0 | 0.066
Gelände-006 | 0.6 | 171.6 | 51.48 | -0.6 | -0.6

# IfcSlab: Geschossdecke Typ 01 256 (8)
Classification: Geschossdecke Holzbalken (BIM Base by Evolut)
03_Bausystem - Tragende Funktion: In Abklärung; Feuerwiderstand: In Abklärung; Luftschall: In Abklärung; Trittschall: In Abklärung; U-Wert: In Abklärung; Umbau-Status: Neubau; Mehrschichtiger Aufbau: Grobspanplatte-OSB; Balken Konstruktion ungedämmt; Balken Konstruktion gedämmt; Grobspanplatte-OSB
05_Bauablauf - Bau-Nr.: In Abklärung; Bauablauf Etappe: In Abklärung; Bauablauf Verbauungsort: In Abklärung; Bauablauf Start Ausführung: In Abklärung; Bauablauf Ende Ausführung: In Abklärung
01_Leistungen und Kosten - Gebäude: In Abklärung; Elementpreis - CHF: 0; BKP: 214 - Montagebau in Holz; eBKP-H_Nr: C04.01; eBKP-H_Beschrieb: Geschossdecke
Holzbau - Holzbau Kapselung: In Abklärung; Holzbau Sonderelement: In Abklärung
Bekleidung - Bekleidung Gipserarbeiten: In Abklärung; Bekleidung Malerarbeiten: In Abklärung; Bekleidung Putz: In Abklärung; Bekleidung Farbe: RAL / NCS
00_Datenstruktur - BIM Base Version: 4.0.0; Kundenergänzungen Version: v01; CAD Werkzeug Typ: Decke; Klassifizierung: Geschossdecke Holzbalken; Klassifizierung Level 0: Decke; Modellierungsrichtlinien: https://evolutbaugmbh.sharepoint.com/:b:/s/External/EciBgBMJMZlDgYCafV5wNokBvCJq9PUJAyVGz7O3vsjVrg?e=aLjLN9; Übersicht BIM Base: https://evolutbaugmbh.sharepoint.com/:b:/s/External/EfS4mJ9nZQpOhASXp0n2kW4B0K7N-vHKx-_6Crp5CxEFeg?e=Qu0M5d; Verbesserungsvorschläge BIM Base: https://forms.office.com/e/pcFhFfi5DW; Anleitung Mengen: https://evolutbaugmbh.sharepoint.com/:b:/s/External/ETgyOLO3JxJEqg9rbaRMLVEBHuWIRtkoMiJN1fISDr-3lw?e=E0LTiQ; Anleitung Eigenschaften: https://evolutbaugmbh.sharepoint.com/:b:/s/External/EQedjNXQkc1Btaftc01yAPUBtND9QzXFSH3-7sie6PGFww?e=wP4uf3; Release Notes: https://evolutbaugmbh.sharepoint.com/:b:/s/External/Eb41lwlDI71MhUVvor2V2mUBSaI-0tQK5U9oJAWxpCINuw?e=NtK3j6
02_Mengen - Stärke - m: 0.256
Name | In | Fläche brutto - m2 | Volumen netto - m3 | Kote Unterkante | Kote Oberkante
Deckennr.-073 | EG | 366.342 | 93.7672 | 3.144 | 3.4
Deckennr.-073 | EG | 30.7896 | 7.88214 | 3.144 | 3.4
Deckennr.-073 | 1.OG | 391.377 | 100.176 | 6.044 | 6.3
Deckennr.-073 | 1.OG | 54.6976 | 14.0026 | 6.044 | 6.3
Deckennr.-073 | 2.OG | 30.7896 | 7.88214 | 8.944 | 9.2
Deckennr.-073 | 2.OG | 367.155 | 93.9917 | 8.944 | 9.2
Deckennr.-073 | Attika | 83.0816 | 21.2689 | 11.844 | 12.1
Deckennr.-073 | Attika | 42.8355 | 10.9659 | 11.844 | 12.1

# IfcSlab: Geschossdecke Typ 02 180 (2)
Material: Brettschichtholz BSH
Holzbau - Holzbau Sonderelement: In Abklärung
03_Bausystem - Tragende Funktion: In Abklärung; Feuerwiderstand: In Abklärung; Trittschall: In Abklärung; Umbau-Status: Neubau; Mehrschichtiger Aufbau: Brettschichtholz BSH
01_Leistungen und Kosten - Gebäude: In Abklärung; Elementpreis - CHF: 0; BKP: 214 - Montagebau in Holz
Bekleidung - Bekleidung Malerarbeiten: In Abklärung
05_Bauablauf - Bau-Nr.: In Abklärung; Bauablauf Etappe: In Abklärung; Bauablauf Verbauungsort: In Abklärung; Bauablauf Start Ausführung: In Abklärung; Bauablauf Ende Ausführung: In Abklärung
02_Mengen - Stärke - m: 0.18
00_Datenstruktur - BIM Base Version: 4.0.0; Kundenergänzungen Version: v01; CAD Werkzeug Typ: Decke; Klassifizierung Level 0: Decke; Modellierungsrichtlinien: https://evolutbaugmbh.sharepoint.com/:b:/s/External/EciBgBMJMZlDgYCafV5wNokBvCJq9PUJAyVGz7O3vsjVrg?e=aLjLN9; Übersicht BIM Base: https://evolutbaugmbh.sharepoint.com/:b:/s/External/EfS4mJ9nZQpOhASXp0n2kW4B0K7N-vHKx-_6Crp5CxEFeg?e=Qu0M5d; Verbesserungsvorschläge BIM Base: https://forms.office.com/e/pcFhFfi5DW; Anleitung Mengen: https://evolutbaugmbh.sharepoint.com/:b:/s/External/ETgyOLO3JxJEqg9rbaRMLVEBHuWIRtkoMiJN1fISDr-3lw?e=E0LTiQ; Anleitung Eigenschaften: https://evolutbaugmbh.sharepoint.com/:b:/s/External/EQedjNXQkc1Btaftc01yAPUBtND9QzXFSH3-7sie6PGFww?e=wP4uf3; Release Notes: https://evolutbaugmbh.sharepoint.com/:b:/s/External/Eb41lwlDI71MhUVvor2V2mUBSaI-0tQK5U9oJAWxpCINuw?e=NtK3j6
Name | In | Classification | eBKP-H_Nr | eBKP-H_Beschrieb | Fläche brutto - m2 | Volumen netto - m3 | Kote Unterkante | Kote Oberkante | Klassifizierung
Deckennr.-073 | EG | Geschossdecke Massivholz (BIM Base by Evolut) | C04.01 | Geschossdecke | 49.787 | 7.97125 | 3.22 | 3.4 | Geschossdecke Massivholz | Holzbau - Holzbau Kapselung: In Abklärung; 03_Bausystem - Luftschall: In Abklärung; U-Wert: In Abklärung; Bekleidung - Bekleidung Gipserarbeiten: In Abklärung; Bekleidung Putz: In Abklärung; Bekleidung Farbe: RAL / NCS
Deckennr.-073 | 2.OG | Balkon Massivholz (BIM Base by Evolut) | C04.08 | Aussen liegende Konstruktion, Vordach | 51.632 | 9.29376 | 9.02 | 9.2 | Balkon Massivholz

# IfcSlab: Geschossdecke Typ 03 250 (8)
Classification: Geschossdecke Ortbeton (BIM Base by Evolut); Material: Beton bewehrt
01_Leistungen und Kosten - Gebäude: In Abklärung; Elementpreis - CHF: 0; BKP: 211 - Baumeisterarbeiten; eBKP-H_Nr: C04.01; eBKP-H_Beschrieb: Geschossdecke
05_Bauablauf - Bau-Nr.: In Abklärung; Bauablauf Etappe: In Abklärung; Bauablauf Verbauungsort: In Abklärung; Bauablauf Start Ausführung: In Abklärung; Bauablauf Ende Ausführung: In Abklärung
Massivbau Ortbeton - Ortbeton Druckfestigkeitsklasse: In Abklärung; Ortbeton Expositionsklasse: In Abklärung; Ortbeton Grösstkorn - mm: Dmax 32; Ortbeton Chloridgehaltsklasse: Cl 0.10; Ortbeton Konsistenzklasse: C3; Ortbeton Recyclingbeton: In Abklärung; Ortbeton Oberflächenausführung: In Abklärung; Ortbeton Oberflächenklasse - BOK: In Abklärung; Ortbeton Schalungstyp: In Abklärung; Ortbeton Dreikantleisten - mm: In Abklärung; Ortbeton Bew. Überdeckung oben - mm: In Abklärung; Ortbeton Bew. Überdeckung unten - mm: In Abklärung; Ortbeton Bew. Überdeckung aussen - mm: In Abklärung; Ortbeton Bew. Überdeckung innen - mm: In Abklärung; Ortbeton Bewehrungsgehalt - kg/m3: In Abklärung
Bekleidung - Bekleidung Gipserarbeiten: In Abklärung; Bekleidung Malerarbeiten: In Abklärung; Bekleidung Putz: In Abklärung; Bekleidung Farbe: RAL / NCS
03_Bausystem - Tragende Funktion: In Abklärung; Feuerwiderstand: In Abklärung; Luftschall: In Abklärung; Trittschall: In Abklärung; U-Wert: In Abklärung; Umbau-Status: Neubau; Mehrschichtiger Aufbau: Beton bewehrt
00_Datenstruktur - BIM Base Version: 4.0.0; Kundenergänzungen Version: v01; CAD Werkzeug Typ: Decke; Klassifizierung: Geschossdecke Ortbeton; Klassifizierung Level 0: Decke; Modellierungsrichtlinien: https://evolutbaugmbh.sharepoint.com/:b:/s/External/EciBgBMJMZlDgYCafV5wNokBvCJq9PUJAyVGz7O3vsjVrg?e=aLjLN9; Übersicht BIM Base: https://evolutbaugmbh.sharepoint.com/:b:/s/External/EfS4mJ9nZQpOhASXp0n2kW4B0K7N-vHKx-_6Crp5CxEFeg?e=Qu0M5d; Verbesserungsvorschläge BIM Base: https://forms.office.com/e/pcFhFfi5DW; Anleitung Mengen: https://evolutbaugmbh.sharepoint.com/:b:/s/External/ETgyOLO3JxJEqg9rbaRMLVEBHuWIRtkoMiJN1fISDr-3lw?e=E0LTiQ; Anleitung Eigenschaften: https://evolutbaugmbh.sharepoint.com/:b:/s/External/EQedjNXQkc1Btaftc01yAPUBtND9QzXFSH3-7sie6PGFww?e=wP4uf3; Release Notes: https://evolutbaugmbh.sharepoint.com/:b:/s/External/Eb41lwlDI71MhUVvor2V2mUBSaI-0tQK5U9oJAWxpCINuw?e=NtK3j6
02_Mengen - Stärke - m: 0.25
Name | In | Fläche brutto - m2 | Volumen netto - m3 | Kote Unterkante | Kote Oberkante
2 x Deckennr.-073 | EG | 52.488 | 13.122 | 2.65 | 2.9
Deckennr.-073 | EG | 58.5095 | 14.6274 | 2.65 | 2.9
Deckennr.-073 | EG | 60.5904 | 15.1416 | 2.65 | 2.9
Deckennr.-073 | 1.OG | 270.774 | 67.6936 | 5.55 | 5.8
Deckennr.-073 | 1.OG | 63.9472 | 15.9868 | 5.7 | 5.95
Deckennr.-073 | 2.OG | 5.1425 | 1.28563 | 9.1 | 9.35
Deckennr.-073 | 2.OG | 322.664 | 80.6659 | 8.45 | 8.7

# IfcSlab: Geschossdecke Typ 04 260 (2)
Classification: Geschossdecke Ortbeton (BIM Base by Evolut)
01_Leistungen und Kosten - Gebäude: In Abklärung; Elementpreis - CHF: 0; BKP: 211 - Baumeisterarbeiten; eBKP-H_Nr: C04.01; eBKP-H_Beschrieb: Geschossdecke
03_Bausystem - Tragende Funktion: In Abklärung; Feuerwiderstand: In Abklärung; Luftschall: In Abklärung; Trittschall: In Abklärung; U-Wert: In Abklärung; Umbau-Status: Neubau; Mehrschichtiger Aufbau: Beton bewehrt; Kalkzementputz Aussen
05_Bauablauf - Bau-Nr.: In Abklärung; Bauablauf Etappe: In Abklärung; Bauablauf Verbauungsort: In Abklärung; Bauablauf Start Ausführung: In Abklärung; Bauablauf Ende Ausführung: In Abklärung
Bekleidung - Bekleidung Gipserarbeiten: In Abklärung; Bekleidung Malerarbeiten: In Abklärung; Bekleidung Putz: In Abklärung; Bekleidung Farbe: RAL / NCS
02_Mengen - Stärke - m: 0.26
Massivbau Ortbeton - Ortbeton Druckfestigkeitsklasse: In Abklärung; Ortbeton Expositionsklasse: In Abklärung; Ortbeton Grösstkorn - mm: Dmax 32; Ortbeton Chloridgehaltsklasse: Cl 0.10; Ortbeton Konsistenzklasse: C3; Ortbeton Recyclingbeton: In Abklärung; Ortbeton Oberflächenausführung: In Abklärung; Ortbeton Oberflächenklasse - BOK: In Abklärung; Ortbeton Schalungstyp: In Abklärung; Ortbeton Dreikantleisten - mm: In Abklärung; Ortbeton Bew. Überdeckung oben - mm: In Abklärung; Ortbeton Bew. Überdeckung unten - mm: In Abklärung; Ortbeton Bew. Überdeckung aussen - mm: In Abklärung; Ortbeton Bew. Überdeckung innen - mm: In Abklärung; Ortbeton Bewehrungsgehalt - kg/m3: In Abklärung
00_Datenstruktur - BIM Base Version: 4.0.0; Kundenergänzungen Version: v01; CAD Werkzeug Typ: Decke; Klassifizierung: Geschossdecke Ortbeton; Klassifizierung Level 0: Decke; Modellierungsrichtlinien: https://evolutbaugmbh.sharepoint.com/:b:/s/External/EciBgBMJMZlDgYCafV5wNokBvCJq9PUJAyVGz7O3vsjVrg?e=aLjLN9; Übersicht BIM Base: https://evolutbaugmbh.sharepoint.com/:b:/s/External/EfS4mJ9nZQpOhASXp0n2kW4B0K7N-vHKx-_6Crp5CxEFeg?e=Qu0M5d; Verbesserungsvorschläge BIM Base: https://forms.office.com/e/pcFhFfi5DW; Anleitung Mengen: https://evolutbaugmbh.sharepoint.com/:b:/s/External/ETgyOLO3JxJEqg9rbaRMLVEBHuWIRtkoMiJN1fISDr-3lw?e=E0LTiQ; Anleitung Eigenschaften: https://evolutbaugmbh.sharepoint.com/:b:/s/External/EQedjNXQkc1Btaftc01yAPUBtND9QzXFSH3-7sie6PGFww?e=wP4uf3; Release Notes: https://evolutbaugmbh.sharepoint.com/:b:/s/External/Eb41lwlDI71MhUVvor2V2mUBSaI-0tQK5U9oJAWxpCINuw?e=NtK3j6
Name | In | Fläche brutto - m2 | Volumen netto - m3 | Kote Unterkante | Kote Oberkante
Deckennr.-073 | UG | 17.104 | 4.41824 | -0.26 | 0
Deckennr.-073 | EG | 52.488 | 13.6253 | 2.64 | 2.9

# IfcSlab: Geschossdecke Typ 05 251, Deckennr.-073
In: EG
Classification: Geschossdecke Ortbeton (BIM Base by Evolut)
01_Leistungen und Kosten - Gebäude: In Abklärung; Elementpreis - CHF: 0; BKP: 211 - Baumeisterarbeiten; eBKP-H_Nr: C04.01; eBKP-H_Beschrieb: Geschossdecke
05_Bauablauf - Bau-Nr.: In Abklärung; Bauablauf Etappe: In Abklärung; Bauablauf Verbauungsort: In Abklärung; Bauablauf Start Ausführung: In Abklärung; Bauablauf Ende Ausführung: In Abklärung
Bekleidung - Bekleidung Gipserarbeiten: In Abklärung; Bekleidung Malerarbeiten: In Abklärung; Bekleidung Putz: In Abklärung; Bekleidung Farbe: RAL / NCS
02_Mengen - Stärke - m: 0.251; Fläche brutto - m2: 52.488; Volumen netto - m3: 13.1723; Kote Unterkante: 2.649; Kote Oberkante: 2.9
00_Datenstruktur - BIM Base Version: 4.0.0; Kundenergänzungen Version: v01; CAD Werkzeug Typ: Decke; Klassifizierung: Geschossdecke Ortbeton; Klassifizierung Level 0: Decke; Modellierungsrichtlinien: https://evolutbaugmbh.sharepoint.com/:b:/s/External/EciBgBMJMZlDgYCafV5wNokBvCJq9PUJAyVGz7O3vsjVrg?e=aLjLN9; Übersicht BIM Base: https://evolutbaugmbh.sharepoint.com/:b:/s/External/EfS4mJ9nZQpOhASXp0n2kW4B0K7N-vHKx-_6Crp5CxEFeg?e=Qu0M5d; Verbesserungsvorschläge BIM Base: https://forms.office.com/e/pcFhFfi5DW; Anleitung Mengen: https://evolutbaugmbh.sharepoint.com/:b:/s/External/ETgyOLO3JxJEqg9rbaRMLVEBHuWIRtkoMiJN1fISDr-3lw?e=E0LTiQ; Anleitung Eigenschaften: https://evolutbaugmbh.sharepoint.com/:b:/s/External/EQedjNXQkc1Btaftc01yAPUBtND9QzXFSH3-7sie6PGFww?e=wP4uf3; Release Notes: https://evolutbaugmbh.sharepoint.com/:b:/s/External/Eb41lwlDI71MhUVvor2V2mUBSaI-0tQK5U9oJAWxpCINuw?e=NtK3j6
03_Bausystem - Tragende Funktion: In Abklärung; Feuerwiderstand: In Abklärung; Luftschall: In Abklärung; Trittschall: In Abklärung; U-Wert: In Abklärung; Umbau-Status: Neubau; Mehrschichtiger Aufbau: Beton bewehrt; Anstrich Innen
Massivbau Ortbeton - Ortbeton Druckfestigkeitsklasse: In Abklärung; Ortbeton Expositionsklasse: In Abklärung; Ortbeton Grösstkorn - mm: Dmax 32; Ortbeton Chloridgehaltsklasse: Cl 0.10; Ortbeton Konsistenzklasse: C3; Ortbeton Recyclingbeton: In Abklärung; Ortbeton Oberflächenausführung: In Abklärung; Ortbeton Oberflächenklasse - BOK: In Abklärung; Ortbeton Schalungstyp: In Abklärung; Ortbeton Dreikantleisten - mm: In Abklärung; Ortbeton Bew. Überdeckung oben - mm: In Abklärung; Ortbeton Bew. Überdeckung unten - mm: In Abklärung; Ortbeton Bew. Überdeckung aussen - mm: In Abklärung; Ortbeton Bew. Überdeckung innen - mm: In Abklärung; Ortbeton Bewehrungsgehalt - kg/m3: In Abklärung

# IfcSlab: Geschossdecke Typ 06 310, Deckennr.-073
In: UG
Classification: Geschossdecke Ortbeton (BIM Base by Evolut)
Bekleidung - Bekleidung Gipserarbeiten: In Abklärung; Bekleidung Malerarbeiten: In Abklärung; Bekleidung Putz: In Abklärung; Bekleidung Farbe: RAL / NCS
Massivbau Ortbeton - Ortbeton Druckfestigkeitsklasse: In Abklärung; Ortbeton Expositionsklasse: In Abklärung; Ortbeton Grösstkorn - mm: Dmax 32; Ortbeton Chloridgehaltsklasse: Cl 0.10; Ortbeton Konsistenzklasse: C3; Ortbeton Recyclingbeton: In Abklärung; Ortbeton Oberflächenausführung: In Abklärung; Ortbeton Oberflächenklasse - BOK: In Abklärung; Ortbeton Schalungstyp: In Abklärung; Ortbeton Dreikantleisten - mm: In Abklärung; Ortbeton Bew. Überdeckung oben - mm: In Abklärung; Ortbeton Bew. Überdeckung unten - mm: In Abklärung; Ortbeton Bew. Überdeckung aussen - mm: In Abklärung; Ortbeton Bew. Überdeckung innen - mm: In Abklärung; Ortbeton Bewehrungsgehalt - kg/m3: In Abklärung
03_Bausystem - Tragende Funktion: In Abklärung; Feuerwiderstand: In Abklärung; Luftschall: In Abklärung; Trittschall: In Abklärung; U-Wert: In Abklärung; Umbau-Status: Neubau; Mehrschichtiger Aufbau: Beton bewehrt; Kalkzementputz Aussen
05_Bauablauf - Bau-Nr.: In Abklärung; Bauablauf Etappe: In Abklärung; Bauablauf Verbauungsort: In Abklärung; Bauablauf Start Ausführung: In Abklärung; Bauablauf Ende Ausführung: In Abklärung
01_Leistungen und Kosten - Gebäude: In Abklärung; Elementpreis - CHF: 0; BKP: 211 - Baumeisterarbeiten; eBKP-H_Nr: C04.01; eBKP-H_Beschrieb: Geschossdecke
02_Mengen - Stärke - m: 0.31; Fläche brutto - m2: 3.752; Volumen netto - m3: 1.08632; Kote Unterkante: -0.09; Kote Oberkante: 0.22
00_Datenstruktur - BIM Base Version: 4.0.0; Kundenergänzungen Version: v01; CAD Werkzeug Typ: Decke; Klassifizierung: Geschossdecke Ortbeton; Klassifizierung Level 0: Decke; Modellierungsrichtlinien: https://evolutbaugmbh.sharepoint.com/:b:/s/External/EciBgBMJMZlDgYCafV5wNokBvCJq9PUJAyVGz7O3vsjVrg?e=aLjLN9; Übersicht BIM Base: https://evolutbaugmbh.sharepoint.com/:b:/s/External/EfS4mJ9nZQpOhASXp0n2kW4B0K7N-vHKx-_6Crp5CxEFeg?e=Qu0M5d; Verbesserungsvorschläge BIM Base: https://forms.office.com/e/pcFhFfi5DW; Anleitung Mengen: https://evolutbaugmbh.sharepoint.com/:b:/s/External/ETgyOLO3JxJEqg9rbaRMLVEBHuWIRtkoMiJN1fISDr-3lw?e=E0LTiQ; Anleitung Eigenschaften: https://evolutbaugmbh.sharepoint.com/:b:/s/External/EQedjNXQkc1Btaftc01yAPUBtND9QzXFSH3-7sie6PGFww?e=wP4uf3; Release Notes: https://evolutbaugmbh.sharepoint.com/:b:/s/External/Eb41lwlDI71MhUVvor2V2mUBSaI-0tQK5U9oJAWxpCINuw?e=NtK3j6

# IfcSlab: Geschossdecke Typ 07 410, Dach-011
In: UG
Classification: Geschossdecke Ortbeton (BIM Base by Evolut)
01_Leistungen und Kosten - Gebäude: In Abklärung; Elementpreis - CHF: 0; BKP: 211 - Baumeisterarbeiten; eBKP-H_Nr: C04.01; eBKP-H_Beschrieb: Geschossdecke
03_Bausystem - Tragende Funktion: In Abklärung; Feuerwiderstand: In Abklärung; Luftschall: In Abklärung; Trittschall: In Abklärung; U-Wert: In Abklärung; Umbau-Status: Neubau; Mehrschichtiger Aufbau: Beton bewehrt; Kalkzementputz Aussen
05_Bauablauf - Bau-Nr.: In Abklärung; Bauablauf Etappe: In Abklärung; Bauablauf Verbauungsort: In Abklärung; Bauablauf Start Ausführung: In Abklärung; Bauablauf Ende Ausführung: In Abklärung
Bekleidung - Bekleidung Gipserarbeiten: In Abklärung; Bekleidung Malerarbeiten: In Abklärung; Bekleidung Putz: In Abklärung; Bekleidung Farbe: RAL / NCS
02_Mengen - Stärke - m: 0.41; Fläche brutto - m2: 29.7123; Volumen netto - m3: 12.1821; Kote Unterkante: -0.741; Kote Oberkante: -0.331
00_Datenstruktur - BIM Base Version: 4.0.0; Kundenergänzungen Version: v01; CAD Werkzeug Typ: Dach; Klassifizierung: Geschossdecke Ortbeton; Klassifizierung Level 0: Decke; Modellierungsrichtlinien: https://evolutbaugmbh.sharepoint.com/:b:/s/External/EciBgBMJMZlDgYCafV5wNokBvCJq9PUJAyVGz7O3vsjVrg?e=aLjLN9; Übersicht BIM Base: https://evolutbaugmbh.sharepoint.com/:b:/s/External/EfS4mJ9nZQpOhASXp0n2kW4B0K7N-vHKx-_6Crp5CxEFeg?e=Qu0M5d; Verbesserungsvorschläge BIM Base: https://forms.office.com/e/pcFhFfi5DW; Anleitung Mengen: https://evolutbaugmbh.sharepoint.com/:b:/s/External/ETgyOLO3JxJEqg9rbaRMLVEBHuWIRtkoMiJN1fISDr-3lw?e=E0LTiQ; Anleitung Eigenschaften: https://evolutbaugmbh.sharepoint.com/:b:/s/External/EQedjNXQkc1Btaftc01yAPUBtND9QzXFSH3-7sie6PGFww?e=wP4uf3; Release Notes: https://evolutbaugmbh.sharepoint.com/:b:/s/External/Eb41lwlDI71MhUVvor2V2mUBSaI-0tQK5U9oJAWxpCINuw?e=NtK3j6
Massivbau Ortbeton - Ortbeton Druckfestigkeitsklasse: In Abklärung; Ortbeton Expositionsklasse: In Abklärung; Ortbeton Grösstkorn - mm: Dmax 32; Ortbeton Chloridgehaltsklasse: Cl 0.10; Ortbeton Konsistenzklasse: C3; Ortbeton Recyclingbeton: In Abklärung; Ortbeton Oberflächenausführung: In Abklärung; Ortbeton Oberflächenklasse - BOK: In Abklärung; Ortbeton Schalungstyp: In Abklärung; Ortbeton Dreikantleisten - mm: In Abklärung; Ortbeton Bew. Überdeckung oben - mm: In Abklärung; Ortbeton Bew. Überdeckung unten - mm: In Abklärung; Ortbeton Bew. Überdeckung aussen - mm: In Abklärung; Ortbeton Bew. Überdeckung innen - mm: In Abklärung; Ortbeton Bewehrungsgehalt - kg/m3: In Abklärung

# IfcSlab: Geschossdecke Typ 08 401 (2)
In: UG
Classification: Geschossdecke Ortbeton (BIM Base by Evolut)
01_Leistungen und Kosten - Gebäude: In Abklärung; Elementpreis - CHF: 0; BKP: 211 - Baumeisterarbeiten; eBKP-H_Nr: C04.01; eBKP-H_Beschrieb: Geschossdecke
05_Bauablauf - Bau-Nr.: In Abklärung; Bauablauf Etappe: In Abklärung; Bauablauf Verbauungsort: In Abklärung; Bauablauf Start Ausführung: In Abklärung; Bauablauf Ende Ausführung: In Abklärung
03_Bausystem - Tragende Funktion: In Abklärung; Feuerwiderstand: In Abklärung; Luftschall: In Abklärung; Trittschall: In Abklärung; U-Wert: In Abklärung; Umbau-Status: Neubau; Mehrschichtiger Aufbau: Beton bewehrt; Anstrich Innen
Massivbau Ortbeton - Ortbeton Druckfestigkeitsklasse: In Abklärung; Ortbeton Expositionsklasse: In Abklärung; Ortbeton Grösstkorn - mm: Dmax 32; Ortbeton Chloridgehaltsklasse: Cl 0.10; Ortbeton Konsistenzklasse: C3; Ortbeton Recyclingbeton: In Abklärung; Ortbeton Oberflächenausführung: In Abklärung; Ortbeton Oberflächenklasse - BOK: In Abklärung; Ortbeton Schalungstyp: In Abklärung; Ortbeton Dreikantleisten - mm: In Abklärung; Ortbeton Bew. Überdeckung oben - mm: In Abklärung; Ortbeton Bew. Überdeckung unten - mm: In Abklärung; Ortbeton Bew. Überdeckung aussen - mm: In Abklärung; Ortbeton Bew. Überdeckung innen - mm: In Abklärung; Ortbeton Bewehrungsgehalt - kg/m3: In Abklärung
00_Datenstruktur - BIM Base Version: 4.0.0; Kundenergänzungen Version: v01; Klassifizierung: Geschossdecke Ortbeton; Klassifizierung Level 0: Decke; Modellierungsrichtlinien: https://evolutbaugmbh.sharepoint.com/:b:/s/External/EciBgBMJMZlDgYCafV5wNokBvCJq9PUJAyVGz7O3vsjVrg?e=aLjLN9; Übersicht BIM Base: https://evolutbaugmbh.sharepoint.com/:b:/s/External/EfS4mJ9nZQpOhASXp0n2kW4B0K7N-vHKx-_6Crp5CxEFeg?e=Qu0M5d; Verbesserungsvorschläge BIM Base: https://forms.office.com/e/pcFhFfi5DW; Anleitung Mengen: https://evolutbaugmbh.sharepoint.com/:b:/s/External/ETgyOLO3JxJEqg9rbaRMLVEBHuWIRtkoMiJN1fISDr-3lw?e=E0LTiQ; Anleitung Eigenschaften: https://evolutbaugmbh.sharepoint.com/:b:/s/External/EQedjNXQkc1Btaftc01yAPUBtND9QzXFSH3-7sie6PGFww?e=wP4uf3; Release Notes: https://evolutbaugmbh.sharepoint.com/:b:/s/External/Eb41lwlDI71MhUVvor2V2mUBSaI-0tQK5U9oJAWxpCINuw?e=NtK3j6
02_Mengen - Stärke - m: 0.401
Bekleidung - Bekleidung Gipserarbeiten: In Abklärung; Bekleidung Malerarbeiten: In Abklärung; Bekleidung Putz: In Abklärung; Bekleidung Farbe: RAL / NCS
Name | CAD Werkzeug Typ | Fläche brutto - m2 | Volumen netto - m3 | Kote Unterkante | Kote Oberkante
Dach-011 | Dach | 29.7123 | 11.9147 | -0.836 | -0.435
Deckennr.-072 | Decke | 171.6 | 68.7961 | -1.001 | -0.6

# IfcSlab: Geschossdecke Typ 09 400 (4)
In: UG
Classification: Geschossdecke Ortbeton (BIM Base by Evolut); Material: Beton bewehrt
01_Leistungen und Kosten - Gebäude: In Abklärung; Elementpreis - CHF: 0; BKP: 211 - Baumeisterarbeiten; eBKP-H_Nr: C04.01; eBKP-H_Beschrieb: Geschossdecke
05_Bauablauf - Bau-Nr.: In Abklärung; Bauablauf Etappe: In Abklärung; Bauablauf Verbauungsort: In Abklärung; Bauablauf Start Ausführung: In Abklärung; Bauablauf Ende Ausführung: In Abklärung
Massivbau Ortbeton - Ortbeton Druckfestigkeitsklasse: In Abklärung; Ortbeton Expositionsklasse: In Abklärung; Ortbeton Grösstkorn - mm: Dmax 32; Ortbeton Chloridgehaltsklasse: Cl 0.10; Ortbeton Konsistenzklasse: C3; Ortbeton Recyclingbeton: In Abklärung; Ortbeton Oberflächenausführung: In Abklärung; Ortbeton Oberflächenklasse - BOK: In Abklärung; Ortbeton Schalungstyp: In Abklärung; Ortbeton Dreikantleisten - mm: In Abklärung; Ortbeton Bew. Überdeckung oben - mm: In Abklärung; Ortbeton Bew. Überdeckung unten - mm: In Abklärung; Ortbeton Bew. Überdeckung aussen - mm: In Abklärung; Ortbeton Bew. Überdeckung innen - mm: In Abklärung; Ortbeton Bewehrungsgehalt - kg/m3: In Abklärung
03_Bausystem - Tragende Funktion: In Abklärung; Feuerwiderstand: In Abklärung; Luftschall: In Abklärung; Trittschall: In Abklärung; U-Wert: In Abklärung; Umbau-Status: Neubau; Mehrschichtiger Aufbau: Beton bewehrt
Bekleidung - Bekleidung Gipserarbeiten: In Abklärung; Bekleidung Malerarbeiten: In Abklärung; Bekleidung Putz: In Abklärung; Bekleidung Farbe: RAL / NCS
02_Mengen - Stärke - m: 0.4
00_Datenstruktur - BIM Base Version: 4.0.0; Kundenergänzungen Version: v01; Klassifizierung: Geschossdecke Ortbeton; Klassifizierung Level 0: Decke; Modellierungsrichtlinien: https://evolutbaugmbh.sharepoint.com/:b:/s/External/EciBgBMJMZlDgYCafV5wNokBvCJq9PUJAyVGz7O3vsjVrg?e=aLjLN9; Übersicht BIM Base: https://evolutbaugmbh.sharepoint.com/:b:/s/External/EfS4mJ9nZQpOhASXp0n2kW4B0K7N-vHKx-_6Crp5CxEFeg?e=Qu0M5d; Verbesserungsvorschläge BIM Base: https://forms.office.com/e/pcFhFfi5DW; Anleitung Mengen: https://evolutbaugmbh.sharepoint.com/:b:/s/External/ETgyOLO3JxJEqg9rbaRMLVEBHuWIRtkoMiJN1fISDr-3lw?e=E0LTiQ; Anleitung Eigenschaften: https://evolutbaugmbh.sharepoint.com/:b:/s/External/EQedjNXQkc1Btaftc01yAPUBtND9QzXFSH3-7sie6PGFww?e=wP4uf3; Release Notes: https://evolutbaugmbh.sharepoint.com/:b:/s/External/Eb41lwlDI71MhUVvor2V2mUBSaI-0tQK5U9oJAWxpCINuw?e=NtK3j6
Name | Fläche brutto - m2 | Volumen netto - m3 | Kote Unterkante | Kote Oberkante | CAD Werkzeug Typ
Dach-011 | 29.7123 | 11.8849 | -0.627 | -0.227 | Dach
Dach-011 | 47.2344 | 18.8937 | -1 | -0.6 | Dach
Dach-011 | 35.2999 | 14.12 | -0.524 | -0.124 | Dach
Deckennr.-072 | 660.901 | 264.361 | -0.4 | 0 | Decke

# IfcStair: Treppentyp (12)
Classification: Innentreppe Beton vorfabriziert (BIM Base by Evolut)
01_Leistungen und Kosten - Gebäude: In Abklärung; Elementpreis - CHF: 0; BKP: 211 - Baumeisterarbeiten; eBKP-H_Nr: C04.02; eBKP-H_Beschrieb: Innen liegende Treppe, Rampe
05_Bauablauf - Bau-Nr.: In Abklärung; Bauablauf Etappe: In Abklärung; Bauablauf Verbauungsort: In Abklärung; Bauablauf Start Ausführung: In Abklärung; Bauablauf Ende Ausführung: In Abklärung
03_Bausystem - Feuerwiderstand: In Abklärung; Trittschall: In Abklärung; Umbau-Status: Neubau
Massivbau Beton vorfabriziert - Beton vorfabriziert Druckfestigkeitsklasse: In Abklärung; Beton vorfabriziert Expositionsklasse: In Abklärung; Beton vorfabriziert Grösstkorn - mm: Dmax 32; Beton vorfabriziert Chloridgehaltsklasse: Cl 0.10; Beton vorfabriziert Konsistenzklasse: C3; Beton vorfabriziert Recyclingbeton: In Abklärung; Beton vorfabriziert Betonsorte zusammengestellt: In Abklärung; Beton vorfabriziert Oberflächenklasse - BOK: In Abklärung; Beton vorfabriziert Schalungstyp: In Abklärung; Beton vorfabriziert Dreikantleisten - mm: In Abklärung; Beton vorfabriziert Bew. Überdeckung oben - mm: In Abklärung; Beton vorfabriziert Bew. Überdeckung unten - mm: In Abklärung; Beton vorfabriziert Bew. Überdeckung aussen - mm: In Abklärung; Beton vorfabriziert Bew. Überdeckung innen - mm: In Abklärung; Beton vorfabriziert Bewehrungsgehalt - kg/m3: In Abklärung
00_Datenstruktur - BIM Base Version: 4.0.0; Kundenergänzungen Version: v01; CAD Werkzeug Typ: Treppe; Klassifizierung: Innentreppe Beton vorfabriziert; Klassifizierung Level 0: Treppe; Modellierungsrichtlinien: https://evolutbaugmbh.sharepoint.com/:b:/s/External/EciBgBMJMZlDgYCafV5wNokBvCJq9PUJAyVGz7O3vsjVrg?e=aLjLN9; Übersicht BIM Base: https://evolutbaugmbh.sharepoint.com/:b:/s/External/EfS4mJ9nZQpOhASXp0n2kW4B0K7N-vHKx-_6Crp5CxEFeg?e=Qu0M5d; Verbesserungsvorschläge BIM Base: https://forms.office.com/e/pcFhFfi5DW; Anleitung Mengen: https://evolutbaugmbh.sharepoint.com/:b:/s/External/ETgyOLO3JxJEqg9rbaRMLVEBHuWIRtkoMiJN1fISDr-3lw?e=E0LTiQ; Anleitung Eigenschaften: https://evolutbaugmbh.sharepoint.com/:b:/s/External/EQedjNXQkc1Btaftc01yAPUBtND9QzXFSH3-7sie6PGFww?e=wP4uf3; Release Notes: https://evolutbaugmbh.sharepoint.com/:b:/s/External/Eb41lwlDI71MhUVvor2V2mUBSaI-0tQK5U9oJAWxpCINuw?e=NtK3j6
Bekleidung - Bekleidung Gipserarbeiten: In Abklärung; Bekleidung Malerarbeiten: In Abklärung; Bekleidung Farbe: RAL / NCS
Name | In | Mehrschichtiger Aufbau | Breite - m | Höhe - m | Länge brutto - m | Fläche brutto - m2 | Volumen netto - m3 | Kote Unterkante | Kote Oberkante
Treppe-001 | UG | Beton bewehrt | 1.6 | 0.380514 | 0.808457 | 1.29353 | 0.246104 | -3.301 | -2.92
Treppe-001 | UG | Beton bewehrt | 1.6 | 3.04 | 4.5 | 7.2 | 2.38537 | -3.1 | -0.06
Treppe-001 | EG | Fehlt | 1.6 | 0.66 | 1.35 | 2.16 | 0.550208 | -0.237 | 0.423
Treppe-001 | EG | Beton bewehrt | 1.6 | 2.43 | 4.5 | 7.2 | 2.22548 | 0.34 | 2.77
2 x Treppe-001 | EG | Beton bewehrt | 1.6 | 0.6 | 1 | 1.6 | 0.48 | -0.6 | 0
Treppe-001 | 1.OG | Fehlt | 1.6 | 0.52 | 1.10643 | 1.77029 | 0.460068 | 2.805 | 3.325
Treppe-001 | 1.OG | Beton bewehrt | 1.6 | 2.42 | 4.5 | 7.2 | 2.22167 | 3.25 | 5.67
Treppe-001 | 2.OG | Fehlt | 1.6 | 0.52 | 1.10643 | 1.77029 | 0.460068 | 5.705 | 6.225
Treppe-001 | 2.OG | Keramik; Beton bewehrt | 1.6 | 2.42 | 4.5 | 7.2 | 2.41856 | 6.13 | 8.55
Treppe-001 | Attika | Fehlt | 1.6 | 0.52 | 1.10643 | 1.77029 | 0.460068 | 8.605 | 9.125
Treppe-001 | Attika | Stahl; Vollholzwerkstoff | 0.8 | 2.75 | 4.55395 | 3.64316 | 0.317144 | 9.35 | 12.1

# IfcStair: Treppentyp 01 - Metall - Holz (3)
Classification: Aussentreppe Stahlbau (BIM Base by Evolut)
01_Leistungen und Kosten - Gebäude: In Abklärung; Elementpreis - CHF: 0; BKP: 213 - Montagebau in Stahl; eBKP-H_Nr: C04.06; eBKP-H_Beschrieb: Aussen liegende Treppe, Rampe
05_Bauablauf - Bau-Nr.: In Abklärung; Bauablauf Etappe: In Abklärung; Bauablauf Verbauungsort: In Abklärung; Bauablauf Start Ausführung: In Abklärung; Bauablauf Ende Ausführung: In Abklärung
03_Bausystem - Feuerwiderstand: In Abklärung; Trittschall: In Abklärung; Umbau-Status: Neubau; Mehrschichtiger Aufbau: Stahl; Massivholz
Stahlbau - Stahlbau Stahlgüte: In Abklärung; Stahlbau Oberflächenbehandlung: In Abklärung; Stahlbau Farbe: In Abklärung
Bekleidung - Bekleidung Malerarbeiten: In Abklärung; Bekleidung Farbe: RAL / NCS
02_Mengen - Höhe - m: 2.9
00_Datenstruktur - BIM Base Version: 4.0.0; Kundenergänzungen Version: v01; CAD Werkzeug Typ: Treppe; Klassifizierung: Aussentreppe Stahlbau; Klassifizierung Level 0: Treppe; Modellierungsrichtlinien: https://evolutbaugmbh.sharepoint.com/:b:/s/External/EciBgBMJMZlDgYCafV5wNokBvCJq9PUJAyVGz7O3vsjVrg?e=aLjLN9; Übersicht BIM Base: https://evolutbaugmbh.sharepoint.com/:b:/s/External/EfS4mJ9nZQpOhASXp0n2kW4B0K7N-vHKx-_6Crp5CxEFeg?e=Qu0M5d; Verbesserungsvorschläge BIM Base: https://forms.office.com/e/pcFhFfi5DW; Anleitung Mengen: https://evolutbaugmbh.sharepoint.com/:b:/s/External/ETgyOLO3JxJEqg9rbaRMLVEBHuWIRtkoMiJN1fISDr-3lw?e=E0LTiQ; Anleitung Eigenschaften: https://evolutbaugmbh.sharepoint.com/:b:/s/External/EQedjNXQkc1Btaftc01yAPUBtND9QzXFSH3-7sie6PGFww?e=wP4uf3; Release Notes: https://evolutbaugmbh.sharepoint.com/:b:/s/External/Eb41lwlDI71MhUVvor2V2mUBSaI-0tQK5U9oJAWxpCINuw?e=NtK3j6
Name | In | Breite - m | Länge brutto - m | Fläche brutto - m2 | Volumen netto - m3 | Kote Unterkante | Kote Oberkante
Treppe-001 | EG | 1.2 | 4.97604 | 5.97125 | 0.433155 | 0 | 2.9
Treppe-001 | 1.OG | 0.8 | 4.25 | 3.4 | 0.303353 | 2.9 | 5.8
Treppe-001 | 2.OG | 0.8 | 4.25 | 3.4 | 0.303353 | 5.8 | 8.7

# IfcTransportElement: Fahrstuhl 27, Möbel-019
In: UG
Classification: Aufzug (BIM Base by Evolut)
01_Leistungen und Kosten - Gebäude: In Abklärung; BKP: 261 - Aufzüge; Elementpreis - CHF: 0; eBKP-H_Nr: D12.01; eBKP-H_Beschrieb: Aufzug
05_Bauablauf - Bau-Nr.: In Abklärung; Bauablauf Etappe: In Abklärung; Bauablauf Verbauungsort: In Abklärung; Bauablauf Start Ausführung: In Abklärung; Bauablauf Ende Ausführung: In Abklärung
02_Mengen - Breite - m: 3.2; Höhe - m: 6.5; Länge brutto - m: 3.275; Kote Unterkante: -3.338; Kote Oberkante: 3.162
03_Bausystem - Umbau-Status: Neubau
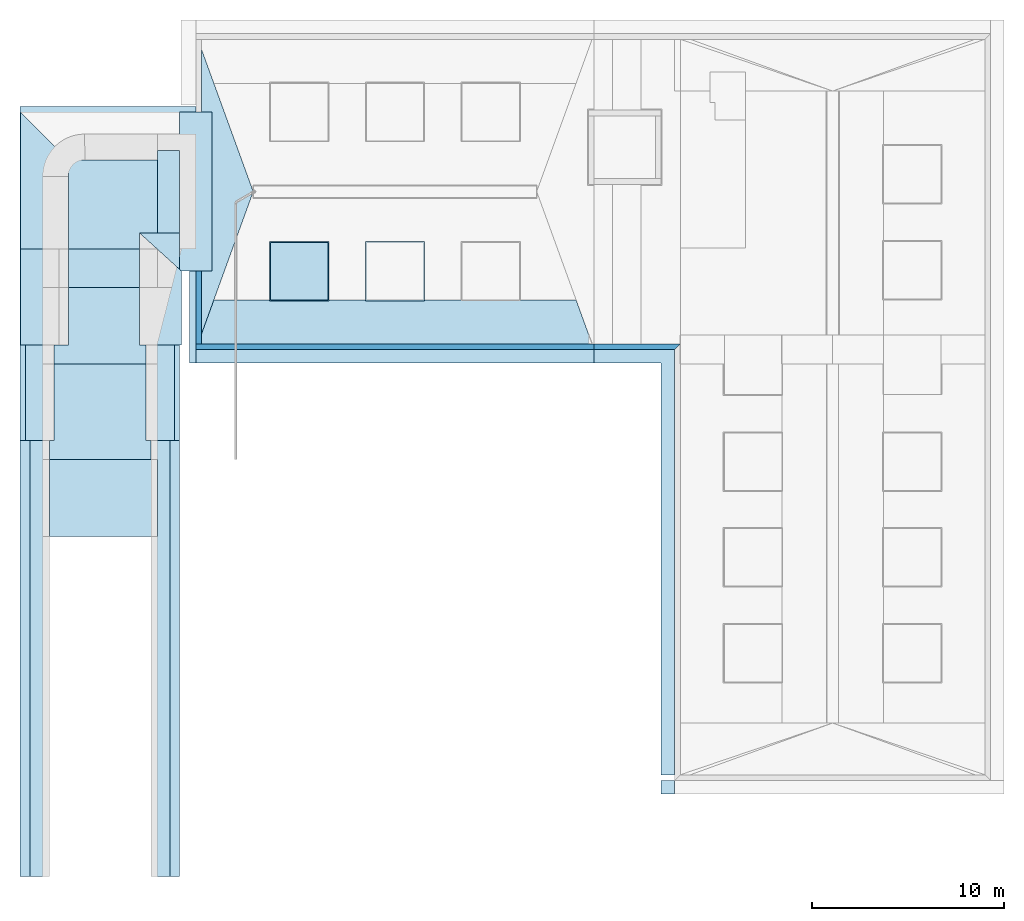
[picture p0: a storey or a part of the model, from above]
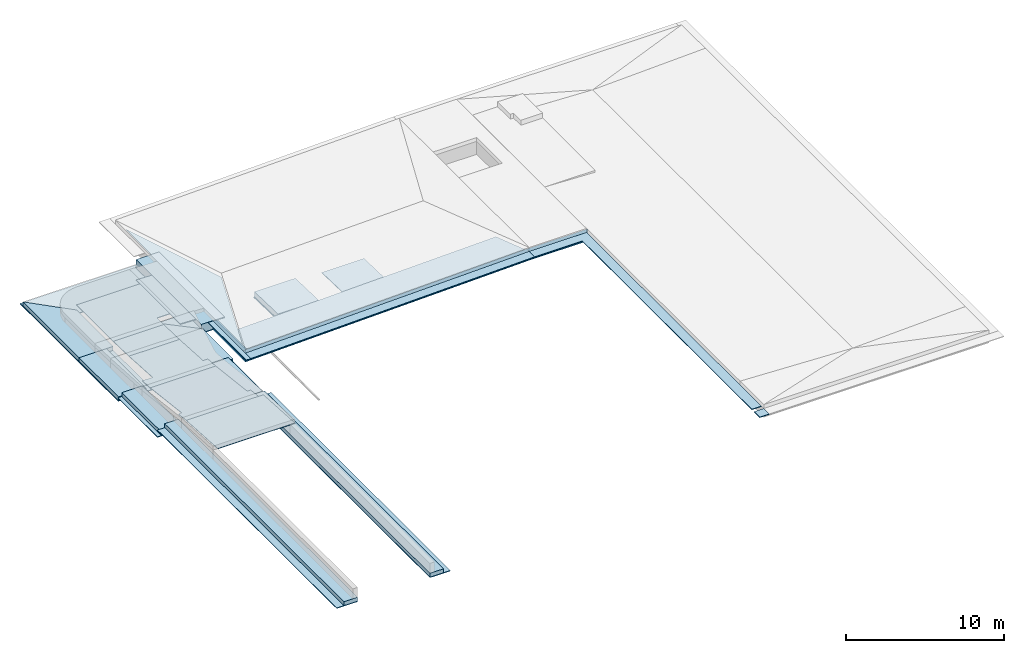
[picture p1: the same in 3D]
Properties of the parts of a building model (IFC4), part 6 of 8

# IfcTransportElement: Fahrstuhl 27, Möbel-019
00_Datenstruktur - BIM Base Version: 4.0.0; Kundenergänzungen Version: v01; CAD Werkzeug Typ: Objekt; Klassifizierung: Aufzug; Klassifizierung Level 0: Transportmittel; Modellierungsrichtlinien: https://evolutbaugmbh.sharepoint.com/:b:/s/External/EciBgBMJMZlDgYCafV5wNokBvCJq9PUJAyVGz7O3vsjVrg?e=aLjLN9; Übersicht BIM Base: https://evolutbaugmbh.sharepoint.com/:b:/s/External/EfS4mJ9nZQpOhASXp0n2kW4B0K7N-vHKx-_6Crp5CxEFeg?e=Qu0M5d; Verbesserungsvorschläge BIM Base: https://forms.office.com/e/pcFhFfi5DW; Anleitung Mengen: https://evolutbaugmbh.sharepoint.com/:b:/s/External/ETgyOLO3JxJEqg9rbaRMLVEBHuWIRtkoMiJN1fISDr-3lw?e=E0LTiQ; Anleitung Eigenschaften: https://evolutbaugmbh.sharepoint.com/:b:/s/External/EQedjNXQkc1Btaftc01yAPUBtND9QzXFSH3-7sie6PGFww?e=wP4uf3; Release Notes: https://evolutbaugmbh.sharepoint.com/:b:/s/External/Eb41lwlDI71MhUVvor2V2mUBSaI-0tQK5U9oJAWxpCINuw?e=NtK3j6

# IfcWall: Aussenwand Typ 01 318 (42)
01_Leistungen und Kosten - Gebäude: In Abklärung; Elementpreis - CHF: 0; BKP: 214 - Montagebau in Holz
03_Bausystem - Tragende Funktion: In Abklärung; Feuerwiderstand: In Abklärung; Luftschall: In Abklärung; U-Wert: In Abklärung; Umbau-Status: Neubau; Mehrschichtiger Aufbau: Grobspanplatte-OSB; Ständer Konstruktion gedämmt; Gipsfaserplatte GFP; Gipsfaserplatte GFP; Verputz Innen
05_Bauablauf - Bau-Nr.: In Abklärung; Bauablauf Etappe: In Abklärung; Bauablauf Verbauungsort: In Abklärung; Bauablauf Start Ausführung: In Abklärung; Bauablauf Ende Ausführung: In Abklärung
Bekleidung - Bekleidung Gipserarbeiten: In Abklärung; Bekleidung Malerarbeiten: In Abklärung; Bekleidung Putz: In Abklärung; Bekleidung Farbe: RAL / NCS
Holzbau - Holzbau Anschluss Massivbau vertikal: In Abklärung; Holzbau Anschluss Massivbau horizontal: In Abklärung; Holzbau Durchstanzung: In Abklärung; Holzbau Kapselung: In Abklärung; Holzbau Sonderelement: In Abklärung
00_Datenstruktur - BIM Base Version: 4.0.0; Kundenergänzungen Version: v01; CAD Werkzeug Typ: Wand; Klassifizierung Level 0: Wand; Modellierungsrichtlinien: https://evolutbaugmbh.sharepoint.com/:b:/s/External/EciBgBMJMZlDgYCafV5wNokBvCJq9PUJAyVGz7O3vsjVrg?e=aLjLN9; Übersicht BIM Base: https://evolutbaugmbh.sharepoint.com/:b:/s/External/EfS4mJ9nZQpOhASXp0n2kW4B0K7N-vHKx-_6Crp5CxEFeg?e=Qu0M5d; Verbesserungsvorschläge BIM Base: https://forms.office.com/e/pcFhFfi5DW; Anleitung Mengen: https://evolutbaugmbh.sharepoint.com/:b:/s/External/ETgyOLO3JxJEqg9rbaRMLVEBHuWIRtkoMiJN1fISDr-3lw?e=E0LTiQ; Anleitung Eigenschaften: https://evolutbaugmbh.sharepoint.com/:b:/s/External/EQedjNXQkc1Btaftc01yAPUBtND9QzXFSH3-7sie6PGFww?e=wP4uf3; Release Notes: https://evolutbaugmbh.sharepoint.com/:b:/s/External/Eb41lwlDI71MhUVvor2V2mUBSaI-0tQK5U9oJAWxpCINuw?e=NtK3j6
02_Mengen - Stärke - m: 0.318
Name | In | Classification | eBKP-H_Nr | eBKP-H_Beschrieb | Klassifizierung | Höhe - m | Länge brutto - m | Fläche brutto - m2 | Volumen netto - m3 | Kote Unterkante | Kote Oberkante
Wand-014 | EG | Aussenwand Holzständer (BIM Base by Evolut) | C02.01 | Aussenwandkonstruktion | Aussenwand Holzständer | 2.9 | 12.429 | 42.2586 | 8.23795 | 0 | 3.4
AW01 | EG | Aussenwand Holzständer (BIM Base by Evolut) | C02.01 | Aussenwandkonstruktion | Aussenwand Holzständer | 3.4 | 29.358 | 99.8172 | 20.0151 | 0 | 3.4
Wand-014 | EG | Aussenwand Holzständer (BIM Base by Evolut) | C02.01 | Aussenwandkonstruktion | Aussenwand Holzständer | 3.4 | 19.4289 | 66.0583 | 15.2425 | 0 | 3.4
Wand-014 | 1.OG | Aussenwand Holzständer (BIM Base by Evolut) | C02.01 | Aussenwandkonstruktion | Aussenwand Holzständer | 3.4 | 12.429 | 42.2586 | 10.5333 | 2.9 | 6.3
Wand-014 | EG | Aussenwand Holzständer (BIM Base by Evolut) | C02.01 | Aussenwandkonstruktion | Aussenwand Holzständer | 3.4 | 14.858 | 50.5172 | 10.9348 | 0 | 3.4
Wand-014 | 1.OG | Aussenwand Holzständer (BIM Base by Evolut) | C02.01 | Aussenwandkonstruktion | Aussenwand Holzständer | 2.9 | 29.358 | 85.1382 | 18.8593 | 3.4 | 6.3
Wand-014 | 1.OG | Aussenwand Holzständer (BIM Base by Evolut) | C02.01 | Aussenwandkonstruktion | Aussenwand Holzständer | 3.08 | 3.929 | 13.0808 | 3.66619 | 3.22 | 6.3
Wand-014 | 1.OG | Aussenwand Holzständer (BIM Base by Evolut) | C02.01 | Aussenwandkonstruktion | Aussenwand Holzständer | 2.9 | 1.046 | 3.9556 | 0.733801 | 3.4 | 6.3
Wand-014 | 1.OG | Aussenwand Holzständer (BIM Base by Evolut) | C02.01 | Aussenwandkonstruktion | Aussenwand Holzständer | 3.08 | 3.929 | 13.0808 | 3.7639 | 3.22 | 6.3
Wand-014 | 1.OG | Aussenwand Holzständer (BIM Base by Evolut) | C02.01 | Aussenwandkonstruktion | Aussenwand Holzständer | 2.9 | 5.00001 | 14.5 | 4.42431 | 3.4 | 6.3
Wand-014 | 1.OG | Aussenwand Holzständer (BIM Base by Evolut) | C02.01 | Aussenwandkonstruktion | Aussenwand Holzständer | 2.9 | 1.046 | 3.9556 | 0.92966 | 3.4 | 6.3
Wand-014 | 1.OG | Aussenwand Holzständer (BIM Base by Evolut) | C02.01 | Aussenwandkonstruktion | Aussenwand Holzständer | 2.9 | 14.4289 | 41.8438 | 9.57233 | 3.4 | 6.3
Wand-014 | 1.OG | Aussenwand Holzständer (BIM Base by Evolut) | C02.01 | Aussenwandkonstruktion | Aussenwand Holzständer | 3.08 | 12.766 | 39.3193 | 8.11466 | 3.22 | 6.3
Wand-014 | 2.OG | Aussenwand Holzständer (BIM Base by Evolut) | C02.01 | Aussenwandkonstruktion | Aussenwand Holzständer | 2.9 | 12.429 | 36.0441 | 8.99077 | 6.3 | 9.2
Wand-014 | 2.OG | Aussenwand Holzständer (BIM Base by Evolut) | C02.01 | Aussenwandkonstruktion | Aussenwand Holzständer | 2.9 | 29.358 | 85.1382 | 18.634 | 6.3 | 9.2
Wand-014 | 2.OG | Aussenwand Holzständer (BIM Base by Evolut) | C02.01 | Aussenwandkonstruktion | Aussenwand Holzständer | 2.9 | 4.99011 | 15.3703 | 4.4319 | 6.3 | 9.2
Wand-014 | 2.OG | Aussenwand Holzständer (BIM Base by Evolut) | C02.01 | Aussenwandkonstruktion | Aussenwand Holzständer | 2.9 | 14.4289 | 41.8438 | 9.62259 | 6.3 | 9.2
Wand-014 | 2.OG | Aussenwand Holzständer (BIM Base by Evolut) | C02.01 | Aussenwandkonstruktion | Aussenwand Holzständer | 2.9 | 14.858 | 43.0882 | 9.28325 | 6.3 | 9.2
Wand-014 | Attika | Innenwand Holzständer (BIM Base by Evolut) | C02.02 | Innenwandkonstruktion | Innenwand Holzständer | 3.70393 | 4.652 | 13.3907 | 4.23435 | 12.1 | 15.804
Wand-014 | Attika | Innenwand Holzständer (BIM Base by Evolut) | C02.02 | Innenwandkonstruktion | Innenwand Holzständer | 3.70393 | 7.121 | 17.1475 | 5.42945 | 12.1 | 15.804
Wand-014 | Attika | Innenwand Holzständer (BIM Base by Evolut) | C02.02 | Innenwandkonstruktion | Innenwand Holzständer | 2.9 | 11.773 | 34.1417 | 10.8394 | 9.2 | 12.1
Wand-014 | Attika | Aussenwand Holzständer (BIM Base by Evolut) | C02.01 | Aussenwandkonstruktion | Aussenwand Holzständer | 2.9 | 29.358 | 85.1382 | 19.3777 | 9.2 | 12.1
Wand-014 | Attika | Aussenwand Holzständer (BIM Base by Evolut) | C02.01 | Aussenwandkonstruktion | Aussenwand Holzständer | 2.9 | 12.389 | 35.9281 | 9.35741 | 9.2 | 12.1
Wand-014 | Attika | Aussenwand Holzständer (BIM Base by Evolut) | C02.01 | Aussenwandkonstruktion | Aussenwand Holzständer | 2.9 | 2.469 | 8.0823 | 2.27321 | 9.2 | 12.1
Wand-014 | Attika | Aussenwand Holzständer (BIM Base by Evolut) | C02.01 | Aussenwandkonstruktion | Aussenwand Holzständer | 2.9 | 9.969 | 29.8323 | 8.20832 | 9.2 | 12.1
Wand-014 | Attika | Aussenwand Holzständer (BIM Base by Evolut) | C02.01 | Aussenwandkonstruktion | Aussenwand Holzständer | 2.9 | 14.858 | 43.0882 | 9.27978 | 9.2 | 12.1
Wand-014 | Attika | Aussenwand Holzständer (BIM Base by Evolut) | C02.01 | Aussenwandkonstruktion | Aussenwand Holzständer | 2.9 | 14.4289 | 41.8438 | 9.78861 | 9.2 | 12.1
Wand-014 | Attika | Aussenwand Holzständer (BIM Base by Evolut) | C02.01 | Aussenwandkonstruktion | Aussenwand Holzständer | 2.9 | 4.96011 | 14.3843 | 4.5199 | 9.2 | 12.1
2 x Wand-014 | Dachaufsicht | Aussenwand Holzständer (BIM Base by Evolut) | C02.01 | Aussenwandkonstruktion | Aussenwand Holzständer | 2.17975 | 5.5499 | 5.59068 | 1.63614 | 13.495 | 15.675
Wand-014 | Dachaufsicht | Aussenwand Holzständer (BIM Base by Evolut) | C02.01 | Aussenwandkonstruktion | Aussenwand Holzständer | 3.96466 | 7.429 | 19.4097 | 6.13081 | 12.1 | 16.065
Wand-014 | Dachaufsicht | Aussenwand Holzständer (BIM Base by Evolut) | C02.01 | Aussenwandkonstruktion | Aussenwand Holzständer | 1.26728 | 29.358 | 37.2047 | 11.6031 | 12.1 | 13.367
Wand-014 | Dachaufsicht | Aussenwand Holzständer (BIM Base by Evolut) | C02.01 | Aussenwandkonstruktion | Aussenwand Holzständer | 2.16592 | 2.469 | 4.9108 | 1.27321 | 12.1 | 14.266
Wand-014 | Dachaufsicht | Aussenwand Holzständer (BIM Base by Evolut) | C02.01 | Aussenwandkonstruktion | Aussenwand Holzständer | 3.96466 | 4.96 | 15.1876 | 4.6252 | 12.1 | 16.065
Wand-014 | Dachaufsicht | Aussenwand Holzständer (BIM Base by Evolut) | C02.01 | Aussenwandkonstruktion | Aussenwand Holzständer | 2.17975 | 5.5499 | 5.59068 | 1.75061 | 13.495 | 15.675
Wand-014 | Dachaufsicht | Aussenwand Holzständer (BIM Base by Evolut) | C02.01 | Aussenwandkonstruktion | Aussenwand Holzständer | 1.68398 | 8.008 | 13.3687 | 2.39307 | 13.495 | 15.179
Wand-014 | Dachaufsicht | Aussenwand Holzständer (BIM Base by Evolut) | C02.01 | Aussenwandkonstruktion | Aussenwand Holzständer | 1.23535 | 19.389 | 23.9522 | 7.56317 | 12.1 | 13.335
Wand-014 | Dachaufsicht | Aussenwand Holzständer (BIM Base by Evolut) | C02.01 | Aussenwandkonstruktion | Aussenwand Holzständer | 3.96466 | 7.429 | 19.4097 | 2.79192 | 12.1 | 16.065
Wand-014 | Dachaufsicht | Aussenwand Holzständer (BIM Base by Evolut) | C02.01 | Aussenwandkonstruktion | Aussenwand Holzständer | 1.65954 | 8.008 | 14.0339 | 1.3892 | 13.495 | 15.277
Wand-014 | Dachaufsicht | Aussenwand Holzständer (BIM Base by Evolut) | C02.01 | Aussenwandkonstruktion | Aussenwand Holzständer | 3.96466 | 7.429 | 19.4097 | 2.64809 | 12.1 | 16.065
Wand-014 | Dachaufsicht | Aussenwand Holzständer (BIM Base by Evolut) | C02.01 | Aussenwandkonstruktion | Aussenwand Holzständer | 2.17975 | 5.5499 | 5.59068 | 1.24721 | 13.495 | 15.675
Wand-014 | Dachaufsicht | Aussenwand Holzständer (BIM Base by Evolut) | C02.01 | Aussenwandkonstruktion | Aussenwand Holzständer | 2.16592 | 9.969 | 22.2808 | 7.01458 | 12.1 | 14.266

# IfcWall: Aussenwand Typ 02 150 (3)
In: Attika
Classification: Aussenwand Holzständer (BIM Base by Evolut)
02_Mengen - Höhe - m: 1; Stärke - m: 0.15; Kote Unterkante: 9.2; Kote Oberkante: 10.2
00_Datenstruktur - BIM Base Version: 4.0.0; Kundenergänzungen Version: v01; CAD Werkzeug Typ: Wand; Klassifizierung: Aussenwand Holzständer; Klassifizierung Level 0: Wand; Modellierungsrichtlinien: https://evolutbaugmbh.sharepoint.com/:b:/s/External/EciBgBMJMZlDgYCafV5wNokBvCJq9PUJAyVGz7O3vsjVrg?e=aLjLN9; Übersicht BIM Base: https://evolutbaugmbh.sharepoint.com/:b:/s/External/EfS4mJ9nZQpOhASXp0n2kW4B0K7N-vHKx-_6Crp5CxEFeg?e=Qu0M5d; Verbesserungsvorschläge BIM Base: https://forms.office.com/e/pcFhFfi5DW; Anleitung Mengen: https://evolutbaugmbh.sharepoint.com/:b:/s/External/ETgyOLO3JxJEqg9rbaRMLVEBHuWIRtkoMiJN1fISDr-3lw?e=E0LTiQ; Anleitung Eigenschaften: https://evolutbaugmbh.sharepoint.com/:b:/s/External/EQedjNXQkc1Btaftc01yAPUBtND9QzXFSH3-7sie6PGFww?e=wP4uf3; Release Notes: https://evolutbaugmbh.sharepoint.com/:b:/s/External/Eb41lwlDI71MhUVvor2V2mUBSaI-0tQK5U9oJAWxpCINuw?e=NtK3j6
Bekleidung - Bekleidung Gipserarbeiten: In Abklärung; Bekleidung Malerarbeiten: In Abklärung; Bekleidung Putz: In Abklärung; Bekleidung Farbe: RAL / NCS
Holzbau - Holzbau Anschluss Massivbau vertikal: In Abklärung; Holzbau Anschluss Massivbau horizontal: In Abklärung; Holzbau Durchstanzung: In Abklärung; Holzbau Kapselung: In Abklärung; Holzbau Sonderelement: In Abklärung
01_Leistungen und Kosten - Gebäude: In Abklärung; Elementpreis - CHF: 0; BKP: 214 - Montagebau in Holz; eBKP-H_Nr: C02.01; eBKP-H_Beschrieb: Aussenwandkonstruktion
03_Bausystem - Tragende Funktion: In Abklärung; Feuerwiderstand: In Abklärung; Luftschall: In Abklärung; U-Wert: In Abklärung; Umbau-Status: Neubau; Mehrschichtiger Aufbau: Grobspanplatte-OSB; Ständer Konstruktion gedämmt; Grobspanplatte-OSB
05_Bauablauf - Bau-Nr.: In Abklärung; Bauablauf Etappe: In Abklärung; Bauablauf Verbauungsort: In Abklärung; Bauablauf Start Ausführung: In Abklärung; Bauablauf Ende Ausführung: In Abklärung
Name | Länge brutto - m = Fläche brutto - m2 | Volumen netto - m3
Wand-017 | 12.508 | 1.8762
2 x Wand-017 | 3.7999 | 0.569985

# IfcWall: Aussenwand Typ 03 301 (11)
In: UG
01_Leistungen und Kosten - Gebäude: In Abklärung; Elementpreis - CHF: 0; BKP: 211 - Baumeisterarbeiten
03_Bausystem - Tragende Funktion: In Abklärung; Umbau-Status: Neubau; Mehrschichtiger Aufbau: Beton bewehrt; Anstrich Innen
05_Bauablauf - Bau-Nr.: In Abklärung; Bauablauf Etappe: In Abklärung; Bauablauf Verbauungsort: In Abklärung; Bauablauf Start Ausführung: In Abklärung; Bauablauf Ende Ausführung: In Abklärung
Massivbau Ortbeton - Ortbeton Druckfestigkeitsklasse: In Abklärung; Ortbeton Expositionsklasse: In Abklärung; Ortbeton Grösstkorn - mm: Dmax 32; Ortbeton Chloridgehaltsklasse: Cl 0.10; Ortbeton Konsistenzklasse: C3; Ortbeton Recyclingbeton: In Abklärung; Ortbeton Oberflächenausführung: In Abklärung; Ortbeton Oberflächenklasse - BOK: In Abklärung; Ortbeton Schalungstyp: In Abklärung; Ortbeton Dreikantleisten - mm: In Abklärung; Ortbeton Bew. Überdeckung oben - mm: In Abklärung; Ortbeton Bew. Überdeckung unten - mm: In Abklärung; Ortbeton Bew. Überdeckung aussen - mm: In Abklärung; Ortbeton Bew. Überdeckung innen - mm: In Abklärung; Ortbeton Bewehrungsgehalt - kg/m3: In Abklärung
Bekleidung - Bekleidung Malerarbeiten: In Abklärung
02_Mengen - Stärke - m: 0.301
00_Datenstruktur - BIM Base Version: 4.0.0; Kundenergänzungen Version: v01; CAD Werkzeug Typ: Wand; Klassifizierung Level 0: Wand; Modellierungsrichtlinien: https://evolutbaugmbh.sharepoint.com/:b:/s/External/EciBgBMJMZlDgYCafV5wNokBvCJq9PUJAyVGz7O3vsjVrg?e=aLjLN9; Übersicht BIM Base: https://evolutbaugmbh.sharepoint.com/:b:/s/External/EfS4mJ9nZQpOhASXp0n2kW4B0K7N-vHKx-_6Crp5CxEFeg?e=Qu0M5d; Verbesserungsvorschläge BIM Base: https://forms.office.com/e/pcFhFfi5DW; Anleitung Mengen: https://evolutbaugmbh.sharepoint.com/:b:/s/External/ETgyOLO3JxJEqg9rbaRMLVEBHuWIRtkoMiJN1fISDr-3lw?e=E0LTiQ; Anleitung Eigenschaften: https://evolutbaugmbh.sharepoint.com/:b:/s/External/EQedjNXQkc1Btaftc01yAPUBtND9QzXFSH3-7sie6PGFww?e=wP4uf3; Release Notes: https://evolutbaugmbh.sharepoint.com/:b:/s/External/Eb41lwlDI71MhUVvor2V2mUBSaI-0tQK5U9oJAWxpCINuw?e=NtK3j6
Name | Classification | eBKP-H_Nr | eBKP-H_Beschrieb | Feuerwiderstand = Luftschall = U-Wert = Bekleidung Gipserarbeiten = Bekleidung Putz | Bekleidung Farbe | Höhe - m | Länge brutto - m | Fläche brutto - m2 | Volumen netto - m3 | Schalungsfläche Wände brutto - m2 | Kote Unterkante | Kote Oberkante | Klassifizierung
Wand-013 | Aussenwand Ortbeton (BIM Base by Evolut) | C02.01 | Aussenwandkonstruktion | In Abklärung | RAL / NCS | 2.9 | 4.501 | 13.0529 | 3.92805 | 26.1058 | -3.3 | -0.4 | Aussenwand Ortbeton
Wand-013 | Aussenwand Ortbeton (BIM Base by Evolut) | C02.01 | Aussenwandkonstruktion | In Abklärung | RAL / NCS | 2.9 | 20.7 | 60.03 | 18.0682 | 120.06 | -3.3 | -0.4 | Aussenwand Ortbeton
Wand-013 | Aussenwand Ortbeton (BIM Base by Evolut) | C02.01 | Aussenwandkonstruktion | In Abklärung | RAL / NCS | 2.9 | 38.699 | 113.1 | 33.5194 | 226.2 | -3.3 | -0.4 | Aussenwand Ortbeton
Wand-013 | Aussenwand Ortbeton (BIM Base by Evolut) | C02.01 | Aussenwandkonstruktion | In Abklärung | RAL / NCS | 3.49983 | 20.8 | 60.6007 | 17.9522 | 121.023 | -3.9 | 0 | Aussenwand Ortbeton
Wand-013 | Aussenwand Ortbeton (BIM Base by Evolut) | C02.01 | Aussenwandkonstruktion | In Abklärung | RAL / NCS | 2.9 | 4.95 | 15.2279 | 4.32086 | 30.4558 | -3.9 | -1 | Aussenwand Ortbeton
Wand-013 | Aussenwand Ortbeton (BIM Base by Evolut) | C02.01 | Aussenwandkonstruktion | In Abklärung | RAL / NCS | 2.9 | 4.95 | 14.355 | 4.31998 | 28.71 | -3.9 | -1 | Aussenwand Ortbeton
Wand-013 | Aussenwand Ortbeton (BIM Base by Evolut) | C02.01 | Aussenwandkonstruktion | In Abklärung | RAL / NCS | 2.9 | 22.5 | 66.1229 | 19.6403 | 132.246 | -3.3 | -0.4 | Aussenwand Ortbeton
Wand-013 | Aussenwand Ortbeton (BIM Base by Evolut) | C02.01 | Aussenwandkonstruktion | In Abklärung | RAL / NCS | 2.9 | 16.5 | 47.85 | 14.1401 | 95.7 | -3.3 | -0.4 | Aussenwand Ortbeton
Wand-013 | Aussenwand Ortbeton (BIM Base by Evolut) | C02.01 | Aussenwandkonstruktion | In Abklärung | RAL / NCS | 2.9 | 20.8 | 54.3624 | 16.0744 | 108.546 | -3.9 | -1 | Aussenwand Ortbeton
Wand-013 | Wand Umgebung Ortbeton (BIM Base by Evolut) | I02.03 | Frei stehende Wand |  |  | 4.1745 | 1.03377 | 4.54859 | 1.03886 |  | -4.175 | 0.366 | Wand Umgebung Ortbeton
Wand-014 | Wand Umgebung Ortbeton (BIM Base by Evolut) | I02.03 | Frei stehende Wand |  |  | 3.76493 | 27 | 102.816 | 30.5513 |  | -3.765 | 0 | Wand Umgebung Ortbeton

# IfcWall: Aussenwand Typ 04 300 (13)
01_Leistungen und Kosten - Gebäude: In Abklärung; Elementpreis - CHF: 0; BKP: 211 - Baumeisterarbeiten
00_Datenstruktur - BIM Base Version: 4.0.0; Kundenergänzungen Version: v01; CAD Werkzeug Typ: Wand; Klassifizierung Level 0: Wand; Modellierungsrichtlinien: https://evolutbaugmbh.sharepoint.com/:b:/s/External/EciBgBMJMZlDgYCafV5wNokBvCJq9PUJAyVGz7O3vsjVrg?e=aLjLN9; Übersicht BIM Base: https://evolutbaugmbh.sharepoint.com/:b:/s/External/EfS4mJ9nZQpOhASXp0n2kW4B0K7N-vHKx-_6Crp5CxEFeg?e=Qu0M5d; Verbesserungsvorschläge BIM Base: https://forms.office.com/e/pcFhFfi5DW; Anleitung Mengen: https://evolutbaugmbh.sharepoint.com/:b:/s/External/ETgyOLO3JxJEqg9rbaRMLVEBHuWIRtkoMiJN1fISDr-3lw?e=E0LTiQ; Anleitung Eigenschaften: https://evolutbaugmbh.sharepoint.com/:b:/s/External/EQedjNXQkc1Btaftc01yAPUBtND9QzXFSH3-7sie6PGFww?e=wP4uf3; Release Notes: https://evolutbaugmbh.sharepoint.com/:b:/s/External/Eb41lwlDI71MhUVvor2V2mUBSaI-0tQK5U9oJAWxpCINuw?e=NtK3j6
02_Mengen - Stärke - m: 0.3
Bekleidung - Bekleidung Malerarbeiten: In Abklärung
Massivbau Ortbeton - Ortbeton Druckfestigkeitsklasse: In Abklärung; Ortbeton Expositionsklasse: In Abklärung; Ortbeton Grösstkorn - mm: Dmax 32; Ortbeton Chloridgehaltsklasse: Cl 0.10; Ortbeton Konsistenzklasse: C3; Ortbeton Recyclingbeton: In Abklärung; Ortbeton Oberflächenausführung: In Abklärung; Ortbeton Oberflächenklasse - BOK: In Abklärung; Ortbeton Schalungstyp: In Abklärung; Ortbeton Dreikantleisten - mm: In Abklärung; Ortbeton Bew. Überdeckung oben - mm: In Abklärung; Ortbeton Bew. Überdeckung unten - mm: In Abklärung; Ortbeton Bew. Überdeckung aussen - mm: In Abklärung; Ortbeton Bew. Überdeckung innen - mm: In Abklärung; Ortbeton Bewehrungsgehalt - kg/m3: In Abklärung
03_Bausystem - Tragende Funktion: In Abklärung; Umbau-Status: Neubau; Mehrschichtiger Aufbau: Beton bewehrt; Sichtbeton
05_Bauablauf - Bau-Nr.: In Abklärung; Bauablauf Etappe: In Abklärung; Bauablauf Verbauungsort: In Abklärung; Bauablauf Start Ausführung: In Abklärung; Bauablauf Ende Ausführung: In Abklärung
Name | In | Classification | eBKP-H_Nr | eBKP-H_Beschrieb | Klassifizierung | Höhe - m | Länge brutto - m | Fläche brutto - m2 | Volumen netto - m3 | Schalungsfläche Wände brutto - m2 | Kote Unterkante | Kote Oberkante | Bekleidung Gipserarbeiten = Bekleidung Putz = Feuerwiderstand = Luftschall = U-Wert | Bekleidung Farbe
Wand-013 | UG | Aussenwand Ortbeton (BIM Base by Evolut) | C02.01 | Aussenwandkonstruktion | Aussenwand Ortbeton | 4.54 | 3.92699 | 17.8346 | 5.02934 | 33.529 | -4.54 | 0 | In Abklärung | RAL / NCS
Wand-013 | UG | Wand Umgebung Ortbeton (BIM Base by Evolut) | I02.03 | Frei stehende Wand | Wand Umgebung Ortbeton | 4.30031 | 5.03769 | 26.7165 | 5.87332 |  | -4.3 | 0
Wand-014 | UG | Wand Umgebung Ortbeton (BIM Base by Evolut) | I02.03 | Frei stehende Wand | Wand Umgebung Ortbeton | 3.76493 | 17.7502 | 66.8283 | 19.725 |  | -3.765 | 0
Wand-014 | UG | Aussenwand Ortbeton (BIM Base by Evolut) | C02.01 | Aussenwandkonstruktion | Aussenwand Ortbeton | 3.76493 | 14.75 | 55.5328 | 16.6598 | 111.066 | -3.765 | 0 | In Abklärung | RAL / NCS
Wand-014 | UG | Aussenwand Ortbeton (BIM Base by Evolut) | C02.01 | Aussenwandkonstruktion | Aussenwand Ortbeton | 1.86498 | 8 | 14.9198 | 4.47595 | 29.8397 | -3.765 | -1.9 | In Abklärung | RAL / NCS
Wand-013 | UG | Wand Umgebung Ortbeton (BIM Base by Evolut) | I02.03 | Frei stehende Wand | Wand Umgebung Ortbeton | 4.54 | 5.12253 | 28.6478 | 7.15838 |  | -4.54 | 0
Wand-014 | UG | Aussenwand Ortbeton (BIM Base by Evolut) | C02.01 | Aussenwandkonstruktion | Aussenwand Ortbeton | 1.86498 | 4.9998 | 10.0724 | 2.82727 | 20.1448 | -3.765 | -1.9 | In Abklärung | RAL / NCS
Wand-013 | UG | Aussenwand Ortbeton (BIM Base by Evolut) | C02.01 | Aussenwandkonstruktion | Aussenwand Ortbeton | 4.54 | 8.8 | 39.952 | 11.9856 | 79.904 | -4.54 | 0 | In Abklärung | RAL / NCS
Wand-014 | EG | Aussenwand Ortbeton (BIM Base by Evolut) | C02.01 | Aussenwandkonstruktion | Aussenwand Ortbeton | 2.9 | 5.01 | 14.454 | 3.88572 | 28.908 | 0 | 2.9 | In Abklärung | RAL / NCS
Wand-013 | UG | Aussenwand Ortbeton (BIM Base by Evolut) | C02.01 | Aussenwandkonstruktion | Aussenwand Ortbeton | 4.30031 | 5 | 21.5015 | 6.45046 | 43.0031 | -4.3 | 0 | In Abklärung | RAL / NCS
Wand-014 | 1.OG | Aussenwand Ortbeton (BIM Base by Evolut) | C02.01 | Aussenwandkonstruktion | Aussenwand Ortbeton | 2.65 | 5.02 | 13.303 | 3.7365 | 26.606 | 2.9 | 5.55 | In Abklärung | RAL / NCS
Wand-014 | 2.OG | Aussenwand Ortbeton (BIM Base by Evolut) | C02.01 | Aussenwandkonstruktion | Aussenwand Ortbeton | 2.9 | 5.02 | 14.5115 | 4.05284 | 29.023 | 5.8 | 8.7 | In Abklärung | RAL / NCS
Wand-014 | Attika | Aussenwand Ortbeton (BIM Base by Evolut) | C02.01 | Aussenwandkonstruktion | Aussenwand Ortbeton | 3.4 | 5.01 | 17.15 | 5.09944 | 34.3 | 8.7 | 12.1 | In Abklärung | RAL / NCS

# IfcWall: Aussenwand Typ 05 300 (5)
In: EG
Classification: Aussenwand Ortbeton (BIM Base by Evolut); Material: Beton bewehrt
01_Leistungen und Kosten - Gebäude: In Abklärung; Elementpreis - CHF: 0; BKP: 211 - Baumeisterarbeiten; eBKP-H_Nr: C02.01; eBKP-H_Beschrieb: Aussenwandkonstruktion
05_Bauablauf - Bau-Nr.: In Abklärung; Bauablauf Etappe: In Abklärung; Bauablauf Verbauungsort: In Abklärung; Bauablauf Start Ausführung: In Abklärung; Bauablauf Ende Ausführung: In Abklärung
03_Bausystem - Tragende Funktion: In Abklärung; Feuerwiderstand: In Abklärung; Luftschall: In Abklärung; U-Wert: In Abklärung; Umbau-Status: Neubau; Mehrschichtiger Aufbau: Beton bewehrt
Massivbau Ortbeton - Ortbeton Druckfestigkeitsklasse: In Abklärung; Ortbeton Expositionsklasse: In Abklärung; Ortbeton Grösstkorn - mm: Dmax 32; Ortbeton Chloridgehaltsklasse: Cl 0.10; Ortbeton Konsistenzklasse: C3; Ortbeton Recyclingbeton: In Abklärung; Ortbeton Oberflächenausführung: In Abklärung; Ortbeton Oberflächenklasse - BOK: In Abklärung; Ortbeton Schalungstyp: In Abklärung; Ortbeton Dreikantleisten - mm: In Abklärung; Ortbeton Bew. Überdeckung oben - mm: In Abklärung; Ortbeton Bew. Überdeckung unten - mm: In Abklärung; Ortbeton Bew. Überdeckung aussen - mm: In Abklärung; Ortbeton Bew. Überdeckung innen - mm: In Abklärung; Ortbeton Bewehrungsgehalt - kg/m3: In Abklärung
Bekleidung - Bekleidung Gipserarbeiten: In Abklärung; Bekleidung Malerarbeiten: In Abklärung; Bekleidung Putz: In Abklärung; Bekleidung Farbe: RAL / NCS
02_Mengen - Stärke - m: 0.3; Kote Oberkante: 2.65
00_Datenstruktur - BIM Base Version: 4.0.0; Kundenergänzungen Version: v01; CAD Werkzeug Typ: Wand; Klassifizierung: Aussenwand Ortbeton; Klassifizierung Level 0: Wand; Modellierungsrichtlinien: https://evolutbaugmbh.sharepoint.com/:b:/s/External/EciBgBMJMZlDgYCafV5wNokBvCJq9PUJAyVGz7O3vsjVrg?e=aLjLN9; Übersicht BIM Base: https://evolutbaugmbh.sharepoint.com/:b:/s/External/EfS4mJ9nZQpOhASXp0n2kW4B0K7N-vHKx-_6Crp5CxEFeg?e=Qu0M5d; Verbesserungsvorschläge BIM Base: https://forms.office.com/e/pcFhFfi5DW; Anleitung Mengen: https://evolutbaugmbh.sharepoint.com/:b:/s/External/ETgyOLO3JxJEqg9rbaRMLVEBHuWIRtkoMiJN1fISDr-3lw?e=E0LTiQ; Anleitung Eigenschaften: https://evolutbaugmbh.sharepoint.com/:b:/s/External/EQedjNXQkc1Btaftc01yAPUBtND9QzXFSH3-7sie6PGFww?e=wP4uf3; Release Notes: https://evolutbaugmbh.sharepoint.com/:b:/s/External/Eb41lwlDI71MhUVvor2V2mUBSaI-0tQK5U9oJAWxpCINuw?e=NtK3j6
Name | Höhe - m | Länge brutto - m | Fläche brutto - m2 | Volumen netto - m3 | Schalungsfläche Wände brutto - m2 | Kote Unterkante
Wand-014 | 2.65 | 4 | 10.6 | 2.66705 | 21.2 | 0
Wand-014 | 3.25 | 18.29 | 59.4425 | 12.5291 | 118.885 | -0.6
Wand-014 | 2.65 | 24.79 | 65.7935 | 14.6969 | 131.587 | 0
Wand-014 | 2.65 | 8.84 | 23.426 | 4.22013 | 46.852 | 0
Wand-014 | 3.25 | 5.74 | 18.655 | 4.15677 | 37.31 | -0.6

# IfcWall: Aussenwand Typ 06 310 (13)
Classification: Aussenwand Ortbeton (BIM Base by Evolut)
01_Leistungen und Kosten - Gebäude: In Abklärung; Elementpreis - CHF: 0; BKP: 211 - Baumeisterarbeiten; eBKP-H_Nr: C02.01; eBKP-H_Beschrieb: Aussenwandkonstruktion
03_Bausystem - Tragende Funktion: In Abklärung; Feuerwiderstand: In Abklärung; Luftschall: In Abklärung; U-Wert: In Abklärung; Umbau-Status: Neubau; Mehrschichtiger Aufbau: Beton bewehrt; Kalkzementputz Aussen
Massivbau Ortbeton - Ortbeton Druckfestigkeitsklasse: In Abklärung; Ortbeton Expositionsklasse: In Abklärung; Ortbeton Grösstkorn - mm: Dmax 32; Ortbeton Chloridgehaltsklasse: Cl 0.10; Ortbeton Konsistenzklasse: C3; Ortbeton Recyclingbeton: In Abklärung; Ortbeton Oberflächenausführung: In Abklärung; Ortbeton Oberflächenklasse - BOK: In Abklärung; Ortbeton Schalungstyp: In Abklärung; Ortbeton Dreikantleisten - mm: In Abklärung; Ortbeton Bew. Überdeckung oben - mm: In Abklärung; Ortbeton Bew. Überdeckung unten - mm: In Abklärung; Ortbeton Bew. Überdeckung aussen - mm: In Abklärung; Ortbeton Bew. Überdeckung innen - mm: In Abklärung; Ortbeton Bewehrungsgehalt - kg/m3: In Abklärung
05_Bauablauf - Bau-Nr.: In Abklärung; Bauablauf Etappe: In Abklärung; Bauablauf Verbauungsort: In Abklärung; Bauablauf Start Ausführung: In Abklärung; Bauablauf Ende Ausführung: In Abklärung
Bekleidung - Bekleidung Gipserarbeiten: In Abklärung; Bekleidung Malerarbeiten: In Abklärung; Bekleidung Putz: In Abklärung; Bekleidung Farbe: RAL / NCS
02_Mengen - Stärke - m: 0.31
00_Datenstruktur - BIM Base Version: 4.0.0; Kundenergänzungen Version: v01; CAD Werkzeug Typ: Wand; Klassifizierung: Aussenwand Ortbeton; Klassifizierung Level 0: Wand; Modellierungsrichtlinien: https://evolutbaugmbh.sharepoint.com/:b:/s/External/EciBgBMJMZlDgYCafV5wNokBvCJq9PUJAyVGz7O3vsjVrg?e=aLjLN9; Übersicht BIM Base: https://evolutbaugmbh.sharepoint.com/:b:/s/External/EfS4mJ9nZQpOhASXp0n2kW4B0K7N-vHKx-_6Crp5CxEFeg?e=Qu0M5d; Verbesserungsvorschläge BIM Base: https://forms.office.com/e/pcFhFfi5DW; Anleitung Mengen: https://evolutbaugmbh.sharepoint.com/:b:/s/External/ETgyOLO3JxJEqg9rbaRMLVEBHuWIRtkoMiJN1fISDr-3lw?e=E0LTiQ; Anleitung Eigenschaften: https://evolutbaugmbh.sharepoint.com/:b:/s/External/EQedjNXQkc1Btaftc01yAPUBtND9QzXFSH3-7sie6PGFww?e=wP4uf3; Release Notes: https://evolutbaugmbh.sharepoint.com/:b:/s/External/Eb41lwlDI71MhUVvor2V2mUBSaI-0tQK5U9oJAWxpCINuw?e=NtK3j6
Name | In | Höhe - m | Länge brutto - m | Fläche brutto - m2 | Volumen netto - m3 | Schalungsfläche Wände brutto - m2 | Kote Unterkante | Kote Oberkante
Wand-014 | 1.OG | 2.65 | 3.99 | 11.395 | 2.7455 | 22.79 | 2.9 | 5.55
Wand-014 | 1.OG | 2.65 | 18.29 | 48.4685 | 9.54902 | 96.937 | 2.9 | 5.55
Wand-014 | 1.OG | 2.65 | 17.69 | 46.8785 | 10.3325 | 93.757 | 2.9 | 5.55
Wand-014 | 1.OG | 2.65 | 14.58 | 38.637 | 7.04141 | 77.274 | 2.9 | 5.55
Wand-014 | 1.OG | 2.8 | 7.091 | 19.8948 | 5.10789 | 39.7896 | 2.9 | 5.7
Wand-014 | 2.OG | 2.65 | 3.99 | 11.395 | 2.7455 | 22.79 | 5.8 | 8.45
Wand-014 | 2.OG | 2.65 | 18.29 | 48.4685 | 9.54902 | 96.937 | 5.8 | 8.45
Wand-014 | 2.OG | 2.65 | 24.781 | 65.6697 | 14.7429 | 131.339 | 5.8 | 8.45
Wand-014 | 2.OG | 2.65 | 14.58 | 38.637 | 7.04141 | 77.274 | 5.8 | 8.45
Wand-014 | Attika | 2.65 | 3.99 | 11.395 | 2.62031 | 22.79 | 8.7 | 11.35
Wand-014 | Attika | 2.65 | 15.29 | 40.5185 | 8.12952 | 81.037 | 8.7 | 11.35
Wand-014 | Attika | 2.65 | 21.781 | 57.7197 | 12.6468 | 115.439 | 8.7 | 11.35
Wand-014 | Attika | 2.65 | 11.58 | 30.687 | 5.74652 | 61.374 | 8.7 | 11.35

# IfcWall: Aussenwand Typ 07 - Brüstung 200 (16)
Classification: Aussenwand Ortbeton (BIM Base by Evolut); Material: Beton bewehrt
01_Leistungen und Kosten - Gebäude: In Abklärung; Elementpreis - CHF: 0; BKP: 211 - Baumeisterarbeiten; eBKP-H_Nr: C02.01; eBKP-H_Beschrieb: Aussenwandkonstruktion
03_Bausystem - Tragende Funktion: In Abklärung; Feuerwiderstand: In Abklärung; Luftschall: In Abklärung; U-Wert: In Abklärung; Umbau-Status: Neubau; Mehrschichtiger Aufbau: Beton bewehrt
Massivbau Ortbeton - Ortbeton Druckfestigkeitsklasse: In Abklärung; Ortbeton Expositionsklasse: In Abklärung; Ortbeton Grösstkorn - mm: Dmax 32; Ortbeton Chloridgehaltsklasse: Cl 0.10; Ortbeton Konsistenzklasse: C3; Ortbeton Recyclingbeton: In Abklärung; Ortbeton Oberflächenausführung: In Abklärung; Ortbeton Oberflächenklasse - BOK: In Abklärung; Ortbeton Schalungstyp: In Abklärung; Ortbeton Dreikantleisten - mm: In Abklärung; Ortbeton Bew. Überdeckung oben - mm: In Abklärung; Ortbeton Bew. Überdeckung unten - mm: In Abklärung; Ortbeton Bew. Überdeckung aussen - mm: In Abklärung; Ortbeton Bew. Überdeckung innen - mm: In Abklärung; Ortbeton Bewehrungsgehalt - kg/m3: In Abklärung
05_Bauablauf - Bau-Nr.: In Abklärung; Bauablauf Etappe: In Abklärung; Bauablauf Verbauungsort: In Abklärung; Bauablauf Start Ausführung: In Abklärung; Bauablauf Ende Ausführung: In Abklärung
Bekleidung - Bekleidung Gipserarbeiten: In Abklärung; Bekleidung Malerarbeiten: In Abklärung; Bekleidung Putz: In Abklärung; Bekleidung Farbe: RAL / NCS
02_Mengen - Höhe - m: 0.5; Stärke - m: 0.2
00_Datenstruktur - BIM Base Version: 4.0.0; Kundenergänzungen Version: v01; CAD Werkzeug Typ: Wand; Klassifizierung: Aussenwand Ortbeton; Klassifizierung Level 0: Wand; Modellierungsrichtlinien: https://evolutbaugmbh.sharepoint.com/:b:/s/External/EciBgBMJMZlDgYCafV5wNokBvCJq9PUJAyVGz7O3vsjVrg?e=aLjLN9; Übersicht BIM Base: https://evolutbaugmbh.sharepoint.com/:b:/s/External/EfS4mJ9nZQpOhASXp0n2kW4B0K7N-vHKx-_6Crp5CxEFeg?e=Qu0M5d; Verbesserungsvorschläge BIM Base: https://forms.office.com/e/pcFhFfi5DW; Anleitung Mengen: https://evolutbaugmbh.sharepoint.com/:b:/s/External/ETgyOLO3JxJEqg9rbaRMLVEBHuWIRtkoMiJN1fISDr-3lw?e=E0LTiQ; Anleitung Eigenschaften: https://evolutbaugmbh.sharepoint.com/:b:/s/External/EQedjNXQkc1Btaftc01yAPUBtND9QzXFSH3-7sie6PGFww?e=wP4uf3; Release Notes: https://evolutbaugmbh.sharepoint.com/:b:/s/External/Eb41lwlDI71MhUVvor2V2mUBSaI-0tQK5U9oJAWxpCINuw?e=NtK3j6
Name | In | Länge brutto - m | Fläche brutto - m2 | Volumen netto - m3 | Schalungsfläche Wände brutto - m2 | Kote Unterkante | Kote Oberkante
Wand-017 | EG | 12.5 | 6.25 | 1.23 | 12.5 | 0 | 0.5
Wand-015 | EG | 4.69467 | 2.34733 | 0.469467 | 4.69467 | 0 | 0.5
2 x Wand-015 | EG | 2.82067 | 1.41033 | 0.262067 | 2.82067 | 0 | 0.5
Wand-016 | EG | 29.5 | 14.75 | 2.95 | 29.5 | 0 | 0.5
Wand-014 | EG | 19.4999 | 9.74995 | 1.94999 | 19.4999 | 0 | 0.5
Wand-014 | Attika | 14.58 | 7.29 | 1.45425 | 14.58 | 8.7 | 9.2
Wand-014 | Attika | 3.0358 | 1.6179 | 0.30278 | 3.2358 | 8.7 | 9.2
Wand-015 | Attika | 2.491 | 1.2597 | 0.23194 | 2.5194 | 8.7 | 9.2
Wand-014 | Attika | 9.8816 | 4.9408 | 0.984709 | 9.8816 | 8.7 | 9.2
Wand-015 | Attika | 2.21 | 1.205 | 0.221 | 2.41 | 8.7 | 9.2
Wand-014 | Attika | 1.01 | 0.605 | 0.101 | 1.21 | 8.7 | 9.2
Wand-014 | Attika | 2.21 | 1.205 | 0.219635 | 2.41 | 8.7 | 9.2
Wand-014 | Attika | 5.0908 | 2.5454 | 0.485629 | 5.0908 | 8.7 | 9.2
Wand-014 | Attika | 2.79 | 1.5 | 0.279318 | 3 | 8.7 | 9.2
Wand-014 | Attika | 4.5908 | 2.2954 | 0.43908 | 4.5908 | 8.7 | 9.2

# IfcWall: Beton bewehrt 300, Wand-013
In: EG
Classification: Aussenwand Ortbeton (BIM Base by Evolut); Material: Beton bewehrt
01_Leistungen und Kosten - Gebäude: In Abklärung; Elementpreis - CHF: 0; BKP: 211 - Baumeisterarbeiten; eBKP-H_Nr: C02.01; eBKP-H_Beschrieb: Aussenwandkonstruktion
03_Bausystem - Tragende Funktion: In Abklärung; Feuerwiderstand: In Abklärung; Luftschall: In Abklärung; U-Wert: In Abklärung; Umbau-Status: Neubau; Mehrschichtiger Aufbau: Beton bewehrt
05_Bauablauf - Bau-Nr.: In Abklärung; Bauablauf Etappe: In Abklärung; Bauablauf Verbauungsort: In Abklärung; Bauablauf Start Ausführung: In Abklärung; Bauablauf Ende Ausführung: In Abklärung
Massivbau Ortbeton - Ortbeton Druckfestigkeitsklasse: In Abklärung; Ortbeton Expositionsklasse: In Abklärung; Ortbeton Grösstkorn - mm: Dmax 32; Ortbeton Chloridgehaltsklasse: Cl 0.10; Ortbeton Konsistenzklasse: C3; Ortbeton Recyclingbeton: In Abklärung; Ortbeton Oberflächenausführung: In Abklärung; Ortbeton Oberflächenklasse - BOK: In Abklärung; Ortbeton Schalungstyp: In Abklärung; Ortbeton Dreikantleisten - mm: In Abklärung; Ortbeton Bew. Überdeckung oben - mm: In Abklärung; Ortbeton Bew. Überdeckung unten - mm: In Abklärung; Ortbeton Bew. Überdeckung aussen - mm: In Abklärung; Ortbeton Bew. Überdeckung innen - mm: In Abklärung; Ortbeton Bewehrungsgehalt - kg/m3: In Abklärung
Bekleidung - Bekleidung Gipserarbeiten: In Abklärung; Bekleidung Malerarbeiten: In Abklärung; Bekleidung Putz: In Abklärung; Bekleidung Farbe: RAL / NCS
02_Mengen - Höhe - m: 3.54; Stärke - m: 0.3; Länge brutto - m: 0.5; Fläche brutto - m2: 1.96816; Volumen netto - m3: 0.562418; Schalungsfläche Wände brutto - m2: 3.8873; Kote Unterkante: -0.64; Kote Oberkante: 2.9
00_Datenstruktur - BIM Base Version: 4.0.0; Kundenergänzungen Version: v01; CAD Werkzeug Typ: Wand; Klassifizierung: Aussenwand Ortbeton; Klassifizierung Level 0: Wand; Modellierungsrichtlinien: https://evolutbaugmbh.sharepoint.com/:b:/s/External/EciBgBMJMZlDgYCafV5wNokBvCJq9PUJAyVGz7O3vsjVrg?e=aLjLN9; Übersicht BIM Base: https://evolutbaugmbh.sharepoint.com/:b:/s/External/EfS4mJ9nZQpOhASXp0n2kW4B0K7N-vHKx-_6Crp5CxEFeg?e=Qu0M5d; Verbesserungsvorschläge BIM Base: https://forms.office.com/e/pcFhFfi5DW; Anleitung Mengen: https://evolutbaugmbh.sharepoint.com/:b:/s/External/ETgyOLO3JxJEqg9rbaRMLVEBHuWIRtkoMiJN1fISDr-3lw?e=E0LTiQ; Anleitung Eigenschaften: https://evolutbaugmbh.sharepoint.com/:b:/s/External/EQedjNXQkc1Btaftc01yAPUBtND9QzXFSH3-7sie6PGFww?e=wP4uf3; Release Notes: https://evolutbaugmbh.sharepoint.com/:b:/s/External/Eb41lwlDI71MhUVvor2V2mUBSaI-0tQK5U9oJAWxpCINuw?e=NtK3j6

# IfcWall: Innenwand Typ 01 154 (4)
Classification: Innenwand Holzständer (BIM Base by Evolut)
01_Leistungen und Kosten - Gebäude: In Abklärung; Elementpreis - CHF: 0; BKP: 214 - Montagebau in Holz; eBKP-H_Nr: C02.02; eBKP-H_Beschrieb: Innenwandkonstruktion
05_Bauablauf - Bau-Nr.: In Abklärung; Bauablauf Etappe: In Abklärung; Bauablauf Verbauungsort: In Abklärung; Bauablauf Start Ausführung: In Abklärung; Bauablauf Ende Ausführung: In Abklärung
03_Bausystem - Tragende Funktion: In Abklärung; Feuerwiderstand: In Abklärung; Luftschall: In Abklärung; U-Wert: In Abklärung; Umbau-Status: Neubau; Mehrschichtiger Aufbau: Dreischichtplatte DSP; Ständer Konstruktion gedämmt; Dreischichtplatte DSP
Holzbau - Holzbau Anschluss Massivbau vertikal: In Abklärung; Holzbau Anschluss Massivbau horizontal: In Abklärung; Holzbau Durchstanzung: In Abklärung; Holzbau Kapselung: In Abklärung; Holzbau Sonderelement: In Abklärung
Bekleidung - Bekleidung Gipserarbeiten: In Abklärung; Bekleidung Malerarbeiten: In Abklärung; Bekleidung Putz: In Abklärung; Bekleidung Farbe: RAL / NCS
00_Datenstruktur - BIM Base Version: 4.0.0; Kundenergänzungen Version: v01; CAD Werkzeug Typ: Wand; Klassifizierung: Innenwand Holzständer; Klassifizierung Level 0: Wand; Modellierungsrichtlinien: https://evolutbaugmbh.sharepoint.com/:b:/s/External/EciBgBMJMZlDgYCafV5wNokBvCJq9PUJAyVGz7O3vsjVrg?e=aLjLN9; Übersicht BIM Base: https://evolutbaugmbh.sharepoint.com/:b:/s/External/EfS4mJ9nZQpOhASXp0n2kW4B0K7N-vHKx-_6Crp5CxEFeg?e=Qu0M5d; Verbesserungsvorschläge BIM Base: https://forms.office.com/e/pcFhFfi5DW; Anleitung Mengen: https://evolutbaugmbh.sharepoint.com/:b:/s/External/ETgyOLO3JxJEqg9rbaRMLVEBHuWIRtkoMiJN1fISDr-3lw?e=E0LTiQ; Anleitung Eigenschaften: https://evolutbaugmbh.sharepoint.com/:b:/s/External/EQedjNXQkc1Btaftc01yAPUBtND9QzXFSH3-7sie6PGFww?e=wP4uf3; Release Notes: https://evolutbaugmbh.sharepoint.com/:b:/s/External/Eb41lwlDI71MhUVvor2V2mUBSaI-0tQK5U9oJAWxpCINuw?e=NtK3j6
02_Mengen - Stärke - m: 0.154
Name | In | Höhe - m | Länge brutto - m | Fläche brutto - m2 | Volumen netto - m3 | Kote Unterkante | Kote Oberkante
Wand-014 | EG | 3.144 | 3.76105 | 12.4095 | 1.82585 | 0 | 3.144
Wand-014 | 1.OG | 2.644 | 3.76105 | 10.436 | 1.53548 | 3.4 | 6.044
Wand-014 | 2.OG | 2.579 | 3.76105 | 10.436 | 1.49773 | 6.3 | 8.944
Wand-014 | Dachaufsicht | 1.40441 | 7.021 | 9.86037 | 1.29023 | 11.844 | 13.248

# IfcWall: Innenwand Typ 02 150 (13)
Classification: Innenwand Backstein (BIM Base by Evolut); Material: MW, Backstein, Sichtmauerwerk
01_Leistungen und Kosten - Gebäude: In Abklärung; Elementpreis - CHF: 0; BKP: 211 - Baumeisterarbeiten; eBKP-H_Nr: C02.02; eBKP-H_Beschrieb: Innenwandkonstruktion
05_Bauablauf - Bau-Nr.: In Abklärung; Bauablauf Etappe: In Abklärung; Bauablauf Verbauungsort: In Abklärung; Bauablauf Start Ausführung: In Abklärung; Bauablauf Ende Ausführung: In Abklärung
03_Bausystem - Tragende Funktion: In Abklärung; Feuerwiderstand: In Abklärung; Luftschall: In Abklärung; U-Wert: In Abklärung; Umbau-Status: Neubau; Mehrschichtiger Aufbau: MW, Backstein, Sichtmauerwerk
Mauerwerk - Mauerwerk Deckenlager: In Abklärung; Mauerwerk Mauerfusselement: In Abklärung
Bekleidung - Bekleidung Gipserarbeiten: In Abklärung; Bekleidung Malerarbeiten: In Abklärung; Bekleidung Putz: In Abklärung; Bekleidung Farbe: RAL / NCS
02_Mengen - Stärke - m: 0.15
00_Datenstruktur - BIM Base Version: 4.0.0; Kundenergänzungen Version: v01; CAD Werkzeug Typ: Wand; Klassifizierung: Innenwand Backstein; Klassifizierung Level 0: Wand; Modellierungsrichtlinien: https://evolutbaugmbh.sharepoint.com/:b:/s/External/EciBgBMJMZlDgYCafV5wNokBvCJq9PUJAyVGz7O3vsjVrg?e=aLjLN9; Übersicht BIM Base: https://evolutbaugmbh.sharepoint.com/:b:/s/External/EfS4mJ9nZQpOhASXp0n2kW4B0K7N-vHKx-_6Crp5CxEFeg?e=Qu0M5d; Verbesserungsvorschläge BIM Base: https://forms.office.com/e/pcFhFfi5DW; Anleitung Mengen: https://evolutbaugmbh.sharepoint.com/:b:/s/External/ETgyOLO3JxJEqg9rbaRMLVEBHuWIRtkoMiJN1fISDr-3lw?e=E0LTiQ; Anleitung Eigenschaften: https://evolutbaugmbh.sharepoint.com/:b:/s/External/EQedjNXQkc1Btaftc01yAPUBtND9QzXFSH3-7sie6PGFww?e=wP4uf3; Release Notes: https://evolutbaugmbh.sharepoint.com/:b:/s/External/Eb41lwlDI71MhUVvor2V2mUBSaI-0tQK5U9oJAWxpCINuw?e=NtK3j6
Name | In | Höhe - m | Länge brutto - m | Fläche brutto - m2 | Volumen netto - m3 | Kote Unterkante | Kote Oberkante
Wand-016 | UG | 3.44872 | 15.174 | 46.2873 | 6.93851 | -4.002 | -0.542
Wand-016 | UG | 3.65 | 0.851 | 3.65365 | 0.43881 | -3.9 | -0.25
Wand-017 | UG | 3.34627 | 3.649 | 12.2105 | 1.78706 | -3.9 | -0.554
Wand-017 | UG | 3.0579 | 3.649 | 11.1583 | 1.63865 | -3.9 | -0.842
Wand-016 | UG | 3.65 | 0.851 | 3.65365 | 0.438837 | -3.9 | -0.25
Wand-016 | UG | 3.65 | 1.001 | 3.65365 | 0.438865 | -3.9 | -0.25
Wand-017 | UG | 3.20208 | 3.649 | 11.6844 | 1.7176 | -3.9 | -0.698
Wand-016 | EG | 2.65 | 1.99 | 6.3335 | 0.791025 | 0 | 2.65
Wand-015 | 1.OG | 2.65 | 2.74147 | 7.66239 | 1.02613 | 2.9 | 5.55
Wand-014 | 1.OG | 2.65 | 3.963 | 11.2704 | 1.57529 | 2.9 | 5.55
Wand-014 | 2.OG | 2.65 | 3.963 | 11.2704 | 1.57529 | 5.8 | 8.45
Wand-015 | 2.OG | 2.65 | 2.74147 | 7.66239 | 1.02613 | 5.8 | 8.45
Wand-015 | Attika | 2.65 | 2.74147 | 7.68889 | 1.02613 | 8.7 | 11.35

# IfcWall: Innenwand Typ 03 160 (4)
Classification: Innenwand Backstein (BIM Base by Evolut)
01_Leistungen und Kosten - Gebäude: In Abklärung; Elementpreis - CHF: 0; BKP: 211 - Baumeisterarbeiten; eBKP-H_Nr: C02.02; eBKP-H_Beschrieb: Innenwandkonstruktion
03_Bausystem - Tragende Funktion: In Abklärung; Feuerwiderstand: In Abklärung; Luftschall: In Abklärung; U-Wert: In Abklärung; Umbau-Status: Neubau; Mehrschichtiger Aufbau: MW, Backstein; Kalkzementputz Aussen
05_Bauablauf - Bau-Nr.: In Abklärung; Bauablauf Etappe: In Abklärung; Bauablauf Verbauungsort: In Abklärung; Bauablauf Start Ausführung: In Abklärung; Bauablauf Ende Ausführung: In Abklärung
Bekleidung - Bekleidung Gipserarbeiten: In Abklärung; Bekleidung Malerarbeiten: In Abklärung; Bekleidung Putz: In Abklärung; Bekleidung Farbe: RAL / NCS
02_Mengen - Stärke - m: 0.16
Mauerwerk - Mauerwerk Deckenlager: In Abklärung; Mauerwerk Mauerfusselement: In Abklärung
00_Datenstruktur - BIM Base Version: 4.0.0; Kundenergänzungen Version: v01; CAD Werkzeug Typ: Wand; Klassifizierung: Innenwand Backstein; Klassifizierung Level 0: Wand; Modellierungsrichtlinien: https://evolutbaugmbh.sharepoint.com/:b:/s/External/EciBgBMJMZlDgYCafV5wNokBvCJq9PUJAyVGz7O3vsjVrg?e=aLjLN9; Übersicht BIM Base: https://evolutbaugmbh.sharepoint.com/:b:/s/External/EfS4mJ9nZQpOhASXp0n2kW4B0K7N-vHKx-_6Crp5CxEFeg?e=Qu0M5d; Verbesserungsvorschläge BIM Base: https://forms.office.com/e/pcFhFfi5DW; Anleitung Mengen: https://evolutbaugmbh.sharepoint.com/:b:/s/External/ETgyOLO3JxJEqg9rbaRMLVEBHuWIRtkoMiJN1fISDr-3lw?e=E0LTiQ; Anleitung Eigenschaften: https://evolutbaugmbh.sharepoint.com/:b:/s/External/EQedjNXQkc1Btaftc01yAPUBtND9QzXFSH3-7sie6PGFww?e=wP4uf3; Release Notes: https://evolutbaugmbh.sharepoint.com/:b:/s/External/Eb41lwlDI71MhUVvor2V2mUBSaI-0tQK5U9oJAWxpCINuw?e=NtK3j6
Name | In | Höhe - m | Länge brutto - m | Fläche brutto - m2 | Volumen netto - m3 | Kote Unterkante | Kote Oberkante
Wand-014 | 1.OG | 2.8 | 1.655 | 6.23 | 0.743157 | 2.9 | 5.7
Wand-014 | 2.OG | 2.5 | 1.655 | 5.5625 | 0.663267 | 5.95 | 8.45
Wand-014 | Attika | 2.65 | 3.2 | 9.7255 | 1.35995 | 8.7 | 11.35
Wand-014 | Attika | 2.65 | 1.655 | 5.83125 | 0.70337 | 8.7 | 11.35

# IfcWall: Innenwand Typ 04 145, Wand-014
In: Attika
Classification: Innenwand Backstein (BIM Base by Evolut)
05_Bauablauf - Bau-Nr.: In Abklärung; Bauablauf Etappe: In Abklärung; Bauablauf Verbauungsort: In Abklärung; Bauablauf Start Ausführung: In Abklärung; Bauablauf Ende Ausführung: In Abklärung
01_Leistungen und Kosten - Gebäude: In Abklärung; Elementpreis - CHF: 0; BKP: 211 - Baumeisterarbeiten; eBKP-H_Nr: C02.02; eBKP-H_Beschrieb: Innenwandkonstruktion
03_Bausystem - Tragende Funktion: In Abklärung; Feuerwiderstand: In Abklärung; Luftschall: In Abklärung; U-Wert: In Abklärung; Umbau-Status: Neubau; Mehrschichtiger Aufbau: Kalkzementputz Aussen; MW, Backstein; Kalkzementputz Aussen
Mauerwerk - Mauerwerk Deckenlager: In Abklärung; Mauerwerk Mauerfusselement: In Abklärung
Bekleidung - Bekleidung Gipserarbeiten: In Abklärung; Bekleidung Malerarbeiten: In Abklärung; Bekleidung Putz: In Abklärung; Bekleidung Farbe: RAL / NCS
02_Mengen - Höhe - m: 2.65; Stärke - m: 0.145; Länge brutto - m: 1.48; Fläche brutto - m2: 4.9935; Volumen netto - m3: 0.338683; Kote Unterkante: 8.7; Kote Oberkante: 11.35
00_Datenstruktur - BIM Base Version: 4.0.0; Kundenergänzungen Version: v01; CAD Werkzeug Typ: Wand; Klassifizierung: Innenwand Backstein; Klassifizierung Level 0: Wand; Modellierungsrichtlinien: https://evolutbaugmbh.sharepoint.com/:b:/s/External/EciBgBMJMZlDgYCafV5wNokBvCJq9PUJAyVGz7O3vsjVrg?e=aLjLN9; Übersicht BIM Base: https://evolutbaugmbh.sharepoint.com/:b:/s/External/EfS4mJ9nZQpOhASXp0n2kW4B0K7N-vHKx-_6Crp5CxEFeg?e=Qu0M5d; Verbesserungsvorschläge BIM Base: https://forms.office.com/e/pcFhFfi5DW; Anleitung Mengen: https://evolutbaugmbh.sharepoint.com/:b:/s/External/ETgyOLO3JxJEqg9rbaRMLVEBHuWIRtkoMiJN1fISDr-3lw?e=E0LTiQ; Anleitung Eigenschaften: https://evolutbaugmbh.sharepoint.com/:b:/s/External/EQedjNXQkc1Btaftc01yAPUBtND9QzXFSH3-7sie6PGFww?e=wP4uf3; Release Notes: https://evolutbaugmbh.sharepoint.com/:b:/s/External/Eb41lwlDI71MhUVvor2V2mUBSaI-0tQK5U9oJAWxpCINuw?e=NtK3j6

# IfcWall: Innenwand Typ 05 170 (21)
01_Leistungen und Kosten - Gebäude: In Abklärung; Elementpreis - CHF: 0; eBKP-H_Nr: C02.02; eBKP-H_Beschrieb: Innenwandkonstruktion
05_Bauablauf - Bau-Nr.: In Abklärung; Bauablauf Etappe: In Abklärung; Bauablauf Verbauungsort: In Abklärung; Bauablauf Start Ausführung: In Abklärung; Bauablauf Ende Ausführung: In Abklärung
03_Bausystem - Tragende Funktion: In Abklärung; Feuerwiderstand: In Abklärung; Luftschall: In Abklärung; U-Wert: In Abklärung; Umbau-Status: Neubau; Mehrschichtiger Aufbau: Kalkzementputz Aussen; MW, Backstein; Kalkzementputz Aussen
Bekleidung - Bekleidung Gipserarbeiten: In Abklärung; Bekleidung Malerarbeiten: In Abklärung; Bekleidung Putz: In Abklärung; Bekleidung Farbe: RAL / NCS
00_Datenstruktur - BIM Base Version: 4.0.0; Kundenergänzungen Version: v01; CAD Werkzeug Typ: Wand; Klassifizierung Level 0: Wand; Modellierungsrichtlinien: https://evolutbaugmbh.sharepoint.com/:b:/s/External/EciBgBMJMZlDgYCafV5wNokBvCJq9PUJAyVGz7O3vsjVrg?e=aLjLN9; Übersicht BIM Base: https://evolutbaugmbh.sharepoint.com/:b:/s/External/EfS4mJ9nZQpOhASXp0n2kW4B0K7N-vHKx-_6Crp5CxEFeg?e=Qu0M5d; Verbesserungsvorschläge BIM Base: https://forms.office.com/e/pcFhFfi5DW; Anleitung Mengen: https://evolutbaugmbh.sharepoint.com/:b:/s/External/ETgyOLO3JxJEqg9rbaRMLVEBHuWIRtkoMiJN1fISDr-3lw?e=E0LTiQ; Anleitung Eigenschaften: https://evolutbaugmbh.sharepoint.com/:b:/s/External/EQedjNXQkc1Btaftc01yAPUBtND9QzXFSH3-7sie6PGFww?e=wP4uf3; Release Notes: https://evolutbaugmbh.sharepoint.com/:b:/s/External/Eb41lwlDI71MhUVvor2V2mUBSaI-0tQK5U9oJAWxpCINuw?e=NtK3j6
02_Mengen - Stärke - m: 0.17
Name | In | Classification | BKP | Holzbau Anschluss Massivbau vertikal = Holzbau Anschluss Massivbau horizontal = Holzbau Durchstanzung = Holzbau Kapselung = Holzbau Sonderelement | Klassifizierung | Höhe - m | Länge brutto - m | Fläche brutto - m2 | Volumen netto - m3 | Kote Unterkante | Kote Oberkante
Wand-014 | 1.OG | Innenwand Holzständer (BIM Base by Evolut) | 214 - Montagebau in Holz | In Abklärung | Innenwand Holzständer | 2.65 | 4.068 | 11.7607 | 1.82838 | 2.9 | 5.55
Wand-014 | 1.OG | Innenwand Holzständer (BIM Base by Evolut) | 214 - Montagebau in Holz | In Abklärung | Innenwand Holzständer | 2.65 | 4.50678 | 12.7645 | 1.71341 | 2.9 | 5.55
Wand-014 | 1.OG | Innenwand Holzständer (BIM Base by Evolut) | 214 - Montagebau in Holz | In Abklärung | Innenwand Holzständer | 2.8 | 6.99 | 20.892 | 2.6393 | 2.9 | 5.7
Wand-014 | 1.OG | Innenwand Holzständer (BIM Base by Evolut) | 214 - Montagebau in Holz | In Abklärung | Innenwand Holzständer | 2.65 | 6.15749 | 16.7678 | 2.75945 | 2.9 | 5.55
Wand-014 | 1.OG | Innenwand Holzständer (BIM Base by Evolut) | 214 - Montagebau in Holz | In Abklärung | Innenwand Holzständer | 2.65 | 2.423 | 7.21595 | 1.08452 | 2.9 | 5.55
Wand-014 | 1.OG | Innenwand Holzständer (BIM Base by Evolut) | 214 - Montagebau in Holz | In Abklärung | Innenwand Holzständer | 2.65 | 6.674 | 18.1366 | 2.37964 | 2.9 | 5.55
Wand-014 | 1.OG | Innenwand Holzständer (BIM Base by Evolut) | 214 - Montagebau in Holz | In Abklärung | Innenwand Holzständer | 2.65 | 6.33969 | 17.5687 | 2.14259 | 2.9 | 5.55
Wand-014 | 1.OG | Innenwand Holzständer (BIM Base by Evolut) | 214 - Montagebau in Holz | In Abklärung | Innenwand Holzständer | 2.65 | 4.20278 | 11.1374 | 1.81454 | 2.9 | 5.55
Wand-014 | 2.OG | Innenwand Holzständer (BIM Base by Evolut) | 214 - Montagebau in Holz | In Abklärung | Innenwand Holzständer | 2.65 | 4.068 | 11.7607 | 1.82838 | 5.8 | 8.45
Wand-014 | 2.OG | Innenwand Holzständer (BIM Base by Evolut) | 214 - Montagebau in Holz | In Abklärung | Innenwand Holzständer | 2.65 | 7 | 19.0005 | 2.43148 | 5.8 | 8.45
Wand-014 | 2.OG | Innenwand Holzständer (BIM Base by Evolut) | 214 - Montagebau in Holz | In Abklärung | Innenwand Holzständer | 2.65 | 2.423 | 7.21595 | 1.08452 | 5.8 | 8.45
Wand-014 | 2.OG | Innenwand Holzständer (BIM Base by Evolut) | 214 - Montagebau in Holz | In Abklärung | Innenwand Holzständer | 2.65 | 6.674 | 18.1366 | 2.37964 | 5.8 | 8.45
Wand-014 | 2.OG | Innenwand Holzständer (BIM Base by Evolut) | 214 - Montagebau in Holz | In Abklärung | Innenwand Holzständer | 2.65 | 6.33969 | 17.5687 | 2.14259 | 5.8 | 8.45
Wand-014 | 2.OG | Innenwand Holzständer (BIM Base by Evolut) | 214 - Montagebau in Holz | In Abklärung | Innenwand Holzständer | 2.65 | 4.20278 | 11.1374 | 1.81454 | 5.8 | 8.45
Wand-014 | 2.OG | Innenwand Holzständer (BIM Base by Evolut) | 214 - Montagebau in Holz | In Abklärung | Innenwand Holzständer | 2.65 | 6.15749 | 16.7678 | 2.75945 | 5.8 | 8.45
Wand-014 | 2.OG | Innenwand Holzständer (BIM Base by Evolut) | 214 - Montagebau in Holz | In Abklärung | Innenwand Holzständer | 2.65 | 4.50678 | 12.7645 | 1.71341 | 5.8 | 8.45
Wand-014 | Attika | Innenwand Holzständer (BIM Base by Evolut) | 214 - Montagebau in Holz | In Abklärung | Innenwand Holzständer | 2.65 | 6.99 | 18.974 | 2.51844 | 8.7 | 11.35
Wand-014 | Attika | Innenwand Holzständer (BIM Base by Evolut) | 214 - Montagebau in Holz | In Abklärung | Innenwand Holzständer | 2.65 | 2.423 | 7.21595 | 1.08452 | 8.7 | 11.35
Wand-014 | Attika | Innenwand Backstein (BIM Base by Evolut) | 211 - Baumeisterarbeiten |  | Innenwand Backstein | 2.65 | 4.427 | 12.182 | 1.68146 | 8.7 | 11.35 | Mauerwerk - Mauerwerk Deckenlager: In Abklärung; Mauerwerk Mauerfusselement: In Abklärung
Wand-014 | Attika | Innenwand Backstein (BIM Base by Evolut) | 211 - Baumeisterarbeiten |  | Innenwand Backstein | 2.65 | 3.44978 | 9.14191 | 1.47193 | 8.7 | 11.35 | Mauerwerk - Mauerwerk Deckenlager: In Abklärung; Mauerwerk Mauerfusselement: In Abklärung
Wand-014 | Attika | Innenwand Backstein (BIM Base by Evolut) | 211 - Baumeisterarbeiten |  | Innenwand Backstein | 2.65 | 8.24647 | 21.8531 | 3.02666 | 8.7 | 11.35 | Mauerwerk - Mauerwerk Deckenlager: In Abklärung; Mauerwerk Mauerfusselement: In Abklärung

# IfcWall: Innenwand Typ 06 300 (15)
Classification: Innenwand Ortbeton (BIM Base by Evolut)
05_Bauablauf - Bau-Nr.: In Abklärung; Bauablauf Etappe: In Abklärung; Bauablauf Verbauungsort: In Abklärung; Bauablauf Start Ausführung: In Abklärung; Bauablauf Ende Ausführung: In Abklärung
01_Leistungen und Kosten - Gebäude: In Abklärung; Elementpreis - CHF: 0; BKP: 211 - Baumeisterarbeiten; eBKP-H_Nr: C02.02; eBKP-H_Beschrieb: Innenwandkonstruktion
03_Bausystem - Tragende Funktion: In Abklärung; Feuerwiderstand: In Abklärung; Luftschall: In Abklärung; U-Wert: In Abklärung; Umbau-Status: Neubau; Mehrschichtiger Aufbau: Beton bewehrt; Sichtbeton
Massivbau Ortbeton - Ortbeton Druckfestigkeitsklasse: In Abklärung; Ortbeton Expositionsklasse: In Abklärung; Ortbeton Grösstkorn - mm: Dmax 32; Ortbeton Chloridgehaltsklasse: Cl 0.10; Ortbeton Konsistenzklasse: C3; Ortbeton Recyclingbeton: In Abklärung; Ortbeton Oberflächenausführung: In Abklärung; Ortbeton Oberflächenklasse - BOK: In Abklärung; Ortbeton Schalungstyp: In Abklärung; Ortbeton Dreikantleisten - mm: In Abklärung; Ortbeton Bew. Überdeckung oben - mm: In Abklärung; Ortbeton Bew. Überdeckung unten - mm: In Abklärung; Ortbeton Bew. Überdeckung aussen - mm: In Abklärung; Ortbeton Bew. Überdeckung innen - mm: In Abklärung; Ortbeton Bewehrungsgehalt - kg/m3: In Abklärung
Bekleidung - Bekleidung Gipserarbeiten: In Abklärung; Bekleidung Malerarbeiten: In Abklärung; Bekleidung Putz: In Abklärung; Bekleidung Farbe: RAL / NCS
02_Mengen - Stärke - m: 0.3
00_Datenstruktur - BIM Base Version: 4.0.0; Kundenergänzungen Version: v01; CAD Werkzeug Typ: Wand; Klassifizierung: Innenwand Ortbeton; Klassifizierung Level 0: Wand; Modellierungsrichtlinien: https://evolutbaugmbh.sharepoint.com/:b:/s/External/EciBgBMJMZlDgYCafV5wNokBvCJq9PUJAyVGz7O3vsjVrg?e=aLjLN9; Übersicht BIM Base: https://evolutbaugmbh.sharepoint.com/:b:/s/External/EfS4mJ9nZQpOhASXp0n2kW4B0K7N-vHKx-_6Crp5CxEFeg?e=Qu0M5d; Verbesserungsvorschläge BIM Base: https://forms.office.com/e/pcFhFfi5DW; Anleitung Mengen: https://evolutbaugmbh.sharepoint.com/:b:/s/External/ETgyOLO3JxJEqg9rbaRMLVEBHuWIRtkoMiJN1fISDr-3lw?e=E0LTiQ; Anleitung Eigenschaften: https://evolutbaugmbh.sharepoint.com/:b:/s/External/EQedjNXQkc1Btaftc01yAPUBtND9QzXFSH3-7sie6PGFww?e=wP4uf3; Release Notes: https://evolutbaugmbh.sharepoint.com/:b:/s/External/Eb41lwlDI71MhUVvor2V2mUBSaI-0tQK5U9oJAWxpCINuw?e=NtK3j6
Name | In | Höhe - m | Länge brutto - m | Fläche brutto - m2 | Volumen netto - m3 | Schalungsfläche Wände brutto - m2 | Kote Unterkante | Kote Oberkante
2 x Wand-014 | UG | 3.0496 | 5 | 14.982 | 4.17269 | 29.964 | -3.45 | -0.388
Wand-014 | UG | 2.9 | 2.59 | 7.511 | 2.02246 | 15.022 | -3.3 | -0.4
Wand-014 | UG | 2.9 | 3.925 | 11.3825 | 3.18391 | 22.765 | -3.3 | -0.4
Wand-014 | UG | 3.062 | 9.79 | 29.977 | 8.9294 | 59.954 | -3.462 | -0.4
Wand-014 | UG | 3.3 | 3.275 | 10.8075 | 2.50425 | 21.615 | -3.3 | 0
Wand-014 | EG | 2.65 | 2.29 | 6.0685 | 1.79299 | 12.137 | 0 | 2.65
Wand-014 | EG | 2.65 | 3.625 | 9.60625 | 1.91493 | 19.2125 | 0 | 2.65
Wand-014 | EG | 2.65 | 2.5 | 6.625 | 1.95994 | 13.25 | 0 | 2.65
Wand-014 | EG | 2.8 | 3.875 | 11.2375 | 2.48585 | 22.475 | 0 | 2.9
Wand-014 | 1.OG | 2.6 | 3.99 | 10.374 | 2.3742 | 20.748 | 3.05 | 5.65
Wand-014 | 2.OG | 2.6 | 3.99 | 10.374 | 2.3742 | 20.748 | 5.95 | 8.55
Wand-014 | Attika | 2.9 | 9.49 | 28.391 | 7.49354 | 56.782 | 9.2 | 12.1
Wand-014 | Attika | 2.9 | 2.509 | 7.2761 | 1.95199 | 14.5522 | 9.2 | 12.1
Wand-014 | Attika | 3.25 | 3.99 | 12.9675 | 3.15225 | 25.935 | 8.85 | 12.1

# IfcWall: Innenwand Typ 07 301 (4)
In: UG
Classification: Innenwand Ortbeton (BIM Base by Evolut)
01_Leistungen und Kosten - Gebäude: In Abklärung; Elementpreis - CHF: 0; BKP: 211 - Baumeisterarbeiten; eBKP-H_Nr: C02.02; eBKP-H_Beschrieb: Innenwandkonstruktion
03_Bausystem - Tragende Funktion: In Abklärung; Feuerwiderstand: In Abklärung; Luftschall: In Abklärung; U-Wert: In Abklärung; Umbau-Status: Neubau; Mehrschichtiger Aufbau: Beton bewehrt; Anstrich Innen
Massivbau Ortbeton - Ortbeton Druckfestigkeitsklasse: In Abklärung; Ortbeton Expositionsklasse: In Abklärung; Ortbeton Grösstkorn - mm: Dmax 32; Ortbeton Chloridgehaltsklasse: Cl 0.10; Ortbeton Konsistenzklasse: C3; Ortbeton Recyclingbeton: In Abklärung; Ortbeton Oberflächenausführung: In Abklärung; Ortbeton Oberflächenklasse - BOK: In Abklärung; Ortbeton Schalungstyp: In Abklärung; Ortbeton Dreikantleisten - mm: In Abklärung; Ortbeton Bew. Überdeckung oben - mm: In Abklärung; Ortbeton Bew. Überdeckung unten - mm: In Abklärung; Ortbeton Bew. Überdeckung aussen - mm: In Abklärung; Ortbeton Bew. Überdeckung innen - mm: In Abklärung; Ortbeton Bewehrungsgehalt - kg/m3: In Abklärung
05_Bauablauf - Bau-Nr.: In Abklärung; Bauablauf Etappe: In Abklärung; Bauablauf Verbauungsort: In Abklärung; Bauablauf Start Ausführung: In Abklärung; Bauablauf Ende Ausführung: In Abklärung
02_Mengen - Stärke - m: 0.301
00_Datenstruktur - BIM Base Version: 4.0.0; Kundenergänzungen Version: v01; CAD Werkzeug Typ: Wand; Klassifizierung: Innenwand Ortbeton; Klassifizierung Level 0: Wand; Modellierungsrichtlinien: https://evolutbaugmbh.sharepoint.com/:b:/s/External/EciBgBMJMZlDgYCafV5wNokBvCJq9PUJAyVGz7O3vsjVrg?e=aLjLN9; Übersicht BIM Base: https://evolutbaugmbh.sharepoint.com/:b:/s/External/EfS4mJ9nZQpOhASXp0n2kW4B0K7N-vHKx-_6Crp5CxEFeg?e=Qu0M5d; Verbesserungsvorschläge BIM Base: https://forms.office.com/e/pcFhFfi5DW; Anleitung Mengen: https://evolutbaugmbh.sharepoint.com/:b:/s/External/ETgyOLO3JxJEqg9rbaRMLVEBHuWIRtkoMiJN1fISDr-3lw?e=E0LTiQ; Anleitung Eigenschaften: https://evolutbaugmbh.sharepoint.com/:b:/s/External/EQedjNXQkc1Btaftc01yAPUBtND9QzXFSH3-7sie6PGFww?e=wP4uf3; Release Notes: https://evolutbaugmbh.sharepoint.com/:b:/s/External/Eb41lwlDI71MhUVvor2V2mUBSaI-0tQK5U9oJAWxpCINuw?e=NtK3j6
Bekleidung - Bekleidung Gipserarbeiten: In Abklärung; Bekleidung Malerarbeiten: In Abklärung; Bekleidung Putz: In Abklärung; Bekleidung Farbe: RAL / NCS
Name | Höhe - m | Länge brutto - m | Fläche brutto - m2 | Volumen netto - m3 | Schalungsfläche Wände brutto - m2 | Kote Unterkante | Kote Oberkante
2 x Wand-014 | 2.9 | 3.5 | 11.02 | 3.00028 | 22.04 | -3.3 | -0.4
Wand-014 | 2.34929 | 3.875 | 9.10351 | 2.32474 | 18.207 | -3.349 | -1
Wand-013 | 2.9 | 4.7 | 14.5 | 0.99631 | 29 | -3.3 | -0.4

# IfcWall: Innenwand Typ 08 300 (14)
Classification: Innenwand Ortbeton (BIM Base by Evolut); Material: Beton bewehrt
01_Leistungen und Kosten - Gebäude: In Abklärung; Elementpreis - CHF: 0; BKP: 211 - Baumeisterarbeiten; eBKP-H_Nr: C02.02; eBKP-H_Beschrieb: Innenwandkonstruktion
05_Bauablauf - Bau-Nr.: In Abklärung; Bauablauf Etappe: In Abklärung; Bauablauf Verbauungsort: In Abklärung; Bauablauf Start Ausführung: In Abklärung; Bauablauf Ende Ausführung: In Abklärung
03_Bausystem - Tragende Funktion: In Abklärung; Feuerwiderstand: In Abklärung; Luftschall: In Abklärung; U-Wert: In Abklärung; Umbau-Status: Neubau; Mehrschichtiger Aufbau: Beton bewehrt
Massivbau Ortbeton - Ortbeton Druckfestigkeitsklasse: In Abklärung; Ortbeton Expositionsklasse: In Abklärung; Ortbeton Grösstkorn - mm: Dmax 32; Ortbeton Chloridgehaltsklasse: Cl 0.10; Ortbeton Konsistenzklasse: C3; Ortbeton Recyclingbeton: In Abklärung; Ortbeton Oberflächenausführung: In Abklärung; Ortbeton Oberflächenklasse - BOK: In Abklärung; Ortbeton Schalungstyp: In Abklärung; Ortbeton Dreikantleisten - mm: In Abklärung; Ortbeton Bew. Überdeckung oben - mm: In Abklärung; Ortbeton Bew. Überdeckung unten - mm: In Abklärung; Ortbeton Bew. Überdeckung aussen - mm: In Abklärung; Ortbeton Bew. Überdeckung innen - mm: In Abklärung; Ortbeton Bewehrungsgehalt - kg/m3: In Abklärung
Bekleidung - Bekleidung Gipserarbeiten: In Abklärung; Bekleidung Malerarbeiten: In Abklärung; Bekleidung Putz: In Abklärung; Bekleidung Farbe: RAL / NCS
02_Mengen - Stärke - m: 0.3
00_Datenstruktur - BIM Base Version: 4.0.0; Kundenergänzungen Version: v01; CAD Werkzeug Typ: Wand; Klassifizierung: Innenwand Ortbeton; Klassifizierung Level 0: Wand; Modellierungsrichtlinien: https://evolutbaugmbh.sharepoint.com/:b:/s/External/EciBgBMJMZlDgYCafV5wNokBvCJq9PUJAyVGz7O3vsjVrg?e=aLjLN9; Übersicht BIM Base: https://evolutbaugmbh.sharepoint.com/:b:/s/External/EfS4mJ9nZQpOhASXp0n2kW4B0K7N-vHKx-_6Crp5CxEFeg?e=Qu0M5d; Verbesserungsvorschläge BIM Base: https://forms.office.com/e/pcFhFfi5DW; Anleitung Mengen: https://evolutbaugmbh.sharepoint.com/:b:/s/External/ETgyOLO3JxJEqg9rbaRMLVEBHuWIRtkoMiJN1fISDr-3lw?e=E0LTiQ; Anleitung Eigenschaften: https://evolutbaugmbh.sharepoint.com/:b:/s/External/EQedjNXQkc1Btaftc01yAPUBtND9QzXFSH3-7sie6PGFww?e=wP4uf3; Release Notes: https://evolutbaugmbh.sharepoint.com/:b:/s/External/Eb41lwlDI71MhUVvor2V2mUBSaI-0tQK5U9oJAWxpCINuw?e=NtK3j6
Name | In | Höhe - m | Länge brutto - m | Fläche brutto - m2 | Volumen netto - m3 | Schalungsfläche Wände brutto - m2 | Kote Unterkante | Kote Oberkante
Wand-014 | EG | 2.65 | 3.5 | 9.275 | 2.7825 | 18.55 | 0 | 2.65
Wand-014 | EG | 2.65 | 3.875 | 10.2687 | 2.84212 | 20.5375 | 0 | 2.65
Wand-014 | EG | 2.65 | 4.79 | 13.4885 | 3.56955 | 26.977 | 0 | 2.65
Wand-014 | EG | 2.65 | 3.5 | 9.275 | 2.544 | 18.55 | 0 | 2.65
Wand-014 | 1.OG | 2.65 | 3.5 | 9.275 | 2.544 | 18.55 | 2.9 | 5.55
Wand-014 | 1.OG | 2.8 | 3.5 | 9.8 | 2.94 | 19.6 | 2.9 | 5.7
Wand-014 | 1.OG | 2.8 | 3.875 | 10.85 | 2.95845 | 21.7 | 2.9 | 5.7
Wand-014 | 2.OG | 2.65 | 3.5 | 9.275 | 2.469 | 18.55 | 5.8 | 8.45
Wand-014 | 2.OG | 2.5 | 3.5 | 9.275 | 2.625 | 18.55 | 5.95 | 8.6
Wand-014 | 2.OG | 2.9 | 3.875 | 11.2375 | 2.90212 | 22.475 | 5.8 | 8.7
Wand-014 | Attika | 3.4 | 3.275 | 12.155 | 3.3405 | 24.31 | 8.7 | 12.1
Wand-014 | Attika | 3.4 | 3.5 | 11.9 | 3.3225 | 23.8 | 8.7 | 12.1
Wand-014 | Attika | 3.4 | 3.5 | 11.9 | 3.57 | 23.8 | 8.7 | 12.1
Wand-014 | Attika | 2.75 | 3.875 | 10.6562 | 2.94938 | 21.3125 | 9.35 | 12.1

# IfcWall: Innenwand Typ 09 310 (3)
Classification: Innenwand Ortbeton (BIM Base by Evolut)
01_Leistungen und Kosten - Gebäude: In Abklärung; Elementpreis - CHF: 0; BKP: 211 - Baumeisterarbeiten; eBKP-H_Nr: C02.02; eBKP-H_Beschrieb: Innenwandkonstruktion
05_Bauablauf - Bau-Nr.: In Abklärung; Bauablauf Etappe: In Abklärung; Bauablauf Verbauungsort: In Abklärung; Bauablauf Start Ausführung: In Abklärung; Bauablauf Ende Ausführung: In Abklärung
Bekleidung - Bekleidung Gipserarbeiten: In Abklärung; Bekleidung Malerarbeiten: In Abklärung; Bekleidung Putz: In Abklärung; Bekleidung Farbe: RAL / NCS
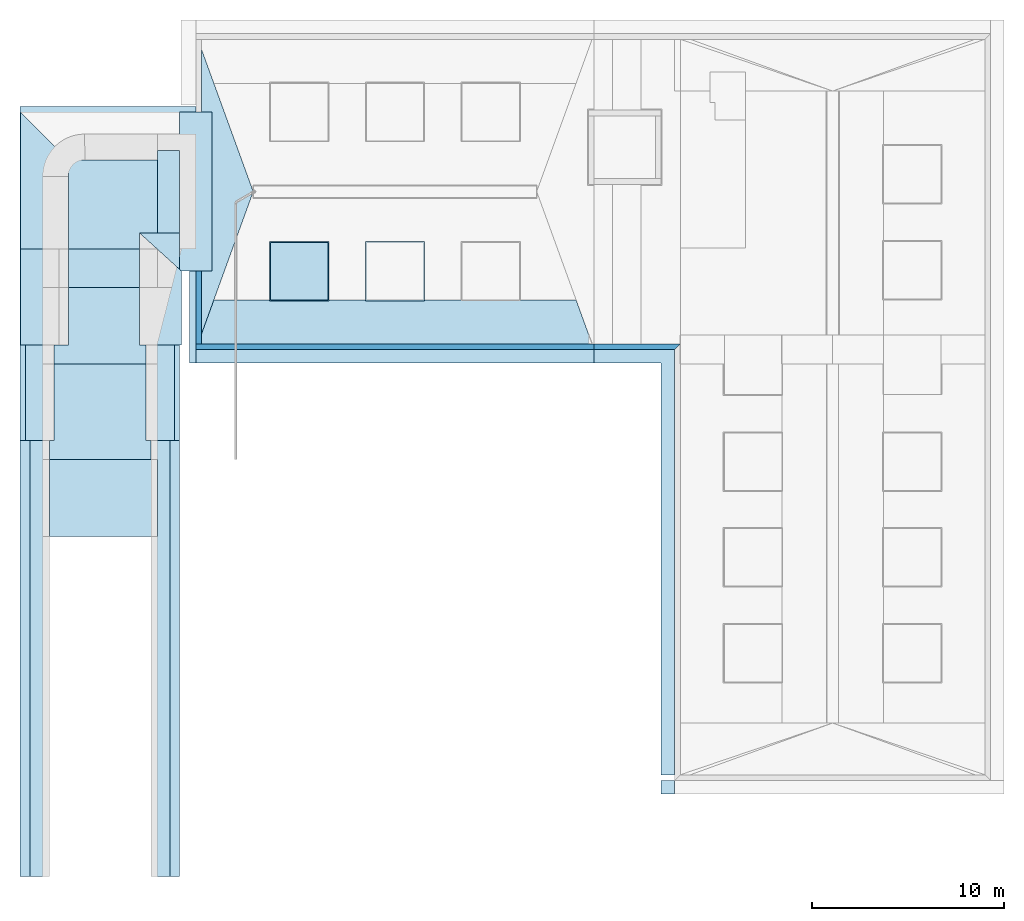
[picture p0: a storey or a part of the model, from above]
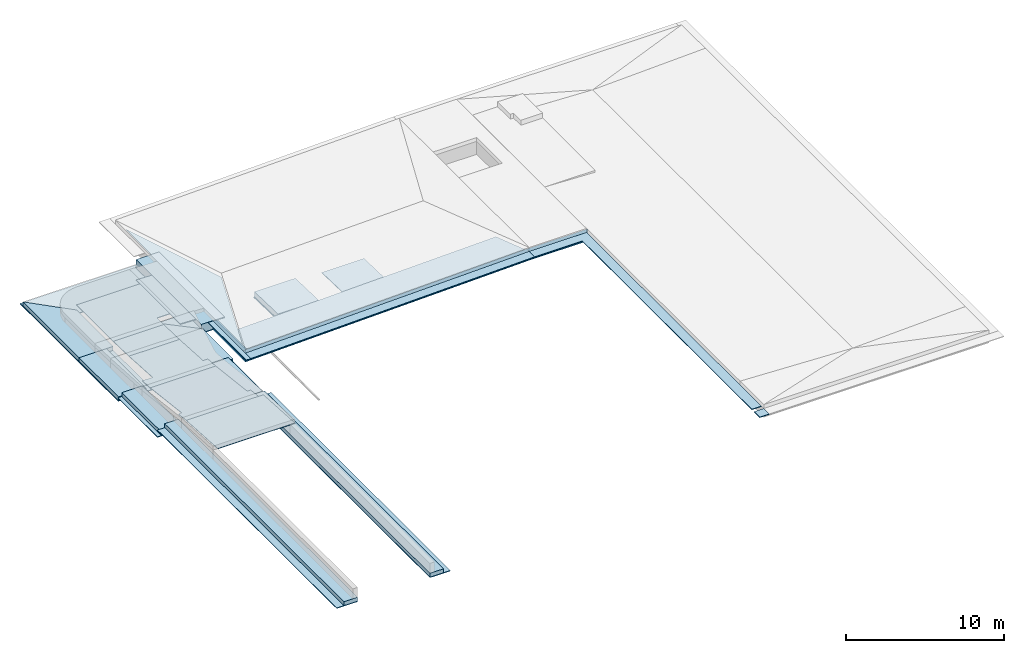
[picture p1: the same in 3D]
Properties of the parts of a building model (IFC4), part 7 of 8

# IfcWall: Innenwand Typ 09 310 (3)
03_Bausystem - Tragende Funktion: In Abklärung; Feuerwiderstand: In Abklärung; Luftschall: In Abklärung; U-Wert: In Abklärung; Umbau-Status: Neubau; Mehrschichtiger Aufbau: Beton bewehrt; Kalkzementputz Aussen
Massivbau Ortbeton - Ortbeton Druckfestigkeitsklasse: In Abklärung; Ortbeton Expositionsklasse: In Abklärung; Ortbeton Grösstkorn - mm: Dmax 32; Ortbeton Chloridgehaltsklasse: Cl 0.10; Ortbeton Konsistenzklasse: C3; Ortbeton Recyclingbeton: In Abklärung; Ortbeton Oberflächenausführung: In Abklärung; Ortbeton Oberflächenklasse - BOK: In Abklärung; Ortbeton Schalungstyp: In Abklärung; Ortbeton Dreikantleisten - mm: In Abklärung; Ortbeton Bew. Überdeckung oben - mm: In Abklärung; Ortbeton Bew. Überdeckung unten - mm: In Abklärung; Ortbeton Bew. Überdeckung aussen - mm: In Abklärung; Ortbeton Bew. Überdeckung innen - mm: In Abklärung; Ortbeton Bewehrungsgehalt - kg/m3: In Abklärung
02_Mengen - Stärke - m: 0.31
00_Datenstruktur - BIM Base Version: 4.0.0; Kundenergänzungen Version: v01; CAD Werkzeug Typ: Wand; Klassifizierung: Innenwand Ortbeton; Klassifizierung Level 0: Wand; Modellierungsrichtlinien: https://evolutbaugmbh.sharepoint.com/:b:/s/External/EciBgBMJMZlDgYCafV5wNokBvCJq9PUJAyVGz7O3vsjVrg?e=aLjLN9; Übersicht BIM Base: https://evolutbaugmbh.sharepoint.com/:b:/s/External/EfS4mJ9nZQpOhASXp0n2kW4B0K7N-vHKx-_6Crp5CxEFeg?e=Qu0M5d; Verbesserungsvorschläge BIM Base: https://forms.office.com/e/pcFhFfi5DW; Anleitung Mengen: https://evolutbaugmbh.sharepoint.com/:b:/s/External/ETgyOLO3JxJEqg9rbaRMLVEBHuWIRtkoMiJN1fISDr-3lw?e=E0LTiQ; Anleitung Eigenschaften: https://evolutbaugmbh.sharepoint.com/:b:/s/External/EQedjNXQkc1Btaftc01yAPUBtND9QzXFSH3-7sie6PGFww?e=wP4uf3; Release Notes: https://evolutbaugmbh.sharepoint.com/:b:/s/External/Eb41lwlDI71MhUVvor2V2mUBSaI-0tQK5U9oJAWxpCINuw?e=NtK3j6
Name | In | Höhe - m | Länge brutto - m | Fläche brutto - m2 | Volumen netto - m3 | Schalungsfläche Wände brutto - m2 | Kote Unterkante | Kote Oberkante
Wand-014 | 1.OG | 2.8 | 4.78 | 14.252 | 3.89006 | 28.504 | 2.9 | 5.7
Wand-014 | 2.OG | 2.5 | 5.09 | 12.725 | 3.47255 | 25.45 | 5.95 | 8.45
Wand-014 | Attika | 2.65 | 1.78 | 5.5385 | 1.22351 | 11.077 | 8.7 | 11.35

# IfcWall: Innenwand Typ 10 310 (15)
Classification: Innenwand Ortbeton (BIM Base by Evolut)
01_Leistungen und Kosten - Gebäude: In Abklärung; Elementpreis - CHF: 0; BKP: 211 - Baumeisterarbeiten; eBKP-H_Nr: C02.02; eBKP-H_Beschrieb: Innenwandkonstruktion
03_Bausystem - Tragende Funktion: In Abklärung; Feuerwiderstand: In Abklärung; Luftschall: In Abklärung; U-Wert: In Abklärung; Umbau-Status: Neubau; Mehrschichtiger Aufbau: Kalkzementputz Aussen; Beton bewehrt; Sichtbeton
Massivbau Ortbeton - Ortbeton Druckfestigkeitsklasse: In Abklärung; Ortbeton Expositionsklasse: In Abklärung; Ortbeton Grösstkorn - mm: Dmax 32; Ortbeton Chloridgehaltsklasse: Cl 0.10; Ortbeton Konsistenzklasse: C3; Ortbeton Recyclingbeton: In Abklärung; Ortbeton Oberflächenausführung: In Abklärung; Ortbeton Oberflächenklasse - BOK: In Abklärung; Ortbeton Schalungstyp: In Abklärung; Ortbeton Dreikantleisten - mm: In Abklärung; Ortbeton Bew. Überdeckung oben - mm: In Abklärung; Ortbeton Bew. Überdeckung unten - mm: In Abklärung; Ortbeton Bew. Überdeckung aussen - mm: In Abklärung; Ortbeton Bew. Überdeckung innen - mm: In Abklärung; Ortbeton Bewehrungsgehalt - kg/m3: In Abklärung
Bekleidung - Bekleidung Gipserarbeiten: In Abklärung; Bekleidung Malerarbeiten: In Abklärung; Bekleidung Putz: In Abklärung; Bekleidung Farbe: RAL / NCS
02_Mengen - Stärke - m: 0.31
05_Bauablauf - Bau-Nr.: In Abklärung; Bauablauf Etappe: In Abklärung; Bauablauf Verbauungsort: In Abklärung; Bauablauf Start Ausführung: In Abklärung; Bauablauf Ende Ausführung: In Abklärung
00_Datenstruktur - BIM Base Version: 4.0.0; Kundenergänzungen Version: v01; CAD Werkzeug Typ: Wand; Klassifizierung: Innenwand Ortbeton; Klassifizierung Level 0: Wand; Modellierungsrichtlinien: https://evolutbaugmbh.sharepoint.com/:b:/s/External/EciBgBMJMZlDgYCafV5wNokBvCJq9PUJAyVGz7O3vsjVrg?e=aLjLN9; Übersicht BIM Base: https://evolutbaugmbh.sharepoint.com/:b:/s/External/EfS4mJ9nZQpOhASXp0n2kW4B0K7N-vHKx-_6Crp5CxEFeg?e=Qu0M5d; Verbesserungsvorschläge BIM Base: https://forms.office.com/e/pcFhFfi5DW; Anleitung Mengen: https://evolutbaugmbh.sharepoint.com/:b:/s/External/ETgyOLO3JxJEqg9rbaRMLVEBHuWIRtkoMiJN1fISDr-3lw?e=E0LTiQ; Anleitung Eigenschaften: https://evolutbaugmbh.sharepoint.com/:b:/s/External/EQedjNXQkc1Btaftc01yAPUBtND9QzXFSH3-7sie6PGFww?e=wP4uf3; Release Notes: https://evolutbaugmbh.sharepoint.com/:b:/s/External/Eb41lwlDI71MhUVvor2V2mUBSaI-0tQK5U9oJAWxpCINuw?e=NtK3j6
Name | In | Höhe - m | Länge brutto - m | Fläche brutto - m2 | Volumen netto - m3 | Schalungsfläche Wände brutto - m2 | Kote Unterkante | Kote Oberkante
Wand-014 | EG | 2.9 | 2.51 | 7.279 | 2.01199 | 14.558 | 0 | 2.9
Wand-014 | EG | 3.4 | 9.8 | 33.32 | 9.3417 | 66.64 | 0 | 3.4
Wand-014 | 1.OG | 3.4 | 2.519 | 8.5646 | 2.35914 | 17.1292 | 2.9 | 6.3
Wand-014 | 1.OG | 2.6 | 3.52 | 9.152 | 1.837 | 18.304 | 3.05 | 5.65
Wand-014 | 1.OG | 2.9 | 9.8 | 28.345 | 7.8459 | 56.69 | 3.4 | 6.3
Wand-014 | 1.OG | 2.8 | 2.501 | 6.9408 | 2.10557 | 13.8816 | 2.9 | 5.7
Wand-014 | 1.OG | 2.75 | 2.29 | 6.2675 | 0.938095 | 12.535 | 2.9 | 5.65
Wand-014 | 2.OG | 2.9 | 9.8 | 28.42 | 7.4534 | 56.84 | 6.3 | 9.2
Wand-014 | 2.OG | 2.9 | 2.519 | 7.9716 | 2.39538 | 15.9432 | 6.3 | 9.2
Wand-014 | 2.OG | 2.75 | 2.29 | 6.2975 | 1.12744 | 12.595 | 5.8 | 8.55
Wand-014 | 2.OG | 2.6 | 3.52 | 9.121 | 1.83288 | 18.242 | 5.95 | 8.55
Wand-014 | 2.OG | 2.5 | 2.191 | 6.2525 | 1.89397 | 12.505 | 5.95 | 8.45
Wand-014 | Attika | 3.25 | 3.52 | 11.44 | 2.6871 | 22.88 | 8.85 | 12.1
Wand-014 | Attika | 3.4 | 2.501 | 8.5034 | 2.3373 | 17.0068 | 8.7 | 12.1
Wand-014 | Attika | 3.4 | 2.29 | 7.786 | 1.33077 | 15.572 | 8.7 | 12.1

# IfcWall: Innenwand Typ 11 250 (2)
In: Attika
Classification: Innenwand Ortbeton (BIM Base by Evolut); Material: Beton bewehrt
01_Leistungen und Kosten - Gebäude: In Abklärung; Elementpreis - CHF: 0; BKP: 211 - Baumeisterarbeiten; eBKP-H_Nr: C02.02; eBKP-H_Beschrieb: Innenwandkonstruktion
05_Bauablauf - Bau-Nr.: In Abklärung; Bauablauf Etappe: In Abklärung; Bauablauf Verbauungsort: In Abklärung; Bauablauf Start Ausführung: In Abklärung; Bauablauf Ende Ausführung: In Abklärung
03_Bausystem - Tragende Funktion: In Abklärung; Feuerwiderstand: In Abklärung; Luftschall: In Abklärung; U-Wert: In Abklärung; Umbau-Status: Neubau; Mehrschichtiger Aufbau: Beton bewehrt
Bekleidung - Bekleidung Gipserarbeiten: In Abklärung; Bekleidung Malerarbeiten: In Abklärung; Bekleidung Putz: In Abklärung; Bekleidung Farbe: RAL / NCS
Massivbau Ortbeton - Ortbeton Druckfestigkeitsklasse: In Abklärung; Ortbeton Expositionsklasse: In Abklärung; Ortbeton Grösstkorn - mm: Dmax 32; Ortbeton Chloridgehaltsklasse: Cl 0.10; Ortbeton Konsistenzklasse: C3; Ortbeton Recyclingbeton: In Abklärung; Ortbeton Oberflächenausführung: In Abklärung; Ortbeton Oberflächenklasse - BOK: In Abklärung; Ortbeton Schalungstyp: In Abklärung; Ortbeton Dreikantleisten - mm: In Abklärung; Ortbeton Bew. Überdeckung oben - mm: In Abklärung; Ortbeton Bew. Überdeckung unten - mm: In Abklärung; Ortbeton Bew. Überdeckung aussen - mm: In Abklärung; Ortbeton Bew. Überdeckung innen - mm: In Abklärung; Ortbeton Bewehrungsgehalt - kg/m3: In Abklärung
02_Mengen - Höhe - m: 0.4; Stärke - m: 0.25; Kote Unterkante: 8.7; Kote Oberkante: 9.1
00_Datenstruktur - BIM Base Version: 4.0.0; Kundenergänzungen Version: v01; CAD Werkzeug Typ: Wand; Klassifizierung: Innenwand Ortbeton; Klassifizierung Level 0: Wand; Modellierungsrichtlinien: https://evolutbaugmbh.sharepoint.com/:b:/s/External/EciBgBMJMZlDgYCafV5wNokBvCJq9PUJAyVGz7O3vsjVrg?e=aLjLN9; Übersicht BIM Base: https://evolutbaugmbh.sharepoint.com/:b:/s/External/EfS4mJ9nZQpOhASXp0n2kW4B0K7N-vHKx-_6Crp5CxEFeg?e=Qu0M5d; Verbesserungsvorschläge BIM Base: https://forms.office.com/e/pcFhFfi5DW; Anleitung Mengen: https://evolutbaugmbh.sharepoint.com/:b:/s/External/ETgyOLO3JxJEqg9rbaRMLVEBHuWIRtkoMiJN1fISDr-3lw?e=E0LTiQ; Anleitung Eigenschaften: https://evolutbaugmbh.sharepoint.com/:b:/s/External/EQedjNXQkc1Btaftc01yAPUBtND9QzXFSH3-7sie6PGFww?e=wP4uf3; Release Notes: https://evolutbaugmbh.sharepoint.com/:b:/s/External/Eb41lwlDI71MhUVvor2V2mUBSaI-0tQK5U9oJAWxpCINuw?e=NtK3j6
Name | Länge brutto - m | Fläche brutto - m2 | Volumen netto - m3 | Schalungsfläche Wände brutto - m2
Wand-015 | 2.825 | 1.21 | 0.2775 | 2.42
Wand-014 | 1.7 | 0.68 | 0.17 | 1.36

# IfcWall: Trennwand Typ 01 186 (12)
Classification: Trennwand Holzständer (BIM Base by Evolut)
01_Leistungen und Kosten - Gebäude: In Abklärung; Elementpreis - CHF: 0; BKP: 214 - Montagebau in Holz; eBKP-H_Nr: C02.02; eBKP-H_Beschrieb: Innenwandkonstruktion
05_Bauablauf - Bau-Nr.: In Abklärung; Bauablauf Etappe: In Abklärung; Bauablauf Verbauungsort: In Abklärung; Bauablauf Start Ausführung: In Abklärung; Bauablauf Ende Ausführung: In Abklärung
03_Bausystem - Tragende Funktion: In Abklärung; Feuerwiderstand: In Abklärung; Luftschall: In Abklärung; U-Wert: In Abklärung; Umbau-Status: Neubau; Mehrschichtiger Aufbau: Kalkzementputz Aussen; Gipskartonplatte GKP; Gipsfaserplatte GFP; Ständer Konstruktion gedämmt; Dämmung Innen
Holzbau - Holzbau Anschluss Massivbau vertikal: In Abklärung; Holzbau Anschluss Massivbau horizontal: In Abklärung; Holzbau Durchstanzung: In Abklärung; Holzbau Kapselung: In Abklärung; Holzbau Sonderelement: In Abklärung
Bekleidung - Bekleidung Gipserarbeiten: In Abklärung; Bekleidung Malerarbeiten: In Abklärung; Bekleidung Putz: In Abklärung; Bekleidung Farbe: RAL / NCS
02_Mengen - Stärke - m: 0.186
00_Datenstruktur - BIM Base Version: 4.0.0; Kundenergänzungen Version: v01; CAD Werkzeug Typ: Wand; Klassifizierung: Trennwand Holzständer; Klassifizierung Level 0: Wand; Modellierungsrichtlinien: https://evolutbaugmbh.sharepoint.com/:b:/s/External/EciBgBMJMZlDgYCafV5wNokBvCJq9PUJAyVGz7O3vsjVrg?e=aLjLN9; Übersicht BIM Base: https://evolutbaugmbh.sharepoint.com/:b:/s/External/EfS4mJ9nZQpOhASXp0n2kW4B0K7N-vHKx-_6Crp5CxEFeg?e=Qu0M5d; Verbesserungsvorschläge BIM Base: https://forms.office.com/e/pcFhFfi5DW; Anleitung Mengen: https://evolutbaugmbh.sharepoint.com/:b:/s/External/ETgyOLO3JxJEqg9rbaRMLVEBHuWIRtkoMiJN1fISDr-3lw?e=E0LTiQ; Anleitung Eigenschaften: https://evolutbaugmbh.sharepoint.com/:b:/s/External/EQedjNXQkc1Btaftc01yAPUBtND9QzXFSH3-7sie6PGFww?e=wP4uf3; Release Notes: https://evolutbaugmbh.sharepoint.com/:b:/s/External/Eb41lwlDI71MhUVvor2V2mUBSaI-0tQK5U9oJAWxpCINuw?e=NtK3j6
Name | In | Höhe - m | Länge brutto - m | Fläche brutto - m2 | Volumen netto - m3 | Kote Unterkante | Kote Oberkante
Wand-014 | EG | 3.4 | 7.307 | 24.8438 | 4.23838 | 0 | 3.4
Wand-014 | EG | 3.4 | 7.121 | 24.1184 | 4.11246 | 0 | 3.4
Wand-014 | EG | 2.9 | 4.334 | 12.5686 | 2.09931 | 0.5 | 3.4
Wand-014 | EG | 2.9 | 4.148 | 12.0292 | 1.99476 | 0.5 | 3.4
Wand-014 | 1.OG | 2.9 | 7.121 | 20.6509 | 3.48149 | 3.4 | 6.3
Wand-014 | 1.OG | 2.9 | 8.077 | 23.4233 | 3.91109 | 3.4 | 6.3
Wand-014 | 1.OG | 2.9 | 8.263 | 23.9627 | 4.04352 | 3.4 | 6.3
Wand-014 | 1.OG | 2.9 | 7.307 | 21.1903 | 3.60529 | 3.4 | 6.3
Wand-014 | 2.OG | 2.9 | 7.006 | 20.6509 | 3.43008 | 6.3 | 9.2
Wand-014 | 2.OG | 2.9 | 4.334 | 12.5686 | 2.084 | 6.3 | 9.2
Wand-014 | 2.OG | 2.9 | 7.192 | 21.1903 | 3.54606 | 6.3 | 9.2
Wand-014 | 2.OG | 2.9 | 4.148 | 12.0292 | 1.97644 | 6.3 | 9.2

# IfcWall: Trennwand Typ 02 - kein Putz 190 (10)
Classification: Trennwand Holzständer (BIM Base by Evolut)
01_Leistungen und Kosten - Gebäude: In Abklärung; Elementpreis - CHF: 0; BKP: 214 - Montagebau in Holz; eBKP-H_Nr: C02.02; eBKP-H_Beschrieb: Innenwandkonstruktion
03_Bausystem - Tragende Funktion: In Abklärung; Feuerwiderstand: In Abklärung; Luftschall: In Abklärung; U-Wert: In Abklärung; Umbau-Status: Neubau; Mehrschichtiger Aufbau: MW, Backstein; Dämmung Innen
05_Bauablauf - Bau-Nr.: In Abklärung; Bauablauf Etappe: In Abklärung; Bauablauf Verbauungsort: In Abklärung; Bauablauf Start Ausführung: In Abklärung; Bauablauf Ende Ausführung: In Abklärung
Holzbau - Holzbau Anschluss Massivbau vertikal: In Abklärung; Holzbau Anschluss Massivbau horizontal: In Abklärung; Holzbau Durchstanzung: In Abklärung; Holzbau Kapselung: In Abklärung; Holzbau Sonderelement: In Abklärung
Bekleidung - Bekleidung Gipserarbeiten: In Abklärung; Bekleidung Malerarbeiten: In Abklärung; Bekleidung Putz: In Abklärung; Bekleidung Farbe: RAL / NCS
02_Mengen - Höhe - m: 2.65; Stärke - m: 0.19
00_Datenstruktur - BIM Base Version: 4.0.0; Kundenergänzungen Version: v01; CAD Werkzeug Typ: Wand; Klassifizierung: Trennwand Holzständer; Klassifizierung Level 0: Wand; Modellierungsrichtlinien: https://evolutbaugmbh.sharepoint.com/:b:/s/External/EciBgBMJMZlDgYCafV5wNokBvCJq9PUJAyVGz7O3vsjVrg?e=aLjLN9; Übersicht BIM Base: https://evolutbaugmbh.sharepoint.com/:b:/s/External/EfS4mJ9nZQpOhASXp0n2kW4B0K7N-vHKx-_6Crp5CxEFeg?e=Qu0M5d; Verbesserungsvorschläge BIM Base: https://forms.office.com/e/pcFhFfi5DW; Anleitung Mengen: https://evolutbaugmbh.sharepoint.com/:b:/s/External/ETgyOLO3JxJEqg9rbaRMLVEBHuWIRtkoMiJN1fISDr-3lw?e=E0LTiQ; Anleitung Eigenschaften: https://evolutbaugmbh.sharepoint.com/:b:/s/External/EQedjNXQkc1Btaftc01yAPUBtND9QzXFSH3-7sie6PGFww?e=wP4uf3; Release Notes: https://evolutbaugmbh.sharepoint.com/:b:/s/External/Eb41lwlDI71MhUVvor2V2mUBSaI-0tQK5U9oJAWxpCINuw?e=NtK3j6
Name | In | Länge brutto - m | Fläche brutto - m2 | Volumen netto - m3 | Kote Unterkante | Kote Oberkante
Wand-015 | 1.OG | 4.133 | 11.4559 | 2.05119 | 2.9 | 5.55
Wand-014 | 1.OG | 3.793 | 10.555 | 1.82339 | 2.9 | 5.55
Wand-015 | 1.OG | 3.59822 | 10.0388 | 1.85374 | 2.9 | 5.55
Wand-015 | 1.OG | 3.59822 | 10.0653 | 1.79012 | 2.9 | 5.55
Wand-014 | 2.OG | 3.793 | 10.555 | 1.82339 | 5.8 | 8.45
Wand-015 | 2.OG | 3.59822 | 10.0388 | 1.85374 | 5.8 | 8.45
Wand-015 | 2.OG | 3.59822 | 10.0653 | 1.79012 | 5.8 | 8.45
Wand-015 | 2.OG | 4.133 | 11.4559 | 2.05119 | 5.8 | 8.45
Wand-014 | Attika | 3.793 | 10.5815 | 1.84591 | 8.7 | 11.35
Wand-015 | Attika | 5.315 | 14.0848 | 2.59634 | 8.7 | 11.35

# IfcWall: Trennwand Typ 03 - verputzt 200 (22)
Classification: Trennwand Holzständer (BIM Base by Evolut)
01_Leistungen und Kosten - Gebäude: In Abklärung; Elementpreis - CHF: 0; BKP: 214 - Montagebau in Holz; eBKP-H_Nr: C02.02; eBKP-H_Beschrieb: Innenwandkonstruktion
05_Bauablauf - Bau-Nr.: In Abklärung; Bauablauf Etappe: In Abklärung; Bauablauf Verbauungsort: In Abklärung; Bauablauf Start Ausführung: In Abklärung; Bauablauf Ende Ausführung: In Abklärung
03_Bausystem - Tragende Funktion: In Abklärung; Feuerwiderstand: In Abklärung; Luftschall: In Abklärung; U-Wert: In Abklärung; Umbau-Status: Neubau; Mehrschichtiger Aufbau: Kalkzementputz Aussen; MW, Backstein; Dämmung Innen
Holzbau - Holzbau Anschluss Massivbau vertikal: In Abklärung; Holzbau Anschluss Massivbau horizontal: In Abklärung; Holzbau Durchstanzung: In Abklärung; Holzbau Kapselung: In Abklärung; Holzbau Sonderelement: In Abklärung
Bekleidung - Bekleidung Gipserarbeiten: In Abklärung; Bekleidung Malerarbeiten: In Abklärung; Bekleidung Putz: In Abklärung; Bekleidung Farbe: RAL / NCS
00_Datenstruktur - BIM Base Version: 4.0.0; Kundenergänzungen Version: v01; CAD Werkzeug Typ: Wand; Klassifizierung: Trennwand Holzständer; Klassifizierung Level 0: Wand; Modellierungsrichtlinien: https://evolutbaugmbh.sharepoint.com/:b:/s/External/EciBgBMJMZlDgYCafV5wNokBvCJq9PUJAyVGz7O3vsjVrg?e=aLjLN9; Übersicht BIM Base: https://evolutbaugmbh.sharepoint.com/:b:/s/External/EfS4mJ9nZQpOhASXp0n2kW4B0K7N-vHKx-_6Crp5CxEFeg?e=Qu0M5d; Verbesserungsvorschläge BIM Base: https://forms.office.com/e/pcFhFfi5DW; Anleitung Mengen: https://evolutbaugmbh.sharepoint.com/:b:/s/External/ETgyOLO3JxJEqg9rbaRMLVEBHuWIRtkoMiJN1fISDr-3lw?e=E0LTiQ; Anleitung Eigenschaften: https://evolutbaugmbh.sharepoint.com/:b:/s/External/EQedjNXQkc1Btaftc01yAPUBtND9QzXFSH3-7sie6PGFww?e=wP4uf3; Release Notes: https://evolutbaugmbh.sharepoint.com/:b:/s/External/Eb41lwlDI71MhUVvor2V2mUBSaI-0tQK5U9oJAWxpCINuw?e=NtK3j6
02_Mengen - Höhe - m: 2.65; Stärke - m: 0.2
Name | In | Länge brutto - m | Fläche brutto - m2 | Volumen netto - m3 | Kote Unterkante | Kote Oberkante
Wand-014 | 1.OG | 4.133 | 11.4559 | 2.15949 | 2.9 | 5.55
Wand-015 | 1.OG | 4.90678 | 13.003 | 2.48517 | 2.9 | 5.55
Wand-014 | 1.OG | 2.885 | 8.14875 | 1.56606 | 2.9 | 5.55
Wand-014 | 1.OG | 3.9 | 11.13 | 1.9539 | 2.9 | 5.55
Wand-014 | 1.OG | 4.71678 | 12.4995 | 2.37624 | 2.9 | 5.55
Wand-015 | 1.OG | 3.803 | 10.5815 | 2.03934 | 2.9 | 5.55
Wand-016 | 1.OG | 2.875 | 8.14875 | 1.50219 | 2.9 | 5.55
Wand-017 | 1.OG | 3.7 | 10.6 | 1.8461 | 2.9 | 5.55
Wand-014 | 2.OG | 2.885 | 8.14875 | 1.56606 | 5.8 | 8.45
Wand-015 | 2.OG | 3.803 | 10.5815 | 2.03934 | 5.8 | 8.45
Wand-016 | 2.OG | 2.875 | 8.14875 | 1.50219 | 5.8 | 8.45
Wand-017 | 2.OG | 3.7 | 10.6 | 1.80546 | 5.8 | 8.45
Wand-015 | 2.OG | 4.90678 | 13.003 | 2.48517 | 5.8 | 8.45
Wand-014 | 2.OG | 4.133 | 11.4559 | 2.15949 | 5.8 | 8.45
Wand-014 | 2.OG | 3.9 | 11.13 | 1.91565 | 5.8 | 8.45
Wand-014 | 2.OG | 4.71678 | 12.4995 | 2.37624 | 5.8 | 8.45
Wand-014 | Attika | 2.885 | 8.14875 | 1.58355 | 8.7 | 11.35
Wand-014 | Attika | 3.9 | 10.935 | 1.96659 | 8.7 | 11.35
Wand-014 | Attika | 5.505 | 14.5883 | 2.88974 | 8.7 | 11.35
Wand-015 | Attika | 3.803 | 10.5815 | 2.06234 | 8.7 | 11.35
Wand-016 | Attika | 2.875 | 8.14875 | 1.51944 | 8.7 | 11.35
Wand-017 | Attika | 3.7 | 10.405 | 1.75383 | 8.7 | 11.35

# IfcWall: Vorsatzschale 01 115 (30)
Classification: Vorsatzwand Holzbau (BIM Base by Evolut)
05_Bauablauf - Bau-Nr.: In Abklärung; Bauablauf Etappe: In Abklärung; Bauablauf Verbauungsort: In Abklärung; Bauablauf Start Ausführung: In Abklärung; Bauablauf Ende Ausführung: In Abklärung
03_Bausystem - Tragende Funktion: In Abklärung; Feuerwiderstand: In Abklärung; Luftschall: In Abklärung; U-Wert: In Abklärung; Umbau-Status: Neubau; Mehrschichtiger Aufbau: Kalkzementputz Aussen; Gipskartonplatte GKP; Gipskartonplatte GKP; Ständer Konstruktion gedämmt
Holzbau - Holzbau Anschluss Massivbau vertikal: In Abklärung; Holzbau Anschluss Massivbau horizontal: In Abklärung; Holzbau Durchstanzung: In Abklärung; Holzbau Kapselung: In Abklärung; Holzbau Sonderelement: In Abklärung
Bekleidung - Bekleidung Gipserarbeiten: In Abklärung; Bekleidung Malerarbeiten: In Abklärung; Bekleidung Putz: In Abklärung; Bekleidung Farbe: RAL / NCS
01_Leistungen und Kosten - Gebäude: In Abklärung; Elementpreis - CHF: 0; BKP: 214 - Montagebau in Holz; eBKP-H_Nr: C02.02; eBKP-H_Beschrieb: Innenwandkonstruktion
02_Mengen - Stärke - m: 0.115
00_Datenstruktur - BIM Base Version: 4.0.0; Kundenergänzungen Version: v01; CAD Werkzeug Typ: Wand; Klassifizierung: Vorsatzwand Holzbau; Klassifizierung Level 0: Wand; Modellierungsrichtlinien: https://evolutbaugmbh.sharepoint.com/:b:/s/External/EciBgBMJMZlDgYCafV5wNokBvCJq9PUJAyVGz7O3vsjVrg?e=aLjLN9; Übersicht BIM Base: https://evolutbaugmbh.sharepoint.com/:b:/s/External/EfS4mJ9nZQpOhASXp0n2kW4B0K7N-vHKx-_6Crp5CxEFeg?e=Qu0M5d; Verbesserungsvorschläge BIM Base: https://forms.office.com/e/pcFhFfi5DW; Anleitung Mengen: https://evolutbaugmbh.sharepoint.com/:b:/s/External/ETgyOLO3JxJEqg9rbaRMLVEBHuWIRtkoMiJN1fISDr-3lw?e=E0LTiQ; Anleitung Eigenschaften: https://evolutbaugmbh.sharepoint.com/:b:/s/External/EQedjNXQkc1Btaftc01yAPUBtND9QzXFSH3-7sie6PGFww?e=wP4uf3; Release Notes: https://evolutbaugmbh.sharepoint.com/:b:/s/External/Eb41lwlDI71MhUVvor2V2mUBSaI-0tQK5U9oJAWxpCINuw?e=NtK3j6
Name | In | Höhe - m | Länge brutto - m | Fläche brutto - m2 | Fläche netto - m2 | Volumen netto - m3 | Kote Unterkante | Kote Oberkante
Wand-014 | 1.OG | 2.65 | 3.44822 | 9.13779 | 8.92579 | 1.0158 | 2.9 | 5.55
Wand-014 | 1.OG | 2.65 | 3.963 | 10.5019 | 10.5019 | 1.19923 | 2.9 | 5.55
Wand-015 | 1.OG | 2.65 | 3.963 | 10.5019 | 10.2899 | 1.18117 | 2.9 | 5.55
Wand-014 | 1.OG | 2.8 | 4.53 | 13.6915 | 12.74 | 1.45776 | 2.9 | 5.7
Wand-014 | 1.OG | 2.65 | 3.59822 | 10.0653 | 9.56179 | 1.09394 | 2.9 | 5.55
Wand-014 | 1.OG | 2.65 | 3.59822 | 9.84004 | 9.56179 | 1.09394 | 2.9 | 5.55
Wand-014 | 1.OG | 2.8 | 3.35 | 9.38 | 9.38 | 1.07368 | 2.9 | 5.7
Wand-014 | 1.OG | 2.65 | 3.88278 | 10.2894 | 10.2894 | 1.17476 | 2.9 | 5.55
Wand-014 | 1.OG | 2.65 | 2.57147 | 6.81439 | 6.60239 | 0.757105 | 2.9 | 5.55
Wand-014 | 1.OG | 2.65 | 2.74147 | 7.76839 | 7.26489 | 0.828725 | 2.9 | 5.55
Wand-014 | 2.OG | 2.5 | 1.955 | 5.63125 | 4.9125 | 0.561755 | 5.95 | 8.6
Wand-014 | 2.OG | 3.15 | 2.575 | 9.21 | 8.14275 | 0.932264 | 5.95 | 9.25
Wand-014 | 2.OG | 2.65 | 3.59822 | 10.0653 | 9.56179 | 1.09394 | 5.8 | 8.45
Wand-014 | 2.OG | 2.5 | 3.34 | 8.851 | 8.35 | 0.95524 | 5.95 | 8.6
Wand-014 | 2.OG | 2.644 | 19.101 | 52.1635 | 42.8759 | 4.88316 | 6.3 | 8.944
Wand-014 | 2.OG | 2.65 | 3.59822 | 9.84004 | 9.56179 | 1.09394 | 5.8 | 8.45
Wand-014 | 2.OG | 2.65 | 2.57147 | 6.81439 | 6.60239 | 0.757105 | 5.8 | 8.45
Wand-014 | 2.OG | 2.65 | 2.74147 | 7.76839 | 7.26489 | 0.828725 | 5.8 | 8.45
Wand-014 | 2.OG | 2.65 | 3.88278 | 10.2894 | 10.2894 | 1.17476 | 5.8 | 8.45
Wand-014 | 2.OG | 2.65 | 3.963 | 10.5019 | 10.5019 | 1.19921 | 5.8 | 8.45
Wand-015 | 2.OG | 2.65 | 3.963 | 10.5019 | 10.2899 | 1.18117 | 5.8 | 8.45
Wand-014 | 2.OG | 2.65 | 3.44822 | 9.13779 | 8.92579 | 1.0158 | 5.8 | 8.45
Wand-014 | Attika | 2.65 | 1.655 | 4.83625 | 4.41225 | 0.507144 | 8.7 | 11.35
Wand-014 | Attika | 2 | 2.875 | 6.15 | 5.77 | 0.66335 | 9.35 | 11.35
Wand-014 | Attika | 2.65 | 5.115 | 14.0848 | 13.5813 | 1.55391 | 8.7 | 11.35
Wand-014 | Attika | 2.65 | 3.34 | 8.851 | 8.851 | 1.01285 | 8.7 | 11.35
Wand-014 | Attika | 2.65 | 2.57147 | 6.81439 | 6.60239 | 0.75342 | 8.7 | 11.35
Wand-014 | Attika | 2.65 | 3.13978 | 8.32041 | 8.32041 | 0.943799 | 8.7 | 11.35
Wand-014 | Attika | 2.65 | 2.74147 | 7.76839 | 7.26489 | 0.828725 | 8.7 | 11.35
Wand-014 | Attika | 2.65 | 3.59822 | 9.84004 | 9.56179 | 1.09394 | 8.7 | 11.35

# IfcWindow: 1-Flügelfenster 27 (10)
Type - PartitioningType: SINGLE_PANEL
Classification: Aussenfenster + Zargen aussen + Fensterbank + Sonnenschutz (BIM Base by Evolut)
05_Bauablauf - Bau-Nr.: In Abklärung; Bauablauf Etappe: In Abklärung; Bauablauf Verbauungsort: In Abklärung; Bauablauf Start Ausführung: In Abklärung; Bauablauf Ende Ausführung: In Abklärung
01_Leistungen und Kosten - Gebäude: In Abklärung; Elementpreis - CHF: 0; BKP: 221 - Fenster, Aussentüren, Tore; eBKP-H_Nr: E03.01; eBKP-H_Beschrieb: Fenster
03_Bausystem - Feuerwiderstand: In Abklärung; Umbau-Status: Neubau
Fenster - Fenster Art: In Abklärung; Fenster Einsatzsitation: In Abklärung; Fenster g-Wert - %: In Abklärung; Fenster Ug-Wert Glas - W/m2K: In Abklärung; Fenster Schallschutzglas R'w+Ctr - dB: In Abklärung; Fenster Sicherheitsglas Personenschutz: In Abklärung; Fenster Sicherheitsglas Absturzhemmung: In Abklärung; Fenster Ornamentglas: In Abklärung; Fenster Insektenschutzgitter: In Abklärung; Fenster Einbruchschutz: In Abklärung; Fenster Öffnungsbegrenzung: In Abklärung; Fenster Öffnungsüberwachung: In Abklärung; Fenster Sitzfenster: In Abklärung; Fenster Schwelle barrierefrei: In Abklärung; Fenster Zuziehgriff + Schnäpper: In Abklärung; Fenster Zuziehgriff Farbe: In Abklärung; Fenster Griffmontage: In Abklärung; Fenster Grifftyp: In Abklärung; Fenster Griffoberfläche: In Abklärung; Fenster Beschlag: In Abklärung; Fenster Farbe Flügel innen: RAL / NCS; Fenster Farbe Flügel aussen: RAL / NCS; Fenster Farbe Rahmen innen: RAL / NCS; Fenster Farbe Rahmen aussen: RAL / NCS; Fenster Farbe Wetterschenkel: RAL / NCS; Fenster Detailbezeichnung links: In Abklärung; Fenster Detailbezeichnung rechts: In Abklärung; Fenster Detailbezeichnung oben: In Abklärung; Fenster Detailbezeichnung unten: In Abklärung; Fenster Detailbezeichnung Mittelpartie: In Abklärung; Fenster Typ: In Abklärung
Metallzarge - Metallzargen Verbindungsart: In Abklärung; Metallzargen Oberflächenbehandlung: In Abklärung; Metallzargen Farbe: In Abklärung; Metallzargen Sturzart: In Abklärung; Metallzargen Storenkasten Breite - mm: In Abklärung; Metallzargen Storenkasten Höhe - mm: In Abklärung; Metallzargen Laibungen: In Abklärung; Metallzargen Tiefe - mm: In Abklärung; Metallzargen Spiegelbreite - mm: In Abklärung; Metallzargen Fensterbank: In Abklärung; Metallzargen Fensterbankneigung - in Grad: In Abklärung
Fensterbank - Fensterbank Material: In Abklärung; Fensterbank Oberflächenbehandlung: In Abklärung; Fensterbank Farbe: RAL / NCS
Sonnenschutz - Sonnenschutz Typ: In Abklärung; Sonnenschutz Steuerung: In Abklärung; Sonnenschutz Antrieb: In Abklärung; Sonnenschutz Farbe: RAL / NCS
00_Datenstruktur - BIM Base Version: 4.0.0; Kundenergänzungen Version: v01; CAD Werkzeug Typ: Fenster; Klassifizierung: Aussenfenster + Zargen aussen + Fensterbank + Sonnenschutz; Klassifizierung Level 0: Fenster; Modellierungsrichtlinien: https://evolutbaugmbh.sharepoint.com/:b:/s/External/EciBgBMJMZlDgYCafV5wNokBvCJq9PUJAyVGz7O3vsjVrg?e=aLjLN9; Übersicht BIM Base: https://evolutbaugmbh.sharepoint.com/:b:/s/External/EfS4mJ9nZQpOhASXp0n2kW4B0K7N-vHKx-_6Crp5CxEFeg?e=Qu0M5d; Verbesserungsvorschläge BIM Base: https://forms.office.com/e/pcFhFfi5DW; Anleitung Mengen: https://evolutbaugmbh.sharepoint.com/:b:/s/External/ETgyOLO3JxJEqg9rbaRMLVEBHuWIRtkoMiJN1fISDr-3lw?e=E0LTiQ; Anleitung Eigenschaften: https://evolutbaugmbh.sharepoint.com/:b:/s/External/EQedjNXQkc1Btaftc01yAPUBtND9QzXFSH3-7sie6PGFww?e=wP4uf3; Release Notes: https://evolutbaugmbh.sharepoint.com/:b:/s/External/Eb41lwlDI71MhUVvor2V2mUBSaI-0tQK5U9oJAWxpCINuw?e=NtK3j6
Name | In | OverallHeight (mm) | OverallWidth (mm) | Wand Typ | Breite Lichtmass - m | Höhe Lichtmass - m | Fläche Lichtmass - m2 | Höhe Mauerlicht - m | Breite Mauerlicht - m | Fläche Mauerlicht - m2 | Delta Höhe unten - m | Delta Hohe oben - m | Wandstärke - m | Kote Brüstung fertig - m | Kote Brüstung roh - m | Kote Sturz fertig - m | Kote Sturz roh - m
Fenster-004 | EG | 2122 | 1004 | Aussenwand Typ 05 | 0.8 | 1.96 | 1.568 | 2.122 | 1.004 | 2.13049 | 0.0684 | 0.0936 | 0.3 | 0.31 | 0.2416 | 2.27 | 2.3636
Fenster-004 | 1.OG | 2122 | 1004 | Aussenwand Typ 06 | 0.8 | 1.96 | 1.568 | 2.122 | 1.004 | 2.13049 | 0.0684 | 0.0936 | 0.31 | 3.21 | 3.1416 | 5.17 | 5.2636
Fenster-004 | 2.OG | 2122 | 1004 | Aussenwand Typ 06 | 0.8 | 1.96 | 1.568 | 2.122 | 1.004 | 2.13049 | 0.0684 | 0.0936 | 0.31 | 6.11 | 6.0416 | 8.07 | 8.1636
Fenster-004 | Attika | 2122 | 1004 | Aussenwand Typ 06 | 0.8 | 1.96 | 1.568 | 2.122 | 1.004 | 2.13049 | 0.06 | 0.102 | 0.31 | 9.01 | 8.95 | 10.97 | 11.072
6 x Fenster-004 | Dachaufsicht | 1131 | 1842 | Aussenwand Typ 01 | 1.6 | 0.95 | 1.52 | 1.131 | 1.842 | 2.0833 | 0.0776 | 0.1034 | 0.318 | 13.8648 | 13.7872 | 14.8148 | 14.9182

# IfcWindow: 2-Flügelfenster 1+1 27 (2)
In: EG
Type - ElementType: Fenster Typ 01 - 2 Flg.; PartitioningType: DOUBLE_PANEL_VERTICAL
OverallHeight: 2641 mm; OverallWidth: 2532 mm; Classification: Aussenfenster + Zargen aussen + Fensterbank + Sonnenschutz (BIM Base by Evolut)
01_Leistungen und Kosten - Gebäude: In Abklärung; Elementpreis - CHF: 0; BKP: 221 - Fenster, Aussentüren, Tore; eBKP-H_Nr: E03.01; eBKP-H_Beschrieb: Fenster
05_Bauablauf - Bau-Nr.: In Abklärung; Bauablauf Etappe: In Abklärung; Bauablauf Verbauungsort: In Abklärung; Bauablauf Start Ausführung: In Abklärung; Bauablauf Ende Ausführung: In Abklärung
03_Bausystem - Feuerwiderstand: In Abklärung; Umbau-Status: Neubau; Wand Typ: Aussenwand Typ 01
Fenster - Fenster Art: In Abklärung; Fenster Einsatzsitation: In Abklärung; Fenster g-Wert - %: In Abklärung; Fenster Ug-Wert Glas - W/m2K: In Abklärung; Fenster Schallschutzglas R'w+Ctr - dB: In Abklärung; Fenster Sicherheitsglas Personenschutz: In Abklärung; Fenster Sicherheitsglas Absturzhemmung: In Abklärung; Fenster Ornamentglas: In Abklärung; Fenster Insektenschutzgitter: In Abklärung; Fenster Einbruchschutz: In Abklärung; Fenster Öffnungsbegrenzung: In Abklärung; Fenster Öffnungsüberwachung: In Abklärung; Fenster Sitzfenster: In Abklärung; Fenster Schwelle barrierefrei: In Abklärung; Fenster Zuziehgriff + Schnäpper: In Abklärung; Fenster Zuziehgriff Farbe: In Abklärung; Fenster Griffmontage: In Abklärung; Fenster Grifftyp: In Abklärung; Fenster Griffoberfläche: In Abklärung; Fenster Beschlag: In Abklärung; Fenster Farbe Flügel innen: RAL / NCS; Fenster Farbe Flügel aussen: RAL / NCS; Fenster Farbe Rahmen innen: RAL / NCS; Fenster Farbe Rahmen aussen: RAL / NCS; Fenster Farbe Wetterschenkel: RAL / NCS; Fenster Detailbezeichnung links: In Abklärung; Fenster Detailbezeichnung rechts: In Abklärung; Fenster Detailbezeichnung oben: In Abklärung; Fenster Detailbezeichnung unten: In Abklärung; Fenster Detailbezeichnung Mittelpartie: In Abklärung; Fenster Typ: In Abklärung
Metallzarge - Metallzargen Verbindungsart: In Abklärung; Metallzargen Oberflächenbehandlung: In Abklärung; Metallzargen Farbe: In Abklärung; Metallzargen Sturzart: In Abklärung; Metallzargen Storenkasten Breite - mm: In Abklärung; Metallzargen Storenkasten Höhe - mm: In Abklärung; Metallzargen Laibungen: In Abklärung; Metallzargen Tiefe - mm: In Abklärung; Metallzargen Spiegelbreite - mm: In Abklärung; Metallzargen Fensterbank: In Abklärung; Metallzargen Fensterbankneigung - in Grad: In Abklärung
Fensterbank - Fensterbank Material: In Abklärung; Fensterbank Oberflächenbehandlung: In Abklärung; Fensterbank Farbe: RAL / NCS
Sonnenschutz - Sonnenschutz Typ: In Abklärung; Sonnenschutz Steuerung: In Abklärung; Sonnenschutz Antrieb: In Abklärung; Sonnenschutz Farbe: RAL / NCS
00_Datenstruktur - BIM Base Version: 4.0.0; Kundenergänzungen Version: v01; CAD Werkzeug Typ: Fenster; Klassifizierung: Aussenfenster + Zargen aussen + Fensterbank + Sonnenschutz; Klassifizierung Level 0: Fenster; Modellierungsrichtlinien: https://evolutbaugmbh.sharepoint.com/:b:/s/External/EciBgBMJMZlDgYCafV5wNokBvCJq9PUJAyVGz7O3vsjVrg?e=aLjLN9; Übersicht BIM Base: https://evolutbaugmbh.sharepoint.com/:b:/s/External/EfS4mJ9nZQpOhASXp0n2kW4B0K7N-vHKx-_6Crp5CxEFeg?e=Qu0M5d; Verbesserungsvorschläge BIM Base: https://forms.office.com/e/pcFhFfi5DW; Anleitung Mengen: https://evolutbaugmbh.sharepoint.com/:b:/s/External/ETgyOLO3JxJEqg9rbaRMLVEBHuWIRtkoMiJN1fISDr-3lw?e=E0LTiQ; Anleitung Eigenschaften: https://evolutbaugmbh.sharepoint.com/:b:/s/External/EQedjNXQkc1Btaftc01yAPUBtND9QzXFSH3-7sie6PGFww?e=wP4uf3; Release Notes: https://evolutbaugmbh.sharepoint.com/:b:/s/External/Eb41lwlDI71MhUVvor2V2mUBSaI-0tQK5U9oJAWxpCINuw?e=NtK3j6
02_Mengen - Breite Lichtmass - m: 2.29; Höhe Lichtmass - m: 2.31; Fläche Lichtmass - m2: 5.2899; Höhe Mauerlicht - m: 2.641; Breite Mauerlicht - m: 2.532; Fläche Mauerlicht - m2: 6.68701; Delta Höhe unten - m: 0.21; Delta Hohe oben - m: 0.121; Wandstärke - m: 0.318; Kote Brüstung fertig - m: 0.21; Kote Brüstung roh - m: 5.19885e-08; Kote Sturz fertig - m: 2.52; Kote Sturz roh - m: 2.641

# IfcWindow: 2-Flügelfenster 1+1 27 (105)
Type - PartitioningType: DOUBLE_PANEL_VERTICAL
Classification: Aussenfenster + Zargen aussen + Fensterbank + Sonnenschutz (BIM Base by Evolut)
01_Leistungen und Kosten - Gebäude: In Abklärung; Elementpreis - CHF: 0; BKP: 221 - Fenster, Aussentüren, Tore; eBKP-H_Nr: E03.01; eBKP-H_Beschrieb: Fenster
05_Bauablauf - Bau-Nr.: In Abklärung; Bauablauf Etappe: In Abklärung; Bauablauf Verbauungsort: In Abklärung; Bauablauf Start Ausführung: In Abklärung; Bauablauf Ende Ausführung: In Abklärung
03_Bausystem - Feuerwiderstand: In Abklärung; Umbau-Status: Neubau
Fenster - Fenster Art: In Abklärung; Fenster Einsatzsitation: In Abklärung; Fenster g-Wert - %: In Abklärung; Fenster Ug-Wert Glas - W/m2K: In Abklärung; Fenster Schallschutzglas R'w+Ctr - dB: In Abklärung; Fenster Sicherheitsglas Personenschutz: In Abklärung; Fenster Sicherheitsglas Absturzhemmung: In Abklärung; Fenster Ornamentglas: In Abklärung; Fenster Insektenschutzgitter: In Abklärung; Fenster Einbruchschutz: In Abklärung; Fenster Öffnungsbegrenzung: In Abklärung; Fenster Öffnungsüberwachung: In Abklärung; Fenster Sitzfenster: In Abklärung; Fenster Schwelle barrierefrei: In Abklärung; Fenster Zuziehgriff + Schnäpper: In Abklärung; Fenster Zuziehgriff Farbe: In Abklärung; Fenster Griffmontage: In Abklärung; Fenster Grifftyp: In Abklärung; Fenster Griffoberfläche: In Abklärung; Fenster Beschlag: In Abklärung; Fenster Farbe Flügel innen: RAL / NCS; Fenster Farbe Flügel aussen: RAL / NCS; Fenster Farbe Rahmen innen: RAL / NCS; Fenster Farbe Rahmen aussen: RAL / NCS; Fenster Farbe Wetterschenkel: RAL / NCS; Fenster Detailbezeichnung links: In Abklärung; Fenster Detailbezeichnung rechts: In Abklärung; Fenster Detailbezeichnung oben: In Abklärung; Fenster Detailbezeichnung unten: In Abklärung; Fenster Detailbezeichnung Mittelpartie: In Abklärung; Fenster Typ: In Abklärung
Metallzarge - Metallzargen Verbindungsart: In Abklärung; Metallzargen Oberflächenbehandlung: In Abklärung; Metallzargen Farbe: In Abklärung; Metallzargen Sturzart: In Abklärung; Metallzargen Storenkasten Breite - mm: In Abklärung; Metallzargen Storenkasten Höhe - mm: In Abklärung; Metallzargen Laibungen: In Abklärung; Metallzargen Tiefe - mm: In Abklärung; Metallzargen Spiegelbreite - mm: In Abklärung; Metallzargen Fensterbank: In Abklärung; Metallzargen Fensterbankneigung - in Grad: In Abklärung
Fensterbank - Fensterbank Material: In Abklärung; Fensterbank Oberflächenbehandlung: In Abklärung; Fensterbank Farbe: RAL / NCS
Sonnenschutz - Sonnenschutz Typ: In Abklärung; Sonnenschutz Steuerung: In Abklärung; Sonnenschutz Antrieb: In Abklärung; Sonnenschutz Farbe: RAL / NCS
00_Datenstruktur - BIM Base Version: 4.0.0; Kundenergänzungen Version: v01; CAD Werkzeug Typ: Fenster; Klassifizierung: Aussenfenster + Zargen aussen + Fensterbank + Sonnenschutz; Klassifizierung Level 0: Fenster; Modellierungsrichtlinien: https://evolutbaugmbh.sharepoint.com/:b:/s/External/EciBgBMJMZlDgYCafV5wNokBvCJq9PUJAyVGz7O3vsjVrg?e=aLjLN9; Übersicht BIM Base: https://evolutbaugmbh.sharepoint.com/:b:/s/External/EfS4mJ9nZQpOhASXp0n2kW4B0K7N-vHKx-_6Crp5CxEFeg?e=Qu0M5d; Verbesserungsvorschläge BIM Base: https://forms.office.com/e/pcFhFfi5DW; Anleitung Mengen: https://evolutbaugmbh.sharepoint.com/:b:/s/External/ETgyOLO3JxJEqg9rbaRMLVEBHuWIRtkoMiJN1fISDr-3lw?e=E0LTiQ; Anleitung Eigenschaften: https://evolutbaugmbh.sharepoint.com/:b:/s/External/EQedjNXQkc1Btaftc01yAPUBtND9QzXFSH3-7sie6PGFww?e=wP4uf3; Release Notes: https://evolutbaugmbh.sharepoint.com/:b:/s/External/Eb41lwlDI71MhUVvor2V2mUBSaI-0tQK5U9oJAWxpCINuw?e=NtK3j6
Name | In | OverallHeight (mm) | OverallWidth (mm) | Wand Typ | Breite Lichtmass - m | Höhe Lichtmass - m | Fläche Lichtmass - m2 | Höhe Mauerlicht - m | Breite Mauerlicht - m | Fläche Mauerlicht - m2 | Delta Höhe unten - m | Delta Hohe oben - m | Wandstärke - m | Kote Brüstung fertig - m | Kote Brüstung roh - m | Kote Sturz fertig - m | Kote Sturz roh - m
11 x Fenster-004 | EG | 2141 | 1842 | Aussenwand Typ 01 | 1.6 | 1.96 | 3.136 | 2.141 | 1.842 | 3.94372 | 0.06 | 0.121 | 0.318 | 0.56 | 0.5 | 2.52 | 2.641
15 x Fenster-004 | EG | 2122 | 1804 | Aussenwand Typ 05 | 1.6 | 1.96 | 3.136 | 2.122 | 1.804 | 3.82809 | 0.0684 | 0.0936 | 0.3 | 0.31 | 0.2416 | 2.27 | 2.3636
 | EG | 2141 | 1842 | Aussenwand Typ 01 | 1.6 | 1.96 | 3.136 | 2.141 | 1.842 | 3.94372 | 0.06 | 0.121 | 0.318 | 0.56 | 0.5 | 2.52 | 2.641
9 x Fenster-004 | 1.OG | 1781 | 1842 | Aussenwand Typ 01 | 1.6 | 1.6 | 2.56 | 1.781 | 1.842 | 3.2806 | 0.06 | 0.121 | 0.318 | 4.14 | 4.08 | 5.74 | 5.861
10 x Fenster-004 | 1.OG | 2122 | 1804 | Aussenwand Typ 06 | 1.6 | 1.96 | 3.136 | 2.122 | 1.804 | 3.82809 | 0.0684 | 0.0936 | 0.31 | 3.21 | 3.1416 | 5.17 | 5.2636
4 x Fenster-004 | 1.OG | 2372 | 1804 | Aussenwand Typ 06 | 1.6 | 2.13 | 3.408 | 2.372 | 1.804 | 4.27909 | 0.14 | 0.102 | 0.31 | 3.04 | 2.9 | 5.17 | 5.272
2 x Fenster-004 | 1.OG | 1781 | 1842 | Aussenwand Typ 01 | 1.6 | 1.6 | 2.56 | 1.781 | 1.842 | 3.2806 | 0.0776 | 0.1034 | 0.318 | 4.14 | 4.0624 | 5.74 | 5.8434
 | 1.OG | 1781 | 1892 | Aussenwand Typ 01 | 1.65 | 1.6 | 2.64 | 1.781 | 1.892 | 3.36965 | 0.0776 | 0.1034 | 0.318 | 4.14 | 4.0624 | 5.74 | 5.8434
2 x Fenster-004 | 1.OG | 2461 | 2532 | Aussenwand Typ 01 | 2.29 | 2.2 | 5.038 | 2.461 | 2.532 | 6.23125 | 0.14 | 0.121 | 0.318 | 3.54 | 3.4 | 5.74 | 5.861
9 x Fenster-004 | 2.OG | 1781 | 1842 | Aussenwand Typ 01 | 1.6 | 1.6 | 2.56 | 1.781 | 1.842 | 3.2806 | 0.06 | 0.121 | 0.318 | 7.04 | 6.98 | 8.64 | 8.761
10 x Fenster-004 | 2.OG | 2122 | 1804 | Aussenwand Typ 06 | 1.6 | 1.96 | 3.136 | 2.122 | 1.804 | 3.82809 | 0.0684 | 0.0936 | 0.31 | 6.11 | 6.0416 | 8.07 | 8.1636
3 x Fenster-004 | 2.OG | 1781 | 1842 | Aussenwand Typ 01 | 1.6 | 1.6 | 2.56 | 1.781 | 1.842 | 3.2806 | 0.0776 | 0.1034 | 0.318 | 7.04 | 6.9624 | 8.64 | 8.7434
4 x Fenster-004 | 2.OG | 2372 | 1804 | Aussenwand Typ 06 | 1.6 | 2.13 | 3.408 | 2.372 | 1.804 | 4.27909 | 0.14 | 0.102 | 0.31 | 5.94 | 5.8 | 8.07 | 8.172
9 x Fenster-004 | Attika | 1781 | 1842 | Aussenwand Typ 01 | 1.6 | 1.6 | 2.56 | 1.781 | 1.842 | 3.2806 | 0.06 | 0.121 | 0.318 | 9.94 | 9.88 | 11.54 | 11.661
9 x Fenster-004 | Attika | 2122 | 1804 | Aussenwand Typ 06 | 1.6 | 1.96 | 3.136 | 2.122 | 1.804 | 3.82809 | 0.0684 | 0.0936 | 0.31 | 9.01 | 8.9416 | 10.97 | 11.0636
3 x Fenster-004 | Attika | 2372 | 1804 | Aussenwand Typ 06 | 1.6 | 2.13 | 3.408 | 2.372 | 1.804 | 4.27909 | 0.14 | 0.102 | 0.31 | 8.84 | 8.7 | 10.97 | 11.072
 | Attika | 1781 | 1842 | Aussenwand Typ 01 | 1.6 | 1.6 | 2.56 | 1.781 | 1.842 | 3.2806 | 0.0776 | 0.1034 | 0.318 | 9.94 | 9.8624 | 11.54 | 11.6434
2 x Fenster-004 | Attika | 1781 | 1842 | Aussenwand Typ 01 | 1.6 | 1.6 | 2.56 | 1.781 | 1.842 | 3.2806 | 0.0776 | 0.1034 | 0.318 | 9.94 | 9.8624 | 11.54 | 11.6434

# IfcWindow: Fenster Typ 01 - 2flg FT (4)
Type - ElementType: Fenster Typ 01 - 2flg FT; PartitioningType: DOUBLE_PANEL_VERTICAL
OverallHeight: 2461 mm; OverallWidth: 2532 mm; Classification: Aussenfenster + Zargen aussen + Fensterbank + Sonnenschutz (BIM Base by Evolut)
05_Bauablauf - Bau-Nr.: In Abklärung; Bauablauf Etappe: In Abklärung; Bauablauf Verbauungsort: In Abklärung; Bauablauf Start Ausführung: In Abklärung; Bauablauf Ende Ausführung: In Abklärung
Fenster - Fenster Art: In Abklärung; Fenster Einsatzsitation: In Abklärung; Fenster g-Wert - %: In Abklärung; Fenster Ug-Wert Glas - W/m2K: In Abklärung; Fenster Schallschutzglas R'w+Ctr - dB: In Abklärung; Fenster Sicherheitsglas Personenschutz: In Abklärung; Fenster Sicherheitsglas Absturzhemmung: In Abklärung; Fenster Ornamentglas: In Abklärung; Fenster Insektenschutzgitter: In Abklärung; Fenster Einbruchschutz: In Abklärung; Fenster Öffnungsbegrenzung: In Abklärung; Fenster Öffnungsüberwachung: In Abklärung; Fenster Sitzfenster: In Abklärung; Fenster Schwelle barrierefrei: In Abklärung; Fenster Zuziehgriff + Schnäpper: In Abklärung; Fenster Zuziehgriff Farbe: In Abklärung; Fenster Griffmontage: In Abklärung; Fenster Grifftyp: In Abklärung; Fenster Griffoberfläche: In Abklärung; Fenster Beschlag: In Abklärung; Fenster Farbe Flügel innen: RAL / NCS; Fenster Farbe Flügel aussen: RAL / NCS; Fenster Farbe Rahmen innen: RAL / NCS; Fenster Farbe Rahmen aussen: RAL / NCS; Fenster Farbe Wetterschenkel: RAL / NCS; Fenster Detailbezeichnung links: In Abklärung; Fenster Detailbezeichnung rechts: In Abklärung; Fenster Detailbezeichnung oben: In Abklärung; Fenster Detailbezeichnung unten: In Abklärung; Fenster Detailbezeichnung Mittelpartie: In Abklärung; Fenster Typ: In Abklärung
Metallzarge - Metallzargen Verbindungsart: In Abklärung; Metallzargen Oberflächenbehandlung: In Abklärung; Metallzargen Farbe: In Abklärung; Metallzargen Sturzart: In Abklärung; Metallzargen Storenkasten Breite - mm: In Abklärung; Metallzargen Storenkasten Höhe - mm: In Abklärung; Metallzargen Laibungen: In Abklärung; Metallzargen Tiefe - mm: In Abklärung; Metallzargen Spiegelbreite - mm: In Abklärung; Metallzargen Fensterbank: In Abklärung; Metallzargen Fensterbankneigung - in Grad: In Abklärung
Fensterbank - Fensterbank Material: In Abklärung; Fensterbank Oberflächenbehandlung: In Abklärung; Fensterbank Farbe: RAL / NCS
03_Bausystem - Feuerwiderstand: In Abklärung; Umbau-Status: Neubau; Wand Typ: Aussenwand Typ 01
02_Mengen - Breite Lichtmass - m: 2.29; Höhe Mauerlicht - m: 2.461; Breite Mauerlicht - m: 2.532; Fläche Mauerlicht - m2: 6.23125; Delta Hohe oben - m: 0.121; Wandstärke - m: 0.318
01_Leistungen und Kosten - Gebäude: In Abklärung; Elementpreis - CHF: 0; BKP: 221 - Fenster, Aussentüren, Tore; eBKP-H_Nr: E03.01; eBKP-H_Beschrieb: Fenster
00_Datenstruktur - BIM Base Version: 4.0.0; Kundenergänzungen Version: v01; CAD Werkzeug Typ: Fenster; Klassifizierung: Aussenfenster + Zargen aussen + Fensterbank + Sonnenschutz; Klassifizierung Level 0: Fenster; Modellierungsrichtlinien: https://evolutbaugmbh.sharepoint.com/:b:/s/External/EciBgBMJMZlDgYCafV5wNokBvCJq9PUJAyVGz7O3vsjVrg?e=aLjLN9; Übersicht BIM Base: https://evolutbaugmbh.sharepoint.com/:b:/s/External/EfS4mJ9nZQpOhASXp0n2kW4B0K7N-vHKx-_6Crp5CxEFeg?e=Qu0M5d; Verbesserungsvorschläge BIM Base: https://forms.office.com/e/pcFhFfi5DW; Anleitung Mengen: https://evolutbaugmbh.sharepoint.com/:b:/s/External/ETgyOLO3JxJEqg9rbaRMLVEBHuWIRtkoMiJN1fISDr-3lw?e=E0LTiQ; Anleitung Eigenschaften: https://evolutbaugmbh.sharepoint.com/:b:/s/External/EQedjNXQkc1Btaftc01yAPUBtND9QzXFSH3-7sie6PGFww?e=wP4uf3; Release Notes: https://evolutbaugmbh.sharepoint.com/:b:/s/External/Eb41lwlDI71MhUVvor2V2mUBSaI-0tQK5U9oJAWxpCINuw?e=NtK3j6
Sonnenschutz - Sonnenschutz Typ: In Abklärung; Sonnenschutz Steuerung: In Abklärung; Sonnenschutz Antrieb: In Abklärung; Sonnenschutz Farbe: RAL / NCS
Name | In | Höhe Lichtmass - m | Fläche Lichtmass - m2 | Delta Höhe unten - m | Kote Brüstung fertig - m | Kote Brüstung roh - m | Kote Sturz fertig - m | Kote Sturz roh - m
2 x Fenster-004 | 2.OG | 2.2 | 5.038 | 0.14 | 6.44 | 6.3 | 8.64 | 8.761
Fenster-004 | Attika | 2.18 | 4.9922 | 0.16 | 9.36 | 9.2 | 11.54 | 11.661
Fenster-004 | Attika | 2.2 | 5.038 | 0.14 | 9.34 | 9.2 | 11.54 | 11.661

# IfcWindow: Klapp-Schwing-Fenster 27, Esstisch-4-001
In: Dachaufsicht
Classification: Dachfenster Flachdach (BIM Base by Evolut)
05_Bauablauf - Bau-Nr.: In Abklärung; Bauablauf Etappe: In Abklärung; Bauablauf Verbauungsort: In Abklärung; Bauablauf Start Ausführung: In Abklärung; Bauablauf Ende Ausführung: In Abklärung
01_Leistungen und Kosten - Gebäude: In Abklärung; Elementpreis - CHF: 0; BKP: 224 - Bedachungsarbeiten; eBKP-H_Nr: F02.01; eBKP-H_Beschrieb: Element zu Flachdach
03_Bausystem - Feuerwiderstand: In Abklärung; Umbau-Status: Neubau
Fenster - Fenster Einsatzsitation: In Abklärung; Fenster g-Wert - %: In Abklärung; Fenster Ug-Wert Glas - W/m2K: In Abklärung; Fenster Schallschutzglas R'w+Ctr - dB: In Abklärung; Fenster Öffnungsüberwachung: In Abklärung; Fenster Farbe Flügel innen: RAL / NCS; Fenster Farbe Flügel aussen: RAL / NCS; Fenster Farbe Rahmen innen: RAL / NCS; Fenster Farbe Rahmen aussen: RAL / NCS; Fenster Detailbezeichnung links: In Abklärung; Fenster Detailbezeichnung rechts: In Abklärung; Fenster Detailbezeichnung oben: In Abklärung; Fenster Detailbezeichnung unten: In Abklärung; Fenster Detailbezeichnung Mittelpartie: In Abklärung; Fenster Typ: In Abklärung
02_Mengen - Breite - m: 1.6; Höhe - m: 1; Fläche brutto - m2: 1.44; Kote Unterkante: 11.35; Kote Oberkante: 12.35
00_Datenstruktur - BIM Base Version: 4.0.0; Kundenergänzungen Version: v01; CAD Werkzeug Typ: Objekt; Klassifizierung: Dachfenster Flachdach; Klassifizierung Level 0: Fenster; Modellierungsrichtlinien: https://evolutbaugmbh.sharepoint.com/:b:/s/External/EciBgBMJMZlDgYCafV5wNokBvCJq9PUJAyVGz7O3vsjVrg?e=aLjLN9; Übersicht BIM Base: https://evolutbaugmbh.sharepoint.com/:b:/s/External/EfS4mJ9nZQpOhASXp0n2kW4B0K7N-vHKx-_6Crp5CxEFeg?e=Qu0M5d; Verbesserungsvorschläge BIM Base: https://forms.office.com/e/pcFhFfi5DW; Anleitung Mengen: https://evolutbaugmbh.sharepoint.com/:b:/s/External/ETgyOLO3JxJEqg9rbaRMLVEBHuWIRtkoMiJN1fISDr-3lw?e=E0LTiQ; Anleitung Eigenschaften: https://evolutbaugmbh.sharepoint.com/:b:/s/External/EQedjNXQkc1Btaftc01yAPUBtND9QzXFSH3-7sie6PGFww?e=wP4uf3; Release Notes: https://evolutbaugmbh.sharepoint.com/:b:/s/External/Eb41lwlDI71MhUVvor2V2mUBSaI-0tQK5U9oJAWxpCINuw?e=NtK3j6

# IfcWindow: Sonderfenster 01 (2)
In: Dachaufsicht
Type - ElementType: Sonderfenster 01; PartitioningType: SINGLE_PANEL
OverallHeight: 3140 mm; OverallWidth: 2200 mm; Classification: Aussenfenster + Zargen aussen + Fensterbank + Sonnenschutz (BIM Base by Evolut)
01_Leistungen und Kosten - Gebäude: In Abklärung; Elementpreis - CHF: 0; BKP: 221 - Fenster, Aussentüren, Tore; eBKP-H_Nr: E03.01; eBKP-H_Beschrieb: Fenster
05_Bauablauf - Bau-Nr.: In Abklärung; Bauablauf Etappe: In Abklärung; Bauablauf Verbauungsort: In Abklärung; Bauablauf Start Ausführung: In Abklärung; Bauablauf Ende Ausführung: In Abklärung
03_Bausystem - Feuerwiderstand: In Abklärung; Umbau-Status: Neubau; Wand Typ: Aussenwand Typ 01
Metallzarge - Metallzargen Verbindungsart: In Abklärung; Metallzargen Oberflächenbehandlung: In Abklärung; Metallzargen Farbe: In Abklärung; Metallzargen Sturzart: In Abklärung; Metallzargen Storenkasten Breite - mm: In Abklärung; Metallzargen Storenkasten Höhe - mm: In Abklärung; Metallzargen Laibungen: In Abklärung; Metallzargen Tiefe - mm: In Abklärung; Metallzargen Spiegelbreite - mm: In Abklärung; Metallzargen Fensterbank: In Abklärung; Metallzargen Fensterbankneigung - in Grad: In Abklärung
Fenster - Fenster Art: In Abklärung; Fenster Einsatzsitation: In Abklärung; Fenster g-Wert - %: In Abklärung; Fenster Ug-Wert Glas - W/m2K: In Abklärung; Fenster Schallschutzglas R'w+Ctr - dB: In Abklärung; Fenster Sicherheitsglas Personenschutz: In Abklärung; Fenster Sicherheitsglas Absturzhemmung: In Abklärung; Fenster Ornamentglas: In Abklärung; Fenster Insektenschutzgitter: In Abklärung; Fenster Einbruchschutz: In Abklärung; Fenster Öffnungsbegrenzung: In Abklärung; Fenster Öffnungsüberwachung: In Abklärung; Fenster Sitzfenster: In Abklärung; Fenster Schwelle barrierefrei: In Abklärung; Fenster Zuziehgriff + Schnäpper: In Abklärung; Fenster Zuziehgriff Farbe: In Abklärung; Fenster Griffmontage: In Abklärung; Fenster Grifftyp: In Abklärung; Fenster Griffoberfläche: In Abklärung; Fenster Beschlag: In Abklärung; Fenster Farbe Flügel innen: RAL / NCS; Fenster Farbe Flügel aussen: RAL / NCS; Fenster Farbe Rahmen innen: RAL / NCS; Fenster Farbe Rahmen aussen: RAL / NCS; Fenster Farbe Wetterschenkel: RAL / NCS; Fenster Detailbezeichnung links: In Abklärung; Fenster Detailbezeichnung rechts: In Abklärung; Fenster Detailbezeichnung oben: In Abklärung; Fenster Detailbezeichnung unten: In Abklärung; Fenster Detailbezeichnung Mittelpartie: In Abklärung; Fenster Typ: In Abklärung
Sonnenschutz - Sonnenschutz Typ: In Abklärung; Sonnenschutz Steuerung: In Abklärung; Sonnenschutz Antrieb: In Abklärung; Sonnenschutz Farbe: RAL / NCS
02_Mengen - Breite Lichtmass - m: 2; Höhe Lichtmass - m: 2.9; Fläche Lichtmass - m2: 5.8; Höhe Mauerlicht - m: 3.14; Breite Mauerlicht - m: 2.2; Fläche Mauerlicht - m2: 6.908; Delta Höhe unten - m: 0.14; Delta Hohe oben - m: 0.1; Wandstärke - m: 0.318; Kote Brüstung fertig - m: 12.64; Kote Brüstung roh - m: 12.5; Kote Sturz fertig - m: 15.54; Kote Sturz roh - m: 15.64
00_Datenstruktur - BIM Base Version: 4.0.0; Kundenergänzungen Version: v01; CAD Werkzeug Typ: Fenster; Klassifizierung: Aussenfenster + Zargen aussen + Fensterbank + Sonnenschutz; Klassifizierung Level 0: Fenster; Modellierungsrichtlinien: https://evolutbaugmbh.sharepoint.com/:b:/s/External/EciBgBMJMZlDgYCafV5wNokBvCJq9PUJAyVGz7O3vsjVrg?e=aLjLN9; Übersicht BIM Base: https://evolutbaugmbh.sharepoint.com/:b:/s/External/EfS4mJ9nZQpOhASXp0n2kW4B0K7N-vHKx-_6Crp5CxEFeg?e=Qu0M5d; Verbesserungsvorschläge BIM Base: https://forms.office.com/e/pcFhFfi5DW; Anleitung Mengen: https://evolutbaugmbh.sharepoint.com/:b:/s/External/ETgyOLO3JxJEqg9rbaRMLVEBHuWIRtkoMiJN1fISDr-3lw?e=E0LTiQ; Anleitung Eigenschaften: https://evolutbaugmbh.sharepoint.com/:b:/s/External/EQedjNXQkc1Btaftc01yAPUBtND9QzXFSH3-7sie6PGFww?e=wP4uf3; Release Notes: https://evolutbaugmbh.sharepoint.com/:b:/s/External/Eb41lwlDI71MhUVvor2V2mUBSaI-0tQK5U9oJAWxpCINuw?e=NtK3j6
Fensterbank - Fensterbank Material: In Abklärung; Fensterbank Oberflächenbehandlung: In Abklärung; Fensterbank Farbe: RAL / NCS

# IfcWindow: Sonderfenster 02 (2)
In: Dachaufsicht
Type - ElementType: Sonderfenster 02; PartitioningType: SINGLE_PANEL
OverallHeight: 2240 mm; OverallWidth: 3150 mm; Classification: Aussenfenster + Zargen aussen + Fensterbank + Sonnenschutz (BIM Base by Evolut)
01_Leistungen und Kosten - Gebäude: In Abklärung; Elementpreis - CHF: 0; BKP: 221 - Fenster, Aussentüren, Tore; eBKP-H_Nr: E03.01; eBKP-H_Beschrieb: Fenster
05_Bauablauf - Bau-Nr.: In Abklärung; Bauablauf Etappe: In Abklärung; Bauablauf Verbauungsort: In Abklärung; Bauablauf Start Ausführung: In Abklärung; Bauablauf Ende Ausführung: In Abklärung
Fenster - Fenster Art: In Abklärung; Fenster Einsatzsitation: In Abklärung; Fenster g-Wert - %: In Abklärung; Fenster Ug-Wert Glas - W/m2K: In Abklärung; Fenster Schallschutzglas R'w+Ctr - dB: In Abklärung; Fenster Sicherheitsglas Personenschutz: In Abklärung; Fenster Sicherheitsglas Absturzhemmung: In Abklärung; Fenster Ornamentglas: In Abklärung; Fenster Insektenschutzgitter: In Abklärung; Fenster Einbruchschutz: In Abklärung; Fenster Öffnungsbegrenzung: In Abklärung; Fenster Öffnungsüberwachung: In Abklärung; Fenster Sitzfenster: In Abklärung; Fenster Schwelle barrierefrei: In Abklärung; Fenster Zuziehgriff + Schnäpper: In Abklärung; Fenster Zuziehgriff Farbe: In Abklärung; Fenster Griffmontage: In Abklärung; Fenster Grifftyp: In Abklärung; Fenster Griffoberfläche: In Abklärung; Fenster Beschlag: In Abklärung; Fenster Farbe Flügel innen: RAL / NCS; Fenster Farbe Flügel aussen: RAL / NCS; Fenster Farbe Rahmen innen: RAL / NCS; Fenster Farbe Rahmen aussen: RAL / NCS; Fenster Farbe Wetterschenkel: RAL / NCS; Fenster Detailbezeichnung links: In Abklärung; Fenster Detailbezeichnung rechts: In Abklärung; Fenster Detailbezeichnung oben: In Abklärung; Fenster Detailbezeichnung unten: In Abklärung; Fenster Detailbezeichnung Mittelpartie: In Abklärung; Fenster Typ: In Abklärung
Metallzarge - Metallzargen Verbindungsart: In Abklärung; Metallzargen Oberflächenbehandlung: In Abklärung; Metallzargen Farbe: In Abklärung; Metallzargen Sturzart: In Abklärung; Metallzargen Storenkasten Breite - mm: In Abklärung; Metallzargen Storenkasten Höhe - mm: In Abklärung; Metallzargen Laibungen: In Abklärung; Metallzargen Tiefe - mm: In Abklärung; Metallzargen Spiegelbreite - mm: In Abklärung; Metallzargen Fensterbank: In Abklärung; Metallzargen Fensterbankneigung - in Grad: In Abklärung
Fensterbank - Fensterbank Material: In Abklärung; Fensterbank Oberflächenbehandlung: In Abklärung; Fensterbank Farbe: RAL / NCS
Sonnenschutz - Sonnenschutz Typ: In Abklärung; Sonnenschutz Steuerung: In Abklärung; Sonnenschutz Antrieb: In Abklärung; Sonnenschutz Farbe: RAL / NCS
00_Datenstruktur - BIM Base Version: 4.0.0; Kundenergänzungen Version: v01; CAD Werkzeug Typ: Fenster; Klassifizierung: Aussenfenster + Zargen aussen + Fensterbank + Sonnenschutz; Klassifizierung Level 0: Fenster; Modellierungsrichtlinien: https://evolutbaugmbh.sharepoint.com/:b:/s/External/EciBgBMJMZlDgYCafV5wNokBvCJq9PUJAyVGz7O3vsjVrg?e=aLjLN9; Übersicht BIM Base: https://evolutbaugmbh.sharepoint.com/:b:/s/External/EfS4mJ9nZQpOhASXp0n2kW4B0K7N-vHKx-_6Crp5CxEFeg?e=Qu0M5d; Verbesserungsvorschläge BIM Base: https://forms.office.com/e/pcFhFfi5DW; Anleitung Mengen: https://evolutbaugmbh.sharepoint.com/:b:/s/External/ETgyOLO3JxJEqg9rbaRMLVEBHuWIRtkoMiJN1fISDr-3lw?e=E0LTiQ; Anleitung Eigenschaften: https://evolutbaugmbh.sharepoint.com/:b:/s/External/EQedjNXQkc1Btaftc01yAPUBtND9QzXFSH3-7sie6PGFww?e=wP4uf3; Release Notes: https://evolutbaugmbh.sharepoint.com/:b:/s/External/Eb41lwlDI71MhUVvor2V2mUBSaI-0tQK5U9oJAWxpCINuw?e=NtK3j6
02_Mengen - Breite Lichtmass - m: 2.95; Höhe Lichtmass - m: 2; Fläche Lichtmass - m2: 5.9; Höhe Mauerlicht - m: 2.24; Breite Mauerlicht - m: 3.15; Fläche Mauerlicht - m2: 7.056; Delta Höhe unten - m: 0.14; Delta Hohe oben - m: 0.1; Wandstärke - m: 0.318; Kote Brüstung fertig - m: 12.64; Kote Brüstung roh - m: 12.5; Kote Sturz fertig - m: 14.64; Kote Sturz roh - m: 14.74
03_Bausystem - Feuerwiderstand: In Abklärung; Umbau-Status: Neubau; Wand Typ: Aussenwand Typ 01

# Material: Magerbeton
Pset_MaterialThermal - ThermalConductivity: 0.3; SpecificHeatCapacity: 1000 J/kg/K
Pset_MaterialCommon - MassDensity: 1000 kg/m3
AC_Pset_MaterialCustom - Embodied Energy: 0.3 (MJ/kg); Embodied Carbon: 0.107 (kgCO₂/kg); Participates in Collision Detection: yes

# Material: Beton bewehrt
Pset_MaterialThermal - ThermalConductivity: 2.5; SpecificHeatCapacity: 1000 J/kg/K
Pset_MaterialCommon - MassDensity: 2400 kg/m3
AC_Pset_MaterialCustom - Embodied Energy: 2.33 (MJ/kg); Embodied Carbon: 0.242 (kgCO₂/kg); Participates in Collision Detection: yes

# Material: MW, Backstein, Sichtmauerwerk
Pset_MaterialThermal - ThermalConductivity: 0.52; SpecificHeatCapacity: 1000 J/kg/K
Pset_MaterialCommon - MassDensity: 1400 kg/m3
AC_Pset_MaterialCustom - Embodied Energy: 3 (MJ/kg); Embodied Carbon: 0.24 (kgCO₂/kg); Participates in Collision Detection: yes

# Material: Lattenrost vertikal
Pset_MaterialThermal - ThermalConductivity: 0.156; SpecificHeatCapacity: 1008 J/kg/K
Pset_MaterialCommon - MassDensity: 1.23 kg/m3
AC_Pset_MaterialCustom - Embodied Energy: 0 (MJ/kg); Embodied Carbon: 0 (kgCO₂/kg); Participates in Collision Detection: yes

# Material: Gipskartonplatte GKP
Pset_MaterialThermal - ThermalConductivity: 0.25; SpecificHeatCapacity: 1000 J/kg/K
Pset_MaterialCommon - MassDensity: 900 kg/m3
AC_Pset_MaterialCustom - Embodied Energy: 6.75 (MJ/kg); Embodied Carbon: 0.39 (kgCO₂/kg); Participates in Collision Detection: yes

# Material: Gefällsbeton
Pset_MaterialThermal - ThermalConductivity: 1.15; SpecificHeatCapacity: 1000 J/kg/K
Pset_MaterialCommon - MassDensity: 1800 kg/m3
AC_Pset_MaterialCustom - Embodied Energy: 0.74 (MJ/kg); Embodied Carbon: 0.107 (kgCO₂/kg); Participates in Collision Detection: yes

# Material: Anstrich Innen
Pset_MaterialThermal - ThermalConductivity: 0.86; SpecificHeatCapacity: 1000 J/kg/K
Pset_MaterialCommon - MassDensity: 1800 kg/m3
AC_Pset_MaterialCustom - Embodied Energy: 1.34 (MJ/kg); Embodied Carbon: 0.213 (kgCO₂/kg); Participates in Collision Detection: yes

# Material: Sichtbeton
Pset_MaterialThermal - ThermalConductivity: 2.5; SpecificHeatCapacity: 1000 J/kg/K
Pset_MaterialCommon - MassDensity: 2400 kg/m3
AC_Pset_MaterialCustom - Embodied Energy: 2.33 (MJ/kg); Embodied Carbon: 0.242 (kgCO₂/kg); Participates in Collision Detection: yes

# Material: Kalkzementputz Aussen
Pset_MaterialThermal - ThermalConductivity: 0.47; SpecificHeatCapacity: 1000 J/kg/K
Pset_MaterialCommon - MassDensity: 1400 kg/m3
AC_Pset_MaterialCustom - Embodied Energy: 1.6 (MJ/kg); Embodied Carbon: 0.11 (kgCO₂/kg); Participates in Collision Detection: yes

# Material: Vollholzwerkstoff
Pset_MaterialThermal - ThermalConductivity: 0.09; SpecificHeatCapacity: 1600 J/kg/K
AC_Pset_MaterialCustom - Embodied Energy: 11.9 (MJ/kg); Embodied Carbon: 0.52 (kgCO₂/kg); Participates in Collision Detection: yes
Pset_MaterialCommon - MassDensity: 300 kg/m3

# Material: Lattenrost horizontal
Pset_MaterialCommon - MassDensity: 1.23 kg/m3
Pset_MaterialThermal - ThermalConductivity: 0.139; SpecificHeatCapacity: 1008 J/kg/K
AC_Pset_MaterialCustom - Embodied Energy: 0 (MJ/kg); Embodied Carbon: 0 (kgCO₂/kg); Participates in Collision Detection: yes

# Material: Falzschalung vertikal
Pset_MaterialThermal - ThermalConductivity: 0.13; SpecificHeatCapacity: 1600 J/kg/K
Pset_MaterialCommon - MassDensity: 500 kg/m3
AC_Pset_MaterialCustom - Embodied Energy: 6.95 (MJ/kg); Embodied Carbon: 0.29 (kgCO₂/kg); Participates in Collision Detection: yes

# Material: Dämmung Aussen
Pset_MaterialThermal - ThermalConductivity: 0.031; SpecificHeatCapacity: 1450 J/kg/K
Pset_MaterialCommon - MassDensity: 15 kg/m3
AC_Pset_MaterialCustom - Embodied Energy: 76 (MJ/kg); Embodied Carbon: 3.18 (kgCO₂/kg); Participates in Collision Detection: yes

# Material: Zementputz Aussen
Pset_MaterialThermal - ThermalConductivity: 0.47; SpecificHeatCapacity: 1000 J/kg/K
Pset_MaterialCommon - MassDensity: 1400 kg/m3
AC_Pset_MaterialCustom - Embodied Energy: 1.6 (MJ/kg); Embodied Carbon: 0.11 (kgCO₂/kg); Participates in Collision Detection: yes

# Material: Verputz Innen
Pset_MaterialThermal - ThermalConductivity: 0.47; SpecificHeatCapacity: 1000 J/kg/K
Pset_MaterialCommon - MassDensity: 1400 kg/m3
AC_Pset_MaterialCustom - Embodied Energy: 1.6 (MJ/kg); Embodied Carbon: 0.11 (kgCO₂/kg); Participates in Collision Detection: yes

# Material: Gipsfaserplatte GFP
Pset_MaterialThermal - ThermalConductivity: 0.25; SpecificHeatCapacity: 1000 J/kg/K
Pset_MaterialCommon - MassDensity: 900 kg/m3
AC_Pset_MaterialCustom - Embodied Energy: 6.75 (MJ/kg); Embodied Carbon: 0.39 (kgCO₂/kg); Participates in Collision Detection: yes

# Material: Ständer Konstruktion gedämmt
Pset_MaterialThermal - ThermalConductivity: 0.037; SpecificHeatCapacity: 840 J/kg/K
Pset_MaterialCommon - MassDensity: 40 kg/m3
AC_Pset_MaterialCustom - Embodied Energy: 14.3 (MJ/kg); Embodied Carbon: 1.08 (kgCO₂/kg); Description: weich; Participates in Collision Detection: yes

# Material: Grobspanplatte-OSB
Pset_MaterialThermal - ThermalConductivity: 0.13; SpecificHeatCapacity: 1700 J/kg/K
Pset_MaterialCommon - MassDensity: 650 kg/m3
AC_Pset_MaterialCustom - Embodied Energy: 15 (MJ/kg); Embodied Carbon: 0.9 (kgCO₂/kg); Participates in Collision Detection: yes

# Material: Dämmung Innen
Pset_MaterialThermal - ThermalConductivity: 0.036; SpecificHeatCapacity: 840 J/kg/K
Pset_MaterialCommon - MassDensity: 115 kg/m3
AC_Pset_MaterialCustom - Embodied Energy: 21.4 (MJ/kg); Embodied Carbon: 1.69 (kgCO₂/kg); Participates in Collision Detection: yes

# Material: Brettschichtholz BSH
Pset_MaterialThermal - ThermalConductivity: 0.13; SpecificHeatCapacity: 1600 J/kg/K
Pset_MaterialCommon - MassDensity: 470 kg/m3
AC_Pset_MaterialCustom - Embodied Energy: 6.95 (MJ/kg); Embodied Carbon: 0.29 (kgCO₂/kg); Participates in Collision Detection: yes

# Material: Stahl
Pset_MaterialThermal - ThermalConductivity: 50; SpecificHeatCapacity: 800 J/kg/K
Pset_MaterialCommon - MassDensity: 7800 kg/m3
AC_Pset_MaterialCustom - Embodied Energy: 20.1 (MJ/kg); Embodied Carbon: 1.46 (kgCO₂/kg); Participates in Collision Detection: yes

# Material: Balken Konstruktion ungedämmt
Pset_MaterialThermal - ThermalConductivity: 0.18; SpecificHeatCapacity: 1008 J/kg/K
Pset_MaterialCommon - MassDensity: 1.2 kg/m3
AC_Pset_MaterialCustom - Embodied Energy: 0 (MJ/kg); Embodied Carbon: 0 (kgCO₂/kg); Participates in Collision Detection: no

# Material: Balken Konstruktion gedämmt
Pset_MaterialThermal - ThermalConductivity: 0.037; SpecificHeatCapacity: 840 J/kg/K
Pset_MaterialCommon - MassDensity: 40 kg/m3
AC_Pset_MaterialCustom - Embodied Energy: 14.3 (MJ/kg); Embodied Carbon: 1.08 (kgCO₂/kg); Description: weich; Participates in Collision Detection: yes

# Material: Massivholz
Pset_MaterialThermal - ThermalConductivity: 0.13; SpecificHeatCapacity: 1600 J/kg/K
Pset_MaterialCommon - MassDensity: 470 kg/m3
AC_Pset_MaterialCustom - Embodied Energy: 6.95 (MJ/kg); Embodied Carbon: 0.29 (kgCO₂/kg); Participates in Collision Detection: yes

# Material: Dreischichtplatte DSP
Pset_MaterialThermal - ThermalConductivity: 0.13; SpecificHeatCapacity: 1700 J/kg/K
Pset_MaterialCommon - MassDensity: 650 kg/m3
AC_Pset_MaterialCustom - Embodied Energy: 15 (MJ/kg); Embodied Carbon: 0.9 (kgCO₂/kg); Participates in Collision Detection: yes

# Material: Bodenbelag
Pset_MaterialThermal - ThermalConductivity: 0.17; SpecificHeatCapacity: 1400 J/kg/K
Pset_MaterialCommon - MassDensity: 1200 kg/m3
AC_Pset_MaterialCustom - Embodied Energy: 91 (MJ/kg); Embodied Carbon: 2.85 (kgCO₂/kg); Participates in Collision Detection: yes

# Material: Unterlagsboden
Pset_MaterialCommon - MassDensity: 2200 kg/m3
Pset_MaterialThermal - ThermalConductivity: 0.8; SpecificHeatCapacity: 800 J/kg/K
AC_Pset_MaterialCustom - Embodied Energy: 0.92 (MJ/kg); Embodied Carbon: 0.15 (kgCO₂/kg); Participates in Collision Detection: yes
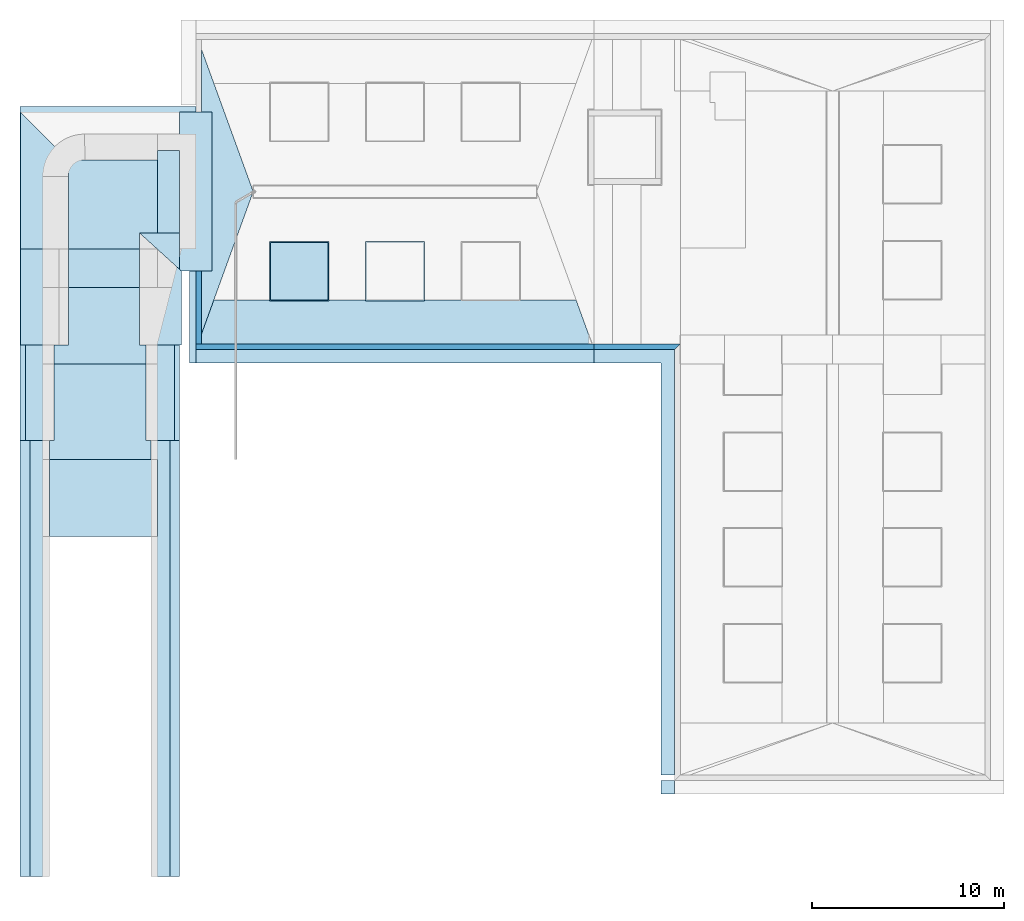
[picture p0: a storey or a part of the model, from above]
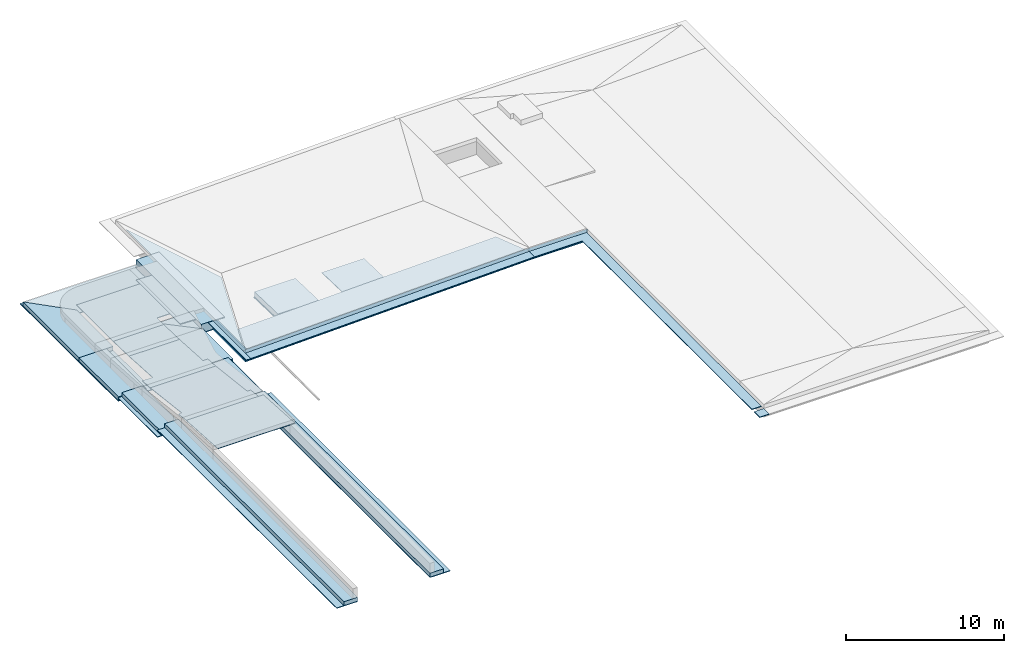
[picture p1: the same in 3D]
Properties of the parts of a building model (IFC4), part 8 of 8

# Material: Sperrschicht
Pset_MaterialCommon - MassDensity: 1100 kg/m3
Pset_MaterialThermal - ThermalConductivity: 0.23; SpecificHeatCapacity: 1000 J/kg/K
AC_Pset_MaterialCustom - Embodied Energy: 2.86 (MJ/kg); Embodied Carbon: 0.066 (kgCO₂/kg); Participates in Collision Detection: yes

# Material: Grünfläche
Pset_MaterialThermal - ThermalConductivity: 0.7; SpecificHeatCapacity: 1000 J/kg/K
Pset_MaterialCommon - MassDensity: 2100 kg/m3
AC_Pset_MaterialCustom - Embodied Energy: 3.93 (MJ/kg); Embodied Carbon: 0.076 (kgCO₂/kg); Participates in Collision Detection: yes

# Material: Keramik
Pset_MaterialThermal - ThermalConductivity: 1.3; SpecificHeatCapacity: 840 J/kg/K
Pset_MaterialCommon - MassDensity: 2300 kg/m3
AC_Pset_MaterialCustom - Embodied Energy: 14.99 (MJ/kg); Embodied Carbon: 0.76 (kgCO₂/kg); Participates in Collision Detection: yes

# Material: Bewehrung
Pset_MaterialThermal - ThermalConductivity: 1.4; SpecificHeatCapacity: 1000 J/kg/K
Pset_MaterialCommon - MassDensity: 2200 kg/m3
AC_Pset_MaterialCustom - Embodied Energy: 1.34 (MJ/kg); Embodied Carbon: 0.213 (kgCO₂/kg); Participates in Collision Detection: yes

# Material: Naturstein
Pset_MaterialCommon - MassDensity: 2000 kg/m3
Pset_MaterialThermal - ThermalConductivity: 1.4; SpecificHeatCapacity: 1000 J/kg/K
AC_Pset_MaterialCustom - Embodied Energy: 5.5 (MJ/kg); Embodied Carbon: 0.035 (kgCO₂/kg); Participates in Collision Detection: yes

# Material: MW, Backstein
Pset_MaterialThermal - ThermalConductivity: 0.44; SpecificHeatCapacity: 1000 J/kg/K
Pset_MaterialCommon - MassDensity: 1100 kg/m3
AC_Pset_MaterialCustom - Embodied Energy: 2.85 (MJ/kg); Embodied Carbon: 0.22 (kgCO₂/kg); Participates in Collision Detection: yes

# Material: Trittschalldämmung
Pset_MaterialThermal - ThermalConductivity: 0.035; SpecificHeatCapacity: 1030 J/kg/K
Pset_MaterialCommon - MassDensity: 80 kg/m3
AC_Pset_MaterialCustom - Embodied Energy: 37 (MJ/kg); Embodied Carbon: 1.48 (kgCO₂/kg); Participates in Collision Detection: yes

# Material: Chrom
Pset_MaterialThermal - ThermalConductivity: 160; SpecificHeatCapacity: 880 J/kg/K
Pset_MaterialCommon - MassDensity: 2800 kg/m3
AC_Pset_MaterialCustom - Embodied Energy: 155 (MJ/kg); Embodied Carbon: 9.16 (kgCO₂/kg); Participates in Collision Detection: yes

# Material: Glas
AC_Pset_MaterialCustom - Embodied Energy: 0.85 (MJ/kg); Embodied Carbon: 0.02 (kgCO₂/kg); Participates in Collision Detection: yes
Pset_MaterialCommon - MassDensity: 2500 kg/m3
Pset_MaterialThermal - ThermalConductivity: 1; SpecificHeatCapacity: 800 J/kg/K

# Material: Dachbegrünung extensiv
Pset_MaterialThermal - ThermalConductivity: 0.7; SpecificHeatCapacity: 1000 J/kg/K
AC_Pset_MaterialCustom - Embodied Energy: 3.93 (MJ/kg); Embodied Carbon: 0.076 (kgCO₂/kg); Participates in Collision Detection: yes
Pset_MaterialCommon - MassDensity: 2100 kg/m3

# Material: Abdichtung Bitumen
Pset_MaterialThermal - ThermalConductivity: 0.23; SpecificHeatCapacity: 1000 J/kg/K
AC_Pset_MaterialCustom - Embodied Energy: 2.86 (MJ/kg); Embodied Carbon: 0.066 (kgCO₂/kg); Participates in Collision Detection: yes
Pset_MaterialCommon - MassDensity: 1100 kg/m3

# Material: Aufdachdämmung
Pset_MaterialThermal - ThermalConductivity: 0.031; SpecificHeatCapacity: 1450 J/kg/K
Pset_MaterialCommon - MassDensity: 15 kg/m3
AC_Pset_MaterialCustom - Embodied Energy: 76 (MJ/kg); Embodied Carbon: 3.18 (kgCO₂/kg); Participates in Collision Detection: yes

# Material: Gefällsdämmung
Pset_MaterialThermal - ThermalConductivity: 0.031; SpecificHeatCapacity: 1450 J/kg/K
AC_Pset_MaterialCustom - Embodied Energy: 76 (MJ/kg); Embodied Carbon: 3.18 (kgCO₂/kg); Participates in Collision Detection: yes
Pset_MaterialCommon - MassDensity: 15 kg/m3

# Material: Dampf- / Luftdichtigkeitsschicht
Pset_MaterialThermal - ThermalConductivity: 0.23; SpecificHeatCapacity: 1000 J/kg/K
Pset_MaterialCommon - MassDensity: 1100 kg/m3
AC_Pset_MaterialCustom - Embodied Energy: 2.86 (MJ/kg); Embodied Carbon: 0.066 (kgCO₂/kg); Participates in Collision Detection: yes

# Material: Falzschalung horizontal
Pset_MaterialThermal - ThermalConductivity: 0.13; SpecificHeatCapacity: 1600 J/kg/K
Pset_MaterialCommon - MassDensity: 500 kg/m3
AC_Pset_MaterialCustom - Embodied Energy: 6.95 (MJ/kg); Embodied Carbon: 0.29 (kgCO₂/kg); Participates in Collision Detection: yes

# Material: Dämmung-Innen
Pset_MaterialThermal - ThermalConductivity: 0.036; SpecificHeatCapacity: 840 J/kg/K
Pset_MaterialCommon - MassDensity: 115 kg/m3
AC_Pset_MaterialCustom - Embodied Energy: 21.4 (MJ/kg); Embodied Carbon: 1.69 (kgCO₂/kg); Participates in Collision Detection: yes

# Material: Dachziegel grau
Pset_MaterialThermal - ThermalConductivity: 1.3; SpecificHeatCapacity: 840 J/kg/K
AC_Pset_MaterialCustom - Embodied Energy: 10 (MJ/kg); Embodied Carbon: 0.7 (kgCO₂/kg); Participates in Collision Detection: yes
Pset_MaterialCommon - MassDensity: 2300 kg/m3

# Material: Dreischichtplatte-DSP
Pset_MaterialThermal - ThermalConductivity: 0.13; SpecificHeatCapacity: 1700 J/kg/K
Pset_MaterialCommon - MassDensity: 650 kg/m3
AC_Pset_MaterialCustom - Embodied Energy: 15 (MJ/kg); Embodied Carbon: 0.9 (kgCO₂/kg); Participates in Collision Detection: yes
